VERSION 5.8 ;
BUSBITCHARS "[]" ;
DIVIDERCHAR "/" ;
UNITS
    DATABASE MICRONS 1000 ;
END UNITS

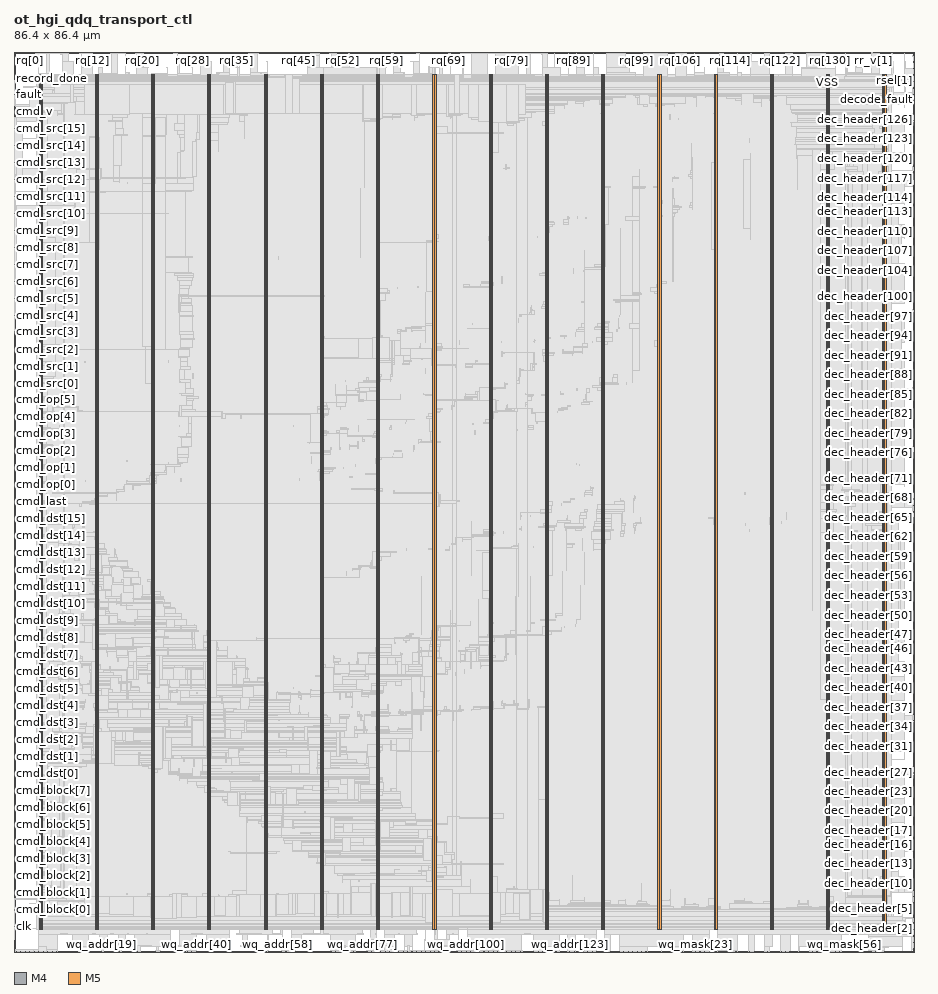
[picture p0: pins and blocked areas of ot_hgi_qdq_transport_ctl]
MACRO ot_hgi_qdq_transport_ctl
  FOREIGN ot_hgi_qdq_transport_ctl 0 0 ;
  CLASS BLOCK ;
  SIZE 86.4 BY 86.4 ;
  PIN beat_done
    DIRECTION OUTPUT ;
    USE SIGNAL ;
    PORT
      LAYER M4 ;
        RECT  0 0.816 0.084 0.84 ;
    END
    PORT
      LAYER M4 ;
        RECT  0.06 0.816 0.137 1.128 ;
    END
  END beat_done
  PIN clk
    DIRECTION INPUT ;
    USE SIGNAL ;
    PORT
      LAYER M4 ;
        RECT  0 2.448 0.084 2.472 ;
    END
    PORT
      LAYER M4 ;
        RECT  0.06 2.448 0.227 2.472 ;
    END
  END clk
  PIN cmd_block[0]
    DIRECTION INPUT ;
    USE SIGNAL ;
    PORT
      LAYER M4 ;
        RECT  0 4.08 0.084 4.104 ;
    END
    PORT
      LAYER M4 ;
        RECT  0.06 4.08 0.061 4.104 ;
    END
    PORT
      LAYER M4 ;
        RECT  0.061 3.984 0.173 4.104 ;
    END
  END cmd_block[0]
  PIN cmd_block[1]
    DIRECTION INPUT ;
    USE SIGNAL ;
    PORT
      LAYER M4 ;
        RECT  0 5.712 0.084 5.736 ;
    END
    PORT
      LAYER M4 ;
        RECT  0.06 5.712 2.408 5.736 ;
    END
  END cmd_block[1]
  PIN cmd_block[2]
    DIRECTION INPUT ;
    USE SIGNAL ;
    PORT
      LAYER M4 ;
        RECT  0 7.344 0.084 7.368 ;
    END
    PORT
      LAYER M4 ;
        RECT  0.06 7.344 2.408 7.368 ;
    END
  END cmd_block[2]
  PIN cmd_block[3]
    DIRECTION INPUT ;
    USE SIGNAL ;
    PORT
      LAYER M4 ;
        RECT  0 8.976 0.084 9 ;
    END
    PORT
      LAYER M4 ;
        RECT  0.06 8.976 2.408 9 ;
    END
  END cmd_block[3]
  PIN cmd_block[4]
    DIRECTION INPUT ;
    USE SIGNAL ;
    PORT
      LAYER M4 ;
        RECT  0 10.608 0.084 10.632 ;
    END
    PORT
      LAYER M4 ;
        RECT  0.06 10.608 2.408 10.632 ;
    END
  END cmd_block[4]
  PIN cmd_block[5]
    DIRECTION INPUT ;
    USE SIGNAL ;
    PORT
      LAYER M4 ;
        RECT  0 12.192 0.084 12.216 ;
    END
    PORT
      LAYER M4 ;
        RECT  0.06 12.192 2.408 12.216 ;
    END
  END cmd_block[5]
  PIN cmd_block[6]
    DIRECTION INPUT ;
    USE SIGNAL ;
    PORT
      LAYER M4 ;
        RECT  0 13.824 0.084 13.848 ;
    END
    PORT
      LAYER M4 ;
        RECT  0.06 13.824 2.408 13.848 ;
    END
  END cmd_block[6]
  PIN cmd_block[7]
    DIRECTION INPUT ;
    USE SIGNAL ;
    PORT
      LAYER M4 ;
        RECT  0 15.456 0.084 15.48 ;
    END
    PORT
      LAYER M4 ;
        RECT  0.06 15.456 2.408 15.48 ;
    END
  END cmd_block[7]
  PIN cmd_dst[0]
    DIRECTION INPUT ;
    USE SIGNAL ;
    PORT
      LAYER M4 ;
        RECT  0 17.088 0.084 17.112 ;
    END
    PORT
      LAYER M4 ;
        RECT  0.06 17.088 0.137 17.112 ;
    END
  END cmd_dst[0]
  PIN cmd_dst[10]
    DIRECTION INPUT ;
    USE SIGNAL ;
    PORT
      LAYER M4 ;
        RECT  0 33.408 0.084 33.432 ;
    END
    PORT
      LAYER M4 ;
        RECT  0.06 33.408 2.408 33.432 ;
    END
  END cmd_dst[10]
  PIN cmd_dst[11]
    DIRECTION INPUT ;
    USE SIGNAL ;
    PORT
      LAYER M4 ;
        RECT  0 35.04 0.084 35.064 ;
    END
    PORT
      LAYER M4 ;
        RECT  0.06 35.04 2.408 35.064 ;
    END
  END cmd_dst[11]
  PIN cmd_dst[12]
    DIRECTION INPUT ;
    USE SIGNAL ;
    PORT
      LAYER M4 ;
        RECT  0 36.672 0.084 36.696 ;
    END
    PORT
      LAYER M4 ;
        RECT  0.06 36.672 2.408 36.696 ;
    END
  END cmd_dst[12]
  PIN cmd_dst[13]
    DIRECTION INPUT ;
    USE SIGNAL ;
    PORT
      LAYER M4 ;
        RECT  0 38.304 0.084 38.328 ;
    END
    PORT
      LAYER M4 ;
        RECT  0.06 38.304 0.137 38.328 ;
    END
  END cmd_dst[13]
  PIN cmd_dst[14]
    DIRECTION INPUT ;
    USE SIGNAL ;
    PORT
      LAYER M4 ;
        RECT  0 39.936 0.084 39.96 ;
    END
    PORT
      LAYER M4 ;
        RECT  0.06 39.936 0.137 39.96 ;
    END
  END cmd_dst[14]
  PIN cmd_dst[15]
    DIRECTION INPUT ;
    USE SIGNAL ;
    PORT
      LAYER M4 ;
        RECT  0 41.568 0.084 41.592 ;
    END
    PORT
      LAYER M4 ;
        RECT  0.06 41.568 2.408 41.592 ;
    END
  END cmd_dst[15]
  PIN cmd_dst[1]
    DIRECTION INPUT ;
    USE SIGNAL ;
    PORT
      LAYER M4 ;
        RECT  0 18.72 0.084 18.744 ;
    END
    PORT
      LAYER M4 ;
        RECT  0.06 18.72 2.408 18.744 ;
    END
  END cmd_dst[1]
  PIN cmd_dst[2]
    DIRECTION INPUT ;
    USE SIGNAL ;
    PORT
      LAYER M4 ;
        RECT  0 20.352 0.084 20.376 ;
    END
    PORT
      LAYER M4 ;
        RECT  0.06 20.352 2.365 20.376 ;
    END
  END cmd_dst[2]
  PIN cmd_dst[3]
    DIRECTION INPUT ;
    USE SIGNAL ;
    PORT
      LAYER M4 ;
        RECT  0 21.984 0.084 22.008 ;
    END
    PORT
      LAYER M4 ;
        RECT  0.06 21.984 2.408 22.008 ;
    END
  END cmd_dst[3]
  PIN cmd_dst[4]
    DIRECTION INPUT ;
    USE SIGNAL ;
    PORT
      LAYER M4 ;
        RECT  0 23.616 0.084 23.64 ;
    END
    PORT
      LAYER M4 ;
        RECT  0.06 23.616 2.408 23.64 ;
    END
  END cmd_dst[4]
  PIN cmd_dst[5]
    DIRECTION INPUT ;
    USE SIGNAL ;
    PORT
      LAYER M4 ;
        RECT  0 25.248 0.084 25.272 ;
    END
    PORT
      LAYER M4 ;
        RECT  0.06 25.248 2.408 25.272 ;
    END
  END cmd_dst[5]
  PIN cmd_dst[6]
    DIRECTION INPUT ;
    USE SIGNAL ;
    PORT
      LAYER M4 ;
        RECT  0 26.88 0.084 26.904 ;
    END
    PORT
      LAYER M4 ;
        RECT  0.06 26.88 2.408 26.904 ;
    END
  END cmd_dst[6]
  PIN cmd_dst[7]
    DIRECTION INPUT ;
    USE SIGNAL ;
    PORT
      LAYER M4 ;
        RECT  0 28.512 0.084 28.536 ;
    END
    PORT
      LAYER M4 ;
        RECT  0.06 28.512 0.137 28.536 ;
    END
  END cmd_dst[7]
  PIN cmd_dst[8]
    DIRECTION INPUT ;
    USE SIGNAL ;
    PORT
      LAYER M4 ;
        RECT  0 30.144 0.084 30.168 ;
    END
    PORT
      LAYER M4 ;
        RECT  0.06 30.144 2.408 30.168 ;
    END
  END cmd_dst[8]
  PIN cmd_dst[9]
    DIRECTION INPUT ;
    USE SIGNAL ;
    PORT
      LAYER M4 ;
        RECT  0 31.776 0.084 31.8 ;
    END
    PORT
      LAYER M4 ;
        RECT  0.06 31.776 2.408 31.8 ;
    END
  END cmd_dst[9]
  PIN cmd_last
    DIRECTION INPUT ;
    USE SIGNAL ;
    PORT
      LAYER M4 ;
        RECT  0 43.2 0.084 43.224 ;
    END
    PORT
      LAYER M4 ;
        RECT  0.06 43.2 0.181 43.224 ;
    END
  END cmd_last
  PIN cmd_op[0]
    DIRECTION INPUT ;
    USE SIGNAL ;
    PORT
      LAYER M4 ;
        RECT  0 44.832 0.084 44.856 ;
    END
    PORT
      LAYER M4 ;
        RECT  0.06 44.832 0.133 44.856 ;
    END
  END cmd_op[0]
  PIN cmd_op[1]
    DIRECTION INPUT ;
    USE SIGNAL ;
    PORT
      LAYER M4 ;
        RECT  0 46.464 0.084 46.488 ;
    END
    PORT
      LAYER M4 ;
        RECT  0.06 46.464 0.133 46.488 ;
    END
  END cmd_op[1]
  PIN cmd_op[2]
    DIRECTION INPUT ;
    USE SIGNAL ;
    PORT
      LAYER M4 ;
        RECT  0 48.096 0.084 48.12 ;
    END
    PORT
      LAYER M4 ;
        RECT  0.06 48.096 2.408 48.12 ;
    END
  END cmd_op[2]
  PIN cmd_op[3]
    DIRECTION INPUT ;
    USE SIGNAL ;
    PORT
      LAYER M4 ;
        RECT  0 49.728 0.084 49.752 ;
    END
    PORT
      LAYER M4 ;
        RECT  0.06 49.728 2.408 49.752 ;
    END
  END cmd_op[3]
  PIN cmd_op[4]
    DIRECTION INPUT ;
    USE SIGNAL ;
    PORT
      LAYER M4 ;
        RECT  0 51.36 0.084 51.384 ;
    END
    PORT
      LAYER M4 ;
        RECT  0.06 51.36 2.408 51.384 ;
    END
  END cmd_op[4]
  PIN cmd_op[5]
    DIRECTION INPUT ;
    USE SIGNAL ;
    PORT
      LAYER M4 ;
        RECT  0 52.992 0.084 53.016 ;
    END
    PORT
      LAYER M4 ;
        RECT  0.06 52.992 2.408 53.016 ;
    END
  END cmd_op[5]
  PIN cmd_src[0]
    DIRECTION INPUT ;
    USE SIGNAL ;
    PORT
      LAYER M4 ;
        RECT  0 54.576 0.084 54.6 ;
    END
    PORT
      LAYER M4 ;
        RECT  0.06 54.576 2.408 54.6 ;
    END
  END cmd_src[0]
  PIN cmd_src[10]
    DIRECTION INPUT ;
    USE SIGNAL ;
    PORT
      LAYER M4 ;
        RECT  0 70.896 0.084 70.92 ;
    END
    PORT
      LAYER M4 ;
        RECT  0.06 70.896 0.097 70.92 ;
    END
  END cmd_src[10]
  PIN cmd_src[11]
    DIRECTION INPUT ;
    USE SIGNAL ;
    PORT
      LAYER M4 ;
        RECT  0 72.528 0.084 72.552 ;
    END
    PORT
      LAYER M4 ;
        RECT  0.06 72.528 0.133 72.552 ;
    END
  END cmd_src[11]
  PIN cmd_src[12]
    DIRECTION INPUT ;
    USE SIGNAL ;
    PORT
      LAYER M4 ;
        RECT  0 74.16 0.084 74.184 ;
    END
    PORT
      LAYER M4 ;
        RECT  0.06 74.16 0.181 74.184 ;
    END
  END cmd_src[12]
  PIN cmd_src[13]
    DIRECTION INPUT ;
    USE SIGNAL ;
    PORT
      LAYER M4 ;
        RECT  0 75.792 0.084 75.816 ;
    END
    PORT
      LAYER M4 ;
        RECT  0.06 75.792 0.229 75.816 ;
    END
  END cmd_src[13]
  PIN cmd_src[14]
    DIRECTION INPUT ;
    USE SIGNAL ;
    PORT
      LAYER M4 ;
        RECT  0 77.424 0.084 77.448 ;
    END
    PORT
      LAYER M4 ;
        RECT  0.06 77.424 0.137 77.448 ;
    END
  END cmd_src[14]
  PIN cmd_src[15]
    DIRECTION INPUT ;
    USE SIGNAL ;
    PORT
      LAYER M4 ;
        RECT  0 79.056 0.084 79.08 ;
    END
    PORT
      LAYER M4 ;
        RECT  0.06 79.056 0.137 79.08 ;
    END
  END cmd_src[15]
  PIN cmd_src[1]
    DIRECTION INPUT ;
    USE SIGNAL ;
    PORT
      LAYER M4 ;
        RECT  0 56.208 0.084 56.232 ;
    END
    PORT
      LAYER M4 ;
        RECT  0.06 56.208 0.097 56.232 ;
    END
  END cmd_src[1]
  PIN cmd_src[2]
    DIRECTION INPUT ;
    USE SIGNAL ;
    PORT
      LAYER M4 ;
        RECT  0 57.84 0.084 57.864 ;
    END
    PORT
      LAYER M4 ;
        RECT  0.06 57.84 2.408 57.864 ;
    END
  END cmd_src[2]
  PIN cmd_src[3]
    DIRECTION INPUT ;
    USE SIGNAL ;
    PORT
      LAYER M4 ;
        RECT  0 59.472 0.084 59.496 ;
    END
    PORT
      LAYER M4 ;
        RECT  0.06 59.472 0.061 59.496 ;
    END
    PORT
      LAYER M4 ;
        RECT  0.061 59.472 0.173 59.592 ;
    END
  END cmd_src[3]
  PIN cmd_src[4]
    DIRECTION INPUT ;
    USE SIGNAL ;
    PORT
      LAYER M4 ;
        RECT  0 61.104 0.084 61.128 ;
    END
    PORT
      LAYER M4 ;
        RECT  0.06 61.104 0.173 61.128 ;
    END
  END cmd_src[4]
  PIN cmd_src[5]
    DIRECTION INPUT ;
    USE SIGNAL ;
    PORT
      LAYER M4 ;
        RECT  0 62.736 0.084 62.76 ;
    END
    PORT
      LAYER M4 ;
        RECT  0.06 62.736 0.179 62.76 ;
    END
  END cmd_src[5]
  PIN cmd_src[6]
    DIRECTION INPUT ;
    USE SIGNAL ;
    PORT
      LAYER M4 ;
        RECT  0 64.368 0.084 64.392 ;
    END
    PORT
      LAYER M4 ;
        RECT  0.06 64.368 0.137 64.392 ;
    END
  END cmd_src[6]
  PIN cmd_src[7]
    DIRECTION INPUT ;
    USE SIGNAL ;
    PORT
      LAYER M4 ;
        RECT  0 66 0.084 66.024 ;
    END
    PORT
      LAYER M4 ;
        RECT  0.06 66 0.209 66.024 ;
    END
  END cmd_src[7]
  PIN cmd_src[8]
    DIRECTION INPUT ;
    USE SIGNAL ;
    PORT
      LAYER M4 ;
        RECT  0 67.632 0.084 67.656 ;
    END
    PORT
      LAYER M4 ;
        RECT  0.06 67.632 0.227 67.656 ;
    END
  END cmd_src[8]
  PIN cmd_src[9]
    DIRECTION INPUT ;
    USE SIGNAL ;
    PORT
      LAYER M4 ;
        RECT  0 69.264 0.084 69.288 ;
    END
    PORT
      LAYER M4 ;
        RECT  0.06 69.264 0.275 69.288 ;
    END
  END cmd_src[9]
  PIN cmd_v
    DIRECTION INPUT ;
    USE SIGNAL ;
    PORT
      LAYER M4 ;
        RECT  0 80.688 0.084 80.712 ;
    END
    PORT
      LAYER M4 ;
        RECT  0.06 80.688 1.477 80.712 ;
    END
  END cmd_v
  PIN dec_header[0]
    DIRECTION OUTPUT ;
    USE SIGNAL ;
    PORT
      LAYER M4 ;
        RECT  86.316 0.288 86.4 0.312 ;
    END
  END dec_header[0]
  PIN dec_header[100]
    DIRECTION OUTPUT ;
    USE SIGNAL ;
    PORT
      LAYER M4 ;
        RECT  86.316 62.928 86.4 62.952 ;
    END
  END dec_header[100]
  PIN dec_header[101]
    DIRECTION OUTPUT ;
    USE SIGNAL ;
    PORT
      LAYER M4 ;
        RECT  86.316 63.552 86.4 63.576 ;
    END
  END dec_header[101]
  PIN dec_header[102]
    DIRECTION OUTPUT ;
    USE SIGNAL ;
    PORT
      LAYER M4 ;
        RECT  86.316 64.176 86.4 64.2 ;
    END
  END dec_header[102]
  PIN dec_header[103]
    DIRECTION OUTPUT ;
    USE SIGNAL ;
    PORT
      LAYER M4 ;
        RECT  86.316 64.8 86.4 64.824 ;
    END
  END dec_header[103]
  PIN dec_header[104]
    DIRECTION OUTPUT ;
    USE SIGNAL ;
    PORT
      LAYER M4 ;
        RECT  86.316 65.424 86.4 65.448 ;
    END
  END dec_header[104]
  PIN dec_header[105]
    DIRECTION OUTPUT ;
    USE SIGNAL ;
    PORT
      LAYER M4 ;
        RECT  86.316 66.048 86.4 66.072 ;
    END
  END dec_header[105]
  PIN dec_header[106]
    DIRECTION OUTPUT ;
    USE SIGNAL ;
    PORT
      LAYER M4 ;
        RECT  86.316 66.672 86.4 66.696 ;
    END
  END dec_header[106]
  PIN dec_header[107]
    DIRECTION OUTPUT ;
    USE SIGNAL ;
    PORT
      LAYER M4 ;
        RECT  86.316 67.296 86.4 67.32 ;
    END
  END dec_header[107]
  PIN dec_header[108]
    DIRECTION OUTPUT ;
    USE SIGNAL ;
    PORT
      LAYER M4 ;
        RECT  86.316 67.92 86.4 67.944 ;
    END
  END dec_header[108]
  PIN dec_header[109]
    DIRECTION OUTPUT ;
    USE SIGNAL ;
    PORT
      LAYER M4 ;
        RECT  86.316 68.544 86.4 68.568 ;
    END
  END dec_header[109]
  PIN dec_header[10]
    DIRECTION OUTPUT ;
    USE SIGNAL ;
    PORT
      LAYER M4 ;
        RECT  86.316 6.576 86.4 6.6 ;
    END
  END dec_header[10]
  PIN dec_header[110]
    DIRECTION OUTPUT ;
    USE SIGNAL ;
    PORT
      LAYER M4 ;
        RECT  86.316 69.168 86.4 69.192 ;
    END
  END dec_header[110]
  PIN dec_header[111]
    DIRECTION OUTPUT ;
    USE SIGNAL ;
    PORT
      LAYER M4 ;
        RECT  86.316 69.792 86.4 69.816 ;
    END
  END dec_header[111]
  PIN dec_header[112]
    DIRECTION OUTPUT ;
    USE SIGNAL ;
    PORT
      LAYER M4 ;
        RECT  86.316 70.416 86.4 70.44 ;
    END
  END dec_header[112]
  PIN dec_header[113]
    DIRECTION OUTPUT ;
    USE SIGNAL ;
    PORT
      LAYER M4 ;
        RECT  86.316 71.04 86.4 71.064 ;
    END
  END dec_header[113]
  PIN dec_header[114]
    DIRECTION OUTPUT ;
    USE SIGNAL ;
    PORT
      LAYER M4 ;
        RECT  86.316 71.664 86.4 71.688 ;
    END
  END dec_header[114]
  PIN dec_header[115]
    DIRECTION OUTPUT ;
    USE SIGNAL ;
    PORT
      LAYER M4 ;
        RECT  86.316 72.288 86.4 72.312 ;
    END
  END dec_header[115]
  PIN dec_header[116]
    DIRECTION OUTPUT ;
    USE SIGNAL ;
    PORT
      LAYER M4 ;
        RECT  86.316 72.912 86.4 72.936 ;
    END
  END dec_header[116]
  PIN dec_header[117]
    DIRECTION OUTPUT ;
    USE SIGNAL ;
    PORT
      LAYER M4 ;
        RECT  86.316 73.536 86.4 73.56 ;
    END
  END dec_header[117]
  PIN dec_header[118]
    DIRECTION OUTPUT ;
    USE SIGNAL ;
    PORT
      LAYER M4 ;
        RECT  86.316 74.16 86.4 74.184 ;
    END
  END dec_header[118]
  PIN dec_header[119]
    DIRECTION OUTPUT ;
    USE SIGNAL ;
    PORT
      LAYER M4 ;
        RECT  86.316 74.784 86.4 74.808 ;
    END
  END dec_header[119]
  PIN dec_header[11]
    DIRECTION OUTPUT ;
    USE SIGNAL ;
    PORT
      LAYER M4 ;
        RECT  86.316 7.2 86.4 7.224 ;
    END
  END dec_header[11]
  PIN dec_header[120]
    DIRECTION OUTPUT ;
    USE SIGNAL ;
    PORT
      LAYER M4 ;
        RECT  86.316 75.408 86.4 75.432 ;
    END
  END dec_header[120]
  PIN dec_header[121]
    DIRECTION OUTPUT ;
    USE SIGNAL ;
    PORT
      LAYER M4 ;
        RECT  86.316 76.08 86.4 76.104 ;
    END
  END dec_header[121]
  PIN dec_header[122]
    DIRECTION OUTPUT ;
    USE SIGNAL ;
    PORT
      LAYER M4 ;
        RECT  86.316 76.704 86.4 76.728 ;
    END
  END dec_header[122]
  PIN dec_header[123]
    DIRECTION OUTPUT ;
    USE SIGNAL ;
    PORT
      LAYER M4 ;
        RECT  86.316 77.328 86.4 77.352 ;
    END
  END dec_header[123]
  PIN dec_header[124]
    DIRECTION OUTPUT ;
    USE SIGNAL ;
    PORT
      LAYER M4 ;
        RECT  86.316 77.952 86.4 77.976 ;
    END
  END dec_header[124]
  PIN dec_header[125]
    DIRECTION OUTPUT ;
    USE SIGNAL ;
    PORT
      LAYER M4 ;
        RECT  86.316 78.576 86.4 78.6 ;
    END
  END dec_header[125]
  PIN dec_header[126]
    DIRECTION OUTPUT ;
    USE SIGNAL ;
    PORT
      LAYER M4 ;
        RECT  86.316 79.2 86.4 79.224 ;
    END
  END dec_header[126]
  PIN dec_header[127]
    DIRECTION OUTPUT ;
    USE SIGNAL ;
    PORT
      LAYER M4 ;
        RECT  86.316 79.824 86.4 79.848 ;
    END
  END dec_header[127]
  PIN dec_header[12]
    DIRECTION OUTPUT ;
    USE SIGNAL ;
    PORT
      LAYER M4 ;
        RECT  86.316 7.824 86.4 7.848 ;
    END
  END dec_header[12]
  PIN dec_header[13]
    DIRECTION OUTPUT ;
    USE SIGNAL ;
    PORT
      LAYER M4 ;
        RECT  86.316 8.448 86.4 8.472 ;
    END
  END dec_header[13]
  PIN dec_header[14]
    DIRECTION OUTPUT ;
    USE SIGNAL ;
    PORT
      LAYER M4 ;
        RECT  86.316 9.072 86.4 9.096 ;
    END
  END dec_header[14]
  PIN dec_header[15]
    DIRECTION OUTPUT ;
    USE SIGNAL ;
    PORT
      LAYER M4 ;
        RECT  86.316 9.696 86.4 9.72 ;
    END
  END dec_header[15]
  PIN dec_header[16]
    DIRECTION OUTPUT ;
    USE SIGNAL ;
    PORT
      LAYER M4 ;
        RECT  86.316 10.32 86.4 10.344 ;
    END
  END dec_header[16]
  PIN dec_header[17]
    DIRECTION OUTPUT ;
    USE SIGNAL ;
    PORT
      LAYER M4 ;
        RECT  86.316 10.944 86.4 10.968 ;
    END
  END dec_header[17]
  PIN dec_header[18]
    DIRECTION OUTPUT ;
    USE SIGNAL ;
    PORT
      LAYER M4 ;
        RECT  86.316 11.568 86.4 11.592 ;
    END
  END dec_header[18]
  PIN dec_header[19]
    DIRECTION OUTPUT ;
    USE SIGNAL ;
    PORT
      LAYER M4 ;
        RECT  86.316 12.192 86.4 12.216 ;
    END
  END dec_header[19]
  PIN dec_header[1]
    DIRECTION OUTPUT ;
    USE SIGNAL ;
    PORT
      LAYER M4 ;
        RECT  86.316 0.912 86.4 0.936 ;
    END
  END dec_header[1]
  PIN dec_header[20]
    DIRECTION OUTPUT ;
    USE SIGNAL ;
    PORT
      LAYER M4 ;
        RECT  86.316 12.816 86.4 12.84 ;
    END
  END dec_header[20]
  PIN dec_header[21]
    DIRECTION OUTPUT ;
    USE SIGNAL ;
    PORT
      LAYER M4 ;
        RECT  86.316 13.44 86.4 13.464 ;
    END
  END dec_header[21]
  PIN dec_header[22]
    DIRECTION OUTPUT ;
    USE SIGNAL ;
    PORT
      LAYER M4 ;
        RECT  86.316 14.064 86.4 14.088 ;
    END
  END dec_header[22]
  PIN dec_header[23]
    DIRECTION OUTPUT ;
    USE SIGNAL ;
    PORT
      LAYER M4 ;
        RECT  86.316 14.688 86.4 14.712 ;
    END
  END dec_header[23]
  PIN dec_header[24]
    DIRECTION OUTPUT ;
    USE SIGNAL ;
    PORT
      LAYER M4 ;
        RECT  86.316 15.312 86.4 15.336 ;
    END
  END dec_header[24]
  PIN dec_header[25]
    DIRECTION OUTPUT ;
    USE SIGNAL ;
    PORT
      LAYER M4 ;
        RECT  86.316 15.936 86.4 15.96 ;
    END
  END dec_header[25]
  PIN dec_header[26]
    DIRECTION OUTPUT ;
    USE SIGNAL ;
    PORT
      LAYER M4 ;
        RECT  86.316 16.56 86.4 16.584 ;
    END
  END dec_header[26]
  PIN dec_header[27]
    DIRECTION OUTPUT ;
    USE SIGNAL ;
    PORT
      LAYER M4 ;
        RECT  86.316 17.184 86.4 17.208 ;
    END
  END dec_header[27]
  PIN dec_header[28]
    DIRECTION OUTPUT ;
    USE SIGNAL ;
    PORT
      LAYER M4 ;
        RECT  86.316 17.808 86.4 17.832 ;
    END
  END dec_header[28]
  PIN dec_header[29]
    DIRECTION OUTPUT ;
    USE SIGNAL ;
    PORT
      LAYER M4 ;
        RECT  86.316 18.48 86.4 18.504 ;
    END
  END dec_header[29]
  PIN dec_header[2]
    DIRECTION OUTPUT ;
    USE SIGNAL ;
    PORT
      LAYER M4 ;
        RECT  86.316 1.536 86.4 1.56 ;
    END
  END dec_header[2]
  PIN dec_header[30]
    DIRECTION OUTPUT ;
    USE SIGNAL ;
    PORT
      LAYER M4 ;
        RECT  86.316 19.104 86.4 19.128 ;
    END
  END dec_header[30]
  PIN dec_header[31]
    DIRECTION OUTPUT ;
    USE SIGNAL ;
    PORT
      LAYER M4 ;
        RECT  86.316 19.728 86.4 19.752 ;
    END
  END dec_header[31]
  PIN dec_header[32]
    DIRECTION OUTPUT ;
    USE SIGNAL ;
    PORT
      LAYER M4 ;
        RECT  86.316 20.352 86.4 20.376 ;
    END
  END dec_header[32]
  PIN dec_header[33]
    DIRECTION OUTPUT ;
    USE SIGNAL ;
    PORT
      LAYER M4 ;
        RECT  86.316 20.976 86.4 21 ;
    END
  END dec_header[33]
  PIN dec_header[34]
    DIRECTION OUTPUT ;
    USE SIGNAL ;
    PORT
      LAYER M4 ;
        RECT  86.316 21.6 86.4 21.624 ;
    END
  END dec_header[34]
  PIN dec_header[35]
    DIRECTION OUTPUT ;
    USE SIGNAL ;
    PORT
      LAYER M4 ;
        RECT  86.316 22.224 86.4 22.248 ;
    END
  END dec_header[35]
  PIN dec_header[36]
    DIRECTION OUTPUT ;
    USE SIGNAL ;
    PORT
      LAYER M4 ;
        RECT  86.316 22.848 86.4 22.872 ;
    END
  END dec_header[36]
  PIN dec_header[37]
    DIRECTION OUTPUT ;
    USE SIGNAL ;
    PORT
      LAYER M4 ;
        RECT  86.316 23.472 86.4 23.496 ;
    END
  END dec_header[37]
  PIN dec_header[38]
    DIRECTION OUTPUT ;
    USE SIGNAL ;
    PORT
      LAYER M4 ;
        RECT  86.316 24.096 86.4 24.12 ;
    END
  END dec_header[38]
  PIN dec_header[39]
    DIRECTION OUTPUT ;
    USE SIGNAL ;
    PORT
      LAYER M4 ;
        RECT  86.316 24.72 86.4 24.744 ;
    END
  END dec_header[39]
  PIN dec_header[3]
    DIRECTION OUTPUT ;
    USE SIGNAL ;
    PORT
      LAYER M4 ;
        RECT  86.316 2.16 86.4 2.184 ;
    END
  END dec_header[3]
  PIN dec_header[40]
    DIRECTION OUTPUT ;
    USE SIGNAL ;
    PORT
      LAYER M4 ;
        RECT  86.316 25.344 86.4 25.368 ;
    END
  END dec_header[40]
  PIN dec_header[41]
    DIRECTION OUTPUT ;
    USE SIGNAL ;
    PORT
      LAYER M4 ;
        RECT  86.316 25.968 86.4 25.992 ;
    END
  END dec_header[41]
  PIN dec_header[42]
    DIRECTION OUTPUT ;
    USE SIGNAL ;
    PORT
      LAYER M4 ;
        RECT  86.316 26.592 86.4 26.616 ;
    END
  END dec_header[42]
  PIN dec_header[43]
    DIRECTION OUTPUT ;
    USE SIGNAL ;
    PORT
      LAYER M4 ;
        RECT  86.316 27.216 86.4 27.24 ;
    END
  END dec_header[43]
  PIN dec_header[44]
    DIRECTION OUTPUT ;
    USE SIGNAL ;
    PORT
      LAYER M4 ;
        RECT  86.316 27.84 86.4 27.864 ;
    END
  END dec_header[44]
  PIN dec_header[45]
    DIRECTION OUTPUT ;
    USE SIGNAL ;
    PORT
      LAYER M4 ;
        RECT  86.316 28.464 86.4 28.488 ;
    END
  END dec_header[45]
  PIN dec_header[46]
    DIRECTION OUTPUT ;
    USE SIGNAL ;
    PORT
      LAYER M4 ;
        RECT  86.316 29.088 86.4 29.112 ;
    END
  END dec_header[46]
  PIN dec_header[47]
    DIRECTION OUTPUT ;
    USE SIGNAL ;
    PORT
      LAYER M4 ;
        RECT  86.316 29.712 86.4 29.736 ;
    END
  END dec_header[47]
  PIN dec_header[48]
    DIRECTION OUTPUT ;
    USE SIGNAL ;
    PORT
      LAYER M4 ;
        RECT  86.316 30.336 86.4 30.36 ;
    END
  END dec_header[48]
  PIN dec_header[49]
    DIRECTION OUTPUT ;
    USE SIGNAL ;
    PORT
      LAYER M4 ;
        RECT  86.316 30.96 86.4 30.984 ;
    END
  END dec_header[49]
  PIN dec_header[4]
    DIRECTION OUTPUT ;
    USE SIGNAL ;
    PORT
      LAYER M4 ;
        RECT  86.316 2.784 86.4 2.808 ;
    END
  END dec_header[4]
  PIN dec_header[50]
    DIRECTION OUTPUT ;
    USE SIGNAL ;
    PORT
      LAYER M4 ;
        RECT  86.316 31.584 86.4 31.608 ;
    END
  END dec_header[50]
  PIN dec_header[51]
    DIRECTION OUTPUT ;
    USE SIGNAL ;
    PORT
      LAYER M4 ;
        RECT  86.316 32.208 86.4 32.232 ;
    END
  END dec_header[51]
  PIN dec_header[52]
    DIRECTION OUTPUT ;
    USE SIGNAL ;
    PORT
      LAYER M4 ;
        RECT  86.316 32.88 86.4 32.904 ;
    END
  END dec_header[52]
  PIN dec_header[53]
    DIRECTION OUTPUT ;
    USE SIGNAL ;
    PORT
      LAYER M4 ;
        RECT  86.316 33.504 86.4 33.528 ;
    END
  END dec_header[53]
  PIN dec_header[54]
    DIRECTION OUTPUT ;
    USE SIGNAL ;
    PORT
      LAYER M4 ;
        RECT  86.316 34.128 86.4 34.152 ;
    END
  END dec_header[54]
  PIN dec_header[55]
    DIRECTION OUTPUT ;
    USE SIGNAL ;
    PORT
      LAYER M4 ;
        RECT  86.316 34.752 86.4 34.776 ;
    END
  END dec_header[55]
  PIN dec_header[56]
    DIRECTION OUTPUT ;
    USE SIGNAL ;
    PORT
      LAYER M4 ;
        RECT  86.316 35.376 86.4 35.4 ;
    END
  END dec_header[56]
  PIN dec_header[57]
    DIRECTION OUTPUT ;
    USE SIGNAL ;
    PORT
      LAYER M4 ;
        RECT  86.316 36 86.4 36.024 ;
    END
  END dec_header[57]
  PIN dec_header[58]
    DIRECTION OUTPUT ;
    USE SIGNAL ;
    PORT
      LAYER M4 ;
        RECT  86.316 36.624 86.4 36.648 ;
    END
  END dec_header[58]
  PIN dec_header[59]
    DIRECTION OUTPUT ;
    USE SIGNAL ;
    PORT
      LAYER M4 ;
        RECT  86.316 37.248 86.4 37.272 ;
    END
  END dec_header[59]
  PIN dec_header[5]
    DIRECTION OUTPUT ;
    USE SIGNAL ;
    PORT
      LAYER M4 ;
        RECT  86.316 3.408 86.4 3.432 ;
    END
  END dec_header[5]
  PIN dec_header[60]
    DIRECTION OUTPUT ;
    USE SIGNAL ;
    PORT
      LAYER M4 ;
        RECT  86.316 37.872 86.4 37.896 ;
    END
  END dec_header[60]
  PIN dec_header[61]
    DIRECTION OUTPUT ;
    USE SIGNAL ;
    PORT
      LAYER M4 ;
        RECT  86.316 38.496 86.4 38.52 ;
    END
  END dec_header[61]
  PIN dec_header[62]
    DIRECTION OUTPUT ;
    USE SIGNAL ;
    PORT
      LAYER M4 ;
        RECT  86.316 39.12 86.4 39.144 ;
    END
  END dec_header[62]
  PIN dec_header[63]
    DIRECTION OUTPUT ;
    USE SIGNAL ;
    PORT
      LAYER M4 ;
        RECT  86.316 39.744 86.4 39.768 ;
    END
  END dec_header[63]
  PIN dec_header[64]
    DIRECTION OUTPUT ;
    USE SIGNAL ;
    PORT
      LAYER M4 ;
        RECT  86.316 40.368 86.4 40.392 ;
    END
  END dec_header[64]
  PIN dec_header[65]
    DIRECTION OUTPUT ;
    USE SIGNAL ;
    PORT
      LAYER M4 ;
        RECT  86.316 40.992 86.4 41.016 ;
    END
  END dec_header[65]
  PIN dec_header[66]
    DIRECTION OUTPUT ;
    USE SIGNAL ;
    PORT
      LAYER M4 ;
        RECT  86.316 41.616 86.4 41.64 ;
    END
  END dec_header[66]
  PIN dec_header[67]
    DIRECTION OUTPUT ;
    USE SIGNAL ;
    PORT
      LAYER M4 ;
        RECT  86.316 42.24 86.4 42.264 ;
    END
  END dec_header[67]
  PIN dec_header[68]
    DIRECTION OUTPUT ;
    USE SIGNAL ;
    PORT
      LAYER M4 ;
        RECT  86.316 42.864 86.4 42.888 ;
    END
  END dec_header[68]
  PIN dec_header[69]
    DIRECTION OUTPUT ;
    USE SIGNAL ;
    PORT
      LAYER M4 ;
        RECT  86.316 43.488 86.4 43.512 ;
    END
  END dec_header[69]
  PIN dec_header[6]
    DIRECTION OUTPUT ;
    USE SIGNAL ;
    PORT
      LAYER M4 ;
        RECT  86.316 4.08 86.4 4.104 ;
    END
  END dec_header[6]
  PIN dec_header[70]
    DIRECTION OUTPUT ;
    USE SIGNAL ;
    PORT
      LAYER M4 ;
        RECT  86.316 44.112 86.4 44.136 ;
    END
  END dec_header[70]
  PIN dec_header[71]
    DIRECTION OUTPUT ;
    USE SIGNAL ;
    PORT
      LAYER M4 ;
        RECT  86.316 44.736 86.4 44.76 ;
    END
  END dec_header[71]
  PIN dec_header[72]
    DIRECTION OUTPUT ;
    USE SIGNAL ;
    PORT
      LAYER M4 ;
        RECT  86.316 45.36 86.4 45.384 ;
    END
  END dec_header[72]
  PIN dec_header[73]
    DIRECTION OUTPUT ;
    USE SIGNAL ;
    PORT
      LAYER M4 ;
        RECT  86.316 45.984 86.4 46.008 ;
    END
  END dec_header[73]
  PIN dec_header[74]
    DIRECTION OUTPUT ;
    USE SIGNAL ;
    PORT
      LAYER M4 ;
        RECT  86.316 46.608 86.4 46.632 ;
    END
  END dec_header[74]
  PIN dec_header[75]
    DIRECTION OUTPUT ;
    USE SIGNAL ;
    PORT
      LAYER M4 ;
        RECT  86.316 47.28 86.4 47.304 ;
    END
  END dec_header[75]
  PIN dec_header[76]
    DIRECTION OUTPUT ;
    USE SIGNAL ;
    PORT
      LAYER M4 ;
        RECT  86.316 47.904 86.4 47.928 ;
    END
  END dec_header[76]
  PIN dec_header[77]
    DIRECTION OUTPUT ;
    USE SIGNAL ;
    PORT
      LAYER M4 ;
        RECT  86.316 48.528 86.4 48.552 ;
    END
  END dec_header[77]
  PIN dec_header[78]
    DIRECTION OUTPUT ;
    USE SIGNAL ;
    PORT
      LAYER M4 ;
        RECT  86.316 49.152 86.4 49.176 ;
    END
  END dec_header[78]
  PIN dec_header[79]
    DIRECTION OUTPUT ;
    USE SIGNAL ;
    PORT
      LAYER M4 ;
        RECT  86.316 49.776 86.4 49.8 ;
    END
  END dec_header[79]
  PIN dec_header[7]
    DIRECTION OUTPUT ;
    USE SIGNAL ;
    PORT
      LAYER M4 ;
        RECT  86.316 4.704 86.4 4.728 ;
    END
  END dec_header[7]
  PIN dec_header[80]
    DIRECTION OUTPUT ;
    USE SIGNAL ;
    PORT
      LAYER M4 ;
        RECT  86.316 50.4 86.4 50.424 ;
    END
  END dec_header[80]
  PIN dec_header[81]
    DIRECTION OUTPUT ;
    USE SIGNAL ;
    PORT
      LAYER M4 ;
        RECT  86.316 51.024 86.4 51.048 ;
    END
  END dec_header[81]
  PIN dec_header[82]
    DIRECTION OUTPUT ;
    USE SIGNAL ;
    PORT
      LAYER M4 ;
        RECT  86.316 51.648 86.4 51.672 ;
    END
  END dec_header[82]
  PIN dec_header[83]
    DIRECTION OUTPUT ;
    USE SIGNAL ;
    PORT
      LAYER M4 ;
        RECT  86.316 52.272 86.4 52.296 ;
    END
  END dec_header[83]
  PIN dec_header[84]
    DIRECTION OUTPUT ;
    USE SIGNAL ;
    PORT
      LAYER M4 ;
        RECT  86.316 52.896 86.4 52.92 ;
    END
  END dec_header[84]
  PIN dec_header[85]
    DIRECTION OUTPUT ;
    USE SIGNAL ;
    PORT
      LAYER M4 ;
        RECT  86.316 53.52 86.4 53.544 ;
    END
  END dec_header[85]
  PIN dec_header[86]
    DIRECTION OUTPUT ;
    USE SIGNAL ;
    PORT
      LAYER M4 ;
        RECT  86.316 54.144 86.4 54.168 ;
    END
  END dec_header[86]
  PIN dec_header[87]
    DIRECTION OUTPUT ;
    USE SIGNAL ;
    PORT
      LAYER M4 ;
        RECT  86.316 54.768 86.4 54.792 ;
    END
  END dec_header[87]
  PIN dec_header[88]
    DIRECTION OUTPUT ;
    USE SIGNAL ;
    PORT
      LAYER M4 ;
        RECT  86.316 55.392 86.4 55.416 ;
    END
  END dec_header[88]
  PIN dec_header[89]
    DIRECTION OUTPUT ;
    USE SIGNAL ;
    PORT
      LAYER M4 ;
        RECT  86.316 56.016 86.4 56.04 ;
    END
  END dec_header[89]
  PIN dec_header[8]
    DIRECTION OUTPUT ;
    USE SIGNAL ;
    PORT
      LAYER M4 ;
        RECT  86.316 5.328 86.4 5.352 ;
    END
  END dec_header[8]
  PIN dec_header[90]
    DIRECTION OUTPUT ;
    USE SIGNAL ;
    PORT
      LAYER M4 ;
        RECT  86.316 56.64 86.4 56.664 ;
    END
  END dec_header[90]
  PIN dec_header[91]
    DIRECTION OUTPUT ;
    USE SIGNAL ;
    PORT
      LAYER M4 ;
        RECT  86.316 57.264 86.4 57.288 ;
    END
  END dec_header[91]
  PIN dec_header[92]
    DIRECTION OUTPUT ;
    USE SIGNAL ;
    PORT
      LAYER M4 ;
        RECT  86.316 57.888 86.4 57.912 ;
    END
  END dec_header[92]
  PIN dec_header[93]
    DIRECTION OUTPUT ;
    USE SIGNAL ;
    PORT
      LAYER M4 ;
        RECT  86.316 58.512 86.4 58.536 ;
    END
  END dec_header[93]
  PIN dec_header[94]
    DIRECTION OUTPUT ;
    USE SIGNAL ;
    PORT
      LAYER M4 ;
        RECT  86.316 59.136 86.4 59.16 ;
    END
  END dec_header[94]
  PIN dec_header[95]
    DIRECTION OUTPUT ;
    USE SIGNAL ;
    PORT
      LAYER M4 ;
        RECT  86.316 59.76 86.4 59.784 ;
    END
  END dec_header[95]
  PIN dec_header[96]
    DIRECTION OUTPUT ;
    USE SIGNAL ;
    PORT
      LAYER M4 ;
        RECT  86.316 60.384 86.4 60.408 ;
    END
  END dec_header[96]
  PIN dec_header[97]
    DIRECTION OUTPUT ;
    USE SIGNAL ;
    PORT
      LAYER M4 ;
        RECT  86.316 61.008 86.4 61.032 ;
    END
  END dec_header[97]
  PIN dec_header[98]
    DIRECTION OUTPUT ;
    USE SIGNAL ;
    PORT
      LAYER M4 ;
        RECT  86.316 61.68 86.4 61.704 ;
    END
  END dec_header[98]
  PIN dec_header[99]
    DIRECTION OUTPUT ;
    USE SIGNAL ;
    PORT
      LAYER M4 ;
        RECT  86.316 62.304 86.4 62.328 ;
    END
  END dec_header[99]
  PIN dec_header[9]
    DIRECTION OUTPUT ;
    USE SIGNAL ;
    PORT
      LAYER M4 ;
        RECT  86.316 5.952 86.4 5.976 ;
    END
  END dec_header[9]
  PIN dec_v
    DIRECTION OUTPUT ;
    USE SIGNAL ;
    PORT
      LAYER M4 ;
        RECT  86.316 80.448 86.4 80.472 ;
    END
  END dec_v
  PIN decode_fault
    DIRECTION INPUT ;
    USE SIGNAL ;
    PORT
      LAYER M4 ;
        RECT  86.316 81.072 86.4 81.096 ;
    END
  END decode_fault
  PIN fault
    DIRECTION OUTPUT ;
    USE SIGNAL ;
    PORT
      LAYER M4 ;
        RECT  0 82.32 0.084 82.344 ;
    END
    PORT
      LAYER M4 ;
        RECT  0.06 82.32 0.137 82.344 ;
    END
  END fault
  PIN qfault
    DIRECTION INPUT ;
    USE SIGNAL ;
    PORT
      LAYER M4 ;
        RECT  86.316 81.696 86.4 81.72 ;
    END
  END qfault
  PIN record_done
    DIRECTION OUTPUT ;
    USE SIGNAL ;
    PORT
      LAYER M4 ;
        RECT  0 83.952 0.084 83.976 ;
    END
    PORT
      LAYER M4 ;
        RECT  0.06 83.808 0.137 83.976 ;
    END
  END record_done
  PIN rq[0]
    DIRECTION OUTPUT ;
    USE SIGNAL ;
    PORT
      LAYER M5 ;
        RECT  0.288 86.316 0.312 86.4 ;
    END
  END rq[0]
  PIN rq[100]
    DIRECTION OUTPUT ;
    USE SIGNAL ;
    PORT
      LAYER M5 ;
        RECT  60.288 86.316 60.312 86.4 ;
    END
  END rq[100]
  PIN rq[101]
    DIRECTION OUTPUT ;
    USE SIGNAL ;
    PORT
      LAYER M5 ;
        RECT  60.912 86.316 60.936 86.4 ;
    END
  END rq[101]
  PIN rq[102]
    DIRECTION OUTPUT ;
    USE SIGNAL ;
    PORT
      LAYER M5 ;
        RECT  61.488 86.316 61.512 86.4 ;
    END
  END rq[102]
  PIN rq[103]
    DIRECTION OUTPUT ;
    USE SIGNAL ;
    PORT
      LAYER M5 ;
        RECT  62.112 86.316 62.136 86.4 ;
    END
  END rq[103]
  PIN rq[104]
    DIRECTION OUTPUT ;
    USE SIGNAL ;
    PORT
      LAYER M5 ;
        RECT  62.688 86.316 62.712 86.4 ;
    END
  END rq[104]
  PIN rq[105]
    DIRECTION OUTPUT ;
    USE SIGNAL ;
    PORT
      LAYER M5 ;
        RECT  63.312 86.316 63.336 86.4 ;
    END
  END rq[105]
  PIN rq[106]
    DIRECTION OUTPUT ;
    USE SIGNAL ;
    PORT
      LAYER M5 ;
        RECT  63.888 86.316 63.912 86.4 ;
    END
  END rq[106]
  PIN rq[107]
    DIRECTION OUTPUT ;
    USE SIGNAL ;
    PORT
      LAYER M5 ;
        RECT  64.512 86.316 64.536 86.4 ;
    END
  END rq[107]
  PIN rq[108]
    DIRECTION OUTPUT ;
    USE SIGNAL ;
    PORT
      LAYER M5 ;
        RECT  65.088 86.316 65.112 86.4 ;
    END
  END rq[108]
  PIN rq[109]
    DIRECTION OUTPUT ;
    USE SIGNAL ;
    PORT
      LAYER M5 ;
        RECT  65.712 86.316 65.736 86.4 ;
    END
  END rq[109]
  PIN rq[10]
    DIRECTION OUTPUT ;
    USE SIGNAL ;
    PORT
      LAYER M5 ;
        RECT  6.288 86.316 6.312 86.4 ;
    END
  END rq[10]
  PIN rq[110]
    DIRECTION OUTPUT ;
    USE SIGNAL ;
    PORT
      LAYER M5 ;
        RECT  66.288 86.316 66.312 86.4 ;
    END
  END rq[110]
  PIN rq[111]
    DIRECTION OUTPUT ;
    USE SIGNAL ;
    PORT
      LAYER M5 ;
        RECT  66.912 86.316 66.936 86.4 ;
    END
  END rq[111]
  PIN rq[112]
    DIRECTION OUTPUT ;
    USE SIGNAL ;
    PORT
      LAYER M5 ;
        RECT  67.488 86.316 67.512 86.4 ;
    END
  END rq[112]
  PIN rq[113]
    DIRECTION OUTPUT ;
    USE SIGNAL ;
    PORT
      LAYER M5 ;
        RECT  68.112 86.316 68.136 86.4 ;
    END
  END rq[113]
  PIN rq[114]
    DIRECTION OUTPUT ;
    USE SIGNAL ;
    PORT
      LAYER M5 ;
        RECT  68.688 86.316 68.712 86.4 ;
    END
  END rq[114]
  PIN rq[115]
    DIRECTION OUTPUT ;
    USE SIGNAL ;
    PORT
      LAYER M5 ;
        RECT  69.312 86.316 69.336 86.4 ;
    END
  END rq[115]
  PIN rq[116]
    DIRECTION OUTPUT ;
    USE SIGNAL ;
    PORT
      LAYER M5 ;
        RECT  69.888 86.316 69.912 86.4 ;
    END
  END rq[116]
  PIN rq[117]
    DIRECTION OUTPUT ;
    USE SIGNAL ;
    PORT
      LAYER M5 ;
        RECT  70.512 86.316 70.536 86.4 ;
    END
  END rq[117]
  PIN rq[118]
    DIRECTION OUTPUT ;
    USE SIGNAL ;
    PORT
      LAYER M5 ;
        RECT  71.088 86.316 71.112 86.4 ;
    END
  END rq[118]
  PIN rq[119]
    DIRECTION OUTPUT ;
    USE SIGNAL ;
    PORT
      LAYER M5 ;
        RECT  71.712 86.316 71.736 86.4 ;
    END
  END rq[119]
  PIN rq[11]
    DIRECTION OUTPUT ;
    USE SIGNAL ;
    PORT
      LAYER M5 ;
        RECT  6.912 86.316 6.936 86.4 ;
    END
  END rq[11]
  PIN rq[120]
    DIRECTION OUTPUT ;
    USE SIGNAL ;
    PORT
      LAYER M5 ;
        RECT  72.288 86.316 72.312 86.4 ;
    END
  END rq[120]
  PIN rq[121]
    DIRECTION OUTPUT ;
    USE SIGNAL ;
    PORT
      LAYER M5 ;
        RECT  72.912 86.316 72.936 86.4 ;
    END
  END rq[121]
  PIN rq[122]
    DIRECTION OUTPUT ;
    USE SIGNAL ;
    PORT
      LAYER M5 ;
        RECT  73.488 86.316 73.512 86.4 ;
    END
  END rq[122]
  PIN rq[123]
    DIRECTION OUTPUT ;
    USE SIGNAL ;
    PORT
      LAYER M5 ;
        RECT  74.112 86.316 74.136 86.4 ;
    END
  END rq[123]
  PIN rq[124]
    DIRECTION OUTPUT ;
    USE SIGNAL ;
    PORT
      LAYER M5 ;
        RECT  74.688 86.316 74.712 86.4 ;
    END
  END rq[124]
  PIN rq[125]
    DIRECTION OUTPUT ;
    USE SIGNAL ;
    PORT
      LAYER M5 ;
        RECT  75.312 86.316 75.336 86.4 ;
    END
  END rq[125]
  PIN rq[126]
    DIRECTION OUTPUT ;
    USE SIGNAL ;
    PORT
      LAYER M5 ;
        RECT  75.888 86.316 75.912 86.4 ;
    END
  END rq[126]
  PIN rq[127]
    DIRECTION OUTPUT ;
    USE SIGNAL ;
    PORT
      LAYER M5 ;
        RECT  76.512 86.316 76.536 86.4 ;
    END
  END rq[127]
  PIN rq[128]
    DIRECTION OUTPUT ;
    USE SIGNAL ;
    PORT
      LAYER M5 ;
        RECT  77.088 86.316 77.112 86.4 ;
    END
  END rq[128]
  PIN rq[129]
    DIRECTION OUTPUT ;
    USE SIGNAL ;
    PORT
      LAYER M5 ;
        RECT  77.712 86.316 77.736 86.4 ;
    END
  END rq[129]
  PIN rq[12]
    DIRECTION OUTPUT ;
    USE SIGNAL ;
    PORT
      LAYER M5 ;
        RECT  7.488 86.316 7.512 86.4 ;
    END
  END rq[12]
  PIN rq[130]
    DIRECTION OUTPUT ;
    USE SIGNAL ;
    PORT
      LAYER M5 ;
        RECT  78.288 86.316 78.312 86.4 ;
    END
  END rq[130]
  PIN rq[131]
    DIRECTION OUTPUT ;
    USE SIGNAL ;
    PORT
      LAYER M5 ;
        RECT  78.912 86.316 78.936 86.4 ;
    END
  END rq[131]
  PIN rq[132]
    DIRECTION OUTPUT ;
    USE SIGNAL ;
    PORT
      LAYER M5 ;
        RECT  79.488 86.316 79.512 86.4 ;
    END
  END rq[132]
  PIN rq[133]
    DIRECTION OUTPUT ;
    USE SIGNAL ;
    PORT
      LAYER M5 ;
        RECT  80.112 86.316 80.136 86.4 ;
    END
  END rq[133]
  PIN rq[134]
    DIRECTION OUTPUT ;
    USE SIGNAL ;
    PORT
      LAYER M5 ;
        RECT  80.688 86.316 80.712 86.4 ;
    END
  END rq[134]
  PIN rq[135]
    DIRECTION OUTPUT ;
    USE SIGNAL ;
    PORT
      LAYER M5 ;
        RECT  81.312 86.316 81.336 86.4 ;
    END
  END rq[135]
  PIN rq[13]
    DIRECTION OUTPUT ;
    USE SIGNAL ;
    PORT
      LAYER M5 ;
        RECT  8.112 86.316 8.136 86.4 ;
    END
  END rq[13]
  PIN rq[14]
    DIRECTION OUTPUT ;
    USE SIGNAL ;
    PORT
      LAYER M5 ;
        RECT  8.688 86.316 8.712 86.4 ;
    END
  END rq[14]
  PIN rq[15]
    DIRECTION OUTPUT ;
    USE SIGNAL ;
    PORT
      LAYER M5 ;
        RECT  9.312 86.316 9.336 86.4 ;
    END
  END rq[15]
  PIN rq[16]
    DIRECTION OUTPUT ;
    USE SIGNAL ;
    PORT
      LAYER M5 ;
        RECT  9.888 86.316 9.912 86.4 ;
    END
  END rq[16]
  PIN rq[17]
    DIRECTION OUTPUT ;
    USE SIGNAL ;
    PORT
      LAYER M5 ;
        RECT  10.512 86.316 10.536 86.4 ;
    END
  END rq[17]
  PIN rq[18]
    DIRECTION OUTPUT ;
    USE SIGNAL ;
    PORT
      LAYER M5 ;
        RECT  11.088 86.316 11.112 86.4 ;
    END
  END rq[18]
  PIN rq[19]
    DIRECTION OUTPUT ;
    USE SIGNAL ;
    PORT
      LAYER M5 ;
        RECT  11.712 86.316 11.736 86.4 ;
    END
  END rq[19]
  PIN rq[1]
    DIRECTION OUTPUT ;
    USE SIGNAL ;
    PORT
      LAYER M5 ;
        RECT  0.912 86.316 0.936 86.4 ;
    END
  END rq[1]
  PIN rq[20]
    DIRECTION OUTPUT ;
    USE SIGNAL ;
    PORT
      LAYER M5 ;
        RECT  12.288 86.316 12.312 86.4 ;
    END
  END rq[20]
  PIN rq[21]
    DIRECTION OUTPUT ;
    USE SIGNAL ;
    PORT
      LAYER M5 ;
        RECT  12.912 86.316 12.936 86.4 ;
    END
  END rq[21]
  PIN rq[22]
    DIRECTION OUTPUT ;
    USE SIGNAL ;
    PORT
      LAYER M5 ;
        RECT  13.488 86.316 13.512 86.4 ;
    END
  END rq[22]
  PIN rq[23]
    DIRECTION OUTPUT ;
    USE SIGNAL ;
    PORT
      LAYER M5 ;
        RECT  14.112 86.316 14.136 86.4 ;
    END
  END rq[23]
  PIN rq[24]
    DIRECTION OUTPUT ;
    USE SIGNAL ;
    PORT
      LAYER M5 ;
        RECT  14.688 86.316 14.712 86.4 ;
    END
  END rq[24]
  PIN rq[25]
    DIRECTION OUTPUT ;
    USE SIGNAL ;
    PORT
      LAYER M5 ;
        RECT  15.312 86.316 15.336 86.4 ;
    END
  END rq[25]
  PIN rq[26]
    DIRECTION OUTPUT ;
    USE SIGNAL ;
    PORT
      LAYER M5 ;
        RECT  15.888 86.316 15.912 86.4 ;
    END
  END rq[26]
  PIN rq[27]
    DIRECTION OUTPUT ;
    USE SIGNAL ;
    PORT
      LAYER M5 ;
        RECT  16.512 86.316 16.536 86.4 ;
    END
  END rq[27]
  PIN rq[28]
    DIRECTION OUTPUT ;
    USE SIGNAL ;
    PORT
      LAYER M5 ;
        RECT  17.088 86.316 17.112 86.4 ;
    END
  END rq[28]
  PIN rq[29]
    DIRECTION OUTPUT ;
    USE SIGNAL ;
    PORT
      LAYER M5 ;
        RECT  17.712 86.316 17.736 86.4 ;
    END
  END rq[29]
  PIN rq[2]
    DIRECTION OUTPUT ;
    USE SIGNAL ;
    PORT
      LAYER M5 ;
        RECT  1.488 86.316 1.512 86.4 ;
    END
  END rq[2]
  PIN rq[30]
    DIRECTION OUTPUT ;
    USE SIGNAL ;
    PORT
      LAYER M5 ;
        RECT  18.288 86.316 18.312 86.4 ;
    END
  END rq[30]
  PIN rq[31]
    DIRECTION OUTPUT ;
    USE SIGNAL ;
    PORT
      LAYER M5 ;
        RECT  18.912 86.316 18.936 86.4 ;
    END
  END rq[31]
  PIN rq[32]
    DIRECTION OUTPUT ;
    USE SIGNAL ;
    PORT
      LAYER M5 ;
        RECT  19.488 86.316 19.512 86.4 ;
    END
  END rq[32]
  PIN rq[33]
    DIRECTION OUTPUT ;
    USE SIGNAL ;
    PORT
      LAYER M5 ;
        RECT  20.112 86.316 20.136 86.4 ;
    END
  END rq[33]
  PIN rq[34]
    DIRECTION OUTPUT ;
    USE SIGNAL ;
    PORT
      LAYER M5 ;
        RECT  20.688 86.316 20.712 86.4 ;
    END
  END rq[34]
  PIN rq[35]
    DIRECTION OUTPUT ;
    USE SIGNAL ;
    PORT
      LAYER M5 ;
        RECT  21.312 86.316 21.336 86.4 ;
    END
  END rq[35]
  PIN rq[36]
    DIRECTION OUTPUT ;
    USE SIGNAL ;
    PORT
      LAYER M5 ;
        RECT  21.888 86.316 21.912 86.4 ;
    END
  END rq[36]
  PIN rq[37]
    DIRECTION OUTPUT ;
    USE SIGNAL ;
    PORT
      LAYER M5 ;
        RECT  22.512 86.316 22.536 86.4 ;
    END
  END rq[37]
  PIN rq[38]
    DIRECTION OUTPUT ;
    USE SIGNAL ;
    PORT
      LAYER M5 ;
        RECT  23.088 86.316 23.112 86.4 ;
    END
  END rq[38]
  PIN rq[39]
    DIRECTION OUTPUT ;
    USE SIGNAL ;
    PORT
      LAYER M5 ;
        RECT  23.712 86.316 23.736 86.4 ;
    END
  END rq[39]
  PIN rq[3]
    DIRECTION OUTPUT ;
    USE SIGNAL ;
    PORT
      LAYER M5 ;
        RECT  2.112 86.316 2.136 86.4 ;
    END
  END rq[3]
  PIN rq[40]
    DIRECTION OUTPUT ;
    USE SIGNAL ;
    PORT
      LAYER M5 ;
        RECT  24.288 86.316 24.312 86.4 ;
    END
  END rq[40]
  PIN rq[41]
    DIRECTION OUTPUT ;
    USE SIGNAL ;
    PORT
      LAYER M5 ;
        RECT  24.912 86.316 24.936 86.4 ;
    END
  END rq[41]
  PIN rq[42]
    DIRECTION OUTPUT ;
    USE SIGNAL ;
    PORT
      LAYER M5 ;
        RECT  25.488 86.316 25.512 86.4 ;
    END
  END rq[42]
  PIN rq[43]
    DIRECTION OUTPUT ;
    USE SIGNAL ;
    PORT
      LAYER M5 ;
        RECT  26.112 86.316 26.136 86.4 ;
    END
  END rq[43]
  PIN rq[44]
    DIRECTION OUTPUT ;
    USE SIGNAL ;
    PORT
      LAYER M5 ;
        RECT  26.688 86.316 26.712 86.4 ;
    END
  END rq[44]
  PIN rq[45]
    DIRECTION OUTPUT ;
    USE SIGNAL ;
    PORT
      LAYER M5 ;
        RECT  27.312 86.316 27.336 86.4 ;
    END
  END rq[45]
  PIN rq[46]
    DIRECTION OUTPUT ;
    USE SIGNAL ;
    PORT
      LAYER M5 ;
        RECT  27.888 86.316 27.912 86.4 ;
    END
  END rq[46]
  PIN rq[47]
    DIRECTION OUTPUT ;
    USE SIGNAL ;
    PORT
      LAYER M5 ;
        RECT  28.512 86.316 28.536 86.4 ;
    END
  END rq[47]
  PIN rq[48]
    DIRECTION OUTPUT ;
    USE SIGNAL ;
    PORT
      LAYER M5 ;
        RECT  29.088 86.316 29.112 86.4 ;
    END
  END rq[48]
  PIN rq[49]
    DIRECTION OUTPUT ;
    USE SIGNAL ;
    PORT
      LAYER M5 ;
        RECT  29.712 86.316 29.736 86.4 ;
    END
  END rq[49]
  PIN rq[4]
    DIRECTION OUTPUT ;
    USE SIGNAL ;
    PORT
      LAYER M5 ;
        RECT  2.688 86.316 2.712 86.4 ;
    END
  END rq[4]
  PIN rq[50]
    DIRECTION OUTPUT ;
    USE SIGNAL ;
    PORT
      LAYER M5 ;
        RECT  30.288 86.316 30.312 86.4 ;
    END
  END rq[50]
  PIN rq[51]
    DIRECTION OUTPUT ;
    USE SIGNAL ;
    PORT
      LAYER M5 ;
        RECT  30.912 86.316 30.936 86.4 ;
    END
  END rq[51]
  PIN rq[52]
    DIRECTION OUTPUT ;
    USE SIGNAL ;
    PORT
      LAYER M5 ;
        RECT  31.488 86.316 31.512 86.4 ;
    END
  END rq[52]
  PIN rq[53]
    DIRECTION OUTPUT ;
    USE SIGNAL ;
    PORT
      LAYER M5 ;
        RECT  32.112 86.316 32.136 86.4 ;
    END
  END rq[53]
  PIN rq[54]
    DIRECTION OUTPUT ;
    USE SIGNAL ;
    PORT
      LAYER M5 ;
        RECT  32.688 86.316 32.712 86.4 ;
    END
  END rq[54]
  PIN rq[55]
    DIRECTION OUTPUT ;
    USE SIGNAL ;
    PORT
      LAYER M5 ;
        RECT  33.312 86.316 33.336 86.4 ;
    END
  END rq[55]
  PIN rq[56]
    DIRECTION OUTPUT ;
    USE SIGNAL ;
    PORT
      LAYER M5 ;
        RECT  33.888 86.316 33.912 86.4 ;
    END
  END rq[56]
  PIN rq[57]
    DIRECTION OUTPUT ;
    USE SIGNAL ;
    PORT
      LAYER M5 ;
        RECT  34.512 86.316 34.536 86.4 ;
    END
  END rq[57]
  PIN rq[58]
    DIRECTION OUTPUT ;
    USE SIGNAL ;
    PORT
      LAYER M5 ;
        RECT  35.088 86.316 35.112 86.4 ;
    END
  END rq[58]
  PIN rq[59]
    DIRECTION OUTPUT ;
    USE SIGNAL ;
    PORT
      LAYER M5 ;
        RECT  35.712 86.316 35.736 86.4 ;
    END
  END rq[59]
  PIN rq[5]
    DIRECTION OUTPUT ;
    USE SIGNAL ;
    PORT
      LAYER M5 ;
        RECT  3.312 86.316 3.336 86.4 ;
    END
  END rq[5]
  PIN rq[60]
    DIRECTION OUTPUT ;
    USE SIGNAL ;
    PORT
      LAYER M5 ;
        RECT  36.288 86.316 36.312 86.4 ;
    END
  END rq[60]
  PIN rq[61]
    DIRECTION OUTPUT ;
    USE SIGNAL ;
    PORT
      LAYER M5 ;
        RECT  36.912 86.316 36.936 86.4 ;
    END
  END rq[61]
  PIN rq[62]
    DIRECTION OUTPUT ;
    USE SIGNAL ;
    PORT
      LAYER M5 ;
        RECT  37.488 86.316 37.512 86.4 ;
    END
  END rq[62]
  PIN rq[63]
    DIRECTION OUTPUT ;
    USE SIGNAL ;
    PORT
      LAYER M5 ;
        RECT  38.112 86.316 38.136 86.4 ;
    END
  END rq[63]
  PIN rq[64]
    DIRECTION OUTPUT ;
    USE SIGNAL ;
    PORT
      LAYER M5 ;
        RECT  38.688 86.316 38.712 86.4 ;
    END
  END rq[64]
  PIN rq[65]
    DIRECTION OUTPUT ;
    USE SIGNAL ;
    PORT
      LAYER M5 ;
        RECT  39.312 86.316 39.336 86.4 ;
    END
  END rq[65]
  PIN rq[66]
    DIRECTION OUTPUT ;
    USE SIGNAL ;
    PORT
      LAYER M5 ;
        RECT  39.888 86.316 39.912 86.4 ;
    END
  END rq[66]
  PIN rq[67]
    DIRECTION OUTPUT ;
    USE SIGNAL ;
    PORT
      LAYER M5 ;
        RECT  40.512 86.316 40.536 86.4 ;
    END
  END rq[67]
  PIN rq[68]
    DIRECTION OUTPUT ;
    USE SIGNAL ;
    PORT
      LAYER M5 ;
        RECT  41.088 86.316 41.112 86.4 ;
    END
  END rq[68]
  PIN rq[69]
    DIRECTION OUTPUT ;
    USE SIGNAL ;
    PORT
      LAYER M5 ;
        RECT  41.712 86.316 41.736 86.4 ;
    END
  END rq[69]
  PIN rq[6]
    DIRECTION OUTPUT ;
    USE SIGNAL ;
    PORT
      LAYER M5 ;
        RECT  3.888 86.316 3.912 86.4 ;
    END
  END rq[6]
  PIN rq[70]
    DIRECTION OUTPUT ;
    USE SIGNAL ;
    PORT
      LAYER M5 ;
        RECT  42.288 86.316 42.312 86.4 ;
    END
  END rq[70]
  PIN rq[71]
    DIRECTION OUTPUT ;
    USE SIGNAL ;
    PORT
      LAYER M5 ;
        RECT  42.912 86.316 42.936 86.4 ;
    END
  END rq[71]
  PIN rq[72]
    DIRECTION OUTPUT ;
    USE SIGNAL ;
    PORT
      LAYER M5 ;
        RECT  43.488 86.316 43.512 86.4 ;
    END
  END rq[72]
  PIN rq[73]
    DIRECTION OUTPUT ;
    USE SIGNAL ;
    PORT
      LAYER M5 ;
        RECT  44.112 86.316 44.136 86.4 ;
    END
  END rq[73]
  PIN rq[74]
    DIRECTION OUTPUT ;
    USE SIGNAL ;
    PORT
      LAYER M5 ;
        RECT  44.688 86.316 44.712 86.4 ;
    END
  END rq[74]
  PIN rq[75]
    DIRECTION OUTPUT ;
    USE SIGNAL ;
    PORT
      LAYER M5 ;
        RECT  45.312 86.316 45.336 86.4 ;
    END
  END rq[75]
  PIN rq[76]
    DIRECTION OUTPUT ;
    USE SIGNAL ;
    PORT
      LAYER M5 ;
        RECT  45.888 86.316 45.912 86.4 ;
    END
  END rq[76]
  PIN rq[77]
    DIRECTION OUTPUT ;
    USE SIGNAL ;
    PORT
      LAYER M5 ;
        RECT  46.512 86.316 46.536 86.4 ;
    END
  END rq[77]
  PIN rq[78]
    DIRECTION OUTPUT ;
    USE SIGNAL ;
    PORT
      LAYER M5 ;
        RECT  47.088 86.316 47.112 86.4 ;
    END
  END rq[78]
  PIN rq[79]
    DIRECTION OUTPUT ;
    USE SIGNAL ;
    PORT
      LAYER M5 ;
        RECT  47.712 86.316 47.736 86.4 ;
    END
  END rq[79]
  PIN rq[7]
    DIRECTION OUTPUT ;
    USE SIGNAL ;
    PORT
      LAYER M5 ;
        RECT  4.512 86.316 4.536 86.4 ;
    END
  END rq[7]
  PIN rq[80]
    DIRECTION OUTPUT ;
    USE SIGNAL ;
    PORT
      LAYER M5 ;
        RECT  48.288 86.316 48.312 86.4 ;
    END
  END rq[80]
  PIN rq[81]
    DIRECTION OUTPUT ;
    USE SIGNAL ;
    PORT
      LAYER M5 ;
        RECT  48.912 86.316 48.936 86.4 ;
    END
  END rq[81]
  PIN rq[82]
    DIRECTION OUTPUT ;
    USE SIGNAL ;
    PORT
      LAYER M5 ;
        RECT  49.488 86.316 49.512 86.4 ;
    END
  END rq[82]
  PIN rq[83]
    DIRECTION OUTPUT ;
    USE SIGNAL ;
    PORT
      LAYER M5 ;
        RECT  50.112 86.316 50.136 86.4 ;
    END
  END rq[83]
  PIN rq[84]
    DIRECTION OUTPUT ;
    USE SIGNAL ;
    PORT
      LAYER M5 ;
        RECT  50.688 86.316 50.712 86.4 ;
    END
  END rq[84]
  PIN rq[85]
    DIRECTION OUTPUT ;
    USE SIGNAL ;
    PORT
      LAYER M5 ;
        RECT  51.312 86.316 51.336 86.4 ;
    END
  END rq[85]
  PIN rq[86]
    DIRECTION OUTPUT ;
    USE SIGNAL ;
    PORT
      LAYER M5 ;
        RECT  51.888 86.316 51.912 86.4 ;
    END
  END rq[86]
  PIN rq[87]
    DIRECTION OUTPUT ;
    USE SIGNAL ;
    PORT
      LAYER M5 ;
        RECT  52.512 86.316 52.536 86.4 ;
    END
  END rq[87]
  PIN rq[88]
    DIRECTION OUTPUT ;
    USE SIGNAL ;
    PORT
      LAYER M5 ;
        RECT  53.088 86.316 53.112 86.4 ;
    END
  END rq[88]
  PIN rq[89]
    DIRECTION OUTPUT ;
    USE SIGNAL ;
    PORT
      LAYER M5 ;
        RECT  53.712 86.316 53.736 86.4 ;
    END
  END rq[89]
  PIN rq[8]
    DIRECTION OUTPUT ;
    USE SIGNAL ;
    PORT
      LAYER M5 ;
        RECT  5.088 86.316 5.112 86.4 ;
    END
  END rq[8]
  PIN rq[90]
    DIRECTION OUTPUT ;
    USE SIGNAL ;
    PORT
      LAYER M5 ;
        RECT  54.288 86.316 54.312 86.4 ;
    END
  END rq[90]
  PIN rq[91]
    DIRECTION OUTPUT ;
    USE SIGNAL ;
    PORT
      LAYER M5 ;
        RECT  54.912 86.316 54.936 86.4 ;
    END
  END rq[91]
  PIN rq[92]
    DIRECTION OUTPUT ;
    USE SIGNAL ;
    PORT
      LAYER M5 ;
        RECT  55.488 86.316 55.512 86.4 ;
    END
  END rq[92]
  PIN rq[93]
    DIRECTION OUTPUT ;
    USE SIGNAL ;
    PORT
      LAYER M5 ;
        RECT  56.112 86.316 56.136 86.4 ;
    END
  END rq[93]
  PIN rq[94]
    DIRECTION OUTPUT ;
    USE SIGNAL ;
    PORT
      LAYER M5 ;
        RECT  56.688 86.316 56.712 86.4 ;
    END
  END rq[94]
  PIN rq[95]
    DIRECTION OUTPUT ;
    USE SIGNAL ;
    PORT
      LAYER M5 ;
        RECT  57.312 86.316 57.336 86.4 ;
    END
  END rq[95]
  PIN rq[96]
    DIRECTION OUTPUT ;
    USE SIGNAL ;
    PORT
      LAYER M5 ;
        RECT  57.888 86.316 57.912 86.4 ;
    END
  END rq[96]
  PIN rq[97]
    DIRECTION OUTPUT ;
    USE SIGNAL ;
    PORT
      LAYER M5 ;
        RECT  58.512 86.316 58.536 86.4 ;
    END
  END rq[97]
  PIN rq[98]
    DIRECTION OUTPUT ;
    USE SIGNAL ;
    PORT
      LAYER M5 ;
        RECT  59.088 86.316 59.112 86.4 ;
    END
  END rq[98]
  PIN rq[99]
    DIRECTION OUTPUT ;
    USE SIGNAL ;
    PORT
      LAYER M5 ;
        RECT  59.712 86.316 59.736 86.4 ;
    END
  END rq[99]
  PIN rq[9]
    DIRECTION OUTPUT ;
    USE SIGNAL ;
    PORT
      LAYER M5 ;
        RECT  5.712 86.316 5.736 86.4 ;
    END
  END rq[9]
  PIN rr_v[0]
    DIRECTION INPUT ;
    USE SIGNAL ;
    PORT
      LAYER M5 ;
        RECT  81.888 86.316 81.912 86.4 ;
    END
  END rr_v[0]
  PIN rr_v[1]
    DIRECTION INPUT ;
    USE SIGNAL ;
    PORT
      LAYER M5 ;
        RECT  82.512 86.316 82.536 86.4 ;
    END
  END rr_v[1]
  PIN rr_v[2]
    DIRECTION INPUT ;
    USE SIGNAL ;
    PORT
      LAYER M5 ;
        RECT  83.088 86.316 83.112 86.4 ;
    END
  END rr_v[2]
  PIN rr_v[3]
    DIRECTION INPUT ;
    USE SIGNAL ;
    PORT
      LAYER M5 ;
        RECT  83.712 86.316 83.736 86.4 ;
    END
  END rr_v[3]
  PIN rr_v[4]
    DIRECTION INPUT ;
    USE SIGNAL ;
    PORT
      LAYER M5 ;
        RECT  84.288 86.316 84.312 86.4 ;
    END
  END rr_v[4]
  PIN rr_v[5]
    DIRECTION INPUT ;
    USE SIGNAL ;
    PORT
      LAYER M5 ;
        RECT  84.912 86.316 84.936 86.4 ;
    END
  END rr_v[5]
  PIN rr_v[6]
    DIRECTION INPUT ;
    USE SIGNAL ;
    PORT
      LAYER M5 ;
        RECT  85.488 86.316 85.512 86.4 ;
    END
  END rr_v[6]
  PIN rr_v[7]
    DIRECTION INPUT ;
    USE SIGNAL ;
    PORT
      LAYER M5 ;
        RECT  86.112 86.316 86.136 86.4 ;
    END
  END rr_v[7]
  PIN rsel[0]
    DIRECTION OUTPUT ;
    USE SIGNAL ;
    PORT
      LAYER M4 ;
        RECT  86.316 82.32 86.4 82.344 ;
    END
  END rsel[0]
  PIN rsel[1]
    DIRECTION OUTPUT ;
    USE SIGNAL ;
    PORT
      LAYER M4 ;
        RECT  86.316 82.944 86.4 82.968 ;
    END
  END rsel[1]
  PIN rsel[2]
    DIRECTION OUTPUT ;
    USE SIGNAL ;
    PORT
      LAYER M4 ;
        RECT  86.316 83.568 86.4 83.592 ;
    END
  END rsel[2]
  PIN rst_n
    DIRECTION INPUT ;
    USE SIGNAL ;
    PORT
      LAYER M4 ;
        RECT  0 85.584 0.084 85.608 ;
    END
    PORT
      LAYER M4 ;
        RECT  0.06 85.584 2.101 85.608 ;
    END
  END rst_n
  PIN vo
    DIRECTION INPUT ;
    USE SIGNAL ;
    PORT
      LAYER M4 ;
        RECT  86.316 84.192 86.4 84.216 ;
    END
  END vo
  PIN wq_addr[0]
    DIRECTION OUTPUT ;
    USE SIGNAL ;
    PORT
      LAYER M5 ;
        RECT  0.192 0 0.216 0.084 ;
    END
  END wq_addr[0]
  PIN wq_addr[100]
    DIRECTION OUTPUT ;
    USE SIGNAL ;
    PORT
      LAYER M5 ;
        RECT  43.392 0 43.416 0.084 ;
    END
  END wq_addr[100]
  PIN wq_addr[101]
    DIRECTION OUTPUT ;
    USE SIGNAL ;
    PORT
      LAYER M5 ;
        RECT  43.824 0 43.848 0.084 ;
    END
  END wq_addr[101]
  PIN wq_addr[102]
    DIRECTION OUTPUT ;
    USE SIGNAL ;
    PORT
      LAYER M5 ;
        RECT  44.256 0 44.28 0.084 ;
    END
  END wq_addr[102]
  PIN wq_addr[103]
    DIRECTION OUTPUT ;
    USE SIGNAL ;
    PORT
      LAYER M5 ;
        RECT  44.688 0 44.712 0.084 ;
    END
  END wq_addr[103]
  PIN wq_addr[104]
    DIRECTION OUTPUT ;
    USE SIGNAL ;
    PORT
      LAYER M5 ;
        RECT  45.12 0 45.144 0.084 ;
    END
  END wq_addr[104]
  PIN wq_addr[105]
    DIRECTION OUTPUT ;
    USE SIGNAL ;
    PORT
      LAYER M5 ;
        RECT  45.552 0 45.576 0.084 ;
    END
  END wq_addr[105]
  PIN wq_addr[106]
    DIRECTION OUTPUT ;
    USE SIGNAL ;
    PORT
      LAYER M5 ;
        RECT  45.984 0 46.008 0.084 ;
    END
  END wq_addr[106]
  PIN wq_addr[107]
    DIRECTION OUTPUT ;
    USE SIGNAL ;
    PORT
      LAYER M5 ;
        RECT  46.416 0 46.44 0.084 ;
    END
  END wq_addr[107]
  PIN wq_addr[108]
    DIRECTION OUTPUT ;
    USE SIGNAL ;
    PORT
      LAYER M5 ;
        RECT  46.848 0 46.872 0.084 ;
    END
  END wq_addr[108]
  PIN wq_addr[109]
    DIRECTION OUTPUT ;
    USE SIGNAL ;
    PORT
      LAYER M5 ;
        RECT  47.28 0 47.304 0.084 ;
    END
  END wq_addr[109]
  PIN wq_addr[10]
    DIRECTION OUTPUT ;
    USE SIGNAL ;
    PORT
      LAYER M5 ;
        RECT  4.512 0 4.536 0.084 ;
    END
  END wq_addr[10]
  PIN wq_addr[110]
    DIRECTION OUTPUT ;
    USE SIGNAL ;
    PORT
      LAYER M5 ;
        RECT  47.712 0 47.736 0.084 ;
    END
  END wq_addr[110]
  PIN wq_addr[111]
    DIRECTION OUTPUT ;
    USE SIGNAL ;
    PORT
      LAYER M5 ;
        RECT  48.144 0 48.168 0.084 ;
    END
  END wq_addr[111]
  PIN wq_addr[112]
    DIRECTION OUTPUT ;
    USE SIGNAL ;
    PORT
      LAYER M5 ;
        RECT  48.576 0 48.6 0.084 ;
    END
  END wq_addr[112]
  PIN wq_addr[113]
    DIRECTION OUTPUT ;
    USE SIGNAL ;
    PORT
      LAYER M5 ;
        RECT  49.008 0 49.032 0.084 ;
    END
  END wq_addr[113]
  PIN wq_addr[114]
    DIRECTION OUTPUT ;
    USE SIGNAL ;
    PORT
      LAYER M5 ;
        RECT  49.44 0 49.464 0.084 ;
    END
  END wq_addr[114]
  PIN wq_addr[115]
    DIRECTION OUTPUT ;
    USE SIGNAL ;
    PORT
      LAYER M5 ;
        RECT  49.872 0 49.896 0.084 ;
    END
  END wq_addr[115]
  PIN wq_addr[116]
    DIRECTION OUTPUT ;
    USE SIGNAL ;
    PORT
      LAYER M5 ;
        RECT  50.304 0 50.328 0.084 ;
    END
  END wq_addr[116]
  PIN wq_addr[117]
    DIRECTION OUTPUT ;
    USE SIGNAL ;
    PORT
      LAYER M5 ;
        RECT  50.736 0 50.76 0.084 ;
    END
  END wq_addr[117]
  PIN wq_addr[118]
    DIRECTION OUTPUT ;
    USE SIGNAL ;
    PORT
      LAYER M5 ;
        RECT  51.168 0 51.192 0.084 ;
    END
  END wq_addr[118]
  PIN wq_addr[119]
    DIRECTION OUTPUT ;
    USE SIGNAL ;
    PORT
      LAYER M5 ;
        RECT  51.6 0 51.624 0.084 ;
    END
  END wq_addr[119]
  PIN wq_addr[11]
    DIRECTION OUTPUT ;
    USE SIGNAL ;
    PORT
      LAYER M5 ;
        RECT  4.944 0 4.968 0.084 ;
    END
  END wq_addr[11]
  PIN wq_addr[120]
    DIRECTION OUTPUT ;
    USE SIGNAL ;
    PORT
      LAYER M5 ;
        RECT  52.032 0 52.056 0.084 ;
    END
  END wq_addr[120]
  PIN wq_addr[121]
    DIRECTION OUTPUT ;
    USE SIGNAL ;
    PORT
      LAYER M5 ;
        RECT  52.464 0 52.488 0.084 ;
    END
  END wq_addr[121]
  PIN wq_addr[122]
    DIRECTION OUTPUT ;
    USE SIGNAL ;
    PORT
      LAYER M5 ;
        RECT  52.896 0 52.92 0.084 ;
    END
  END wq_addr[122]
  PIN wq_addr[123]
    DIRECTION OUTPUT ;
    USE SIGNAL ;
    PORT
      LAYER M5 ;
        RECT  53.328 0 53.352 0.084 ;
    END
  END wq_addr[123]
  PIN wq_addr[124]
    DIRECTION OUTPUT ;
    USE SIGNAL ;
    PORT
      LAYER M5 ;
        RECT  53.76 0 53.784 0.084 ;
    END
  END wq_addr[124]
  PIN wq_addr[125]
    DIRECTION OUTPUT ;
    USE SIGNAL ;
    PORT
      LAYER M5 ;
        RECT  54.192 0 54.216 0.084 ;
    END
  END wq_addr[125]
  PIN wq_addr[126]
    DIRECTION OUTPUT ;
    USE SIGNAL ;
    PORT
      LAYER M5 ;
        RECT  54.624 0 54.648 0.084 ;
    END
  END wq_addr[126]
  PIN wq_addr[127]
    DIRECTION OUTPUT ;
    USE SIGNAL ;
    PORT
      LAYER M5 ;
        RECT  55.056 0 55.08 0.084 ;
    END
  END wq_addr[127]
  PIN wq_addr[12]
    DIRECTION OUTPUT ;
    USE SIGNAL ;
    PORT
      LAYER M5 ;
        RECT  5.376 0 5.4 0.084 ;
    END
  END wq_addr[12]
  PIN wq_addr[13]
    DIRECTION OUTPUT ;
    USE SIGNAL ;
    PORT
      LAYER M5 ;
        RECT  5.808 0 5.832 0.084 ;
    END
  END wq_addr[13]
  PIN wq_addr[14]
    DIRECTION OUTPUT ;
    USE SIGNAL ;
    PORT
      LAYER M5 ;
        RECT  6.24 0 6.264 0.084 ;
    END
  END wq_addr[14]
  PIN wq_addr[15]
    DIRECTION OUTPUT ;
    USE SIGNAL ;
    PORT
      LAYER M5 ;
        RECT  6.672 0 6.696 0.084 ;
    END
  END wq_addr[15]
  PIN wq_addr[16]
    DIRECTION OUTPUT ;
    USE SIGNAL ;
    PORT
      LAYER M5 ;
        RECT  7.104 0 7.128 0.084 ;
    END
  END wq_addr[16]
  PIN wq_addr[17]
    DIRECTION OUTPUT ;
    USE SIGNAL ;
    PORT
      LAYER M5 ;
        RECT  7.536 0 7.56 0.084 ;
    END
  END wq_addr[17]
  PIN wq_addr[18]
    DIRECTION OUTPUT ;
    USE SIGNAL ;
    PORT
      LAYER M5 ;
        RECT  7.968 0 7.992 0.084 ;
    END
  END wq_addr[18]
  PIN wq_addr[19]
    DIRECTION OUTPUT ;
    USE SIGNAL ;
    PORT
      LAYER M5 ;
        RECT  8.4 0 8.424 0.084 ;
    END
  END wq_addr[19]
  PIN wq_addr[1]
    DIRECTION OUTPUT ;
    USE SIGNAL ;
    PORT
      LAYER M5 ;
        RECT  0.624 0 0.648 0.084 ;
    END
  END wq_addr[1]
  PIN wq_addr[20]
    DIRECTION OUTPUT ;
    USE SIGNAL ;
    PORT
      LAYER M5 ;
        RECT  8.832 0 8.856 0.084 ;
    END
  END wq_addr[20]
  PIN wq_addr[21]
    DIRECTION OUTPUT ;
    USE SIGNAL ;
    PORT
      LAYER M5 ;
        RECT  9.264 0 9.288 0.084 ;
    END
  END wq_addr[21]
  PIN wq_addr[22]
    DIRECTION OUTPUT ;
    USE SIGNAL ;
    PORT
      LAYER M5 ;
        RECT  9.696 0 9.72 0.084 ;
    END
  END wq_addr[22]
  PIN wq_addr[23]
    DIRECTION OUTPUT ;
    USE SIGNAL ;
    PORT
      LAYER M5 ;
        RECT  10.128 0 10.152 0.084 ;
    END
  END wq_addr[23]
  PIN wq_addr[24]
    DIRECTION OUTPUT ;
    USE SIGNAL ;
    PORT
      LAYER M5 ;
        RECT  10.56 0 10.584 0.084 ;
    END
  END wq_addr[24]
  PIN wq_addr[25]
    DIRECTION OUTPUT ;
    USE SIGNAL ;
    PORT
      LAYER M5 ;
        RECT  10.992 0 11.016 0.084 ;
    END
  END wq_addr[25]
  PIN wq_addr[26]
    DIRECTION OUTPUT ;
    USE SIGNAL ;
    PORT
      LAYER M5 ;
        RECT  11.424 0 11.448 0.084 ;
    END
  END wq_addr[26]
  PIN wq_addr[27]
    DIRECTION OUTPUT ;
    USE SIGNAL ;
    PORT
      LAYER M5 ;
        RECT  11.856 0 11.88 0.084 ;
    END
  END wq_addr[27]
  PIN wq_addr[28]
    DIRECTION OUTPUT ;
    USE SIGNAL ;
    PORT
      LAYER M5 ;
        RECT  12.288 0 12.312 0.084 ;
    END
  END wq_addr[28]
  PIN wq_addr[29]
    DIRECTION OUTPUT ;
    USE SIGNAL ;
    PORT
      LAYER M5 ;
        RECT  12.72 0 12.744 0.084 ;
    END
  END wq_addr[29]
  PIN wq_addr[2]
    DIRECTION OUTPUT ;
    USE SIGNAL ;
    PORT
      LAYER M5 ;
        RECT  1.056 0 1.08 0.084 ;
    END
  END wq_addr[2]
  PIN wq_addr[30]
    DIRECTION OUTPUT ;
    USE SIGNAL ;
    PORT
      LAYER M5 ;
        RECT  13.152 0 13.176 0.084 ;
    END
  END wq_addr[30]
  PIN wq_addr[31]
    DIRECTION OUTPUT ;
    USE SIGNAL ;
    PORT
      LAYER M5 ;
        RECT  13.584 0 13.608 0.084 ;
    END
  END wq_addr[31]
  PIN wq_addr[32]
    DIRECTION OUTPUT ;
    USE SIGNAL ;
    PORT
      LAYER M5 ;
        RECT  14.016 0 14.04 0.084 ;
    END
  END wq_addr[32]
  PIN wq_addr[33]
    DIRECTION OUTPUT ;
    USE SIGNAL ;
    PORT
      LAYER M5 ;
        RECT  14.448 0 14.472 0.084 ;
    END
  END wq_addr[33]
  PIN wq_addr[34]
    DIRECTION OUTPUT ;
    USE SIGNAL ;
    PORT
      LAYER M5 ;
        RECT  14.88 0 14.904 0.084 ;
    END
  END wq_addr[34]
  PIN wq_addr[35]
    DIRECTION OUTPUT ;
    USE SIGNAL ;
    PORT
      LAYER M5 ;
        RECT  15.312 0 15.336 0.084 ;
    END
  END wq_addr[35]
  PIN wq_addr[36]
    DIRECTION OUTPUT ;
    USE SIGNAL ;
    PORT
      LAYER M5 ;
        RECT  15.744 0 15.768 0.084 ;
    END
  END wq_addr[36]
  PIN wq_addr[37]
    DIRECTION OUTPUT ;
    USE SIGNAL ;
    PORT
      LAYER M5 ;
        RECT  16.176 0 16.2 0.084 ;
    END
  END wq_addr[37]
  PIN wq_addr[38]
    DIRECTION OUTPUT ;
    USE SIGNAL ;
    PORT
      LAYER M5 ;
        RECT  16.608 0 16.632 0.084 ;
    END
  END wq_addr[38]
  PIN wq_addr[39]
    DIRECTION OUTPUT ;
    USE SIGNAL ;
    PORT
      LAYER M5 ;
        RECT  17.04 0 17.064 0.084 ;
    END
  END wq_addr[39]
  PIN wq_addr[3]
    DIRECTION OUTPUT ;
    USE SIGNAL ;
    PORT
      LAYER M5 ;
        RECT  1.488 0 1.512 0.084 ;
    END
  END wq_addr[3]
  PIN wq_addr[40]
    DIRECTION OUTPUT ;
    USE SIGNAL ;
    PORT
      LAYER M5 ;
        RECT  17.472 0 17.496 0.084 ;
    END
  END wq_addr[40]
  PIN wq_addr[41]
    DIRECTION OUTPUT ;
    USE SIGNAL ;
    PORT
      LAYER M5 ;
        RECT  17.904 0 17.928 0.084 ;
    END
  END wq_addr[41]
  PIN wq_addr[42]
    DIRECTION OUTPUT ;
    USE SIGNAL ;
    PORT
      LAYER M5 ;
        RECT  18.336 0 18.36 0.084 ;
    END
  END wq_addr[42]
  PIN wq_addr[43]
    DIRECTION OUTPUT ;
    USE SIGNAL ;
    PORT
      LAYER M5 ;
        RECT  18.768 0 18.792 0.084 ;
    END
  END wq_addr[43]
  PIN wq_addr[44]
    DIRECTION OUTPUT ;
    USE SIGNAL ;
    PORT
      LAYER M5 ;
        RECT  19.2 0 19.224 0.084 ;
    END
  END wq_addr[44]
  PIN wq_addr[45]
    DIRECTION OUTPUT ;
    USE SIGNAL ;
    PORT
      LAYER M5 ;
        RECT  19.632 0 19.656 0.084 ;
    END
  END wq_addr[45]
  PIN wq_addr[46]
    DIRECTION OUTPUT ;
    USE SIGNAL ;
    PORT
      LAYER M5 ;
        RECT  20.064 0 20.088 0.084 ;
    END
  END wq_addr[46]
  PIN wq_addr[47]
    DIRECTION OUTPUT ;
    USE SIGNAL ;
    PORT
      LAYER M5 ;
        RECT  20.496 0 20.52 0.084 ;
    END
  END wq_addr[47]
  PIN wq_addr[48]
    DIRECTION OUTPUT ;
    USE SIGNAL ;
    PORT
      LAYER M5 ;
        RECT  20.928 0 20.952 0.084 ;
    END
  END wq_addr[48]
  PIN wq_addr[49]
    DIRECTION OUTPUT ;
    USE SIGNAL ;
    PORT
      LAYER M5 ;
        RECT  21.36 0 21.384 0.084 ;
    END
  END wq_addr[49]
  PIN wq_addr[4]
    DIRECTION OUTPUT ;
    USE SIGNAL ;
    PORT
      LAYER M5 ;
        RECT  1.92 0 1.944 0.084 ;
    END
  END wq_addr[4]
  PIN wq_addr[50]
    DIRECTION OUTPUT ;
    USE SIGNAL ;
    PORT
      LAYER M5 ;
        RECT  21.792 0 21.816 0.084 ;
    END
  END wq_addr[50]
  PIN wq_addr[51]
    DIRECTION OUTPUT ;
    USE SIGNAL ;
    PORT
      LAYER M5 ;
        RECT  22.224 0 22.248 0.084 ;
    END
  END wq_addr[51]
  PIN wq_addr[52]
    DIRECTION OUTPUT ;
    USE SIGNAL ;
    PORT
      LAYER M5 ;
        RECT  22.656 0 22.68 0.084 ;
    END
  END wq_addr[52]
  PIN wq_addr[53]
    DIRECTION OUTPUT ;
    USE SIGNAL ;
    PORT
      LAYER M5 ;
        RECT  23.088 0 23.112 0.084 ;
    END
  END wq_addr[53]
  PIN wq_addr[54]
    DIRECTION OUTPUT ;
    USE SIGNAL ;
    PORT
      LAYER M5 ;
        RECT  23.52 0 23.544 0.084 ;
    END
  END wq_addr[54]
  PIN wq_addr[55]
    DIRECTION OUTPUT ;
    USE SIGNAL ;
    PORT
      LAYER M5 ;
        RECT  23.952 0 23.976 0.084 ;
    END
  END wq_addr[55]
  PIN wq_addr[56]
    DIRECTION OUTPUT ;
    USE SIGNAL ;
    PORT
      LAYER M5 ;
        RECT  24.384 0 24.408 0.084 ;
    END
  END wq_addr[56]
  PIN wq_addr[57]
    DIRECTION OUTPUT ;
    USE SIGNAL ;
    PORT
      LAYER M5 ;
        RECT  24.816 0 24.84 0.084 ;
    END
  END wq_addr[57]
  PIN wq_addr[58]
    DIRECTION OUTPUT ;
    USE SIGNAL ;
    PORT
      LAYER M5 ;
        RECT  25.248 0 25.272 0.084 ;
    END
  END wq_addr[58]
  PIN wq_addr[59]
    DIRECTION OUTPUT ;
    USE SIGNAL ;
    PORT
      LAYER M5 ;
        RECT  25.68 0 25.704 0.084 ;
    END
  END wq_addr[59]
  PIN wq_addr[5]
    DIRECTION OUTPUT ;
    USE SIGNAL ;
    PORT
      LAYER M5 ;
        RECT  2.352 0 2.376 0.084 ;
    END
  END wq_addr[5]
  PIN wq_addr[60]
    DIRECTION OUTPUT ;
    USE SIGNAL ;
    PORT
      LAYER M5 ;
        RECT  26.112 0 26.136 0.084 ;
    END
  END wq_addr[60]
  PIN wq_addr[61]
    DIRECTION OUTPUT ;
    USE SIGNAL ;
    PORT
      LAYER M5 ;
        RECT  26.544 0 26.568 0.084 ;
    END
  END wq_addr[61]
  PIN wq_addr[62]
    DIRECTION OUTPUT ;
    USE SIGNAL ;
    PORT
      LAYER M5 ;
        RECT  26.976 0 27 0.084 ;
    END
  END wq_addr[62]
  PIN wq_addr[63]
    DIRECTION OUTPUT ;
    USE SIGNAL ;
    PORT
      LAYER M5 ;
        RECT  27.408 0 27.432 0.084 ;
    END
  END wq_addr[63]
  PIN wq_addr[64]
    DIRECTION OUTPUT ;
    USE SIGNAL ;
    PORT
      LAYER M5 ;
        RECT  27.84 0 27.864 0.084 ;
    END
  END wq_addr[64]
  PIN wq_addr[65]
    DIRECTION OUTPUT ;
    USE SIGNAL ;
    PORT
      LAYER M5 ;
        RECT  28.272 0 28.296 0.084 ;
    END
  END wq_addr[65]
  PIN wq_addr[66]
    DIRECTION OUTPUT ;
    USE SIGNAL ;
    PORT
      LAYER M5 ;
        RECT  28.704 0 28.728 0.084 ;
    END
  END wq_addr[66]
  PIN wq_addr[67]
    DIRECTION OUTPUT ;
    USE SIGNAL ;
    PORT
      LAYER M5 ;
        RECT  29.136 0 29.16 0.084 ;
    END
  END wq_addr[67]
  PIN wq_addr[68]
    DIRECTION OUTPUT ;
    USE SIGNAL ;
    PORT
      LAYER M5 ;
        RECT  29.568 0 29.592 0.084 ;
    END
  END wq_addr[68]
  PIN wq_addr[69]
    DIRECTION OUTPUT ;
    USE SIGNAL ;
    PORT
      LAYER M5 ;
        RECT  30 0 30.024 0.084 ;
    END
  END wq_addr[69]
  PIN wq_addr[6]
    DIRECTION OUTPUT ;
    USE SIGNAL ;
    PORT
      LAYER M5 ;
        RECT  2.784 0 2.808 0.084 ;
    END
  END wq_addr[6]
  PIN wq_addr[70]
    DIRECTION OUTPUT ;
    USE SIGNAL ;
    PORT
      LAYER M5 ;
        RECT  30.432 0 30.456 0.084 ;
    END
  END wq_addr[70]
  PIN wq_addr[71]
    DIRECTION OUTPUT ;
    USE SIGNAL ;
    PORT
      LAYER M5 ;
        RECT  30.864 0 30.888 0.084 ;
    END
  END wq_addr[71]
  PIN wq_addr[72]
    DIRECTION OUTPUT ;
    USE SIGNAL ;
    PORT
      LAYER M5 ;
        RECT  31.296 0 31.32 0.084 ;
    END
  END wq_addr[72]
  PIN wq_addr[73]
    DIRECTION OUTPUT ;
    USE SIGNAL ;
    PORT
      LAYER M5 ;
        RECT  31.728 0 31.752 0.084 ;
    END
  END wq_addr[73]
  PIN wq_addr[74]
    DIRECTION OUTPUT ;
    USE SIGNAL ;
    PORT
      LAYER M5 ;
        RECT  32.16 0 32.184 0.084 ;
    END
  END wq_addr[74]
  PIN wq_addr[75]
    DIRECTION OUTPUT ;
    USE SIGNAL ;
    PORT
      LAYER M5 ;
        RECT  32.592 0 32.616 0.084 ;
    END
  END wq_addr[75]
  PIN wq_addr[76]
    DIRECTION OUTPUT ;
    USE SIGNAL ;
    PORT
      LAYER M5 ;
        RECT  33.024 0 33.048 0.084 ;
    END
  END wq_addr[76]
  PIN wq_addr[77]
    DIRECTION OUTPUT ;
    USE SIGNAL ;
    PORT
      LAYER M5 ;
        RECT  33.456 0 33.48 0.084 ;
    END
  END wq_addr[77]
  PIN wq_addr[78]
    DIRECTION OUTPUT ;
    USE SIGNAL ;
    PORT
      LAYER M5 ;
        RECT  33.888 0 33.912 0.084 ;
    END
  END wq_addr[78]
  PIN wq_addr[79]
    DIRECTION OUTPUT ;
    USE SIGNAL ;
    PORT
      LAYER M5 ;
        RECT  34.32 0 34.344 0.084 ;
    END
  END wq_addr[79]
  PIN wq_addr[7]
    DIRECTION OUTPUT ;
    USE SIGNAL ;
    PORT
      LAYER M5 ;
        RECT  3.216 0 3.24 0.084 ;
    END
  END wq_addr[7]
  PIN wq_addr[80]
    DIRECTION OUTPUT ;
    USE SIGNAL ;
    PORT
      LAYER M5 ;
        RECT  34.752 0 34.776 0.084 ;
    END
  END wq_addr[80]
  PIN wq_addr[81]
    DIRECTION OUTPUT ;
    USE SIGNAL ;
    PORT
      LAYER M5 ;
        RECT  35.184 0 35.208 0.084 ;
    END
  END wq_addr[81]
  PIN wq_addr[82]
    DIRECTION OUTPUT ;
    USE SIGNAL ;
    PORT
      LAYER M5 ;
        RECT  35.616 0 35.64 0.084 ;
    END
  END wq_addr[82]
  PIN wq_addr[83]
    DIRECTION OUTPUT ;
    USE SIGNAL ;
    PORT
      LAYER M5 ;
        RECT  36.048 0 36.072 0.084 ;
    END
  END wq_addr[83]
  PIN wq_addr[84]
    DIRECTION OUTPUT ;
    USE SIGNAL ;
    PORT
      LAYER M5 ;
        RECT  36.48 0 36.504 0.084 ;
    END
  END wq_addr[84]
  PIN wq_addr[85]
    DIRECTION OUTPUT ;
    USE SIGNAL ;
    PORT
      LAYER M5 ;
        RECT  36.912 0 36.936 0.084 ;
    END
  END wq_addr[85]
  PIN wq_addr[86]
    DIRECTION OUTPUT ;
    USE SIGNAL ;
    PORT
      LAYER M5 ;
        RECT  37.344 0 37.368 0.084 ;
    END
  END wq_addr[86]
  PIN wq_addr[87]
    DIRECTION OUTPUT ;
    USE SIGNAL ;
    PORT
      LAYER M5 ;
        RECT  37.776 0 37.8 0.084 ;
    END
  END wq_addr[87]
  PIN wq_addr[88]
    DIRECTION OUTPUT ;
    USE SIGNAL ;
    PORT
      LAYER M5 ;
        RECT  38.208 0 38.232 0.084 ;
    END
  END wq_addr[88]
  PIN wq_addr[89]
    DIRECTION OUTPUT ;
    USE SIGNAL ;
    PORT
      LAYER M5 ;
        RECT  38.64 0 38.664 0.084 ;
    END
  END wq_addr[89]
  PIN wq_addr[8]
    DIRECTION OUTPUT ;
    USE SIGNAL ;
    PORT
      LAYER M5 ;
        RECT  3.648 0 3.672 0.084 ;
    END
  END wq_addr[8]
  PIN wq_addr[90]
    DIRECTION OUTPUT ;
    USE SIGNAL ;
    PORT
      LAYER M5 ;
        RECT  39.072 0 39.096 0.084 ;
    END
  END wq_addr[90]
  PIN wq_addr[91]
    DIRECTION OUTPUT ;
    USE SIGNAL ;
    PORT
      LAYER M5 ;
        RECT  39.504 0 39.528 0.084 ;
    END
  END wq_addr[91]
  PIN wq_addr[92]
    DIRECTION OUTPUT ;
    USE SIGNAL ;
    PORT
      LAYER M5 ;
        RECT  39.936 0 39.96 0.084 ;
    END
  END wq_addr[92]
  PIN wq_addr[93]
    DIRECTION OUTPUT ;
    USE SIGNAL ;
    PORT
      LAYER M5 ;
        RECT  40.368 0 40.392 0.084 ;
    END
  END wq_addr[93]
  PIN wq_addr[94]
    DIRECTION OUTPUT ;
    USE SIGNAL ;
    PORT
      LAYER M5 ;
        RECT  40.8 0 40.824 0.084 ;
    END
  END wq_addr[94]
  PIN wq_addr[95]
    DIRECTION OUTPUT ;
    USE SIGNAL ;
    PORT
      LAYER M5 ;
        RECT  41.232 0 41.256 0.084 ;
    END
  END wq_addr[95]
  PIN wq_addr[96]
    DIRECTION OUTPUT ;
    USE SIGNAL ;
    PORT
      LAYER M5 ;
        RECT  41.664 0 41.688 0.084 ;
    END
  END wq_addr[96]
  PIN wq_addr[97]
    DIRECTION OUTPUT ;
    USE SIGNAL ;
    PORT
      LAYER M5 ;
        RECT  42.096 0 42.12 0.084 ;
    END
  END wq_addr[97]
  PIN wq_addr[98]
    DIRECTION OUTPUT ;
    USE SIGNAL ;
    PORT
      LAYER M5 ;
        RECT  42.528 0 42.552 0.084 ;
    END
  END wq_addr[98]
  PIN wq_addr[99]
    DIRECTION OUTPUT ;
    USE SIGNAL ;
    PORT
      LAYER M5 ;
        RECT  42.96 0 42.984 0.084 ;
    END
  END wq_addr[99]
  PIN wq_addr[9]
    DIRECTION OUTPUT ;
    USE SIGNAL ;
    PORT
      LAYER M5 ;
        RECT  4.08 0 4.104 0.084 ;
    END
  END wq_addr[9]
  PIN wq_mask[0]
    DIRECTION OUTPUT ;
    USE SIGNAL ;
    PORT
      LAYER M5 ;
        RECT  55.488 0 55.512 0.084 ;
    END
  END wq_mask[0]
  PIN wq_mask[10]
    DIRECTION OUTPUT ;
    USE SIGNAL ;
    PORT
      LAYER M5 ;
        RECT  59.808 0 59.832 0.084 ;
    END
  END wq_mask[10]
  PIN wq_mask[11]
    DIRECTION OUTPUT ;
    USE SIGNAL ;
    PORT
      LAYER M5 ;
        RECT  60.24 0 60.264 0.084 ;
    END
  END wq_mask[11]
  PIN wq_mask[12]
    DIRECTION OUTPUT ;
    USE SIGNAL ;
    PORT
      LAYER M5 ;
        RECT  60.672 0 60.696 0.084 ;
    END
  END wq_mask[12]
  PIN wq_mask[13]
    DIRECTION OUTPUT ;
    USE SIGNAL ;
    PORT
      LAYER M5 ;
        RECT  61.104 0 61.128 0.084 ;
    END
  END wq_mask[13]
  PIN wq_mask[14]
    DIRECTION OUTPUT ;
    USE SIGNAL ;
    PORT
      LAYER M5 ;
        RECT  61.536 0 61.56 0.084 ;
    END
  END wq_mask[14]
  PIN wq_mask[15]
    DIRECTION OUTPUT ;
    USE SIGNAL ;
    PORT
      LAYER M5 ;
        RECT  61.968 0 61.992 0.084 ;
    END
  END wq_mask[15]
  PIN wq_mask[16]
    DIRECTION OUTPUT ;
    USE SIGNAL ;
    PORT
      LAYER M5 ;
        RECT  62.4 0 62.424 0.084 ;
    END
  END wq_mask[16]
  PIN wq_mask[17]
    DIRECTION OUTPUT ;
    USE SIGNAL ;
    PORT
      LAYER M5 ;
        RECT  62.832 0 62.856 0.084 ;
    END
  END wq_mask[17]
  PIN wq_mask[18]
    DIRECTION OUTPUT ;
    USE SIGNAL ;
    PORT
      LAYER M5 ;
        RECT  63.264 0 63.288 0.084 ;
    END
  END wq_mask[18]
  PIN wq_mask[19]
    DIRECTION OUTPUT ;
    USE SIGNAL ;
    PORT
      LAYER M5 ;
        RECT  63.696 0 63.72 0.084 ;
    END
  END wq_mask[19]
  PIN wq_mask[1]
    DIRECTION OUTPUT ;
    USE SIGNAL ;
    PORT
      LAYER M5 ;
        RECT  55.92 0 55.944 0.084 ;
    END
  END wq_mask[1]
  PIN wq_mask[20]
    DIRECTION OUTPUT ;
    USE SIGNAL ;
    PORT
      LAYER M5 ;
        RECT  64.128 0 64.152 0.084 ;
    END
  END wq_mask[20]
  PIN wq_mask[21]
    DIRECTION OUTPUT ;
    USE SIGNAL ;
    PORT
      LAYER M5 ;
        RECT  64.56 0 64.584 0.084 ;
    END
  END wq_mask[21]
  PIN wq_mask[22]
    DIRECTION OUTPUT ;
    USE SIGNAL ;
    PORT
      LAYER M5 ;
        RECT  64.992 0 65.016 0.084 ;
    END
  END wq_mask[22]
  PIN wq_mask[23]
    DIRECTION OUTPUT ;
    USE SIGNAL ;
    PORT
      LAYER M5 ;
        RECT  65.424 0 65.448 0.084 ;
    END
  END wq_mask[23]
  PIN wq_mask[24]
    DIRECTION OUTPUT ;
    USE SIGNAL ;
    PORT
      LAYER M5 ;
        RECT  65.856 0 65.88 0.084 ;
    END
  END wq_mask[24]
  PIN wq_mask[25]
    DIRECTION OUTPUT ;
    USE SIGNAL ;
    PORT
      LAYER M5 ;
        RECT  66.288 0 66.312 0.084 ;
    END
  END wq_mask[25]
  PIN wq_mask[26]
    DIRECTION OUTPUT ;
    USE SIGNAL ;
    PORT
      LAYER M5 ;
        RECT  66.72 0 66.744 0.084 ;
    END
  END wq_mask[26]
  PIN wq_mask[27]
    DIRECTION OUTPUT ;
    USE SIGNAL ;
    PORT
      LAYER M5 ;
        RECT  67.152 0 67.176 0.084 ;
    END
  END wq_mask[27]
  PIN wq_mask[28]
    DIRECTION OUTPUT ;
    USE SIGNAL ;
    PORT
      LAYER M5 ;
        RECT  67.584 0 67.608 0.084 ;
    END
  END wq_mask[28]
  PIN wq_mask[29]
    DIRECTION OUTPUT ;
    USE SIGNAL ;
    PORT
      LAYER M5 ;
        RECT  68.016 0 68.04 0.084 ;
    END
  END wq_mask[29]
  PIN wq_mask[2]
    DIRECTION OUTPUT ;
    USE SIGNAL ;
    PORT
      LAYER M5 ;
        RECT  56.352 0 56.376 0.084 ;
    END
  END wq_mask[2]
  PIN wq_mask[30]
    DIRECTION OUTPUT ;
    USE SIGNAL ;
    PORT
      LAYER M5 ;
        RECT  68.448 0 68.472 0.084 ;
    END
  END wq_mask[30]
  PIN wq_mask[31]
    DIRECTION OUTPUT ;
    USE SIGNAL ;
    PORT
      LAYER M5 ;
        RECT  68.88 0 68.904 0.084 ;
    END
  END wq_mask[31]
  PIN wq_mask[32]
    DIRECTION OUTPUT ;
    USE SIGNAL ;
    PORT
      LAYER M5 ;
        RECT  69.312 0 69.336 0.084 ;
    END
  END wq_mask[32]
  PIN wq_mask[33]
    DIRECTION OUTPUT ;
    USE SIGNAL ;
    PORT
      LAYER M5 ;
        RECT  69.744 0 69.768 0.084 ;
    END
  END wq_mask[33]
  PIN wq_mask[34]
    DIRECTION OUTPUT ;
    USE SIGNAL ;
    PORT
      LAYER M5 ;
        RECT  70.176 0 70.2 0.084 ;
    END
  END wq_mask[34]
  PIN wq_mask[35]
    DIRECTION OUTPUT ;
    USE SIGNAL ;
    PORT
      LAYER M5 ;
        RECT  70.608 0 70.632 0.084 ;
    END
  END wq_mask[35]
  PIN wq_mask[36]
    DIRECTION OUTPUT ;
    USE SIGNAL ;
    PORT
      LAYER M5 ;
        RECT  71.04 0 71.064 0.084 ;
    END
  END wq_mask[36]
  PIN wq_mask[37]
    DIRECTION OUTPUT ;
    USE SIGNAL ;
    PORT
      LAYER M5 ;
        RECT  71.472 0 71.496 0.084 ;
    END
  END wq_mask[37]
  PIN wq_mask[38]
    DIRECTION OUTPUT ;
    USE SIGNAL ;
    PORT
      LAYER M5 ;
        RECT  71.904 0 71.928 0.084 ;
    END
  END wq_mask[38]
  PIN wq_mask[39]
    DIRECTION OUTPUT ;
    USE SIGNAL ;
    PORT
      LAYER M5 ;
        RECT  72.336 0 72.36 0.084 ;
    END
  END wq_mask[39]
  PIN wq_mask[3]
    DIRECTION OUTPUT ;
    USE SIGNAL ;
    PORT
      LAYER M5 ;
        RECT  56.784 0 56.808 0.084 ;
    END
  END wq_mask[3]
  PIN wq_mask[40]
    DIRECTION OUTPUT ;
    USE SIGNAL ;
    PORT
      LAYER M5 ;
        RECT  72.768 0 72.792 0.084 ;
    END
  END wq_mask[40]
  PIN wq_mask[41]
    DIRECTION OUTPUT ;
    USE SIGNAL ;
    PORT
      LAYER M5 ;
        RECT  73.2 0 73.224 0.084 ;
    END
  END wq_mask[41]
  PIN wq_mask[42]
    DIRECTION OUTPUT ;
    USE SIGNAL ;
    PORT
      LAYER M5 ;
        RECT  73.632 0 73.656 0.084 ;
    END
  END wq_mask[42]
  PIN wq_mask[43]
    DIRECTION OUTPUT ;
    USE SIGNAL ;
    PORT
      LAYER M5 ;
        RECT  74.064 0 74.088 0.084 ;
    END
  END wq_mask[43]
  PIN wq_mask[44]
    DIRECTION OUTPUT ;
    USE SIGNAL ;
    PORT
      LAYER M5 ;
        RECT  74.496 0 74.52 0.084 ;
    END
  END wq_mask[44]
  PIN wq_mask[45]
    DIRECTION OUTPUT ;
    USE SIGNAL ;
    PORT
      LAYER M5 ;
        RECT  74.928 0 74.952 0.084 ;
    END
  END wq_mask[45]
  PIN wq_mask[46]
    DIRECTION OUTPUT ;
    USE SIGNAL ;
    PORT
      LAYER M5 ;
        RECT  75.36 0 75.384 0.084 ;
    END
  END wq_mask[46]
  PIN wq_mask[47]
    DIRECTION OUTPUT ;
    USE SIGNAL ;
    PORT
      LAYER M5 ;
        RECT  75.792 0 75.816 0.084 ;
    END
  END wq_mask[47]
  PIN wq_mask[48]
    DIRECTION OUTPUT ;
    USE SIGNAL ;
    PORT
      LAYER M5 ;
        RECT  76.224 0 76.248 0.084 ;
    END
  END wq_mask[48]
  PIN wq_mask[49]
    DIRECTION OUTPUT ;
    USE SIGNAL ;
    PORT
      LAYER M5 ;
        RECT  76.656 0 76.68 0.084 ;
    END
  END wq_mask[49]
  PIN wq_mask[4]
    DIRECTION OUTPUT ;
    USE SIGNAL ;
    PORT
      LAYER M5 ;
        RECT  57.216 0 57.24 0.084 ;
    END
  END wq_mask[4]
  PIN wq_mask[50]
    DIRECTION OUTPUT ;
    USE SIGNAL ;
    PORT
      LAYER M5 ;
        RECT  77.088 0 77.112 0.084 ;
    END
  END wq_mask[50]
  PIN wq_mask[51]
    DIRECTION OUTPUT ;
    USE SIGNAL ;
    PORT
      LAYER M5 ;
        RECT  77.52 0 77.544 0.084 ;
    END
  END wq_mask[51]
  PIN wq_mask[52]
    DIRECTION OUTPUT ;
    USE SIGNAL ;
    PORT
      LAYER M5 ;
        RECT  77.952 0 77.976 0.084 ;
    END
  END wq_mask[52]
  PIN wq_mask[53]
    DIRECTION OUTPUT ;
    USE SIGNAL ;
    PORT
      LAYER M5 ;
        RECT  78.384 0 78.408 0.084 ;
    END
  END wq_mask[53]
  PIN wq_mask[54]
    DIRECTION OUTPUT ;
    USE SIGNAL ;
    PORT
      LAYER M5 ;
        RECT  78.816 0 78.84 0.084 ;
    END
  END wq_mask[54]
  PIN wq_mask[55]
    DIRECTION OUTPUT ;
    USE SIGNAL ;
    PORT
      LAYER M5 ;
        RECT  79.248 0 79.272 0.084 ;
    END
  END wq_mask[55]
  PIN wq_mask[56]
    DIRECTION OUTPUT ;
    USE SIGNAL ;
    PORT
      LAYER M5 ;
        RECT  79.68 0 79.704 0.084 ;
    END
  END wq_mask[56]
  PIN wq_mask[57]
    DIRECTION OUTPUT ;
    USE SIGNAL ;
    PORT
      LAYER M5 ;
        RECT  80.112 0 80.136 0.084 ;
    END
  END wq_mask[57]
  PIN wq_mask[58]
    DIRECTION OUTPUT ;
    USE SIGNAL ;
    PORT
      LAYER M5 ;
        RECT  80.544 0 80.568 0.084 ;
    END
  END wq_mask[58]
  PIN wq_mask[59]
    DIRECTION OUTPUT ;
    USE SIGNAL ;
    PORT
      LAYER M5 ;
        RECT  80.976 0 81 0.084 ;
    END
  END wq_mask[59]
  PIN wq_mask[5]
    DIRECTION OUTPUT ;
    USE SIGNAL ;
    PORT
      LAYER M5 ;
        RECT  57.648 0 57.672 0.084 ;
    END
  END wq_mask[5]
  PIN wq_mask[60]
    DIRECTION OUTPUT ;
    USE SIGNAL ;
    PORT
      LAYER M5 ;
        RECT  81.408 0 81.432 0.084 ;
    END
  END wq_mask[60]
  PIN wq_mask[61]
    DIRECTION OUTPUT ;
    USE SIGNAL ;
    PORT
      LAYER M5 ;
        RECT  81.84 0 81.864 0.084 ;
    END
  END wq_mask[61]
  PIN wq_mask[62]
    DIRECTION OUTPUT ;
    USE SIGNAL ;
    PORT
      LAYER M5 ;
        RECT  82.272 0 82.296 0.084 ;
    END
  END wq_mask[62]
  PIN wq_mask[63]
    DIRECTION OUTPUT ;
    USE SIGNAL ;
    PORT
      LAYER M5 ;
        RECT  82.704 0 82.728 0.084 ;
    END
  END wq_mask[63]
  PIN wq_mask[6]
    DIRECTION OUTPUT ;
    USE SIGNAL ;
    PORT
      LAYER M5 ;
        RECT  58.08 0 58.104 0.084 ;
    END
  END wq_mask[6]
  PIN wq_mask[7]
    DIRECTION OUTPUT ;
    USE SIGNAL ;
    PORT
      LAYER M5 ;
        RECT  58.512 0 58.536 0.084 ;
    END
  END wq_mask[7]
  PIN wq_mask[8]
    DIRECTION OUTPUT ;
    USE SIGNAL ;
    PORT
      LAYER M5 ;
        RECT  58.944 0 58.968 0.084 ;
    END
  END wq_mask[8]
  PIN wq_mask[9]
    DIRECTION OUTPUT ;
    USE SIGNAL ;
    PORT
      LAYER M5 ;
        RECT  59.376 0 59.4 0.084 ;
    END
  END wq_mask[9]
  PIN wq_v[0]
    DIRECTION OUTPUT ;
    USE SIGNAL ;
    PORT
      LAYER M5 ;
        RECT  83.136 0 83.16 0.084 ;
    END
  END wq_v[0]
  PIN wq_v[1]
    DIRECTION OUTPUT ;
    USE SIGNAL ;
    PORT
      LAYER M5 ;
        RECT  83.568 0 83.592 0.084 ;
    END
  END wq_v[1]
  PIN wq_v[2]
    DIRECTION OUTPUT ;
    USE SIGNAL ;
    PORT
      LAYER M5 ;
        RECT  84 0 84.024 0.084 ;
    END
  END wq_v[2]
  PIN wq_v[3]
    DIRECTION OUTPUT ;
    USE SIGNAL ;
    PORT
      LAYER M5 ;
        RECT  84.432 0 84.456 0.084 ;
    END
  END wq_v[3]
  PIN wq_v[4]
    DIRECTION OUTPUT ;
    USE SIGNAL ;
    PORT
      LAYER M5 ;
        RECT  84.864 0 84.888 0.084 ;
    END
  END wq_v[4]
  PIN wq_v[5]
    DIRECTION OUTPUT ;
    USE SIGNAL ;
    PORT
      LAYER M5 ;
        RECT  85.296 0 85.32 0.084 ;
    END
  END wq_v[5]
  PIN wq_v[6]
    DIRECTION OUTPUT ;
    USE SIGNAL ;
    PORT
      LAYER M5 ;
        RECT  85.728 0 85.752 0.084 ;
    END
  END wq_v[6]
  PIN wq_v[7]
    DIRECTION OUTPUT ;
    USE SIGNAL ;
    PORT
      LAYER M5 ;
        RECT  86.16 0 86.184 0.084 ;
    END
  END wq_v[7]
  PIN wsel[0]
    DIRECTION OUTPUT ;
    USE SIGNAL ;
    PORT
      LAYER M4 ;
        RECT  86.316 84.816 86.4 84.84 ;
    END
  END wsel[0]
  PIN wsel[1]
    DIRECTION OUTPUT ;
    USE SIGNAL ;
    PORT
      LAYER M4 ;
        RECT  86.316 85.44 86.4 85.464 ;
    END
  END wsel[1]
  PIN wsel[2]
    DIRECTION OUTPUT ;
    USE SIGNAL ;
    PORT
      LAYER M4 ;
        RECT  86.316 86.064 86.4 86.088 ;
    END
  END wsel[2]
  PIN VDD
    DIRECTION INOUT ;
    USE POWER ;
    PORT
      LAYER M5 ;
        RECT  83.592 2.151 83.712 84.249 ;
        RECT  78.192 2.151 78.312 84.249 ;
        RECT  72.792 2.151 72.912 84.249 ;
        RECT  67.392 2.151 67.512 84.249 ;
        RECT  61.992 2.151 62.112 84.249 ;
        RECT  56.592 2.151 56.712 84.249 ;
        RECT  51.192 2.151 51.312 84.249 ;
        RECT  45.792 2.151 45.912 84.249 ;
        RECT  40.392 2.151 40.512 84.249 ;
        RECT  34.992 2.151 35.112 84.249 ;
        RECT  29.592 2.151 29.712 84.249 ;
        RECT  24.192 2.151 24.312 84.249 ;
        RECT  18.792 2.151 18.912 84.249 ;
        RECT  13.392 2.151 13.512 84.249 ;
        RECT  7.992 2.151 8.112 84.249 ;
        RECT  2.592 2.151 2.712 84.249 ;
    END
  END VDD
  PIN VSS
    DIRECTION INOUT ;
    USE GROUND ;
    PORT
      LAYER M5 ;
        RECT  83.4 2.137 83.52 84.263 ;
        RECT  78 2.137 78.12 84.263 ;
        RECT  72.6 2.137 72.72 84.263 ;
        RECT  67.2 2.137 67.32 84.263 ;
        RECT  61.8 2.137 61.92 84.263 ;
        RECT  56.4 2.137 56.52 84.263 ;
        RECT  51 2.137 51.12 84.263 ;
        RECT  45.6 2.137 45.72 84.263 ;
        RECT  40.2 2.137 40.32 84.263 ;
        RECT  34.8 2.137 34.92 84.263 ;
        RECT  29.4 2.137 29.52 84.263 ;
        RECT  24 2.137 24.12 84.263 ;
        RECT  18.6 2.137 18.72 84.263 ;
        RECT  13.2 2.137 13.32 84.263 ;
        RECT  7.8 2.137 7.92 84.263 ;
        RECT  2.4 2.137 2.52 84.263 ;
    END
  END VSS
  # OT_OBS_CLOSED layer=M5 d_um=1.536 added=202
  OBS
    LAYER RVTN ;
     RECT  2.16 2.16 84.24 2.295 ;
     RECT  2.16 2.565 84.24 2.835 ;
     RECT  2.16 3.105 84.24 3.375 ;
     RECT  2.16 3.645 84.24 3.915 ;
     RECT  2.16 4.185 84.24 4.455 ;
     RECT  2.16 4.725 84.24 4.995 ;
     RECT  2.16 5.265 84.24 5.535 ;
     RECT  2.16 5.805 84.24 6.075 ;
     RECT  2.16 6.345 84.24 6.615 ;
     RECT  2.16 6.885 84.24 7.155 ;
     RECT  2.16 7.425 84.24 7.695 ;
     RECT  2.16 7.965 84.24 8.235 ;
     RECT  2.16 8.505 84.24 8.775 ;
     RECT  2.16 9.045 84.24 9.315 ;
     RECT  2.16 9.585 84.24 9.855 ;
     RECT  2.16 10.125 84.24 10.395 ;
     RECT  2.16 10.665 84.24 10.935 ;
     RECT  2.16 11.205 84.24 11.475 ;
     RECT  2.16 11.745 84.24 12.015 ;
     RECT  2.16 12.285 84.24 12.555 ;
     RECT  2.16 12.825 84.24 13.095 ;
     RECT  2.16 13.365 84.24 13.635 ;
     RECT  2.16 13.905 84.24 14.175 ;
     RECT  2.16 14.445 84.24 14.715 ;
     RECT  2.16 14.985 84.24 15.255 ;
     RECT  2.16 15.525 84.24 15.795 ;
     RECT  2.16 16.065 84.24 16.335 ;
     RECT  2.16 16.605 84.24 16.875 ;
     RECT  2.16 17.145 84.24 17.415 ;
     RECT  2.16 17.685 84.24 17.955 ;
     RECT  2.16 18.225 84.24 18.495 ;
     RECT  2.16 18.765 84.24 19.035 ;
     RECT  2.16 19.305 84.24 19.575 ;
     RECT  2.16 19.845 84.24 20.115 ;
     RECT  2.16 20.385 84.24 20.655 ;
     RECT  2.16 20.925 84.24 21.195 ;
     RECT  2.16 21.465 84.24 21.735 ;
     RECT  2.16 22.005 84.24 22.275 ;
     RECT  2.16 22.545 84.24 22.815 ;
     RECT  2.16 23.085 84.24 23.355 ;
     RECT  2.16 23.625 84.24 23.895 ;
     RECT  2.16 24.165 84.24 24.435 ;
     RECT  2.16 24.705 84.24 24.975 ;
     RECT  2.16 25.245 84.24 25.515 ;
     RECT  2.16 25.785 84.24 26.055 ;
     RECT  2.16 26.325 84.24 26.595 ;
     RECT  2.16 26.865 84.24 27.135 ;
     RECT  2.16 27.405 84.24 27.675 ;
     RECT  2.16 27.945 84.24 28.215 ;
     RECT  2.16 28.485 84.24 28.755 ;
     RECT  2.16 29.025 84.24 29.295 ;
     RECT  2.16 29.565 84.24 29.835 ;
     RECT  2.16 30.105 84.24 30.375 ;
     RECT  2.16 30.645 84.24 30.915 ;
     RECT  2.16 31.185 84.24 31.455 ;
     RECT  2.16 31.725 84.24 31.995 ;
     RECT  2.16 32.265 84.24 32.535 ;
     RECT  2.16 32.805 84.24 33.075 ;
     RECT  2.16 33.345 84.24 33.615 ;
     RECT  2.16 33.885 84.24 34.155 ;
     RECT  2.16 34.425 84.24 34.695 ;
     RECT  2.16 34.965 84.24 35.235 ;
     RECT  2.16 35.505 84.24 35.775 ;
     RECT  2.16 36.045 84.24 36.315 ;
     RECT  2.16 36.585 84.24 36.855 ;
     RECT  2.16 37.125 84.24 37.395 ;
     RECT  2.16 37.665 84.24 37.935 ;
     RECT  2.16 38.205 84.24 38.475 ;
     RECT  2.16 38.745 84.24 39.015 ;
     RECT  2.16 39.285 84.24 39.555 ;
     RECT  2.16 39.825 84.24 40.095 ;
     RECT  2.16 40.365 84.24 40.635 ;
     RECT  2.16 40.905 84.24 41.175 ;
     RECT  2.16 41.445 84.24 41.715 ;
     RECT  2.16 41.985 84.24 42.255 ;
     RECT  2.16 42.525 84.24 42.795 ;
     RECT  2.16 43.065 84.24 43.335 ;
     RECT  2.16 43.605 84.24 43.875 ;
     RECT  2.16 44.145 84.24 44.415 ;
     RECT  2.16 44.685 84.24 44.955 ;
     RECT  2.16 45.225 84.24 45.495 ;
     RECT  2.16 45.765 84.24 46.035 ;
     RECT  2.16 46.305 84.24 46.575 ;
     RECT  2.16 46.845 84.24 47.115 ;
     RECT  2.16 47.385 84.24 47.655 ;
     RECT  2.16 47.925 84.24 48.195 ;
     RECT  2.16 48.465 84.24 48.735 ;
     RECT  2.16 49.005 84.24 49.275 ;
     RECT  2.16 49.545 84.24 49.815 ;
     RECT  2.16 50.085 84.24 50.355 ;
     RECT  2.16 50.625 84.24 50.895 ;
     RECT  2.16 51.165 84.24 51.435 ;
     RECT  2.16 51.705 84.24 51.975 ;
     RECT  2.16 52.245 84.24 52.515 ;
     RECT  2.16 52.785 84.24 53.055 ;
     RECT  2.16 53.325 84.24 53.595 ;
     RECT  2.16 53.865 84.24 54.135 ;
     RECT  2.16 54.405 84.24 54.675 ;
     RECT  2.16 54.945 84.24 55.215 ;
     RECT  2.16 55.485 84.24 55.755 ;
     RECT  2.16 56.025 84.24 56.295 ;
     RECT  2.16 56.565 84.24 56.835 ;
     RECT  2.16 57.105 84.24 57.375 ;
     RECT  2.16 57.645 84.24 57.915 ;
     RECT  2.16 58.185 84.24 58.455 ;
     RECT  2.16 58.725 84.24 58.995 ;
     RECT  2.16 59.265 84.24 59.535 ;
     RECT  2.16 59.805 84.24 60.075 ;
     RECT  2.16 60.345 84.24 60.615 ;
     RECT  2.16 60.885 84.24 61.155 ;
     RECT  2.16 61.425 84.24 61.695 ;
     RECT  2.16 61.965 84.24 62.235 ;
     RECT  2.16 62.505 84.24 62.775 ;
     RECT  2.16 63.045 84.24 63.315 ;
     RECT  2.16 63.585 84.24 63.855 ;
     RECT  2.16 64.125 84.24 64.395 ;
     RECT  2.16 64.665 84.24 64.935 ;
     RECT  2.16 65.205 84.24 65.475 ;
     RECT  2.16 65.745 84.24 66.015 ;
     RECT  2.16 66.285 84.24 66.555 ;
     RECT  2.16 66.825 84.24 67.095 ;
     RECT  2.16 67.365 84.24 67.635 ;
     RECT  2.16 67.905 84.24 68.175 ;
     RECT  2.16 68.445 84.24 68.715 ;
     RECT  2.16 68.985 84.24 69.255 ;
     RECT  2.16 69.525 84.24 69.795 ;
     RECT  2.16 70.065 84.24 70.335 ;
     RECT  2.16 70.605 84.24 70.875 ;
     RECT  2.16 71.145 84.24 71.415 ;
     RECT  2.16 71.685 84.24 71.955 ;
     RECT  2.16 72.225 84.24 72.495 ;
     RECT  2.16 72.765 84.24 73.035 ;
     RECT  2.16 73.305 84.24 73.575 ;
     RECT  2.16 73.845 84.24 74.115 ;
     RECT  2.16 74.385 84.24 74.655 ;
     RECT  2.16 74.925 84.24 75.195 ;
     RECT  2.16 75.465 84.24 75.735 ;
     RECT  2.16 76.005 84.24 76.275 ;
     RECT  2.16 76.545 84.24 76.815 ;
     RECT  2.16 77.085 84.24 77.355 ;
     RECT  2.16 77.625 84.24 77.895 ;
     RECT  2.16 78.165 84.24 78.435 ;
     RECT  2.16 78.705 84.24 78.975 ;
     RECT  2.16 79.245 84.24 79.515 ;
     RECT  2.16 79.785 84.24 80.055 ;
     RECT  2.16 80.325 84.24 80.595 ;
     RECT  2.16 80.865 84.24 81.135 ;
     RECT  2.16 81.405 84.24 81.675 ;
     RECT  2.16 81.945 84.24 82.215 ;
     RECT  2.16 82.485 84.24 82.755 ;
     RECT  2.16 83.025 84.24 83.295 ;
     RECT  2.16 83.565 84.24 83.835 ;
     RECT  2.16 84.105 84.24 84.24 ;
    LAYER RVTP ;
     RECT  2.16 2.295 84.24 2.565 ;
     RECT  2.16 2.835 84.24 3.105 ;
     RECT  2.16 3.375 84.24 3.645 ;
     RECT  2.16 3.915 84.24 4.185 ;
     RECT  2.16 4.455 84.24 4.725 ;
     RECT  2.16 4.995 84.24 5.265 ;
     RECT  2.16 5.535 84.24 5.805 ;
     RECT  2.16 6.075 84.24 6.345 ;
     RECT  2.16 6.615 84.24 6.885 ;
     RECT  2.16 7.155 84.24 7.425 ;
     RECT  2.16 7.695 84.24 7.965 ;
     RECT  2.16 8.235 84.24 8.505 ;
     RECT  2.16 8.775 84.24 9.045 ;
     RECT  2.16 9.315 84.24 9.585 ;
     RECT  2.16 9.855 84.24 10.125 ;
     RECT  2.16 10.395 84.24 10.665 ;
     RECT  2.16 10.935 84.24 11.205 ;
     RECT  2.16 11.475 84.24 11.745 ;
     RECT  2.16 12.015 84.24 12.285 ;
     RECT  2.16 12.555 84.24 12.825 ;
     RECT  2.16 13.095 84.24 13.365 ;
     RECT  2.16 13.635 84.24 13.905 ;
     RECT  2.16 14.175 84.24 14.445 ;
     RECT  2.16 14.715 84.24 14.985 ;
     RECT  2.16 15.255 84.24 15.525 ;
     RECT  2.16 15.795 84.24 16.065 ;
     RECT  2.16 16.335 84.24 16.605 ;
     RECT  2.16 16.875 84.24 17.145 ;
     RECT  2.16 17.415 84.24 17.685 ;
     RECT  2.16 17.955 84.24 18.225 ;
     RECT  2.16 18.495 84.24 18.765 ;
     RECT  2.16 19.035 84.24 19.305 ;
     RECT  2.16 19.575 84.24 19.845 ;
     RECT  2.16 20.115 84.24 20.385 ;
     RECT  2.16 20.655 84.24 20.925 ;
     RECT  2.16 21.195 84.24 21.465 ;
     RECT  2.16 21.735 84.24 22.005 ;
     RECT  2.16 22.275 84.24 22.545 ;
     RECT  2.16 22.815 84.24 23.085 ;
     RECT  2.16 23.355 84.24 23.625 ;
     RECT  2.16 23.895 84.24 24.165 ;
     RECT  2.16 24.435 84.24 24.705 ;
     RECT  2.16 24.975 84.24 25.245 ;
     RECT  2.16 25.515 84.24 25.785 ;
     RECT  2.16 26.055 84.24 26.325 ;
     RECT  2.16 26.595 84.24 26.865 ;
     RECT  2.16 27.135 84.24 27.405 ;
     RECT  2.16 27.675 84.24 27.945 ;
     RECT  2.16 28.215 84.24 28.485 ;
     RECT  2.16 28.755 84.24 29.025 ;
     RECT  2.16 29.295 84.24 29.565 ;
     RECT  2.16 29.835 84.24 30.105 ;
     RECT  2.16 30.375 84.24 30.645 ;
     RECT  2.16 30.915 84.24 31.185 ;
     RECT  2.16 31.455 84.24 31.725 ;
     RECT  2.16 31.995 84.24 32.265 ;
     RECT  2.16 32.535 84.24 32.805 ;
     RECT  2.16 33.075 84.24 33.345 ;
     RECT  2.16 33.615 84.24 33.885 ;
     RECT  2.16 34.155 84.24 34.425 ;
     RECT  2.16 34.695 84.24 34.965 ;
     RECT  2.16 35.235 84.24 35.505 ;
     RECT  2.16 35.775 84.24 36.045 ;
     RECT  2.16 36.315 84.24 36.585 ;
     RECT  2.16 36.855 84.24 37.125 ;
     RECT  2.16 37.395 84.24 37.665 ;
     RECT  2.16 37.935 84.24 38.205 ;
     RECT  2.16 38.475 84.24 38.745 ;
     RECT  2.16 39.015 84.24 39.285 ;
     RECT  2.16 39.555 84.24 39.825 ;
     RECT  2.16 40.095 84.24 40.365 ;
     RECT  2.16 40.635 84.24 40.905 ;
     RECT  2.16 41.175 84.24 41.445 ;
     RECT  2.16 41.715 84.24 41.985 ;
     RECT  2.16 42.255 84.24 42.525 ;
     RECT  2.16 42.795 84.24 43.065 ;
     RECT  2.16 43.335 84.24 43.605 ;
     RECT  2.16 43.875 84.24 44.145 ;
     RECT  2.16 44.415 84.24 44.685 ;
     RECT  2.16 44.955 84.24 45.225 ;
     RECT  2.16 45.495 84.24 45.765 ;
     RECT  2.16 46.035 84.24 46.305 ;
     RECT  2.16 46.575 84.24 46.845 ;
     RECT  2.16 47.115 84.24 47.385 ;
     RECT  2.16 47.655 84.24 47.925 ;
     RECT  2.16 48.195 84.24 48.465 ;
     RECT  2.16 48.735 84.24 49.005 ;
     RECT  2.16 49.275 84.24 49.545 ;
     RECT  2.16 49.815 84.24 50.085 ;
     RECT  2.16 50.355 84.24 50.625 ;
     RECT  2.16 50.895 84.24 51.165 ;
     RECT  2.16 51.435 84.24 51.705 ;
     RECT  2.16 51.975 84.24 52.245 ;
     RECT  2.16 52.515 84.24 52.785 ;
     RECT  2.16 53.055 84.24 53.325 ;
     RECT  2.16 53.595 84.24 53.865 ;
     RECT  2.16 54.135 84.24 54.405 ;
     RECT  2.16 54.675 84.24 54.945 ;
     RECT  2.16 55.215 84.24 55.485 ;
     RECT  2.16 55.755 84.24 56.025 ;
     RECT  2.16 56.295 84.24 56.565 ;
     RECT  2.16 56.835 84.24 57.105 ;
     RECT  2.16 57.375 84.24 57.645 ;
     RECT  2.16 57.915 84.24 58.185 ;
     RECT  2.16 58.455 84.24 58.725 ;
     RECT  2.16 58.995 84.24 59.265 ;
     RECT  2.16 59.535 84.24 59.805 ;
     RECT  2.16 60.075 84.24 60.345 ;
     RECT  2.16 60.615 84.24 60.885 ;
     RECT  2.16 61.155 84.24 61.425 ;
     RECT  2.16 61.695 84.24 61.965 ;
     RECT  2.16 62.235 84.24 62.505 ;
     RECT  2.16 62.775 84.24 63.045 ;
     RECT  2.16 63.315 84.24 63.585 ;
     RECT  2.16 63.855 84.24 64.125 ;
     RECT  2.16 64.395 84.24 64.665 ;
     RECT  2.16 64.935 84.24 65.205 ;
     RECT  2.16 65.475 84.24 65.745 ;
     RECT  2.16 66.015 84.24 66.285 ;
     RECT  2.16 66.555 84.24 66.825 ;
     RECT  2.16 67.095 84.24 67.365 ;
     RECT  2.16 67.635 84.24 67.905 ;
     RECT  2.16 68.175 84.24 68.445 ;
     RECT  2.16 68.715 84.24 68.985 ;
     RECT  2.16 69.255 84.24 69.525 ;
     RECT  2.16 69.795 84.24 70.065 ;
     RECT  2.16 70.335 84.24 70.605 ;
     RECT  2.16 70.875 84.24 71.145 ;
     RECT  2.16 71.415 84.24 71.685 ;
     RECT  2.16 71.955 84.24 72.225 ;
     RECT  2.16 72.495 84.24 72.765 ;
     RECT  2.16 73.035 84.24 73.305 ;
     RECT  2.16 73.575 84.24 73.845 ;
     RECT  2.16 74.115 84.24 74.385 ;
     RECT  2.16 74.655 84.24 74.925 ;
     RECT  2.16 75.195 84.24 75.465 ;
     RECT  2.16 75.735 84.24 76.005 ;
     RECT  2.16 76.275 84.24 76.545 ;
     RECT  2.16 76.815 84.24 77.085 ;
     RECT  2.16 77.355 84.24 77.625 ;
     RECT  2.16 77.895 84.24 78.165 ;
     RECT  2.16 78.435 84.24 78.705 ;
     RECT  2.16 78.975 84.24 79.245 ;
     RECT  2.16 79.515 84.24 79.785 ;
     RECT  2.16 80.055 84.24 80.325 ;
     RECT  2.16 80.595 84.24 80.865 ;
     RECT  2.16 81.135 84.24 81.405 ;
     RECT  2.16 81.675 84.24 81.945 ;
     RECT  2.16 82.215 84.24 82.485 ;
     RECT  2.16 82.755 84.24 83.025 ;
     RECT  2.16 83.295 84.24 83.565 ;
     RECT  2.16 83.835 84.24 84.105 ;
    LAYER M1 ;
     RECT  2.16 2.151 84.24 84.249 ;
    LAYER M2 ;
     RECT  0.067 74.016 0.103 74.034 ;
     RECT  0.031 80.1 0.103 80.118 ;
     RECT  0.031 81.306 0.103 81.324 ;
     RECT  0.031 70.578 0.131 70.596 ;
     RECT  0.103 74.016 0.139 74.682 ;
     RECT  0.103 79.722 0.175 80.118 ;
     RECT  0.139 74.016 0.203 75.384 ;
     RECT  0.067 2.268 2.16 2.286 ;
     RECT  0.031 5.076 2.16 5.094 ;
     RECT  0.103 17.082 2.16 17.1 ;
     RECT  0.103 28.458 2.16 28.476 ;
     RECT  0.103 38.178 2.16 38.196 ;
     RECT  0.103 39.87 2.16 39.888 ;
     RECT  0.203 74.016 2.16 74.034 ;
     RECT  0.203 75.366 2.16 75.384 ;
     RECT  0.103 78.102 2.16 78.12 ;
     RECT  0.823 78.948 2.16 78.966 ;
     RECT  0.175 79.722 2.16 80.154 ;
     RECT  0.103 81.216 2.16 81.324 ;
     RECT  2.16 2.151 4.711 84.249 ;
     RECT  4.711 2.151 4.847 84.906 ;
     RECT  16.771 1.152 16.907 1.17 ;
     RECT  31.459 1.152 31.559 1.17 ;
     RECT  35.383 1.152 35.555 1.17 ;
     RECT  39.379 1.152 39.479 1.17 ;
     RECT  40.675 1.152 40.811 1.17 ;
     RECT  4.847 2.151 42.115 84.249 ;
     RECT  42.115 2.106 42.503 84.249 ;
     RECT  42.503 2.151 48.199 84.249 ;
     RECT  48.199 2.106 49.307 84.249 ;
     RECT  49.307 2.151 79.843 84.249 ;
     RECT  79.843 2.151 79.979 84.906 ;
     RECT  79.979 2.151 81.427 84.249 ;
     RECT  81.427 2.106 81.923 84.249 ;
     RECT  81.923 2.151 84.24 84.249 ;
     RECT  84.24 81.378 84.407 83.754 ;
     RECT  84.24 2.304 84.443 4.518 ;
     RECT  84.24 27.18 84.911 28.98 ;
     RECT  84.24 29.736 84.911 41.814 ;
     RECT  84.24 5.742 84.947 7.758 ;
     RECT  84.911 27.18 84.947 27.9 ;
     RECT  84.911 29.736 84.947 41.004 ;
     RECT  84.24 66.06 84.947 71.1 ;
     RECT  84.443 4.086 85.091 4.518 ;
     RECT  84.947 32.202 85.127 40.464 ;
     RECT  84.24 56.034 85.199 61.524 ;
     RECT  84.947 67.302 85.199 69.822 ;
     RECT  85.091 4.086 85.343 4.374 ;
     RECT  85.343 4.356 85.487 4.374 ;
     RECT  84.947 5.742 85.487 7.218 ;
     RECT  84.24 8.676 85.487 11.7 ;
     RECT  84.24 12.456 85.487 14.706 ;
     RECT  84.24 15.462 85.487 17.676 ;
     RECT  84.24 18.468 85.487 18.486 ;
     RECT  84.24 19.242 85.487 23.346 ;
     RECT  84.24 24.102 85.487 26.424 ;
     RECT  84.947 27.882 85.487 27.9 ;
     RECT  84.947 29.736 85.487 30.978 ;
     RECT  85.127 32.202 85.487 39.78 ;
     RECT  84.24 42.696 85.487 43.524 ;
     RECT  84.24 44.856 85.487 55.278 ;
     RECT  85.199 56.034 85.487 57.294 ;
     RECT  85.199 58.5 85.487 61.524 ;
     RECT  84.24 62.28 85.487 65.304 ;
     RECT  84.947 66.06 85.487 66.078 ;
     RECT  85.199 67.302 85.487 67.32 ;
     RECT  85.199 68.616 85.487 69.822 ;
     RECT  84.947 71.082 85.487 71.1 ;
     RECT  84.24 71.856 85.487 74.106 ;
     RECT  84.24 76.086 85.487 76.734 ;
     RECT  84.24 77.796 85.487 80.352 ;
     RECT  84.407 81.378 85.487 82.512 ;
     RECT  85.487 22.086 85.523 23.346 ;
     RECT  84.911 28.962 85.523 28.98 ;
     RECT  85.487 54.108 85.523 55.278 ;
     RECT  85.487 60.966 85.523 61.524 ;
     RECT  85.487 73.386 85.523 74.106 ;
     RECT  85.487 81.756 85.523 82.512 ;
     RECT  84.443 2.304 85.559 3.294 ;
     RECT  84.407 83.574 85.559 83.754 ;
     RECT  85.559 2.304 86.171 2.322 ;
     RECT  85.559 3.186 86.279 3.294 ;
     RECT  85.487 5.742 86.279 6.3 ;
     RECT  85.523 73.512 86.279 74.106 ;
     RECT  85.559 83.574 86.279 83.592 ;
     RECT  86.279 3.186 86.315 3.204 ;
     RECT  86.279 5.742 86.315 5.76 ;
     RECT  85.487 9.666 86.315 9.684 ;
     RECT  85.487 17.082 86.315 17.676 ;
     RECT  85.523 22.086 86.315 22.734 ;
     RECT  84.911 41.796 86.315 41.814 ;
     RECT  85.487 42.696 86.315 43.326 ;
     RECT  85.487 47.862 86.315 48.456 ;
     RECT  85.523 54.108 86.315 54.126 ;
     RECT  85.523 61.506 86.315 61.524 ;
     RECT  86.279 73.512 86.315 73.53 ;
     RECT  84.24 75.006 86.315 75.024 ;
     RECT  85.487 79.722 86.315 80.352 ;
     RECT  85.523 81.756 86.315 82.476 ;
     RECT  86.315 82.458 86.387 82.476 ;
    LAYER M3 ;
     RECT  3.456 0.091 4.158 0.139 ;
     RECT  34.236 0.091 34.254 0.139 ;
     RECT  35.388 0.091 35.406 0.139 ;
     RECT  43.668 0.091 43.686 0.139 ;
     RECT  44.46 0.091 48.762 0.139 ;
     RECT  67.536 0.091 67.554 0.139 ;
     RECT  68.436 0.091 69.498 0.139 ;
     RECT  82.404 0.091 83.574 0.139 ;
     RECT  2.736 0.139 4.158 0.187 ;
     RECT  36.504 0.091 36.522 0.187 ;
     RECT  86.148 0.091 86.166 0.283 ;
     RECT  82.08 0.139 83.574 0.475 ;
     RECT  49.896 0.091 50.922 0.523 ;
     RECT  51.768 0.091 52.326 0.523 ;
     RECT  58.14 0.091 60.858 0.523 ;
     RECT  62.172 0.091 62.19 0.523 ;
     RECT  63.108 0.091 64.314 0.523 ;
     RECT  72.072 0.091 72.522 0.523 ;
     RECT  75.348 0.091 75.366 0.523 ;
     RECT  76.392 0.091 79.434 0.523 ;
     RECT  82.08 0.475 83.934 0.523 ;
     RECT  85.32 0.091 85.338 0.523 ;
     RECT  6.372 0.091 7.146 0.571 ;
     RECT  8.568 0.091 8.586 0.571 ;
     RECT  10.296 0.091 10.314 0.571 ;
     RECT  12.132 0.091 12.15 0.571 ;
     RECT  13.68 0.091 13.842 0.571 ;
     RECT  16.776 0.091 17.514 0.571 ;
     RECT  19.008 0.523 19.026 0.571 ;
     RECT  20.664 0.091 20.682 0.571 ;
     RECT  24.444 0.091 24.462 0.571 ;
     RECT  26.676 0.091 26.982 0.571 ;
     RECT  30.42 0.091 31.482 0.571 ;
     RECT  32.292 0.091 32.742 0.571 ;
     RECT  34.236 0.139 35.406 0.571 ;
     RECT  36.504 0.187 36.558 0.571 ;
     RECT  37.476 0.091 37.494 0.571 ;
     RECT  38.268 0.091 38.286 0.571 ;
     RECT  40.356 0.091 40.806 0.571 ;
     RECT  0.108 0.811 0.126 1.099 ;
     RECT  0.036 1.099 0.126 1.133 ;
     RECT  39.384 0.091 39.402 1.147 ;
     RECT  34.236 0.571 36.558 1.175 ;
     RECT  39.384 1.147 39.474 1.175 ;
     RECT  40.356 0.571 41.85 1.175 ;
     RECT  82.08 0.523 85.338 1.531 ;
     RECT  86.148 0.283 86.31 1.531 ;
     RECT  2.376 0.187 4.158 1.723 ;
     RECT  5.652 0.571 7.146 1.723 ;
     RECT  8.244 0.571 9.018 1.723 ;
     RECT  10.044 0.571 10.746 1.723 ;
     RECT  11.592 0.571 15.03 1.723 ;
     RECT  15.912 0.571 17.514 1.723 ;
     RECT  18.504 0.571 20.682 1.723 ;
     RECT  21.924 0.571 22.41 1.723 ;
     RECT  24.372 0.571 24.462 1.723 ;
     RECT  25.776 0.091 25.794 1.723 ;
     RECT  26.676 0.571 27.558 1.723 ;
     RECT  30.42 0.571 32.742 1.723 ;
     RECT  35.532 1.175 36.558 1.723 ;
     RECT  37.476 0.571 38.286 1.723 ;
     RECT  41.472 1.175 41.85 1.723 ;
     RECT  42.696 0.091 42.714 1.723 ;
     RECT  43.524 0.139 48.762 1.723 ;
     RECT  49.896 0.523 52.326 1.723 ;
     RECT  53.172 0.091 53.874 1.723 ;
     RECT  54.72 0.091 55.926 1.723 ;
     RECT  56.736 0.091 57.258 1.723 ;
     RECT  58.14 0.523 64.314 1.723 ;
     RECT  65.16 0.091 66.762 1.723 ;
     RECT  67.536 0.139 69.498 1.723 ;
     RECT  70.524 0.091 71.082 1.723 ;
     RECT  72.072 0.523 72.774 1.723 ;
     RECT  73.62 0.091 74.538 1.723 ;
     RECT  75.348 0.523 79.434 1.723 ;
     RECT  82.08 1.531 86.31 1.723 ;
     RECT  26.676 1.723 28.782 2.143 ;
     RECT  29.592 1.723 33.498 2.143 ;
     RECT  34.236 1.175 34.758 2.143 ;
     RECT  35.532 1.723 38.646 2.143 ;
     RECT  40.356 1.175 40.698 2.143 ;
     RECT  43.524 1.723 55.926 2.143 ;
     RECT  56.736 1.723 66.762 2.143 ;
     RECT  67.536 1.723 86.31 2.143 ;
     RECT  2.376 1.723 15.03 2.155 ;
     RECT  15.912 1.723 20.682 2.155 ;
     RECT  21.636 1.723 24.858 2.155 ;
     RECT  25.596 1.723 25.794 2.191 ;
     RECT  26.676 2.143 33.498 2.191 ;
     RECT  34.236 2.143 38.646 2.191 ;
     RECT  39.456 1.175 39.474 2.191 ;
     RECT  40.215 2.143 40.698 2.191 ;
     RECT  41.472 1.723 42.714 2.191 ;
     RECT  25.596 2.191 33.498 2.227 ;
     RECT  34.236 2.191 42.714 2.227 ;
     RECT  0.036 1.133 0.054 2.263 ;
     RECT  2.376 2.155 24.858 2.263 ;
     RECT  25.596 2.227 42.714 2.263 ;
     RECT  2.376 2.263 42.714 2.371 ;
     RECT  43.524 2.143 86.31 2.371 ;
     RECT  2.376 2.371 86.31 2.461 ;
     RECT  2.34 2.461 86.31 2.597 ;
     RECT  2.34 2.597 85.518 2.669 ;
     RECT  2.34 2.669 85.482 2.731 ;
     RECT  2.304 2.731 85.482 3.065 ;
     RECT  86.256 2.597 86.31 3.209 ;
     RECT  86.256 3.209 86.274 3.299 ;
     RECT  2.304 3.065 85.338 3.371 ;
     RECT  2.304 3.371 83.934 3.875 ;
     RECT  0.036 2.263 0.09 3.979 ;
     RECT  85.068 3.371 85.338 4.075 ;
     RECT  0.036 3.979 0.162 4.109 ;
     RECT  2.34 3.875 83.934 4.109 ;
     RECT  68.652 4.109 83.934 4.145 ;
     RECT  6.228 4.109 67.806 4.217 ;
     RECT  2.34 4.109 5.382 4.253 ;
     RECT  74.124 4.145 83.898 4.253 ;
     RECT  64.044 4.217 67.806 4.289 ;
     RECT  74.124 4.253 76.554 4.289 ;
     RECT  6.228 4.217 11.538 4.379 ;
     RECT  12.42 4.217 63.306 4.379 ;
     RECT  64.044 4.289 65.754 4.379 ;
     RECT  66.492 4.289 67.806 4.379 ;
     RECT  77.364 4.253 83.898 4.379 ;
     RECT  85.068 4.075 85.482 4.379 ;
     RECT  10.8 4.379 11.538 4.415 ;
     RECT  12.42 4.379 63.054 4.415 ;
     RECT  66.492 4.379 67.497 4.415 ;
     RECT  75.168 4.289 76.554 4.415 ;
     RECT  31.068 4.415 63.054 4.451 ;
     RECT  66.672 4.415 67.497 4.487 ;
     RECT  31.068 4.451 58.806 4.493 ;
     RECT  85.068 4.379 85.086 4.523 ;
     RECT  53.1 4.493 58.806 4.541 ;
     RECT  6.228 4.379 10.026 4.559 ;
     RECT  53.1 4.541 57.294 4.559 ;
     RECT  58.068 4.541 58.806 4.559 ;
     RECT  59.724 4.451 61.002 4.559 ;
     RECT  64.404 4.379 65.754 4.559 ;
     RECT  75.168 4.415 76.23 4.589 ;
     RECT  6.228 4.559 9.054 4.649 ;
     RECT  10.8 4.415 10.818 4.649 ;
     RECT  12.42 4.415 30.33 4.649 ;
     RECT  53.244 4.559 57.294 4.649 ;
     RECT  59.724 4.559 60.858 4.649 ;
     RECT  65.232 4.559 65.394 4.649 ;
     RECT  68.652 4.145 72.897 4.649 ;
     RECT  9.864 4.559 10.026 4.685 ;
     RECT  53.316 4.649 57.294 4.685 ;
     RECT  65.232 4.649 65.25 4.685 ;
     RECT  71.856 4.649 72.897 4.685 ;
     RECT  75.276 4.589 76.23 4.685 ;
     RECT  78.015 4.379 83.898 4.685 ;
     RECT  68.652 4.649 70.938 4.691 ;
     RECT  12.42 4.649 13.95 4.721 ;
     RECT  12.42 4.721 13.806 4.733 ;
     RECT  69.156 4.691 70.938 4.757 ;
     RECT  78.015 4.685 79.038 4.757 ;
     RECT  53.388 4.685 57.294 4.793 ;
     RECT  59.868 4.649 60.75 4.829 ;
     RECT  69.156 4.757 70.83 4.829 ;
     RECT  71.928 4.685 72.897 4.829 ;
     RECT  78.015 4.757 78.966 4.829 ;
     RECT  2.34 4.253 5.274 4.919 ;
     RECT  7.776 4.649 8.586 4.919 ;
     RECT  14.94 4.649 30.294 4.919 ;
     RECT  53.388 4.793 54.81 4.919 ;
     RECT  56.415 4.793 57.294 4.919 ;
     RECT  58.068 4.559 58.734 4.919 ;
     RECT  61.815 4.451 63.054 4.919 ;
     RECT  69.156 4.829 70.146 4.919 ;
     RECT  75.276 4.685 75.438 4.919 ;
     RECT  76.212 4.685 76.23 4.919 ;
     RECT  6.228 4.649 6.966 4.925 ;
     RECT  14.94 4.919 24.39 4.955 ;
     RECT  31.068 4.493 52.362 4.955 ;
     RECT  53.388 4.919 53.586 4.955 ;
     RECT  56.415 4.919 57.222 4.955 ;
     RECT  69.156 4.919 69.174 4.955 ;
     RECT  2.376 4.919 5.058 4.991 ;
     RECT  14.94 4.955 24.354 4.991 ;
     RECT  54.36 4.919 54.81 4.991 ;
     RECT  58.14 4.919 58.734 4.991 ;
     RECT  59.904 4.829 60.246 4.991 ;
     RECT  62.892 4.919 63.054 4.991 ;
     RECT  12.708 4.733 13.806 5.027 ;
     RECT  12.78 5.027 13.806 5.063 ;
     RECT  52.344 4.955 52.362 5.063 ;
     RECT  58.716 4.991 58.734 5.063 ;
     RECT  62.964 4.991 63.054 5.063 ;
     RECT  0.036 4.109 0.054 5.099 ;
     RECT  2.376 4.991 5.022 5.099 ;
     RECT  9.936 4.685 10.026 5.099 ;
     RECT  64.404 4.559 64.422 5.099 ;
     RECT  66.708 4.487 67.497 5.099 ;
     RECT  70.128 4.919 70.146 5.099 ;
     RECT  25.236 4.919 30.294 5.165 ;
     RECT  31.068 4.955 51.39 5.165 ;
     RECT  14.94 4.991 24.297 5.189 ;
     RECT  31.356 5.165 51.39 5.189 ;
     RECT  2.376 5.099 4.698 5.225 ;
     RECT  14.94 5.189 17.118 5.225 ;
     RECT  18.108 5.189 19.746 5.261 ;
     RECT  54.792 4.991 54.81 5.261 ;
     RECT  79.812 4.685 83.898 5.261 ;
     RECT  28.332 5.165 30.294 5.297 ;
     RECT  25.236 5.165 27.486 5.309 ;
     RECT  44.784 5.189 51.39 5.309 ;
     RECT  86.292 4.699 86.31 5.323 ;
     RECT  20.52 5.189 24.297 5.333 ;
     RECT  31.356 5.189 43.974 5.333 ;
     RECT  80.028 5.261 83.898 5.341 ;
     RECT  6.228 4.925 6.786 5.357 ;
     RECT  31.356 5.333 32.202 5.369 ;
     RECT  78.015 4.829 78.678 5.369 ;
     RECT  31.356 5.369 32.022 5.453 ;
     RECT  19.656 5.261 19.746 5.459 ;
     RECT  29.052 5.297 30.294 5.459 ;
     RECT  33.048 5.333 43.974 5.459 ;
     RECT  45 5.309 51.39 5.459 ;
     RECT  80.028 5.341 84.114 5.459 ;
     RECT  14.94 5.225 16.686 5.495 ;
     RECT  19.656 5.459 19.674 5.495 ;
     RECT  20.556 5.333 24.297 5.495 ;
     RECT  20.556 5.495 22.806 5.531 ;
     RECT  6.228 5.357 6.246 5.567 ;
     RECT  12.78 5.063 13.497 5.567 ;
     RECT  20.556 5.531 22.338 5.567 ;
     RECT  25.236 5.309 25.47 5.567 ;
     RECT  26.316 5.309 27.486 5.597 ;
     RECT  12.816 5.567 13.497 5.603 ;
     RECT  15.264 5.495 16.686 5.603 ;
     RECT  26.604 5.597 27.486 5.603 ;
     RECT  29.415 5.459 30.294 5.603 ;
     RECT  10.836 5.539 10.854 5.639 ;
     RECT  15.264 5.603 16.074 5.639 ;
     RECT  18.108 5.261 18.897 5.639 ;
     RECT  25.236 5.567 25.362 5.639 ;
     RECT  26.784 5.603 27.486 5.639 ;
     RECT  80.352 5.459 80.406 5.639 ;
     RECT  15.264 5.639 15.282 5.645 ;
     RECT  16.056 5.639 16.074 5.645 ;
     RECT  26.784 5.639 27.234 5.645 ;
     RECT  31.644 5.453 32.022 5.645 ;
     RECT  31.968 5.645 32.022 5.648 ;
     RECT  45.615 5.459 51.39 5.693 ;
     RECT  2.376 5.225 4.374 5.707 ;
     RECT  47.304 5.693 51.39 5.729 ;
     RECT  86.256 5.323 86.31 5.765 ;
     RECT  29.415 5.603 30.222 5.801 ;
     RECT  20.988 5.567 22.338 5.873 ;
     RECT  21.564 5.873 22.338 5.909 ;
     RECT  2.304 5.707 4.374 5.999 ;
     RECT  47.304 5.729 51.297 5.999 ;
     RECT  63.036 5.063 63.054 5.999 ;
     RECT  49.5 5.999 51.297 6.029 ;
     RECT  50.184 6.029 51.297 6.035 ;
     RECT  47.304 5.999 48.366 6.071 ;
     RECT  81.432 5.459 84.114 6.107 ;
     RECT  47.556 6.071 48.366 6.143 ;
     RECT  2.415 5.999 4.374 6.151 ;
     RECT  81.936 6.107 84.114 6.179 ;
     RECT  2.415 6.151 4.482 6.269 ;
     RECT  47.916 6.143 48.078 6.269 ;
     RECT  33.048 5.459 43.866 6.277 ;
     RECT  32.328 6.277 43.866 6.305 ;
     RECT  47.916 6.269 47.934 6.305 ;
     RECT  86.256 5.765 86.274 6.305 ;
     RECT  2.415 6.269 3.69 6.341 ;
     RECT  60.228 4.991 60.246 6.539 ;
     RECT  81.936 6.179 83.697 6.845 ;
     RECT  31.536 6.691 31.554 6.961 ;
     RECT  32.328 6.305 42.93 6.961 ;
     RECT  43.848 6.305 43.866 6.989 ;
     RECT  82.08 6.845 82.35 7.079 ;
     RECT  82.08 7.079 82.098 7.187 ;
     RECT  83.196 6.845 83.697 7.223 ;
     RECT  85.464 5.947 85.482 7.232 ;
     RECT  45.615 5.693 46.422 7.259 ;
     RECT  4.464 6.269 4.482 7.321 ;
     RECT  31.536 6.961 42.93 7.321 ;
     RECT  2.415 6.341 3.582 7.339 ;
     RECT  53.568 4.955 53.586 7.349 ;
     RECT  2.34 7.339 3.582 7.385 ;
     RECT  31.068 7.321 42.93 7.385 ;
     RECT  2.415 7.385 3.582 7.501 ;
     RECT  31.068 7.385 39.078 7.501 ;
     RECT  2.415 7.501 3.726 7.619 ;
     RECT  39.816 7.385 41.526 7.619 ;
     RECT  2.415 7.619 3.546 7.691 ;
     RECT  84.924 7.735 84.942 7.853 ;
     RECT  39.816 7.619 41.49 8.159 ;
     RECT  41.292 8.159 41.49 8.195 ;
     RECT  29.415 5.801 29.697 8.299 ;
     RECT  29.415 8.299 29.934 8.311 ;
     RECT  30.78 7.501 39.078 8.311 ;
     RECT  39.816 8.159 40.554 8.311 ;
     RECT  29.415 8.311 40.554 8.509 ;
     RECT  29.232 8.509 40.554 8.539 ;
     RECT  42.912 7.385 42.93 8.699 ;
     RECT  41.976 8.539 41.994 8.851 ;
     RECT  5.976 5.881 5.994 8.879 ;
     RECT  4.464 7.321 4.518 8.941 ;
     RECT  2.415 7.691 3.222 8.968 ;
     RECT  2.304 8.968 3.222 9.005 ;
     RECT  2.415 9.005 3.222 9.067 ;
     RECT  29.088 8.539 40.554 9.085 ;
     RECT  2.415 9.067 3.726 9.121 ;
     RECT  4.464 8.941 4.698 9.121 ;
     RECT  28.224 9.085 40.554 9.211 ;
     RECT  2.415 9.121 4.698 9.239 ;
     RECT  85.464 8.443 85.482 9.239 ;
     RECT  28.224 9.211 41.094 9.275 ;
     RECT  41.976 8.851 42.282 9.391 ;
     RECT  28.224 9.275 40.497 9.437 ;
     RECT  2.415 9.239 3.546 9.509 ;
     RECT  41.364 9.391 42.282 9.509 ;
     RECT  25.2 9.481 25.218 9.533 ;
     RECT  2.415 9.509 3.402 9.545 ;
     RECT  41.364 9.509 42.03 9.545 ;
     RECT  27.468 9.625 27.486 9.661 ;
     RECT  28.224 9.437 38.538 9.661 ;
     RECT  25.488 9.643 25.506 9.689 ;
     RECT  27.468 9.661 38.538 9.725 ;
     RECT  86.292 9.661 86.31 9.725 ;
     RECT  26.712 9.691 26.73 10.021 ;
     RECT  39.528 9.437 40.497 10.165 ;
     RECT  27.576 9.725 38.538 10.201 ;
     RECT  39.456 10.165 40.497 10.201 ;
     RECT  26.712 10.021 26.766 10.435 ;
     RECT  27.576 10.201 40.497 10.471 ;
     RECT  41.364 9.545 41.49 10.471 ;
     RECT  27.576 10.471 41.49 10.589 ;
     RECT  27.576 10.589 41.238 10.625 ;
     RECT  25.992 10.435 26.766 10.741 ;
     RECT  27.576 10.625 40.626 10.741 ;
     RECT  2.415 9.545 3.042 10.843 ;
     RECT  25.884 10.741 40.626 10.931 ;
     RECT  24.015 5.495 24.297 10.975 ;
     RECT  25.884 10.931 38.862 10.987 ;
     RECT  2.415 10.843 3.582 11.011 ;
     RECT  4.464 9.239 4.698 11.011 ;
     RECT  24.015 10.975 24.894 11.011 ;
     RECT  25.668 10.987 38.862 11.011 ;
     RECT  2.415 11.011 4.698 11.129 ;
     RECT  39.672 10.931 40.626 11.129 ;
     RECT  24.015 11.011 38.862 11.165 ;
     RECT  30.564 11.165 38.862 11.435 ;
     RECT  32.508 11.435 38.862 11.713 ;
     RECT  39.672 11.129 40.497 11.713 ;
     RECT  24.015 11.165 29.79 11.911 ;
     RECT  23.832 11.911 29.79 11.947 ;
     RECT  30.564 11.435 31.662 11.947 ;
     RECT  23.832 11.947 31.662 12.091 ;
     RECT  23.796 12.091 31.662 12.325 ;
     RECT  23.472 12.325 31.662 12.361 ;
     RECT  32.508 11.713 40.497 12.361 ;
     RECT  2.415 11.129 3.582 12.631 ;
     RECT  22.32 5.909 22.338 12.631 ;
     RECT  23.472 12.361 40.497 12.631 ;
     RECT  2.415 12.631 3.654 12.749 ;
     RECT  22.32 12.631 40.497 12.749 ;
     RECT  2.415 12.749 3.438 12.785 ;
     RECT  22.32 12.749 38.538 13.003 ;
     RECT  22.068 13.003 38.538 13.027 ;
     RECT  42.768 12.859 42.786 13.037 ;
     RECT  21.636 13.027 38.538 13.289 ;
     RECT  46.944 12.859 46.962 13.289 ;
     RECT  2.415 12.785 3.114 13.801 ;
     RECT  2.415 13.801 3.222 13.819 ;
     RECT  21.636 13.289 38.178 13.829 ;
     RECT  2.34 13.819 3.222 13.865 ;
     RECT  21.636 13.829 37.314 14.099 ;
     RECT  2.415 13.865 3.222 14.203 ;
     RECT  4.392 11.129 4.698 14.203 ;
     RECT  20.52 14.059 20.538 14.251 ;
     RECT  21.636 14.099 37.206 14.251 ;
     RECT  20.52 14.251 37.206 14.341 ;
     RECT  2.415 14.203 4.698 14.369 ;
     RECT  20.196 14.341 37.206 14.369 ;
     RECT  2.415 14.369 3.654 14.405 ;
     RECT  20.196 14.369 37.134 14.521 ;
     RECT  20.052 14.521 37.134 14.639 ;
     RECT  50.328 6.035 51.297 14.639 ;
     RECT  22.212 14.639 37.134 14.675 ;
     RECT  18.615 5.639 18.897 14.881 ;
     RECT  20.052 14.639 20.97 14.881 ;
     RECT  26.568 14.675 37.134 15.215 ;
     RECT  18.615 14.881 20.97 15.307 ;
     RECT  18.252 15.307 20.97 15.403 ;
     RECT  22.212 14.675 25.65 15.403 ;
     RECT  18.252 15.403 25.65 15.421 ;
     RECT  18.252 15.421 25.83 15.449 ;
     RECT  32.112 15.215 37.134 15.449 ;
     RECT  2.415 14.405 3.222 15.451 ;
     RECT  4.392 14.369 4.698 15.451 ;
     RECT  18.252 15.449 20.07 15.485 ;
     RECT  2.415 15.451 4.698 15.601 ;
     RECT  20.808 15.449 25.83 15.601 ;
     RECT  26.568 15.215 31.158 15.601 ;
     RECT  32.112 15.449 35.442 15.629 ;
     RECT  36.18 15.449 36.738 15.677 ;
     RECT  2.415 15.601 4.734 15.719 ;
     RECT  18.252 15.485 19.458 15.719 ;
     RECT  18.252 15.719 19.206 15.755 ;
     RECT  20.808 15.601 31.158 15.755 ;
     RECT  2.415 15.719 3.654 15.791 ;
     RECT  18.252 15.755 18.897 15.799 ;
     RECT  17.64 15.799 18.897 15.979 ;
     RECT  31.356 16.105 31.374 16.141 ;
     RECT  32.292 15.629 35.442 16.295 ;
     RECT  20.808 15.755 30.186 16.375 ;
     RECT  31.356 16.141 31.518 16.375 ;
     RECT  32.292 16.295 35.37 16.375 ;
     RECT  16.632 16.141 16.65 16.411 ;
     RECT  17.496 15.979 18.897 16.411 ;
     RECT  20.7 16.375 30.186 16.555 ;
     RECT  31.356 16.375 35.37 16.555 ;
     RECT  85.464 10.291 85.482 16.589 ;
     RECT  16.632 16.411 18.897 16.645 ;
     RECT  19.8 16.555 19.818 16.645 ;
     RECT  15.876 16.501 15.894 16.681 ;
     RECT  16.632 16.645 19.818 16.681 ;
     RECT  20.7 16.555 35.37 16.681 ;
     RECT  15.876 16.681 35.37 16.799 ;
     RECT  15.876 16.799 35.097 16.871 ;
     RECT  2.415 15.791 3.222 16.951 ;
     RECT  15.876 16.871 17.118 16.951 ;
     RECT  2.415 16.951 3.33 17.035 ;
     RECT  4.392 15.719 4.734 17.035 ;
     RECT  17.928 16.871 35.097 17.069 ;
     RECT  15.66 16.951 17.118 17.105 ;
     RECT  17.928 17.069 28.35 17.105 ;
     RECT  0.108 17.077 0.126 17.117 ;
     RECT  13.215 5.603 13.497 17.185 ;
     RECT  14.832 17.077 14.85 17.213 ;
     RECT  2.415 17.035 4.734 17.221 ;
     RECT  15.66 17.105 15.894 17.221 ;
     RECT  14.868 17.221 15.894 17.339 ;
     RECT  17.928 17.105 26.622 17.339 ;
     RECT  2.415 17.221 5.022 17.419 ;
     RECT  13.215 17.185 13.806 17.491 ;
     RECT  29.088 17.069 35.097 17.609 ;
     RECT  15.804 17.339 15.894 17.645 ;
     RECT  17.1 17.105 17.118 17.645 ;
     RECT  13.215 17.491 14.058 17.653 ;
     RECT  13.068 17.653 14.058 17.659 ;
     RECT  6.084 17.611 6.102 17.707 ;
     RECT  2.415 17.419 5.166 17.761 ;
     RECT  6.084 17.707 6.462 17.761 ;
     RECT  86.292 17.077 86.31 17.837 ;
     RECT  12.888 17.659 14.058 17.851 ;
     RECT  18.072 17.339 26.622 17.879 ;
     RECT  29.088 17.609 34.002 17.915 ;
     RECT  12.312 17.851 14.058 18.031 ;
     RECT  21.636 17.879 26.622 18.031 ;
     RECT  27.36 17.105 28.35 18.031 ;
     RECT  29.124 17.915 34.002 18.077 ;
     RECT  2.415 17.761 6.966 18.121 ;
     RECT  7.776 4.919 8.097 18.121 ;
     RECT  2.415 18.121 8.442 18.149 ;
     RECT  29.124 18.077 32.958 18.149 ;
     RECT  12.24 18.031 14.058 18.157 ;
     RECT  2.415 18.149 5.022 18.185 ;
     RECT  5.796 18.149 8.442 18.185 ;
     RECT  12.024 18.157 14.058 18.193 ;
     RECT  6.624 18.185 8.442 18.301 ;
     RECT  9.36 18.121 9.378 18.301 ;
     RECT  10.656 18.193 10.674 18.301 ;
     RECT  11.484 18.193 14.058 18.379 ;
     RECT  14.868 17.339 15.03 18.379 ;
     RECT  6.624 18.301 9.378 18.419 ;
     RECT  6.624 18.419 6.642 18.455 ;
     RECT  7.416 18.419 9.378 18.455 ;
     RECT  29.124 18.149 32.886 18.455 ;
     RECT  29.124 18.455 32.67 18.527 ;
     RECT  7.452 18.455 9.378 18.535 ;
     RECT  16.236 18.301 16.362 18.535 ;
     RECT  17.208 17.761 17.334 18.535 ;
     RECT  18.072 17.879 20.862 18.535 ;
     RECT  7.452 18.535 9.45 18.571 ;
     RECT  10.656 18.301 10.746 18.571 ;
     RECT  11.484 18.379 15.03 18.571 ;
     RECT  16.056 18.535 16.362 18.571 ;
     RECT  17.208 18.535 20.862 18.571 ;
     RECT  34.815 17.609 35.097 18.661 ;
     RECT  33.84 18.077 34.002 18.689 ;
     RECT  2.415 18.185 4.77 18.697 ;
     RECT  16.056 18.571 20.862 18.697 ;
     RECT  21.636 18.031 28.35 18.697 ;
     RECT  2.304 18.697 4.77 18.749 ;
     RECT  7.452 18.571 15.318 18.841 ;
     RECT  16.056 18.697 28.35 18.841 ;
     RECT  33.84 18.689 33.858 18.845 ;
     RECT  29.124 18.527 31.986 18.959 ;
     RECT  2.415 18.749 4.77 18.989 ;
     RECT  34.776 18.661 35.097 19.111 ;
     RECT  38.16 13.829 38.178 19.201 ;
     RECT  2.415 18.989 3.402 19.229 ;
     RECT  36.72 15.677 36.738 19.237 ;
     RECT  37.944 19.201 38.178 19.237 ;
     RECT  36.72 19.237 38.178 19.277 ;
     RECT  34.776 19.111 35.154 19.336 ;
     RECT  4.356 18.989 4.77 19.339 ;
     RECT  5.544 19.201 5.562 19.339 ;
     RECT  7.452 18.841 28.35 19.345 ;
     RECT  29.124 18.959 31.878 19.345 ;
     RECT  4.356 19.339 5.562 19.381 ;
     RECT  34.776 19.336 35.19 19.381 ;
     RECT  36.72 19.277 36.738 19.381 ;
     RECT  4.356 19.381 5.67 19.471 ;
     RECT  2.415 19.229 3.366 19.499 ;
     RECT  4.356 19.471 5.778 19.535 ;
     RECT  2.415 19.499 3.15 19.615 ;
     RECT  6.624 19.543 6.642 19.615 ;
     RECT  7.452 19.345 31.878 19.615 ;
     RECT  34.776 19.381 35.37 19.651 ;
     RECT  5.472 19.535 5.778 19.769 ;
     RECT  6.624 19.615 31.878 19.769 ;
     RECT  34.164 19.651 35.37 19.769 ;
     RECT  5.472 19.769 5.598 19.805 ;
     RECT  6.624 19.769 31.158 19.921 ;
     RECT  34.815 19.769 35.37 19.921 ;
     RECT  36.144 19.381 36.738 19.921 ;
     RECT  34.02 19.915 34.038 19.955 ;
     RECT  5.544 19.805 5.598 20.039 ;
     RECT  6.552 19.921 31.158 20.039 ;
     RECT  6.552 20.039 31.086 20.075 ;
     RECT  5.58 20.039 5.598 20.111 ;
     RECT  6.552 20.075 9.702 20.149 ;
     RECT  10.548 20.075 31.086 20.309 ;
     RECT  2.376 19.615 3.15 20.347 ;
     RECT  2.304 20.347 3.15 20.461 ;
     RECT  34.815 19.921 36.738 20.461 ;
     RECT  37.944 19.277 38.178 20.461 ;
     RECT  2.304 20.461 3.33 20.539 ;
     RECT  32.976 20.551 32.994 20.587 ;
     RECT  2.304 20.539 3.51 20.615 ;
     RECT  6.516 20.149 9.702 20.615 ;
     RECT  4.356 19.535 4.734 20.659 ;
     RECT  2.415 20.615 3.51 20.731 ;
     RECT  4.356 20.659 4.77 20.731 ;
     RECT  5.76 20.695 5.778 20.731 ;
     RECT  6.516 20.615 8.442 20.731 ;
     RECT  2.415 20.731 4.77 20.849 ;
     RECT  2.415 20.849 3.51 20.885 ;
     RECT  4.356 20.849 4.77 20.957 ;
     RECT  34.815 20.461 38.286 20.971 ;
     RECT  4.392 20.957 4.77 21.001 ;
     RECT  5.76 20.731 8.442 21.001 ;
     RECT  32.688 20.587 32.994 21.001 ;
     RECT  4.392 21.001 4.806 21.067 ;
     RECT  5.652 21.001 8.442 21.067 ;
     RECT  10.548 20.309 30.942 21.115 ;
     RECT  9.216 20.615 9.702 21.127 ;
     RECT  10.44 21.115 30.942 21.127 ;
     RECT  34.776 20.971 38.286 21.191 ;
     RECT  9.216 21.127 30.942 21.199 ;
     RECT  31.716 21.115 31.734 21.199 ;
     RECT  9.216 21.199 31.734 21.271 ;
     RECT  32.688 21.001 33.858 21.271 ;
     RECT  34.776 21.191 36.09 21.271 ;
     RECT  80.388 5.639 80.406 21.361 ;
     RECT  32.688 21.271 33.966 21.389 ;
     RECT  34.704 21.271 36.09 21.389 ;
     RECT  36.864 21.191 38.286 21.389 ;
     RECT  4.392 21.067 8.442 21.425 ;
     RECT  36.9 21.389 38.286 21.425 ;
     RECT  36.9 21.425 36.918 21.533 ;
     RECT  9.216 21.271 31.914 21.541 ;
     RECT  85.464 18.463 85.482 21.629 ;
     RECT  2.415 20.885 3.474 21.643 ;
     RECT  4.392 21.425 8.19 21.659 ;
     RECT  33.624 21.389 33.75 21.659 ;
     RECT  34.704 21.389 35.91 21.659 ;
     RECT  32.688 21.389 32.886 21.695 ;
     RECT  33.624 21.659 33.678 21.695 ;
     RECT  34.776 21.659 35.73 21.695 ;
     RECT  34.776 21.695 35.097 21.731 ;
     RECT  2.415 21.643 3.51 21.811 ;
     RECT  4.392 21.659 6.93 21.811 ;
     RECT  7.668 21.659 8.19 21.839 ;
     RECT  2.415 21.811 6.93 21.929 ;
     RECT  8.928 21.541 31.95 21.929 ;
     RECT  2.415 21.929 3.546 21.937 ;
     RECT  4.392 21.929 4.734 21.965 ;
     RECT  5.796 21.929 6.93 21.965 ;
     RECT  2.412 21.937 3.546 22.001 ;
     RECT  5.796 21.965 5.814 22.001 ;
     RECT  2.412 22.001 3.15 22.013 ;
     RECT  6.912 21.965 6.93 22.073 ;
     RECT  7.776 21.839 8.19 22.351 ;
     RECT  8.928 21.929 30.402 22.351 ;
     RECT  31.248 21.929 31.95 22.411 ;
     RECT  7.776 22.351 30.402 22.469 ;
     RECT  7.776 22.469 30.222 22.505 ;
     RECT  31.248 22.411 32.094 22.505 ;
     RECT  31.284 22.505 32.094 22.621 ;
     RECT  33.3 22.219 33.318 22.621 ;
     RECT  34.815 21.731 35.097 22.621 ;
     RECT  34.308 22.621 35.91 22.699 ;
     RECT  40.215 12.749 40.497 22.699 ;
     RECT  29.415 22.505 30.078 22.739 ;
     RECT  33.012 22.621 33.462 22.739 ;
     RECT  40.215 22.699 40.554 22.739 ;
     RECT  42.084 22.219 42.102 22.739 ;
     RECT  13.215 22.505 28.242 22.775 ;
     RECT  29.415 22.739 29.97 22.775 ;
     RECT  31.284 22.621 32.238 22.775 ;
     RECT  33.012 22.739 33.318 22.775 ;
     RECT  37.404 22.699 37.422 22.783 ;
     RECT  38.16 21.425 38.286 22.783 ;
     RECT  39.06 21.271 39.078 22.783 ;
     RECT  13.215 22.775 27.486 22.847 ;
     RECT  86.292 22.081 86.31 22.877 ;
     RECT  34.308 22.699 36.018 22.891 ;
     RECT  37.08 22.783 37.422 22.891 ;
     RECT  38.16 22.783 39.294 22.891 ;
     RECT  7.776 22.505 10.062 23.009 ;
     RECT  13.215 22.847 26.514 23.009 ;
     RECT  27.324 22.847 27.486 23.009 ;
     RECT  28.224 22.775 28.242 23.009 ;
     RECT  34.308 22.891 36.162 23.009 ;
     RECT  36.936 22.891 39.294 23.009 ;
     RECT  34.308 23.009 35.946 23.045 ;
     RECT  36.936 23.009 37.35 23.045 ;
     RECT  33.012 22.775 33.174 23.081 ;
     RECT  7.776 23.009 9.018 23.161 ;
     RECT  38.16 23.009 39.294 23.161 ;
     RECT  40.215 22.739 40.497 23.161 ;
     RECT  41.688 23.131 41.85 23.161 ;
     RECT  42.948 23.125 42.966 23.161 ;
     RECT  9.9 23.009 10.062 23.251 ;
     RECT  10.872 22.505 12.15 23.251 ;
     RECT  13.215 23.009 26.406 23.251 ;
     RECT  43.92 23.161 43.938 23.251 ;
     RECT  36.972 23.045 37.098 23.279 ;
     RECT  41.22 23.161 41.85 23.279 ;
     RECT  42.624 23.161 43.146 23.279 ;
     RECT  43.92 23.251 44.658 23.287 ;
     RECT  7.704 23.161 9.018 23.315 ;
     RECT  9.9 23.251 26.406 23.315 ;
     RECT  34.815 23.045 35.946 23.315 ;
     RECT  36.972 23.279 36.99 23.315 ;
     RECT  38.16 23.161 40.497 23.315 ;
     RECT  41.22 23.279 41.562 23.315 ;
     RECT  42.624 23.279 42.894 23.315 ;
     RECT  43.92 23.287 44.766 23.315 ;
     RECT  45.615 7.259 45.897 23.323 ;
     RECT  27.36 23.009 27.45 23.351 ;
     RECT  49.32 23.317 49.338 23.357 ;
     RECT  6.624 23.287 6.642 23.431 ;
     RECT  7.704 23.315 8.262 23.431 ;
     RECT  44.1 23.315 44.766 23.431 ;
     RECT  45.615 23.323 45.99 23.431 ;
     RECT  50.364 14.639 51.297 23.431 ;
     RECT  85.5 23.323 85.518 23.501 ;
     RECT  4.392 21.965 4.698 23.515 ;
     RECT  22.5 23.315 26.406 23.549 ;
     RECT  32.364 23.431 32.49 23.549 ;
     RECT  41.328 23.315 41.49 23.549 ;
     RECT  42.768 23.315 42.822 23.549 ;
     RECT  44.1 23.431 45.99 23.549 ;
     RECT  50.256 23.431 51.297 23.549 ;
     RECT  35.892 23.315 35.946 23.585 ;
     RECT  39.276 23.315 40.497 23.585 ;
     RECT  41.328 23.549 41.346 23.585 ;
     RECT  44.1 23.549 44.658 23.585 ;
     RECT  45.612 23.549 45.99 23.585 ;
     RECT  50.256 23.549 50.274 23.585 ;
     RECT  2.415 22.013 3.15 23.611 ;
     RECT  27.36 23.351 27.414 23.621 ;
     RECT  2.304 23.611 3.15 23.657 ;
     RECT  42.804 23.549 42.822 23.693 ;
     RECT  4.392 23.515 4.878 23.701 ;
     RECT  5.832 23.431 5.85 23.701 ;
     RECT  6.624 23.431 6.786 23.701 ;
     RECT  45.615 23.585 45.99 23.701 ;
     RECT  47.016 23.371 47.034 23.701 ;
     RECT  48.312 23.323 48.33 23.701 ;
     RECT  35.892 23.585 35.91 23.729 ;
     RECT  4.392 23.701 5.022 23.819 ;
     RECT  45.615 23.701 46.026 23.819 ;
     RECT  46.8 23.701 47.178 23.819 ;
     RECT  47.952 23.701 48.474 23.819 ;
     RECT  5.796 23.701 6.786 23.855 ;
     RECT  7.596 23.431 8.262 23.855 ;
     RECT  46.8 23.819 46.962 23.855 ;
     RECT  47.952 23.819 48.186 23.855 ;
     RECT  9 23.315 9.018 23.933 ;
     RECT  22.608 23.549 26.406 23.935 ;
     RECT  6.084 23.855 6.786 23.971 ;
     RECT  9.9 23.315 21.726 23.971 ;
     RECT  29.415 22.775 29.697 23.971 ;
     RECT  6.084 23.971 6.858 24.089 ;
     RECT  9.108 23.971 21.726 24.089 ;
     RECT  45.615 23.819 45.99 24.089 ;
     RECT  46.8 23.855 46.89 24.089 ;
     RECT  47.988 23.855 48.078 24.089 ;
     RECT  6.084 24.089 6.102 24.125 ;
     RECT  22.608 23.935 26.55 24.125 ;
     RECT  47.988 24.089 48.006 24.125 ;
     RECT  46.872 24.089 46.89 24.161 ;
     RECT  6.84 24.089 6.858 24.197 ;
     RECT  78.015 5.369 78.297 24.205 ;
     RECT  9.108 24.089 14.994 24.233 ;
     RECT  22.608 24.125 26.514 24.233 ;
     RECT  45.615 24.089 45.954 24.233 ;
     RECT  49.428 23.431 49.446 24.233 ;
     RECT  15.984 24.089 21.726 24.395 ;
     RECT  16.812 24.395 21.726 24.403 ;
     RECT  22.608 24.233 24.426 24.403 ;
     RECT  32.472 23.549 32.49 24.469 ;
     RECT  27.468 24.241 27.594 24.475 ;
     RECT  39.276 23.585 39.294 24.475 ;
     RECT  7.776 23.855 8.262 24.511 ;
     RECT  28.44 24.475 28.458 24.511 ;
     RECT  29.412 23.971 29.697 24.511 ;
     RECT  34.056 24.475 34.074 24.511 ;
     RECT  7.776 24.511 8.37 24.601 ;
     RECT  9.108 24.233 13.95 24.629 ;
     RECT  16.812 24.403 24.426 24.629 ;
     RECT  27.288 24.475 27.594 24.629 ;
     RECT  9.108 24.629 13.878 24.665 ;
     RECT  33.336 24.511 34.074 24.745 ;
     RECT  34.815 23.315 35.097 24.745 ;
     RECT  28.44 24.511 29.697 24.781 ;
     RECT  33.336 24.745 35.097 24.781 ;
     RECT  25.164 24.233 26.514 24.899 ;
     RECT  27.288 24.629 27.486 24.899 ;
     RECT  28.44 24.781 29.79 24.899 ;
     RECT  31.284 24.241 31.302 24.907 ;
     RECT  33.336 24.781 35.37 24.907 ;
     RECT  9.108 24.665 13.497 24.935 ;
     RECT  25.272 24.899 25.434 24.935 ;
     RECT  33.336 24.907 35.442 24.935 ;
     RECT  38.16 23.315 38.286 24.935 ;
     RECT  31.14 24.907 31.302 24.955 ;
     RECT  32.328 24.469 32.49 24.955 ;
     RECT  27.288 24.899 27.45 24.971 ;
     RECT  25.272 24.935 25.29 25.043 ;
     RECT  14.832 24.233 14.994 25.051 ;
     RECT  29.376 24.899 29.79 25.051 ;
     RECT  31.14 24.955 32.49 25.051 ;
     RECT  33.336 24.935 33.426 25.051 ;
     RECT  34.2 24.935 35.442 25.051 ;
     RECT  39.276 24.475 39.402 25.051 ;
     RECT  10.26 24.935 12.042 25.085 ;
     RECT  34.2 25.051 35.478 25.133 ;
     RECT  7.128 24.601 8.37 25.141 ;
     RECT  15.984 24.395 16.002 25.141 ;
     RECT  16.812 24.629 22.194 25.141 ;
     RECT  14.832 25.051 15.174 25.147 ;
     RECT  15.984 25.141 22.194 25.147 ;
     RECT  9.108 24.935 9.45 25.169 ;
     RECT  28.44 24.899 28.566 25.169 ;
     RECT  29.376 25.051 33.426 25.169 ;
     RECT  28.548 25.169 28.566 25.205 ;
     RECT  30.528 25.169 33.426 25.205 ;
     RECT  2.415 23.657 3.15 25.243 ;
     RECT  6.48 25.141 8.37 25.285 ;
     RECT  6.12 25.285 8.37 25.321 ;
     RECT  9.108 25.169 9.306 25.321 ;
     RECT  4.392 23.819 4.662 25.349 ;
     RECT  26.784 25.249 26.802 25.349 ;
     RECT  13.215 24.935 13.497 25.435 ;
     RECT  14.832 25.147 22.194 25.435 ;
     RECT  11.16 25.085 12.042 25.439 ;
     RECT  14.832 25.435 22.23 25.439 ;
     RECT  2.34 25.243 3.15 25.475 ;
     RECT  11.16 25.439 11.97 25.475 ;
     RECT  14.832 25.439 15.066 25.475 ;
     RECT  29.376 25.169 29.697 25.475 ;
     RECT  30.528 25.205 32.922 25.475 ;
     RECT  34.344 25.133 35.478 25.555 ;
     RECT  6.12 25.321 9.306 25.591 ;
     RECT  13.215 25.435 13.914 25.591 ;
     RECT  14.832 25.475 14.958 25.591 ;
     RECT  15.876 25.439 22.23 25.591 ;
     RECT  22.968 24.629 24.426 25.591 ;
     RECT  34.344 25.555 35.586 25.591 ;
     RECT  4.428 25.349 4.662 25.627 ;
     RECT  5.472 25.591 9.306 25.627 ;
     RECT  4.428 25.627 9.306 25.709 ;
     RECT  13.215 25.591 14.958 25.709 ;
     RECT  15.876 25.591 24.426 25.709 ;
     RECT  30.6 25.475 32.922 25.709 ;
     RECT  4.428 25.709 6.354 25.745 ;
     RECT  34.344 25.591 35.73 25.745 ;
     RECT  7.092 25.709 9.306 25.817 ;
     RECT  10.26 25.085 10.35 25.819 ;
     RECT  13.215 25.709 13.986 25.819 ;
     RECT  10.044 25.819 10.35 25.861 ;
     RECT  11.16 25.475 11.25 25.861 ;
     RECT  22.068 25.709 24.426 25.889 ;
     RECT  10.044 25.861 11.25 25.979 ;
     RECT  34.812 25.745 35.73 25.987 ;
     RECT  36.576 25.591 37.242 25.987 ;
     RECT  7.2 25.817 9.306 26.015 ;
     RECT  10.044 25.979 10.998 26.015 ;
     RECT  22.068 25.889 24.297 26.015 ;
     RECT  7.272 26.015 9.306 26.087 ;
     RECT  31.572 25.709 32.922 26.131 ;
     RECT  34.812 25.987 37.242 26.131 ;
     RECT  38.16 24.935 38.178 26.131 ;
     RECT  4.428 25.745 6.318 26.203 ;
     RECT  14.724 25.709 14.958 26.203 ;
     RECT  30.6 25.709 30.618 26.237 ;
     RECT  4.248 26.203 6.318 26.249 ;
     RECT  15.876 25.709 15.894 26.249 ;
     RECT  22.068 26.015 22.59 26.249 ;
     RECT  23.364 26.015 24.297 26.249 ;
     RECT  4.248 26.249 5.382 26.285 ;
     RECT  6.3 26.249 6.318 26.285 ;
     RECT  22.068 26.249 22.446 26.285 ;
     RECT  23.4 26.249 24.297 26.321 ;
     RECT  7.38 26.087 9.306 26.365 ;
     RECT  10.044 26.015 10.314 26.365 ;
     RECT  29.415 25.475 29.697 26.401 ;
     RECT  34.812 26.131 38.178 26.401 ;
     RECT  39.06 25.051 39.402 26.401 ;
     RECT  40.215 23.585 40.497 26.401 ;
     RECT  4.248 26.285 5.31 26.429 ;
     RECT  31.572 26.131 34.074 26.429 ;
     RECT  7.38 26.365 10.314 26.519 ;
     RECT  28.98 26.401 29.697 26.519 ;
     RECT  34.812 26.401 39.402 26.527 ;
     RECT  40.14 26.401 40.497 26.527 ;
     RECT  7.38 26.519 10.062 26.555 ;
     RECT  85.464 24.088 85.482 26.621 ;
     RECT  32.112 26.429 34.074 26.635 ;
     RECT  34.812 26.527 40.497 26.635 ;
     RECT  11.772 26.203 11.934 26.671 ;
     RECT  12.852 25.819 13.986 26.671 ;
     RECT  14.724 26.203 15.102 26.671 ;
     RECT  16.668 25.709 21.33 26.671 ;
     RECT  32.112 26.635 40.662 26.671 ;
     RECT  11.772 26.671 13.986 26.761 ;
     RECT  14.724 26.671 15.318 26.761 ;
     RECT  2.415 25.475 3.15 26.779 ;
     RECT  4.392 26.429 5.31 26.789 ;
     RECT  7.38 26.555 9.522 26.789 ;
     RECT  30.78 26.671 31.302 26.789 ;
     RECT  42.372 26.527 42.39 26.789 ;
     RECT  4.392 26.789 5.238 26.825 ;
     RECT  7.38 26.789 9.378 26.825 ;
     RECT  7.38 26.825 9.306 26.827 ;
     RECT  2.415 26.779 3.294 26.875 ;
     RECT  32.112 26.671 41.598 26.897 ;
     RECT  11.772 26.761 15.318 27.031 ;
     RECT  7.272 26.827 9.306 27.059 ;
     RECT  32.112 26.897 37.134 27.059 ;
     RECT  2.304 26.875 3.294 27.095 ;
     RECT  7.272 27.059 8.406 27.095 ;
     RECT  36.648 27.059 37.134 27.095 ;
     RECT  43.236 26.761 43.254 27.095 ;
     RECT  37.872 26.897 41.598 27.103 ;
     RECT  22.248 26.285 22.446 27.139 ;
     RECT  2.415 27.095 3.294 27.211 ;
     RECT  4.392 26.825 4.662 27.211 ;
     RECT  16.236 26.671 21.33 27.211 ;
     RECT  22.248 27.139 22.482 27.239 ;
     RECT  43.848 27.205 43.866 27.245 ;
     RECT  84.924 27.175 84.942 27.245 ;
     RECT  11.052 27.031 15.318 27.301 ;
     RECT  29.412 26.519 29.697 27.301 ;
     RECT  9.216 27.059 9.306 27.329 ;
     RECT  22.248 27.239 22.446 27.329 ;
     RECT  29.412 27.301 29.862 27.329 ;
     RECT  16.2 27.211 21.33 27.337 ;
     RECT  22.248 27.329 22.266 27.337 ;
     RECT  10.908 27.301 15.39 27.341 ;
     RECT  9.216 27.329 9.234 27.365 ;
     RECT  37.872 27.103 41.922 27.365 ;
     RECT  44.784 27.211 44.802 27.445 ;
     RECT  6.516 27.337 6.534 27.481 ;
     RECT  7.272 27.095 8.334 27.481 ;
     RECT  10.98 27.341 15.39 27.481 ;
     RECT  16.2 27.337 22.266 27.481 ;
     RECT  44.784 27.445 44.874 27.481 ;
     RECT  45.615 24.233 45.897 27.481 ;
     RECT  6.516 27.481 8.334 27.599 ;
     RECT  29.415 27.329 29.862 27.599 ;
     RECT  4.212 27.211 4.662 27.635 ;
     RECT  6.516 27.599 8.262 27.635 ;
     RECT  32.112 27.059 35.838 27.635 ;
     RECT  37.872 27.365 39.078 27.635 ;
     RECT  6.516 27.635 8.097 27.715 ;
     RECT  30.78 26.789 31.158 27.751 ;
     RECT  32.148 27.635 32.166 27.779 ;
     RECT  6.336 27.715 8.097 27.841 ;
     RECT  30.636 27.751 31.158 27.841 ;
     RECT  5.724 27.841 8.097 27.869 ;
     RECT  10.98 27.481 22.266 27.869 ;
     RECT  38.232 27.635 39.078 27.869 ;
     RECT  39.816 27.365 41.886 27.869 ;
     RECT  5.724 27.869 6.57 27.877 ;
     RECT  2.415 27.211 3.438 27.883 ;
     RECT  36.648 27.095 36.99 27.883 ;
     RECT  5.436 27.877 6.57 27.905 ;
     RECT  7.308 27.869 8.097 27.905 ;
     RECT  85.464 27.835 85.482 27.905 ;
     RECT  11.736 27.869 22.266 27.917 ;
     RECT  32.976 27.635 33.066 27.917 ;
     RECT  46.944 27.877 46.962 27.917 ;
     RECT  42.84 27.751 42.858 28.021 ;
     RECT  44.784 27.481 45.897 28.111 ;
     RECT  5.436 27.905 6.534 28.139 ;
     RECT  11.772 27.917 22.266 28.139 ;
     RECT  33.048 27.917 33.066 28.139 ;
     RECT  11.772 28.139 21.438 28.175 ;
     RECT  30.636 27.841 31.374 28.175 ;
     RECT  39.816 27.869 41.058 28.175 ;
     RECT  9.972 27.913 10.026 28.255 ;
     RECT  9.864 28.255 10.026 28.291 ;
     RECT  10.98 27.869 10.998 28.291 ;
     RECT  34.056 27.635 35.838 28.291 ;
     RECT  36.648 27.883 37.17 28.291 ;
     RECT  44.532 28.111 45.897 28.291 ;
     RECT  47.124 27.979 47.25 28.291 ;
     RECT  39.816 28.175 41.022 28.319 ;
     RECT  5.436 28.139 5.454 28.409 ;
     RECT  6.408 28.139 6.534 28.409 ;
     RECT  11.772 28.175 20.502 28.409 ;
     RECT  21.312 28.175 21.438 28.409 ;
     RECT  30.636 28.175 30.798 28.409 ;
     RECT  47.124 28.291 47.286 28.409 ;
     RECT  4.644 27.635 4.662 28.417 ;
     RECT  6.408 28.409 6.426 28.445 ;
     RECT  12.708 28.409 20.502 28.445 ;
     RECT  21.312 28.409 21.33 28.445 ;
     RECT  30.636 28.409 30.654 28.445 ;
     RECT  34.056 28.291 37.17 28.445 ;
     RECT  44.532 28.291 46.206 28.445 ;
     RECT  84.888 28.417 84.906 28.493 ;
     RECT  44.532 28.445 44.694 28.525 ;
     RECT  0.108 28.453 0.126 28.541 ;
     RECT  8.964 28.381 8.982 28.561 ;
     RECT  37.116 28.445 37.17 28.561 ;
     RECT  42.84 28.021 43.29 28.561 ;
     RECT  47.232 28.409 47.286 28.561 ;
     RECT  2.415 27.883 3.798 28.679 ;
     RECT  4.644 28.417 5.166 28.679 ;
     RECT  37.116 28.561 37.314 28.679 ;
     RECT  47.232 28.561 47.43 28.679 ;
     RECT  2.415 28.679 3.618 28.715 ;
     RECT  4.644 28.679 4.95 28.715 ;
     RECT  34.092 28.445 36.27 28.715 ;
     RECT  37.116 28.679 37.134 28.715 ;
     RECT  38.268 27.869 39.078 28.715 ;
     RECT  47.232 28.679 47.286 28.715 ;
     RECT  8.964 28.561 9.018 28.795 ;
     RECT  8.892 28.795 9.018 28.831 ;
     RECT  9.864 28.291 10.998 28.831 ;
     RECT  11.772 28.409 11.79 28.831 ;
     RECT  38.772 28.715 39.078 28.831 ;
     RECT  39.816 28.319 40.878 28.831 ;
     RECT  42.84 28.561 43.506 28.831 ;
     RECT  38.772 28.831 40.878 28.859 ;
     RECT  42.696 28.831 43.506 28.949 ;
     RECT  13.14 28.445 20.502 28.985 ;
     RECT  38.916 28.859 40.878 28.985 ;
     RECT  43.344 28.949 43.506 29.029 ;
     RECT  44.28 28.525 44.694 29.029 ;
     RECT  13.14 28.985 19.674 29.069 ;
     RECT  7.776 27.905 8.097 29.101 ;
     RECT  8.892 28.831 11.79 29.101 ;
     RECT  20.448 28.985 20.502 29.101 ;
     RECT  85.5 28.957 85.518 29.117 ;
     RECT  13.14 29.069 17.406 29.219 ;
     RECT  18.18 29.069 19.674 29.219 ;
     RECT  20.448 29.101 20.538 29.219 ;
     RECT  38.916 28.985 39.078 29.219 ;
     RECT  7.776 29.101 11.79 29.255 ;
     RECT  13.14 29.219 13.59 29.255 ;
     RECT  34.704 28.715 36.27 29.255 ;
     RECT  43.344 29.029 44.694 29.255 ;
     RECT  9.756 29.255 11.79 29.263 ;
     RECT  20.52 29.219 20.538 29.291 ;
     RECT  9.756 29.263 12.366 29.371 ;
     RECT  13.14 29.255 13.497 29.371 ;
     RECT  39.852 28.985 40.878 29.371 ;
     RECT  38.916 29.219 38.934 29.405 ;
     RECT  43.704 29.255 44.694 29.461 ;
     RECT  45.576 28.445 45.897 29.461 ;
     RECT  7.776 29.255 8.982 29.489 ;
     RECT  14.328 29.219 17.406 29.489 ;
     RECT  43.704 29.461 45.897 29.489 ;
     RECT  7.776 29.489 8.838 29.525 ;
     RECT  34.815 29.255 36.27 29.525 ;
     RECT  39.852 29.371 40.914 29.525 ;
     RECT  43.704 29.489 43.722 29.525 ;
     RECT  4.644 28.715 4.662 29.755 ;
     RECT  18.18 29.219 19.566 29.759 ;
     RECT  36.504 29.605 36.666 29.759 ;
     RECT  6.84 29.755 6.858 29.795 ;
     RECT  18.18 29.759 19.422 29.795 ;
     RECT  44.604 29.489 45.897 29.839 ;
     RECT  42.768 29.767 42.786 29.867 ;
     RECT  24.015 26.321 24.297 29.899 ;
     RECT  37.62 29.731 37.638 29.911 ;
     RECT  39.96 29.525 40.914 29.911 ;
     RECT  41.868 27.869 41.886 29.911 ;
     RECT  6.984 29.911 7.002 30.029 ;
     RECT  23.544 29.899 24.297 30.029 ;
     RECT  39.96 29.911 41.886 30.029 ;
     RECT  14.328 29.489 17.334 30.065 ;
     RECT  37.44 29.911 37.962 30.065 ;
     RECT  2.415 28.715 3.15 30.136 ;
     RECT  9.756 29.371 13.497 30.139 ;
     RECT  2.304 30.136 3.15 30.173 ;
     RECT  39.996 30.029 41.886 30.173 ;
     RECT  4.644 29.755 4.914 30.181 ;
     RECT  44.604 29.839 46.098 30.181 ;
     RECT  47.232 28.715 47.25 30.181 ;
     RECT  48.168 28.561 48.186 30.181 ;
     RECT  37.62 30.065 37.962 30.187 ;
     RECT  23.256 30.091 23.274 30.209 ;
     RECT  36.504 29.759 36.522 30.221 ;
     RECT  7.776 29.525 8.154 30.235 ;
     RECT  4.356 30.181 5.058 30.299 ;
     RECT  37.62 30.187 38.178 30.299 ;
     RECT  4.356 30.299 4.662 30.335 ;
     RECT  5.904 30.181 6.102 30.335 ;
     RECT  40.215 30.173 41.886 30.335 ;
     RECT  44.604 30.181 48.186 30.335 ;
     RECT  18.18 29.795 18.897 30.371 ;
     RECT  37.656 30.299 38.178 30.371 ;
     RECT  51.015 23.549 51.297 30.415 ;
     RECT  45.468 30.335 45.897 30.443 ;
     RECT  47.088 30.335 48.186 30.443 ;
     RECT  7.668 30.235 8.154 30.451 ;
     RECT  37.944 30.371 38.178 30.451 ;
     RECT  50.688 30.415 51.297 30.451 ;
     RECT  50.688 30.451 51.642 30.461 ;
     RECT  7.668 30.451 8.802 30.541 ;
     RECT  9.756 30.139 13.518 30.541 ;
     RECT  5.976 30.335 6.102 30.569 ;
     RECT  37.944 30.451 38.322 30.569 ;
     RECT  5.976 30.569 5.994 30.605 ;
     RECT  37.944 30.569 37.962 30.605 ;
     RECT  7.668 30.541 13.518 30.721 ;
     RECT  14.436 30.065 17.334 30.721 ;
     RECT  51.015 30.461 51.642 30.721 ;
     RECT  6.732 30.712 6.75 30.749 ;
     RECT  14.436 30.721 17.73 30.839 ;
     RECT  51.015 30.721 52.542 30.839 ;
     RECT  18.504 30.371 18.897 30.875 ;
     RECT  47.7 30.443 48.186 30.875 ;
     RECT  49.176 30.721 49.554 30.875 ;
     RECT  51.015 30.839 51.786 30.875 ;
     RECT  7.668 30.721 13.662 30.907 ;
     RECT  7.488 30.907 13.662 30.955 ;
     RECT  14.436 30.839 17.514 30.955 ;
     RECT  85.464 29.707 85.482 30.992 ;
     RECT  40.215 30.335 40.914 31.109 ;
     RECT  7.488 30.955 17.514 31.145 ;
     RECT  52.524 30.839 52.542 31.145 ;
     RECT  51.015 30.875 51.297 31.195 ;
     RECT  52.848 31.195 52.866 31.253 ;
     RECT  41.868 30.335 41.886 31.261 ;
     RECT  41.688 31.261 41.886 31.373 ;
     RECT  15.408 31.145 17.514 31.379 ;
     RECT  40.215 31.109 40.878 31.379 ;
     RECT  7.488 31.145 14.634 31.415 ;
     RECT  17.352 31.379 17.37 31.415 ;
     RECT  53.856 31.261 53.874 31.415 ;
     RECT  41.868 31.373 41.886 31.525 ;
     RECT  6.588 31.339 6.606 31.531 ;
     RECT  7.488 31.415 8.097 31.531 ;
     RECT  45.576 30.443 45.897 31.531 ;
     RECT  49.536 30.875 49.554 31.531 ;
     RECT  9.072 31.415 14.634 31.565 ;
     RECT  41.868 31.525 42.426 31.565 ;
     RECT  84.924 31.495 84.942 31.613 ;
     RECT  9.936 31.565 14.634 31.649 ;
     RECT  45.576 31.531 46.026 31.649 ;
     RECT  49.536 31.531 49.986 31.649 ;
     RECT  9.936 31.649 10.674 31.685 ;
     RECT  43.776 31.339 43.794 31.685 ;
     RECT  4.644 30.335 4.662 31.801 ;
     RECT  50.976 31.195 51.297 31.801 ;
     RECT  5.976 31.531 8.097 31.867 ;
     RECT  54 31.531 54.018 31.891 ;
     RECT  5.436 31.867 8.097 31.919 ;
     RECT  9.936 31.685 10.206 31.919 ;
     RECT  15.408 31.379 16.578 31.919 ;
     RECT  54 31.891 54.414 31.919 ;
     RECT  11.592 31.649 14.634 31.927 ;
     RECT  15.408 31.919 16.47 31.927 ;
     RECT  6.444 31.919 8.097 31.955 ;
     RECT  9.936 31.919 10.098 31.955 ;
     RECT  11.592 31.927 16.47 31.955 ;
     RECT  50.58 31.801 52.002 31.955 ;
     RECT  7.704 31.955 8.097 31.991 ;
     RECT  11.88 31.955 16.11 32.189 ;
     RECT  6.444 31.955 6.642 32.225 ;
     RECT  14.328 32.189 16.11 32.225 ;
     RECT  9.072 31.565 9.198 32.296 ;
     RECT  8.82 32.296 9.198 32.341 ;
     RECT  9.936 31.955 9.954 32.341 ;
     RECT  52.02 32.071 52.038 32.341 ;
     RECT  5.436 31.919 5.67 32.459 ;
     RECT  6.516 32.225 6.642 32.459 ;
     RECT  8.82 32.341 9.954 32.459 ;
     RECT  14.472 32.225 16.11 32.459 ;
     RECT  4.536 31.801 4.662 32.491 ;
     RECT  6.516 32.459 6.534 32.495 ;
     RECT  8.82 32.459 9.81 32.495 ;
     RECT  52.02 32.341 52.686 32.495 ;
     RECT  8.82 32.495 9.162 32.729 ;
     RECT  41.868 31.565 41.886 32.801 ;
     RECT  4.32 32.491 4.662 32.881 ;
     RECT  5.436 32.459 5.454 32.881 ;
     RECT  7.776 31.991 8.097 32.881 ;
     RECT  8.82 32.729 9.09 32.881 ;
     RECT  11.88 32.189 13.554 32.881 ;
     RECT  4.32 32.881 5.454 32.999 ;
     RECT  7.776 32.881 9.09 32.999 ;
     RECT  14.472 32.459 15.498 32.999 ;
     RECT  4.32 32.999 5.274 33.035 ;
     RECT  7.776 32.999 9.054 33.035 ;
     RECT  14.472 32.999 15.39 33.035 ;
     RECT  7.776 33.035 8.226 33.079 ;
     RECT  14.472 33.035 15.066 33.151 ;
     RECT  2.415 30.173 3.15 33.385 ;
     RECT  2.304 33.385 3.294 33.421 ;
     RECT  4.32 33.035 4.662 33.421 ;
     RECT  9.864 33.385 9.882 33.421 ;
     RECT  10.8 32.881 13.554 33.421 ;
     RECT  14.364 33.151 15.066 33.421 ;
     RECT  2.304 33.421 3.438 33.437 ;
     RECT  2.415 33.437 3.438 33.539 ;
     RECT  9.864 33.421 15.066 33.539 ;
     RECT  7.704 33.079 8.226 33.547 ;
     RECT  4.212 33.421 4.662 33.575 ;
     RECT  9.864 33.539 14.886 33.575 ;
     RECT  2.415 33.539 3.294 33.629 ;
     RECT  11.448 33.575 14.49 33.809 ;
     RECT  4.248 33.575 4.662 33.845 ;
     RECT  7.056 33.547 8.226 33.845 ;
     RECT  44.604 30.335 44.622 33.845 ;
     RECT  9.036 33.035 9.054 33.925 ;
     RECT  6.228 33.595 6.246 33.961 ;
     RECT  7.056 33.845 8.097 33.961 ;
     RECT  8.82 33.925 9.054 33.961 ;
     RECT  9.864 33.575 10.278 33.961 ;
     RECT  45.576 31.649 45.897 33.961 ;
     RECT  12.24 33.809 14.382 33.965 ;
     RECT  12.276 33.965 14.382 34.079 ;
     RECT  8.82 33.961 10.278 34.115 ;
     RECT  12.276 34.079 14.31 34.115 ;
     RECT  48.168 30.875 48.186 34.115 ;
     RECT  4.644 33.845 4.662 34.219 ;
     RECT  6.228 33.961 8.097 34.349 ;
     RECT  12.348 34.115 14.058 34.349 ;
     RECT  7.2 34.349 8.097 34.385 ;
     RECT  10.296 34.315 10.314 34.385 ;
     RECT  4.644 34.219 5.31 34.501 ;
     RECT  11.448 33.809 11.466 34.501 ;
     RECT  13.104 34.349 14.058 34.619 ;
     RECT  6.228 34.349 6.462 34.655 ;
     RECT  13.104 34.619 13.914 34.655 ;
     RECT  7.704 34.385 8.097 34.693 ;
     RECT  8.82 34.115 9.378 34.693 ;
     RECT  45 33.961 45.897 34.735 ;
     RECT  7.704 34.693 9.378 34.829 ;
     RECT  4.644 34.501 5.382 34.889 ;
     RECT  6.3 34.655 6.462 34.889 ;
     RECT  9.324 34.829 9.378 34.889 ;
     RECT  2.415 33.629 3.15 34.891 ;
     RECT  6.444 34.889 6.462 34.961 ;
     RECT  2.415 34.891 3.762 35.005 ;
     RECT  2.304 35.005 3.762 35.041 ;
     RECT  4.644 34.889 4.878 35.041 ;
     RECT  2.304 35.041 4.878 35.069 ;
     RECT  2.415 35.069 4.878 35.159 ;
     RECT  10.512 34.501 11.466 35.159 ;
     RECT  12.348 34.349 12.366 35.159 ;
     RECT  2.415 35.159 3.618 35.195 ;
     RECT  9.36 34.889 9.378 35.195 ;
     RECT  54.396 31.919 54.414 35.195 ;
     RECT  7.704 34.829 8.586 35.311 ;
     RECT  11.232 35.159 11.466 35.311 ;
     RECT  11.232 35.311 11.574 35.323 ;
     RECT  4.644 35.159 4.878 35.429 ;
     RECT  9.504 35.311 10.494 35.429 ;
     RECT  4.644 35.429 4.734 35.465 ;
     RECT  7.56 35.311 8.586 35.545 ;
     RECT  13.104 34.655 13.497 35.545 ;
     RECT  10.332 35.429 10.494 35.735 ;
     RECT  12.852 35.545 13.497 35.735 ;
     RECT  6.516 35.545 6.534 35.851 ;
     RECT  7.272 35.545 8.586 35.851 ;
     RECT  11.232 35.323 12.114 35.947 ;
     RECT  9.504 35.429 9.522 35.969 ;
     RECT  10.512 35.947 12.114 35.969 ;
     RECT  30.672 35.941 30.69 35.981 ;
     RECT  39.096 30.451 39.114 36.005 ;
     RECT  49.536 31.649 49.554 36.005 ;
     RECT  4.644 35.465 4.662 36.077 ;
     RECT  6.516 35.851 8.586 36.121 ;
     RECT  9.36 36.085 9.378 36.121 ;
     RECT  51.015 31.955 51.297 36.121 ;
     RECT  6.516 36.121 9.378 36.239 ;
     RECT  7.272 36.239 8.442 36.461 ;
     RECT  6.336 36.391 6.354 36.509 ;
     RECT  10.512 35.969 11.934 36.509 ;
     RECT  4.824 36.475 4.842 36.545 ;
     RECT  31.932 36.121 31.95 36.545 ;
     RECT  52.668 32.495 52.686 36.545 ;
     RECT  2.415 35.195 3.15 36.625 ;
     RECT  10.512 36.509 11.394 36.625 ;
     RECT  7.272 36.461 8.37 36.659 ;
     RECT  6.12 36.625 6.138 36.661 ;
     RECT  2.304 36.625 3.15 36.701 ;
     RECT  32.472 36.661 32.49 36.763 ;
     RECT  5.004 36.661 5.022 36.779 ;
     RECT  5.796 36.661 6.138 36.779 ;
     RECT  7.308 36.659 8.37 36.779 ;
     RECT  10.404 36.625 11.394 36.779 ;
     RECT  32.472 36.763 33.21 36.779 ;
     RECT  3.996 36.661 4.014 36.815 ;
     RECT  5.796 36.779 5.814 36.815 ;
     RECT  10.404 36.779 11.286 36.815 ;
     RECT  10.404 36.815 10.962 36.859 ;
     RECT  34.815 29.525 35.097 36.859 ;
     RECT  9.216 36.239 9.378 36.931 ;
     RECT  10.296 36.859 10.962 36.931 ;
     RECT  33.084 36.779 33.21 36.931 ;
     RECT  34.2 36.859 35.097 36.931 ;
     RECT  9.216 36.931 9.45 37.021 ;
     RECT  10.188 36.931 10.962 37.021 ;
     RECT  9.216 37.021 10.962 37.049 ;
     RECT  33.084 36.931 33.354 37.049 ;
     RECT  33.084 37.049 33.21 37.085 ;
     RECT  34.164 36.931 35.097 37.085 ;
     RECT  34.2 37.085 35.097 37.319 ;
     RECT  34.272 37.319 35.097 37.391 ;
     RECT  9.216 37.049 10.854 37.471 ;
     RECT  34.308 37.391 35.097 37.561 ;
     RECT  9.072 37.471 10.854 37.589 ;
     RECT  9.072 37.589 10.746 37.625 ;
     RECT  34.308 37.561 35.298 37.625 ;
     RECT  6.3 37.579 6.318 37.741 ;
     RECT  6.3 37.741 6.534 37.859 ;
     RECT  9.072 37.625 9.918 37.859 ;
     RECT  9.072 37.859 9.882 37.895 ;
     RECT  34.815 37.625 35.298 37.939 ;
     RECT  34.815 37.939 35.442 38.011 ;
     RECT  9.648 37.895 9.882 38.129 ;
     RECT  7.308 36.779 8.298 38.137 ;
     RECT  6.3 37.859 6.39 38.155 ;
     RECT  7.308 38.137 8.91 38.281 ;
     RECT  0.108 38.173 0.126 38.333 ;
     RECT  34.815 38.011 36.126 38.395 ;
     RECT  5.904 38.155 6.39 38.399 ;
     RECT  34.815 38.395 36.702 38.399 ;
     RECT  45 34.735 45.954 38.399 ;
     RECT  54.792 35.311 54.81 38.399 ;
     RECT  3.996 38.281 4.014 38.435 ;
     RECT  7.2 38.281 8.91 38.435 ;
     RECT  34.815 38.399 35.298 38.435 ;
     RECT  36.108 38.399 36.702 38.435 ;
     RECT  5.904 38.399 6.318 38.551 ;
     RECT  44.784 38.515 44.802 38.573 ;
     RECT  40.215 31.379 40.497 38.641 ;
     RECT  55.656 38.551 55.674 38.641 ;
     RECT  56.415 4.955 56.697 38.641 ;
     RECT  5.22 38.551 6.318 38.669 ;
     RECT  7.668 38.435 8.91 38.669 ;
     RECT  9.648 38.129 9.774 38.669 ;
     RECT  41.4 38.551 41.85 38.669 ;
     RECT  7.776 38.669 8.766 38.705 ;
     RECT  9.648 38.669 9.666 38.705 ;
     RECT  37.656 38.551 37.674 38.705 ;
     RECT  39.78 38.641 40.497 38.741 ;
     RECT  48.456 34.159 48.474 38.779 ;
     RECT  53.064 36.661 53.082 38.821 ;
     RECT  49.896 38.821 49.914 38.939 ;
     RECT  41.832 38.669 41.85 38.975 ;
     RECT  47.772 38.779 48.474 38.975 ;
     RECT  47.952 38.975 48.474 39.011 ;
     RECT  53.064 38.821 53.658 39.091 ;
     RECT  5.22 38.669 6.246 39.149 ;
     RECT  4.284 38.779 4.302 39.181 ;
     RECT  5.22 39.149 5.562 39.181 ;
     RECT  55.656 38.641 56.697 39.181 ;
     RECT  4.284 39.181 5.562 39.209 ;
     RECT  7.776 38.705 8.694 39.209 ;
     RECT  42.012 39.091 42.174 39.209 ;
     RECT  48.456 39.011 48.474 39.209 ;
     RECT  4.284 39.209 5.418 39.245 ;
     RECT  7.776 39.209 8.622 39.245 ;
     RECT  53.064 39.091 53.766 39.245 ;
     RECT  2.415 36.701 3.15 39.307 ;
     RECT  55.656 39.181 56.754 39.559 ;
     RECT  7.776 39.245 8.097 39.595 ;
     RECT  43.02 39.361 43.038 39.631 ;
     RECT  43.884 36.121 43.902 39.631 ;
     RECT  55.656 39.559 57.294 39.631 ;
     RECT  54.54 38.551 54.558 39.677 ;
     RECT  4.284 39.245 5.346 39.749 ;
     RECT  5.256 39.749 5.274 39.785 ;
     RECT  43.02 39.631 43.902 39.785 ;
     RECT  85.464 32.197 85.482 39.785 ;
     RECT  43.884 39.785 43.902 39.787 ;
     RECT  7.74 39.595 8.097 39.829 ;
     RECT  43.884 39.787 44.118 39.865 ;
     RECT  2.415 39.307 3.258 39.901 ;
     RECT  4.284 39.749 4.338 39.901 ;
     RECT  6.624 39.865 6.93 39.901 ;
     RECT  7.704 39.829 8.097 39.901 ;
     RECT  43.884 39.865 44.442 39.901 ;
     RECT  45.615 38.399 45.954 39.901 ;
     RECT  6.624 39.901 8.097 39.917 ;
     RECT  0.108 39.865 0.126 39.965 ;
     RECT  2.415 39.901 3.438 40.019 ;
     RECT  43.884 39.901 45.954 40.027 ;
     RECT  2.415 40.019 3.222 40.055 ;
     RECT  43.884 40.027 46.062 40.061 ;
     RECT  45.072 40.061 46.062 40.171 ;
     RECT  58.176 39.901 58.482 40.171 ;
     RECT  77.472 24.205 78.297 40.261 ;
     RECT  4.176 39.901 4.338 40.289 ;
     RECT  6.768 39.917 8.097 40.289 ;
     RECT  45.072 40.171 46.206 40.289 ;
     RECT  4.176 40.289 4.194 40.325 ;
     RECT  7.596 40.289 8.097 40.325 ;
     RECT  45.072 40.289 46.062 40.325 ;
     RECT  46.98 40.171 46.998 40.325 ;
     RECT  55.476 39.631 57.294 40.325 ;
     RECT  58.176 40.171 58.59 40.325 ;
     RECT  80.136 21.361 80.406 40.405 ;
     RECT  83.415 7.223 83.697 40.405 ;
     RECT  53.064 39.245 53.082 40.441 ;
     RECT  55.62 40.325 57.294 40.441 ;
     RECT  58.284 40.325 58.59 40.441 ;
     RECT  59.58 40.171 59.598 40.441 ;
     RECT  83.415 40.405 83.862 40.441 ;
     RECT  80.136 40.405 80.982 40.445 ;
     RECT  51.015 36.121 51.678 40.459 ;
     RECT  85.104 40.363 85.122 40.469 ;
     RECT  48.672 40.441 48.69 40.531 ;
     RECT  6.768 40.289 6.786 40.559 ;
     RECT  45.072 40.325 45.897 40.559 ;
     RECT  55.62 40.441 57.51 40.559 ;
     RECT  70.632 40.369 70.65 40.559 ;
     RECT  82.368 40.441 83.862 40.559 ;
     RECT  48.564 40.531 48.69 40.631 ;
     RECT  53.928 40.441 54.522 40.675 ;
     RECT  52.92 40.441 53.082 40.699 ;
     RECT  53.928 40.675 54.702 40.699 ;
     RECT  5.652 40.675 5.67 40.711 ;
     RECT  51.015 40.459 51.858 40.711 ;
     RECT  52.92 40.699 54.702 40.711 ;
     RECT  59.58 40.441 59.706 40.711 ;
     RECT  50.364 40.711 51.858 40.801 ;
     RECT  50.364 40.801 52.074 40.829 ;
     RECT  52.848 40.711 54.846 40.829 ;
     RECT  6.588 40.711 6.75 40.865 ;
     RECT  48.672 40.631 48.69 40.865 ;
     RECT  55.62 40.559 57.366 40.865 ;
     RECT  50.832 40.829 52.074 40.937 ;
     RECT  58.284 40.441 58.626 40.981 ;
     RECT  59.472 40.711 59.706 40.981 ;
     RECT  82.368 40.559 83.826 40.981 ;
     RECT  84.924 40.981 84.942 41.021 ;
     RECT  2.415 40.055 3.15 41.035 ;
     RECT  67.215 5.099 67.497 41.071 ;
     RECT  72.615 4.829 72.897 41.083 ;
     RECT  5.652 40.711 5.814 41.099 ;
     RECT  6.624 40.865 6.75 41.099 ;
     RECT  58.284 40.981 58.734 41.099 ;
     RECT  70.2 40.909 70.218 41.099 ;
     RECT  81.72 40.981 83.826 41.099 ;
     RECT  59.472 40.981 59.778 41.107 ;
     RECT  6.624 41.099 6.642 41.135 ;
     RECT  50.832 40.937 51.297 41.135 ;
     RECT  52.092 40.981 52.11 41.135 ;
     RECT  52.848 40.829 54.702 41.135 ;
     RECT  59.472 41.107 60.21 41.135 ;
     RECT  81.72 41.099 81.738 41.135 ;
     RECT  55.764 40.865 57.366 41.165 ;
     RECT  82.944 41.099 83.826 41.171 ;
     RECT  59.688 41.135 60.21 41.207 ;
     RECT  58.284 41.099 58.446 41.243 ;
     RECT  52.848 41.135 53.406 41.251 ;
     RECT  5.436 41.215 5.454 41.369 ;
     RECT  43.884 40.061 43.902 41.369 ;
     RECT  55.764 41.165 57.33 41.369 ;
     RECT  73.692 41.179 73.71 41.369 ;
     RECT  2.415 41.035 3.834 41.405 ;
     RECT  52.2 41.251 53.406 41.405 ;
     RECT  53.064 41.405 53.406 41.411 ;
     RECT  2.415 41.405 3.798 41.485 ;
     RECT  2.304 41.485 3.798 41.597 ;
     RECT  77.472 40.261 78.678 41.605 ;
     RECT  54.324 41.135 54.702 41.611 ;
     RECT  2.415 41.597 3.798 41.639 ;
     RECT  53.064 41.411 53.154 41.639 ;
     RECT  55.872 41.369 57.33 41.639 ;
     RECT  67.104 41.071 67.497 41.647 ;
     RECT  2.415 41.639 3.618 41.675 ;
     RECT  60.12 41.207 60.138 41.675 ;
     RECT  72.504 41.083 72.897 41.741 ;
     RECT  66.708 41.647 67.497 41.747 ;
     RECT  84.888 41.611 84.906 41.747 ;
     RECT  83.016 41.171 83.826 41.755 ;
     RECT  48.636 41.521 48.654 41.791 ;
     RECT  80.136 40.445 80.406 41.791 ;
     RECT  4.824 41.521 4.986 41.909 ;
     RECT  48.6 41.791 48.762 41.909 ;
     RECT  54.324 41.611 54.918 41.909 ;
     RECT  4.824 41.909 4.842 41.945 ;
     RECT  48.6 41.909 48.654 41.945 ;
     RECT  49.536 41.791 49.554 41.945 ;
     RECT  53.136 41.639 53.154 41.945 ;
     RECT  79.776 41.791 80.406 41.945 ;
     RECT  51.015 41.135 51.297 42.061 ;
     RECT  55.908 41.639 57.33 42.061 ;
     RECT  58.284 41.243 58.41 42.061 ;
     RECT  50.58 42.061 51.297 42.151 ;
     RECT  74.16 41.521 74.178 42.173 ;
     RECT  83.016 41.755 83.898 42.179 ;
     RECT  50.58 42.151 51.642 42.181 ;
     RECT  54.36 41.909 54.918 42.215 ;
     RECT  48.6 41.945 48.618 42.221 ;
     RECT  50.472 42.181 51.642 42.221 ;
     RECT  83.016 42.179 83.826 42.251 ;
     RECT  77.472 41.605 78.858 42.259 ;
     RECT  54.72 42.215 54.918 42.331 ;
     RECT  55.908 42.061 58.41 42.331 ;
     RECT  59.472 42.223 59.49 42.331 ;
     RECT  54.72 42.331 55.062 42.449 ;
     RECT  77.472 42.259 79.002 42.449 ;
     RECT  50.58 42.221 51.642 42.485 ;
     RECT  54.72 42.449 54.738 42.485 ;
     RECT  55.908 42.331 58.626 42.485 ;
     RECT  77.472 42.449 78.894 42.485 ;
     RECT  80.136 41.945 80.406 42.763 ;
     RECT  51.015 42.485 51.642 42.871 ;
     RECT  56.016 42.485 58.626 42.989 ;
     RECT  7.776 40.325 8.097 42.997 ;
     RECT  6.444 42.763 6.462 43.025 ;
     RECT  52.56 42.871 52.578 43.025 ;
     RECT  80.136 42.763 80.766 43.025 ;
     RECT  7.272 42.997 8.097 43.141 ;
     RECT  83.415 42.251 83.826 43.141 ;
     RECT  77.472 42.485 78.678 43.169 ;
     RECT  2.415 41.675 3.15 43.195 ;
     RECT  2.304 43.195 3.15 43.231 ;
     RECT  42.48 43.051 42.498 43.231 ;
     RECT  6.624 43.141 8.097 43.259 ;
     RECT  42.48 43.231 42.786 43.259 ;
     RECT  51.015 42.871 51.678 43.259 ;
     RECT  57.636 42.989 58.626 43.259 ;
     RECT  82.872 43.141 83.826 43.259 ;
     RECT  2.304 43.231 3.69 43.295 ;
     RECT  7.272 43.259 8.097 43.295 ;
     RECT  51.015 43.259 51.606 43.295 ;
     RECT  52.704 43.141 53.442 43.295 ;
     RECT  57.636 43.259 58.482 43.295 ;
     RECT  81.72 43.141 81.738 43.295 ;
     RECT  59.436 42.331 59.49 43.303 ;
     RECT  83.415 43.259 83.826 43.303 ;
     RECT  42.768 43.259 42.786 43.325 ;
     RECT  58.248 43.295 58.482 43.325 ;
     RECT  2.415 43.295 3.69 43.331 ;
     RECT  7.416 43.295 8.097 43.331 ;
     RECT  53.424 43.295 53.442 43.483 ;
     RECT  53.424 43.483 53.802 43.529 ;
     RECT  58.248 43.325 58.266 43.529 ;
     RECT  85.464 43.483 85.482 43.529 ;
     RECT  59.436 43.303 59.598 43.537 ;
     RECT  7.74 43.331 8.097 43.565 ;
     RECT  53.424 43.529 53.442 43.565 ;
     RECT  59.436 43.537 59.634 43.565 ;
     RECT  7.815 43.565 8.097 43.681 ;
     RECT  80.136 43.025 80.658 43.681 ;
     RECT  59.58 43.565 59.634 43.709 ;
     RECT  7.815 43.681 8.946 43.799 ;
     RECT  82.332 43.681 82.35 43.799 ;
     RECT  54.72 43.681 54.738 43.835 ;
     RECT  59.58 43.709 59.598 43.835 ;
     RECT  55.476 43.867 55.494 43.951 ;
     RECT  83.415 43.303 83.934 44.041 ;
     RECT  8.928 43.799 8.946 44.059 ;
     RECT  9.828 43.303 9.846 44.059 ;
     RECT  70.164 43.951 70.182 44.069 ;
     RECT  82.908 44.041 83.934 44.069 ;
     RECT  8.928 44.059 9.846 44.077 ;
     RECT  8.928 44.077 10.026 44.105 ;
     RECT  54.792 43.951 55.494 44.105 ;
     RECT  82.908 44.069 83.697 44.141 ;
     RECT  86.292 41.791 86.31 44.141 ;
     RECT  9.828 44.105 10.026 44.221 ;
     RECT  34.815 38.435 35.097 44.221 ;
     RECT  79.704 43.681 80.658 44.221 ;
     RECT  36.468 44.059 36.486 44.339 ;
     RECT  54.9 44.105 55.494 44.339 ;
     RECT  79.704 44.221 81.378 44.339 ;
     RECT  79.704 44.339 81.126 44.347 ;
     RECT  79.452 44.347 81.126 44.375 ;
     RECT  79.452 44.375 80.406 44.384 ;
     RECT  77.472 43.169 78.297 44.443 ;
     RECT  9.828 44.221 10.566 44.447 ;
     RECT  34.815 44.221 35.406 44.477 ;
     RECT  55.332 44.339 55.494 44.491 ;
     RECT  55.332 44.491 55.674 44.609 ;
     RECT  10.548 44.447 10.566 44.645 ;
     RECT  55.332 44.609 55.35 44.645 ;
     RECT  11.412 44.419 11.43 44.761 ;
     RECT  77.472 44.443 78.57 44.761 ;
     RECT  10.62 44.761 10.638 44.851 ;
     RECT  11.412 44.761 12.114 44.851 ;
     RECT  13.215 35.735 13.497 44.851 ;
     RECT  83.196 44.141 83.697 44.851 ;
     RECT  10.62 44.851 13.497 44.879 ;
     RECT  77.472 44.761 78.714 44.879 ;
     RECT  79.488 44.384 80.406 44.915 ;
     RECT  83.196 44.851 83.898 44.951 ;
     RECT  10.836 44.879 13.497 44.959 ;
     RECT  2.415 43.331 3.15 44.995 ;
     RECT  2.412 44.995 3.15 45.019 ;
     RECT  83.196 44.951 83.697 45.023 ;
     RECT  2.304 45.019 3.15 45.115 ;
     RECT  10.836 44.959 13.662 45.149 ;
     RECT  2.304 45.115 3.726 45.185 ;
     RECT  10.836 45.149 10.998 45.185 ;
     RECT  12.6 45.149 13.662 45.185 ;
     RECT  6.84 45.121 6.858 45.221 ;
     RECT  10.836 45.185 10.854 45.293 ;
     RECT  12.672 45.185 13.662 45.293 ;
     RECT  29.415 27.599 29.697 45.301 ;
     RECT  27.36 45.301 27.378 45.419 ;
     RECT  12.744 45.293 13.662 45.455 ;
     RECT  16.02 45.193 16.038 45.455 ;
     RECT  32.22 45.595 32.238 45.689 ;
     RECT  13.104 45.455 13.662 45.697 ;
     RECT  13.104 45.697 13.878 45.731 ;
     RECT  13.14 45.731 13.878 45.841 ;
     RECT  33.768 45.841 33.786 45.917 ;
     RECT  29.304 45.301 29.697 45.931 ;
     RECT  13.14 45.841 14.67 45.995 ;
     RECT  13.215 45.995 13.662 46.067 ;
     RECT  29.304 45.931 30.258 46.111 ;
     RECT  29.16 46.111 30.546 46.157 ;
     RECT  14.436 45.995 14.67 46.265 ;
     RECT  29.415 46.157 30.546 46.309 ;
     RECT  29.415 46.309 30.654 46.381 ;
     RECT  2.415 45.185 3.114 46.459 ;
     RECT  29.415 46.381 30.834 46.499 ;
     RECT  29.415 46.499 30.546 46.535 ;
     RECT  31.608 46.381 31.626 46.535 ;
     RECT  15.408 46.039 15.426 46.579 ;
     RECT  2.415 46.459 3.474 46.615 ;
     RECT  2.412 46.615 3.474 46.651 ;
     RECT  14.544 46.265 14.67 46.651 ;
     RECT  15.408 46.579 15.966 46.651 ;
     RECT  2.412 46.651 3.618 46.747 ;
     RECT  2.304 46.747 3.618 46.769 ;
     RECT  54.288 46.741 54.306 46.781 ;
     RECT  2.304 46.769 3.114 46.805 ;
     RECT  32.76 46.651 32.778 46.805 ;
     RECT  14.544 46.651 15.966 46.841 ;
     RECT  53.964 46.843 53.982 46.883 ;
     RECT  15.696 46.841 15.966 46.885 ;
     RECT  34.815 44.477 35.097 46.921 ;
     RECT  14.832 46.841 14.85 46.949 ;
     RECT  15.696 46.885 16.182 47.011 ;
     RECT  4.392 46.651 4.41 47.075 ;
     RECT  10.836 47.047 10.854 47.147 ;
     RECT  34.704 46.921 35.097 47.323 ;
     RECT  34.704 47.323 35.262 47.345 ;
     RECT  85.464 44.731 85.482 47.345 ;
     RECT  15.696 47.011 16.65 47.461 ;
     RECT  34.815 47.345 35.262 47.501 ;
     RECT  28.512 46.921 28.53 47.579 ;
     RECT  36.324 47.461 36.342 47.615 ;
     RECT  29.415 46.535 29.697 47.695 ;
     RECT  29.412 47.695 29.697 47.731 ;
     RECT  15.696 47.461 16.722 47.759 ;
     RECT  36.432 47.731 36.45 47.885 ;
     RECT  37.296 47.467 37.314 47.885 ;
     RECT  29.412 47.731 30.366 47.933 ;
     RECT  29.415 47.933 30.366 48.001 ;
     RECT  2.415 46.805 3.114 48.091 ;
     RECT  36.54 48.001 37.242 48.119 ;
     RECT  29.415 48.001 30.402 48.155 ;
     RECT  38.304 48.001 38.322 48.155 ;
     RECT  2.304 48.091 3.114 48.379 ;
     RECT  30.42 48.271 30.438 48.389 ;
     RECT  31.212 48.271 31.374 48.389 ;
     RECT  2.304 48.379 3.654 48.425 ;
     RECT  15.732 47.759 16.722 48.467 ;
     RECT  2.415 48.425 3.654 48.541 ;
     RECT  16.056 48.467 16.722 48.541 ;
     RECT  32.22 48.271 32.238 48.541 ;
     RECT  33.012 48.361 33.03 48.541 ;
     RECT  86.292 47.857 86.31 48.557 ;
     RECT  2.415 48.541 3.834 48.659 ;
     RECT  32.22 48.541 33.03 48.659 ;
     RECT  38.376 48.271 38.466 48.659 ;
     RECT  2.415 48.659 3.654 48.695 ;
     RECT  4.608 48.541 4.626 48.695 ;
     RECT  32.22 48.659 32.238 48.695 ;
     RECT  28.332 48.811 28.35 48.901 ;
     RECT  28.188 48.901 28.35 48.929 ;
     RECT  38.844 48.811 38.862 48.937 ;
     RECT  28.188 48.929 28.206 48.941 ;
     RECT  33.012 48.659 33.03 48.965 ;
     RECT  29.415 48.155 29.697 49.081 ;
     RECT  40.215 38.741 40.497 49.081 ;
     RECT  33.48 48.973 33.642 49.199 ;
     RECT  38.844 48.937 39.078 49.199 ;
     RECT  29.232 49.081 29.697 49.235 ;
     RECT  38.844 49.199 38.862 49.235 ;
     RECT  16.056 48.541 17.046 49.351 ;
     RECT  34.815 47.501 35.097 49.351 ;
     RECT  15.948 49.351 17.046 49.441 ;
     RECT  15.948 49.441 17.082 49.469 ;
     RECT  29.376 49.235 29.697 49.505 ;
     RECT  34.416 49.351 35.097 49.505 ;
     RECT  15.804 49.477 15.822 49.517 ;
     RECT  33.48 49.199 33.498 49.565 ;
     RECT  29.415 49.505 29.697 49.621 ;
     RECT  2.415 48.695 3.114 49.723 ;
     RECT  29.415 49.621 29.97 49.771 ;
     RECT  2.304 49.723 3.114 49.775 ;
     RECT  16.596 49.469 17.082 49.775 ;
     RECT  34.488 49.505 35.097 49.775 ;
     RECT  2.415 49.775 3.114 49.891 ;
     RECT  29.415 49.771 30.078 49.891 ;
     RECT  31.212 48.389 31.23 49.891 ;
     RECT  2.415 49.891 3.294 49.963 ;
     RECT  40.032 49.081 40.497 49.981 ;
     RECT  29.415 49.891 30.222 50.009 ;
     RECT  34.596 49.775 35.097 50.009 ;
     RECT  29.415 50.009 29.97 50.045 ;
     RECT  30.996 49.891 31.23 50.045 ;
     RECT  44.244 49.711 44.262 50.045 ;
     RECT  48.24 50.107 48.258 50.153 ;
     RECT  2.415 49.963 3.474 50.161 ;
     RECT  4.392 50.125 4.41 50.161 ;
     RECT  32.004 49.531 32.022 50.161 ;
     RECT  34.776 50.009 35.097 50.161 ;
     RECT  49.86 50.125 49.878 50.161 ;
     RECT  2.415 50.161 4.41 50.279 ;
     RECT  31.356 50.161 32.094 50.279 ;
     RECT  34.776 50.161 35.118 50.279 ;
     RECT  31.356 50.279 31.914 50.315 ;
     RECT  34.776 50.279 35.097 50.315 ;
     RECT  36.036 50.161 36.234 50.315 ;
     RECT  49.284 50.161 49.878 50.315 ;
     RECT  2.415 50.279 3.546 50.351 ;
     RECT  15.84 50.431 15.858 50.549 ;
     RECT  26.856 50.431 26.874 50.549 ;
     RECT  36.108 50.315 36.234 50.549 ;
     RECT  4.392 50.279 4.41 50.585 ;
     RECT  33.084 49.981 33.102 50.585 ;
     RECT  36.108 50.549 36.126 50.585 ;
     RECT  49.392 50.315 49.878 50.585 ;
     RECT  16.74 49.775 17.082 50.693 ;
     RECT  29.415 50.045 29.697 50.701 ;
     RECT  45.615 40.559 45.897 50.701 ;
     RECT  43.992 50.665 44.01 50.717 ;
     RECT  28.872 50.701 29.697 50.731 ;
     RECT  37.548 50.701 37.566 50.819 ;
     RECT  50.112 50.701 50.274 50.819 ;
     RECT  45.108 50.701 45.897 50.855 ;
     RECT  51.015 43.295 51.297 50.971 ;
     RECT  50.112 50.819 50.13 51.005 ;
     RECT  37.656 50.971 37.674 51.097 ;
     RECT  28.692 50.731 29.697 51.125 ;
     RECT  37.656 51.097 38.394 51.125 ;
     RECT  45.288 50.855 45.897 51.125 ;
     RECT  38.376 51.125 38.394 51.149 ;
     RECT  29.088 51.125 29.697 51.241 ;
     RECT  39.924 49.981 40.497 51.241 ;
     RECT  45.615 51.125 45.897 51.241 ;
     RECT  21.78 51.241 21.798 51.293 ;
     RECT  29.088 51.241 29.754 51.331 ;
     RECT  2.415 50.351 3.258 51.355 ;
     RECT  39.6 51.241 40.497 51.395 ;
     RECT  50.976 50.971 51.297 51.395 ;
     RECT  15.948 51.397 15.966 51.439 ;
     RECT  16.74 50.693 17.01 51.439 ;
     RECT  15.948 51.439 17.01 51.511 ;
     RECT  29.088 51.331 29.79 51.511 ;
     RECT  15.948 51.511 17.262 51.637 ;
     RECT  29.088 51.511 30.078 51.643 ;
     RECT  2.304 51.355 3.258 51.665 ;
     RECT  39.816 51.395 40.497 51.665 ;
     RECT  20.232 51.241 20.25 51.677 ;
     RECT  2.415 51.665 3.258 51.745 ;
     RECT  2.415 51.745 3.726 51.781 ;
     RECT  40.215 51.665 40.497 51.781 ;
     RECT  45.615 51.241 46.062 51.781 ;
     RECT  51.015 51.395 51.297 51.781 ;
     RECT  13.215 46.067 13.497 51.871 ;
     RECT  40.215 51.781 40.806 51.871 ;
     RECT  2.415 51.781 3.87 51.899 ;
     RECT  15.948 51.637 17.406 51.899 ;
     RECT  45.615 51.781 46.422 51.899 ;
     RECT  51.015 51.781 51.318 51.899 ;
     RECT  6.12 51.871 6.138 51.907 ;
     RECT  13.104 51.871 13.497 51.917 ;
     RECT  2.415 51.899 3.654 51.935 ;
     RECT  52.2 51.781 52.218 51.935 ;
     RECT  4.644 51.781 4.662 52.007 ;
     RECT  6.12 51.907 6.534 52.007 ;
     RECT  29.088 51.643 30.186 52.051 ;
     RECT  40.215 51.871 40.95 52.051 ;
     RECT  52.308 51.979 52.722 52.051 ;
     RECT  45.615 51.899 46.278 52.061 ;
     RECT  16.02 51.899 17.406 52.079 ;
     RECT  29.088 52.051 30.33 52.169 ;
     RECT  40.215 52.051 41.094 52.169 ;
     RECT  47.196 52.051 47.79 52.171 ;
     RECT  40.215 52.169 40.806 52.205 ;
     RECT  47.196 52.171 48.114 52.205 ;
     RECT  52.308 52.051 53.118 52.205 ;
     RECT  48.096 52.205 48.114 52.211 ;
     RECT  52.56 52.205 53.118 52.241 ;
     RECT  31.356 52.051 31.374 52.321 ;
     RECT  41.976 52.051 41.994 52.321 ;
     RECT  29.088 52.169 30.114 52.349 ;
     RECT  6.12 52.007 6.138 52.355 ;
     RECT  31.248 52.321 31.806 52.411 ;
     RECT  53.1 52.241 53.118 52.411 ;
     RECT  29.415 52.349 30.114 52.439 ;
     RECT  47.304 52.205 47.358 52.439 ;
     RECT  16.02 52.079 17.154 52.445 ;
     RECT  41.976 52.321 42.318 52.475 ;
     RECT  53.1 52.411 53.442 52.475 ;
     RECT  49.104 52.321 49.122 52.555 ;
     RECT  47.34 52.439 47.358 52.583 ;
     RECT  49.104 52.555 49.194 52.591 ;
     RECT  49.104 52.591 49.338 52.745 ;
     RECT  54.504 52.591 55.242 52.745 ;
     RECT  30.96 52.411 31.806 52.747 ;
     RECT  29.415 52.439 29.97 52.781 ;
     RECT  54.648 52.745 55.242 52.825 ;
     RECT  42.264 52.475 42.318 52.861 ;
     RECT  54.648 52.825 55.566 52.877 ;
     RECT  33.048 52.861 33.57 52.939 ;
     RECT  45.615 52.061 45.897 52.939 ;
     RECT  2.415 51.935 3.258 52.951 ;
     RECT  16.524 52.445 17.154 52.951 ;
     RECT  33.048 52.939 33.93 52.979 ;
     RECT  42.264 52.861 42.462 52.979 ;
     RECT  45.615 52.939 46.53 52.979 ;
     RECT  2.415 52.951 3.69 52.987 ;
     RECT  49.32 52.745 49.338 52.987 ;
     RECT  33.048 52.979 33.57 53.015 ;
     RECT  42.264 52.979 42.282 53.015 ;
     RECT  54.648 52.877 54.99 53.015 ;
     RECT  2.304 52.987 3.69 53.024 ;
     RECT  45.615 52.979 46.206 53.024 ;
     RECT  44.028 52.987 44.046 53.059 ;
     RECT  2.415 53.024 3.69 53.131 ;
     RECT  16.524 52.951 17.226 53.131 ;
     RECT  43.344 53.059 44.046 53.131 ;
     RECT  43.236 53.131 44.046 53.227 ;
     RECT  2.415 53.131 3.834 53.249 ;
     RECT  33.048 53.015 33.174 53.249 ;
     RECT  16.524 53.131 17.694 53.285 ;
     RECT  43.236 53.227 44.55 53.285 ;
     RECT  2.415 53.249 3.33 53.321 ;
     RECT  49.32 52.987 49.662 53.365 ;
     RECT  16.524 53.285 17.19 53.401 ;
     RECT  30.96 52.747 31.914 53.401 ;
     RECT  33.048 53.249 33.138 53.401 ;
     RECT  40.215 52.205 40.497 53.401 ;
     RECT  45.615 53.024 45.897 53.401 ;
     RECT  49.32 53.365 49.734 53.401 ;
     RECT  51.015 51.899 51.297 53.401 ;
     RECT  39.492 53.401 40.497 53.491 ;
     RECT  49.32 53.401 49.878 53.491 ;
     RECT  39.276 53.491 40.497 53.519 ;
     RECT  43.308 53.285 44.55 53.519 ;
     RECT  49.104 53.491 49.878 53.519 ;
     RECT  54.9 53.015 54.99 53.519 ;
     RECT  85.464 49.147 85.482 53.549 ;
     RECT  30.852 53.401 33.138 53.555 ;
     RECT  37.08 53.035 37.098 53.555 ;
     RECT  45.468 53.401 45.897 53.555 ;
     RECT  49.104 53.519 49.662 53.555 ;
     RECT  50.652 53.401 51.297 53.555 ;
     RECT  52.776 53.491 52.794 53.563 ;
     RECT  39.276 53.519 39.294 53.591 ;
     RECT  43.308 53.519 43.326 53.591 ;
     RECT  49.104 53.555 49.122 53.591 ;
     RECT  52.452 53.563 52.794 53.591 ;
     RECT  16.056 53.401 17.19 53.611 ;
     RECT  15.912 53.611 17.19 53.663 ;
     RECT  54.972 53.519 54.99 53.671 ;
     RECT  52.452 53.591 52.47 53.789 ;
     RECT  44.316 53.519 44.55 53.825 ;
     RECT  44.532 53.825 44.55 53.837 ;
     RECT  31.896 53.555 33.138 53.861 ;
     RECT  34.815 50.315 35.097 53.941 ;
     RECT  45.615 53.555 45.897 53.941 ;
     RECT  56.415 42.989 56.697 53.941 ;
     RECT  45.615 53.941 45.954 54.031 ;
     RECT  16.452 53.663 17.19 54.095 ;
     RECT  32.796 53.861 33.138 54.095 ;
     RECT  54.972 53.671 55.278 54.095 ;
     RECT  54.036 53.905 54.054 54.125 ;
     RECT  45.615 54.031 46.206 54.131 ;
     RECT  86.292 54.103 86.31 54.173 ;
     RECT  33.084 54.095 33.138 54.211 ;
     RECT  34.164 53.941 35.097 54.211 ;
     RECT  47.16 54.139 47.178 54.211 ;
     RECT  56.052 53.941 56.697 54.211 ;
     RECT  31.896 53.861 31.914 54.365 ;
     RECT  55.548 54.211 56.697 54.365 ;
     RECT  30.852 53.555 30.87 54.473 ;
     RECT  47.052 54.211 47.178 54.481 ;
     RECT  56.232 54.365 56.697 54.481 ;
     RECT  2.415 53.321 3.258 54.571 ;
     RECT  13.215 51.917 13.497 54.571 ;
     RECT  47.052 54.481 47.358 54.599 ;
     RECT  56.232 54.481 58.05 54.599 ;
     RECT  48.24 54.481 48.258 54.607 ;
     RECT  2.304 54.571 3.258 54.635 ;
     RECT  33.084 54.211 35.097 54.635 ;
     RECT  47.052 54.599 47.07 54.635 ;
     RECT  56.232 54.599 57.942 54.635 ;
     RECT  58.824 54.481 58.842 54.635 ;
     RECT  16.452 54.095 16.974 54.715 ;
     RECT  34.776 54.635 35.097 54.751 ;
     RECT  4.608 54.751 4.626 54.869 ;
     RECT  31.788 54.751 31.806 54.869 ;
     RECT  33.588 54.635 34.002 54.869 ;
     RECT  48.24 54.607 48.51 54.905 ;
     RECT  15.912 54.715 16.974 54.941 ;
     RECT  2.415 54.635 3.258 55.021 ;
     RECT  33.84 54.869 34.002 55.139 ;
     RECT  48.456 54.905 48.51 55.139 ;
     RECT  33.84 55.139 33.858 55.175 ;
     RECT  56.232 54.635 56.697 55.175 ;
     RECT  57.42 54.635 57.942 55.175 ;
     RECT  2.415 55.021 3.834 55.255 ;
     RECT  34.776 54.751 35.154 55.291 ;
     RECT  36.108 54.751 36.126 55.291 ;
     RECT  34.776 55.291 35.262 55.409 ;
     RECT  57.564 55.175 57.942 55.409 ;
     RECT  85.5 54.679 85.518 55.421 ;
     RECT  36.108 55.291 36.378 55.445 ;
     RECT  57.636 55.409 57.726 55.445 ;
     RECT  57.636 55.445 57.654 55.481 ;
     RECT  17.172 55.021 17.19 55.553 ;
     RECT  59.328 54.679 59.382 55.715 ;
     RECT  48.564 55.255 48.582 55.819 ;
     RECT  48.564 55.819 48.834 55.831 ;
     RECT  59.364 55.715 59.382 55.831 ;
     RECT  15.912 54.941 16.362 55.949 ;
     RECT  48.564 55.831 48.942 55.949 ;
     RECT  16.02 55.949 16.362 55.957 ;
     RECT  39.456 55.561 39.474 55.985 ;
     RECT  48.564 55.949 48.582 55.985 ;
     RECT  49.752 55.831 49.986 56.101 ;
     RECT  16.02 55.957 16.902 56.255 ;
     RECT  43.308 56.101 44.01 56.255 ;
     RECT  49.716 56.101 49.986 56.255 ;
     RECT  0.108 56.203 0.126 56.333 ;
     RECT  36.216 55.445 36.378 56.371 ;
     RECT  49.932 56.255 49.986 56.371 ;
     RECT  42.372 56.065 42.39 56.381 ;
     RECT  43.344 56.255 44.01 56.443 ;
     RECT  49.932 56.371 50.202 56.489 ;
     RECT  34.776 55.409 35.097 56.525 ;
     RECT  37.296 56.371 37.962 56.525 ;
     RECT  43.344 56.443 44.334 56.525 ;
     RECT  49.932 56.489 49.95 56.525 ;
     RECT  34.815 56.525 35.097 56.605 ;
     RECT  36.216 56.371 36.522 56.605 ;
     RECT  37.404 56.525 37.962 56.641 ;
     RECT  44.316 56.525 44.334 56.641 ;
     RECT  51.015 53.555 51.297 56.641 ;
     RECT  6.804 56.569 6.822 56.669 ;
     RECT  16.02 56.255 16.686 56.731 ;
     RECT  14.832 56.569 14.85 56.759 ;
     RECT  34.815 56.605 36.522 56.759 ;
     RECT  37.404 56.641 38.142 56.759 ;
     RECT  44.316 56.641 44.478 56.759 ;
     RECT  44.316 56.759 44.334 56.795 ;
     RECT  45.615 54.131 45.897 56.911 ;
     RECT  36 56.759 36.522 57.001 ;
     RECT  15.984 56.731 16.686 57.037 ;
     RECT  45.612 56.911 45.897 57.065 ;
     RECT  39.168 56.911 39.186 57.145 ;
     RECT  15.804 57.037 16.686 57.181 ;
     RECT  39.168 57.145 39.294 57.181 ;
     RECT  40.215 53.519 40.497 57.181 ;
     RECT  50.868 56.641 51.297 57.259 ;
     RECT  50.868 57.259 51.75 57.271 ;
     RECT  36 57.001 36.558 57.293 ;
     RECT  37.404 56.759 38.106 57.293 ;
     RECT  36 57.293 36.162 57.299 ;
     RECT  85.464 56.011 85.482 57.299 ;
     RECT  46.836 57.181 46.854 57.415 ;
     RECT  37.404 57.293 38.07 57.451 ;
     RECT  46.836 57.415 46.926 57.451 ;
     RECT  50.724 57.271 51.75 57.451 ;
     RECT  53.568 57.259 53.586 57.451 ;
     RECT  52.668 57.451 53.73 57.547 ;
     RECT  54.576 57.451 54.594 57.547 ;
     RECT  39.168 57.181 40.497 57.569 ;
     RECT  46.836 57.451 47.07 57.569 ;
     RECT  50.724 57.451 51.894 57.569 ;
     RECT  46.836 57.569 46.926 57.581 ;
     RECT  37.116 57.451 38.07 57.605 ;
     RECT  46.836 57.581 46.854 57.605 ;
     RECT  52.668 57.547 54.594 57.605 ;
     RECT  38.988 57.577 39.042 57.721 ;
     RECT  39.888 57.569 40.497 57.721 ;
     RECT  2.415 55.255 3.942 57.835 ;
     RECT  37.296 57.605 38.07 57.839 ;
     RECT  52.668 57.605 52.758 57.839 ;
     RECT  15.804 57.181 16.866 57.869 ;
     RECT  37.296 57.839 37.89 57.875 ;
     RECT  39.888 57.721 41.022 57.875 ;
     RECT  50.724 57.569 51.297 57.875 ;
     RECT  52.668 57.839 52.686 57.875 ;
     RECT  15.912 57.869 16.866 57.983 ;
     RECT  85.176 57.883 85.194 57.983 ;
     RECT  2.304 57.835 3.942 57.991 ;
     RECT  15.984 57.983 16.866 57.991 ;
     RECT  40.215 57.875 41.022 57.991 ;
     RECT  53.748 57.605 54.594 57.991 ;
     RECT  34.815 56.759 35.097 58.075 ;
     RECT  12.6 54.571 13.497 58.081 ;
     RECT  61.815 4.919 62.097 58.081 ;
     RECT  33.084 57.931 33.102 58.109 ;
     RECT  53.748 57.991 55.062 58.109 ;
     RECT  2.304 57.991 4.41 58.145 ;
     RECT  38.916 57.721 39.042 58.145 ;
     RECT  40.215 57.991 41.166 58.145 ;
     RECT  53.748 58.109 53.766 58.145 ;
     RECT  54.576 58.109 55.062 58.145 ;
     RECT  2.415 58.145 4.41 58.289 ;
     RECT  56.415 55.175 56.697 58.363 ;
     RECT  33.876 58.261 33.894 58.379 ;
     RECT  39.024 58.145 39.042 58.379 ;
     RECT  40.215 58.145 41.058 58.379 ;
     RECT  54.612 58.145 55.062 58.379 ;
     RECT  54.756 58.379 55.062 58.415 ;
     RECT  34.632 58.075 35.097 58.531 ;
     RECT  49.932 58.531 49.95 58.603 ;
     RECT  56.415 58.363 57.006 58.621 ;
     RECT  46.764 58.531 46.782 58.649 ;
     RECT  55.512 58.531 55.53 58.649 ;
     RECT  56.415 58.621 57.474 58.651 ;
     RECT  49.932 58.603 49.986 58.657 ;
     RECT  51.015 57.875 51.297 58.657 ;
     RECT  42.768 58.351 42.786 58.685 ;
     RECT  61.488 58.081 62.097 58.685 ;
     RECT  49.932 58.657 50.022 58.733 ;
     RECT  15.984 57.991 17.154 58.801 ;
     RECT  49.932 58.733 49.95 58.829 ;
     RECT  51.015 58.657 51.354 58.891 ;
     RECT  15.984 58.801 17.298 58.919 ;
     RECT  55.908 58.651 57.474 58.955 ;
     RECT  34.38 58.531 35.097 58.973 ;
     RECT  36 57.299 36.018 58.973 ;
     RECT  51.015 58.891 51.534 58.991 ;
     RECT  29.415 52.781 29.697 59.029 ;
     RECT  29.415 59.029 29.79 59.069 ;
     RECT  34.815 58.973 35.097 59.071 ;
     RECT  52.848 58.891 52.866 59.071 ;
     RECT  52.452 59.071 53.01 59.189 ;
     RECT  34.815 59.071 35.334 59.225 ;
     RECT  52.452 59.189 52.47 59.225 ;
     RECT  15.984 58.919 17.19 59.233 ;
     RECT  37.08 58.699 37.098 59.341 ;
     RECT  53.928 59.071 53.946 59.495 ;
     RECT  56.415 58.955 57.474 59.495 ;
     RECT  15.84 59.233 17.19 59.531 ;
     RECT  0.144 59.467 0.162 59.563 ;
     RECT  0.072 59.563 0.162 59.597 ;
     RECT  36.864 59.341 37.098 59.611 ;
     RECT  54.756 58.415 54.774 59.611 ;
     RECT  38.196 59.611 38.214 59.701 ;
     RECT  39.456 58.531 39.474 59.701 ;
     RECT  36.864 59.611 37.242 59.729 ;
     RECT  56.415 59.495 57.042 59.755 ;
     RECT  36.864 59.729 36.882 59.765 ;
     RECT  54.036 59.611 54.774 59.765 ;
     RECT  57.816 59.611 57.978 59.789 ;
     RECT  59.364 55.831 60.03 59.881 ;
     RECT  54.144 59.765 54.774 59.999 ;
     RECT  55.692 59.755 57.042 59.999 ;
     RECT  58.032 59.851 58.086 59.999 ;
     RECT  38.196 59.701 39.474 60.035 ;
     RECT  55.8 59.999 57.042 60.035 ;
     RECT  38.196 60.035 38.214 60.071 ;
     RECT  39.456 60.035 39.474 60.151 ;
     RECT  40.215 58.379 40.497 60.151 ;
     RECT  39.456 60.151 40.497 60.305 ;
     RECT  54.504 59.999 54.774 60.305 ;
     RECT  56.016 60.035 57.042 60.305 ;
     RECT  59.04 59.881 60.03 60.305 ;
     RECT  44.028 60.241 44.046 60.341 ;
     RECT  85.464 58.495 85.482 60.413 ;
     RECT  56.415 60.305 57.042 60.421 ;
     RECT  56.415 60.421 57.186 60.539 ;
     RECT  56.415 60.539 57.006 60.575 ;
     RECT  48.42 60.421 48.438 60.845 ;
     RECT  58.032 59.999 58.05 60.845 ;
     RECT  15.84 59.531 17.154 60.961 ;
     RECT  85.5 60.961 85.518 61.037 ;
     RECT  48.528 60.961 48.69 61.079 ;
     RECT  58.14 60.961 58.158 61.079 ;
     RECT  0.072 59.597 0.09 61.099 ;
     RECT  15.84 60.961 17.19 61.151 ;
     RECT  48.528 61.079 48.546 61.229 ;
     RECT  49.644 61.159 49.662 61.231 ;
     RECT  49.464 61.231 49.662 61.385 ;
     RECT  15.84 61.151 17.154 61.469 ;
     RECT  49.608 61.385 49.662 61.501 ;
     RECT  49.608 61.501 49.878 61.619 ;
     RECT  49.608 61.619 49.734 61.655 ;
     RECT  86.292 61.501 86.31 61.709 ;
     RECT  51.015 58.991 51.297 61.771 ;
     RECT  49.608 61.655 49.662 61.889 ;
     RECT  50.652 61.771 51.297 61.925 ;
     RECT  15.984 61.469 17.154 62.033 ;
     RECT  49.644 61.889 49.662 62.033 ;
     RECT  50.724 61.925 51.297 62.159 ;
     RECT  15.984 62.033 17.082 62.275 ;
     RECT  54.756 60.305 54.774 62.311 ;
     RECT  58.176 61.231 58.194 62.311 ;
     RECT  15.804 62.275 17.082 62.333 ;
     RECT  57.708 62.311 58.194 62.401 ;
     RECT  59.364 60.305 60.03 62.401 ;
     RECT  54.432 62.311 54.774 62.429 ;
     RECT  50.832 62.159 51.297 62.465 ;
     RECT  34.815 59.225 35.226 62.581 ;
     RECT  57.708 62.401 60.03 62.581 ;
     RECT  57.564 62.581 60.03 62.621 ;
     RECT  16.056 62.333 17.082 62.771 ;
     RECT  58.176 62.621 60.03 63.041 ;
     RECT  16.056 62.771 16.758 63.098 ;
     RECT  59.364 63.041 60.03 63.121 ;
     RECT  34.815 62.581 35.694 63.211 ;
     RECT  61.815 58.685 62.097 63.211 ;
     RECT  59.364 63.121 60.246 63.239 ;
     RECT  34.815 63.211 36.018 63.275 ;
     RECT  39.456 60.305 39.474 63.275 ;
     RECT  59.364 63.239 60.102 63.275 ;
     RECT  40.215 60.305 40.497 63.391 ;
     RECT  61.524 63.211 62.097 63.391 ;
     RECT  35.856 63.275 36.018 63.509 ;
     RECT  15.876 63.098 16.758 63.661 ;
     RECT  35.856 63.509 35.874 63.725 ;
     RECT  36.792 63.661 36.81 63.815 ;
     RECT  61.092 63.391 62.097 63.815 ;
     RECT  43.56 63.787 43.578 63.823 ;
     RECT  38.772 63.751 38.79 63.851 ;
     RECT  43.164 63.823 43.578 63.931 ;
     RECT  15.876 63.661 16.866 64.021 ;
     RECT  45.615 57.065 45.897 64.021 ;
     RECT  43.164 63.931 43.722 64.049 ;
     RECT  43.164 64.049 43.182 64.085 ;
     RECT  44.748 63.931 44.766 64.085 ;
     RECT  61.704 63.815 62.097 64.085 ;
     RECT  45.615 64.021 45.99 64.201 ;
     RECT  61.815 64.085 62.097 64.201 ;
     RECT  44.892 64.201 46.062 64.319 ;
     RECT  44.892 64.319 45.897 64.355 ;
     RECT  61.815 64.201 62.658 64.355 ;
     RECT  15.876 64.021 17.046 64.435 ;
     RECT  15.66 64.435 17.046 64.471 ;
     RECT  15.66 64.471 17.118 64.741 ;
     RECT  46.836 64.201 46.854 64.859 ;
     RECT  51.015 62.465 51.297 64.939 ;
     RECT  15.66 64.741 17.19 64.975 ;
     RECT  15.444 64.975 17.19 65.165 ;
     RECT  50.4 64.939 51.297 65.165 ;
     RECT  14.544 57.847 14.562 65.245 ;
     RECT  15.444 65.165 17.082 65.245 ;
     RECT  14.544 65.245 17.082 65.273 ;
     RECT  50.724 65.165 51.297 65.273 ;
     RECT  54.756 62.429 54.774 65.281 ;
     RECT  54.648 65.281 54.774 65.435 ;
     RECT  54.756 65.435 54.774 65.551 ;
     RECT  54.756 65.551 55.134 65.563 ;
     RECT  56.415 60.575 56.697 65.563 ;
     RECT  53.712 65.137 53.73 65.597 ;
     RECT  54.756 65.563 56.697 65.705 ;
     RECT  55.692 65.705 56.697 65.821 ;
     RECT  55.692 65.821 56.79 65.975 ;
     RECT  0.072 61.099 0.162 65.995 ;
     RECT  85.464 62.275 85.482 66.083 ;
     RECT  14.544 65.273 16.722 66.631 ;
     RECT  84.924 66.595 84.942 66.701 ;
     RECT  25.344 66.487 25.362 66.749 ;
     RECT  14.544 66.631 17.154 66.785 ;
     RECT  54.756 65.705 54.774 67.325 ;
     RECT  85.464 67.288 85.482 67.325 ;
     RECT  7.815 43.799 8.097 67.441 ;
     RECT  67.215 41.747 67.497 67.441 ;
     RECT  85.176 67.915 85.194 68.009 ;
     RECT  39.564 63.391 40.497 68.099 ;
     RECT  7.815 67.441 8.19 68.107 ;
     RECT  7.164 68.107 8.19 68.144 ;
     RECT  39.636 68.099 40.497 68.251 ;
     RECT  39.636 68.251 40.59 68.279 ;
     RECT  45.615 64.355 45.897 68.341 ;
     RECT  40.215 68.279 40.59 68.521 ;
     RECT  2.415 58.289 3.942 68.639 ;
     RECT  45.54 68.341 45.897 68.675 ;
     RECT  50.256 68.635 50.274 68.675 ;
     RECT  40.215 68.521 40.734 68.909 ;
     RECT  40.215 68.909 40.59 68.945 ;
     RECT  51.015 65.273 51.297 69.061 ;
     RECT  58.176 63.041 58.194 69.485 ;
     RECT  70.704 68.377 70.722 69.493 ;
     RECT  51.015 69.061 51.426 69.601 ;
     RECT  85.464 68.539 85.482 69.827 ;
     RECT  51.015 69.601 51.714 69.835 ;
     RECT  51.015 69.835 51.786 69.871 ;
     RECT  56.415 65.975 56.79 69.871 ;
     RECT  51.015 69.871 51.93 69.989 ;
     RECT  52.704 69.871 53.19 70.025 ;
     RECT  51.015 69.989 51.786 70.157 ;
     RECT  59.364 63.275 60.03 70.231 ;
     RECT  52.776 70.025 53.19 70.295 ;
     RECT  53.172 70.295 53.19 70.411 ;
     RECT  84.924 70.375 84.942 70.445 ;
     RECT  53.172 70.411 53.298 70.529 ;
     RECT  54.9 70.411 54.918 70.529 ;
     RECT  53.172 70.529 53.19 70.565 ;
     RECT  54.072 70.411 54.09 70.565 ;
     RECT  58.716 70.231 60.03 70.565 ;
     RECT  0.072 65.995 0.198 70.573 ;
     RECT  61.815 64.355 62.097 70.645 ;
     RECT  63.252 64.363 63.27 70.645 ;
     RECT  80.136 44.915 80.406 70.681 ;
     RECT  0.036 70.573 0.198 70.685 ;
     RECT  61.815 70.645 62.298 70.685 ;
     RECT  63.252 70.645 63.378 70.915 ;
     RECT  63.252 70.915 63.486 70.951 ;
     RECT  63.252 70.951 63.702 71.323 ;
     RECT  63.252 71.323 63.918 71.491 ;
     RECT  65.16 71.311 65.178 71.491 ;
     RECT  63.252 71.491 64.098 71.609 ;
     RECT  63.252 71.609 63.81 71.645 ;
     RECT  64.872 71.491 65.178 71.645 ;
     RECT  5.58 71.653 5.598 71.693 ;
     RECT  5.796 71.761 5.814 71.837 ;
     RECT  61.815 70.685 62.097 71.899 ;
     RECT  64.98 71.645 65.178 71.951 ;
     RECT  61.815 71.899 62.262 72.149 ;
     RECT  63.252 71.645 63.378 72.365 ;
     RECT  7.272 68.144 8.19 72.931 ;
     RECT  85.464 71.035 85.482 72.959 ;
     RECT  14.544 66.785 16.506 73.003 ;
     RECT  7.272 72.931 8.766 73.037 ;
     RECT  14.544 73.003 17.046 73.111 ;
     RECT  33.264 66.631 33.282 73.265 ;
     RECT  63.252 72.365 63.27 73.265 ;
     RECT  59.364 70.565 60.03 73.339 ;
     RECT  56.415 69.871 57.078 73.381 ;
     RECT  59.364 73.339 60.498 73.381 ;
     RECT  61.815 72.149 62.097 73.381 ;
     RECT  59.364 73.381 60.642 73.499 ;
     RECT  56.415 73.381 57.222 73.535 ;
     RECT  61.416 73.381 62.097 73.535 ;
     RECT  85.5 73.381 85.518 73.565 ;
     RECT  83.415 45.023 83.697 73.615 ;
     RECT  12.348 58.081 13.497 73.741 ;
     RECT  83.415 73.615 83.898 73.769 ;
     RECT  14.544 73.111 17.19 73.805 ;
     RECT  10.908 73.777 10.926 73.913 ;
     RECT  10.116 73.885 10.134 74.011 ;
     RECT  86.292 73.507 86.31 74.083 ;
     RECT  7.272 73.037 8.19 74.155 ;
     RECT  86.256 74.083 86.31 74.189 ;
     RECT  83.415 73.769 83.826 74.191 ;
     RECT  63.216 73.921 63.234 74.281 ;
     RECT  65.16 71.951 65.178 74.281 ;
     RECT  7.272 74.155 8.298 74.299 ;
     RECT  63.216 74.281 63.414 74.299 ;
     RECT  82.836 74.191 83.826 74.309 ;
     RECT  7.272 74.299 8.514 74.345 ;
     RECT  15.696 73.805 17.19 74.345 ;
     RECT  63.216 74.299 63.774 74.345 ;
     RECT  5.76 74.317 5.778 74.381 ;
     RECT  64.944 74.281 65.178 74.425 ;
     RECT  63.396 74.345 63.414 74.453 ;
     RECT  17.172 74.345 17.19 74.461 ;
     RECT  80.136 70.681 80.514 74.461 ;
     RECT  81.36 53.221 81.378 74.461 ;
     RECT  59.364 73.499 60.03 74.489 ;
     RECT  64.764 74.425 65.178 74.615 ;
     RECT  80.136 74.461 81.378 74.623 ;
     RECT  0.036 70.685 0.162 74.659 ;
     RECT  5.904 74.461 5.922 74.669 ;
     RECT  86.256 74.189 86.274 74.813 ;
     RECT  64.944 74.615 65.178 74.849 ;
     RECT  80.136 74.623 81.594 74.885 ;
     RECT  83.016 74.309 83.826 74.921 ;
     RECT  83.232 74.921 83.826 74.965 ;
     RECT  64.98 74.849 65.178 74.993 ;
     RECT  7.272 74.345 8.19 75.091 ;
     RECT  80.136 74.885 81.018 75.091 ;
     RECT  60.012 74.489 60.03 75.119 ;
     RECT  77.472 44.879 78.297 75.127 ;
     RECT  47.232 75.091 47.25 75.211 ;
     RECT  7.272 75.091 8.37 75.245 ;
     RECT  47.232 75.211 47.538 75.299 ;
     RECT  79.812 75.091 81.018 75.389 ;
     RECT  83.232 74.965 83.934 75.389 ;
     RECT  79.812 75.389 80.586 75.425 ;
     RECT  86.292 75.001 86.31 75.437 ;
     RECT  47.232 75.299 47.286 75.533 ;
     RECT  9.576 74.011 10.134 75.541 ;
     RECT  47.232 75.533 47.25 75.581 ;
     RECT  0.036 74.659 0.198 75.787 ;
     RECT  66.924 67.441 67.497 75.839 ;
     RECT  77.472 75.127 78.786 75.929 ;
     RECT  83.232 75.389 83.898 76.001 ;
     RECT  83.232 76.001 83.697 76.081 ;
     RECT  70.056 69.493 70.722 76.109 ;
     RECT  81.576 76.081 81.594 76.171 ;
     RECT  75.24 73.201 75.258 76.207 ;
     RECT  65.016 74.993 65.178 76.235 ;
     RECT  80.208 75.425 80.586 76.315 ;
     RECT  81.396 76.171 81.594 76.315 ;
     RECT  82.944 76.081 83.697 76.351 ;
     RECT  75.096 76.207 75.258 76.441 ;
     RECT  75.096 76.441 75.33 76.477 ;
     RECT  76.68 32.773 76.698 76.477 ;
     RECT  80.208 76.315 81.594 76.477 ;
     RECT  82.476 76.351 83.697 76.477 ;
     RECT  79.56 76.477 81.594 76.621 ;
     RECT  82.44 76.477 83.697 76.621 ;
     RECT  70.704 76.109 70.722 76.649 ;
     RECT  45.615 68.675 45.897 76.711 ;
     RECT  15.696 74.345 16.002 76.775 ;
     RECT  77.472 75.929 78.606 76.819 ;
     RECT  77.472 76.819 78.678 76.855 ;
     RECT  79.56 76.621 83.697 76.855 ;
     RECT  15.984 76.775 16.002 76.891 ;
     RECT  15.984 76.891 16.254 76.981 ;
     RECT  75.096 76.477 76.698 77.03 ;
     RECT  77.472 76.855 83.934 77.03 ;
     RECT  75.096 77.03 83.934 77.117 ;
     RECT  75.096 77.117 82.638 77.512 ;
     RECT  74.952 77.512 82.638 77.549 ;
     RECT  65.016 76.235 65.034 77.585 ;
     RECT  83.412 77.117 83.934 77.693 ;
     RECT  74.988 77.549 82.638 77.819 ;
     RECT  17.172 74.461 17.55 77.855 ;
     RECT  74.988 77.819 82.494 77.855 ;
     RECT  83.415 77.693 83.934 77.855 ;
     RECT  18.615 30.875 18.897 77.935 ;
     RECT  19.62 76.855 19.638 77.935 ;
     RECT  17.46 77.855 17.55 77.963 ;
     RECT  17.532 77.963 17.55 77.971 ;
     RECT  74.988 77.855 82.458 77.981 ;
     RECT  70.596 77.701 70.614 78.089 ;
     RECT  75.06 77.981 82.458 78.161 ;
     RECT  15.984 76.981 16.326 78.205 ;
     RECT  7.272 75.245 8.19 78.233 ;
     RECT  12.348 73.741 13.554 78.241 ;
     RECT  14.544 73.805 14.562 78.241 ;
     RECT  7.272 78.233 8.097 78.269 ;
     RECT  12.348 78.241 14.562 78.395 ;
     RECT  9.576 75.541 10.314 78.403 ;
     RECT  9.576 78.403 10.854 78.431 ;
     RECT  15.912 78.205 16.326 78.475 ;
     RECT  9.792 78.431 10.854 78.503 ;
     RECT  14.544 78.395 14.562 78.511 ;
     RECT  14.544 78.511 14.598 78.539 ;
     RECT  40.215 68.945 40.497 78.619 ;
     RECT  18.615 77.935 19.638 78.637 ;
     RECT  75.096 78.161 82.458 78.637 ;
     RECT  17.532 77.971 17.766 78.665 ;
     RECT  40.215 78.619 40.806 78.781 ;
     RECT  15.66 78.475 16.326 78.907 ;
     RECT  0.036 75.787 0.846 78.971 ;
     RECT  9.792 78.503 10.494 79.043 ;
     RECT  75.096 78.637 82.566 79.043 ;
     RECT  83.415 77.855 83.697 79.051 ;
     RECT  40.215 78.781 41.022 79.229 ;
     RECT  85.464 76.072 85.482 79.229 ;
     RECT  83.124 79.051 83.697 79.241 ;
     RECT  75.096 79.043 82.386 79.249 ;
     RECT  51.015 70.157 51.297 79.321 ;
     RECT  18.576 78.637 19.638 79.483 ;
     RECT  15.408 78.907 16.326 79.511 ;
     RECT  47.376 79.321 47.934 79.519 ;
     RECT  47.376 79.519 48.186 79.555 ;
     RECT  18.576 79.483 20.502 79.591 ;
     RECT  47.268 79.555 48.186 79.591 ;
     RECT  74.664 79.249 82.386 79.591 ;
     RECT  74.52 79.591 82.386 79.661 ;
     RECT  45.615 76.711 46.53 79.675 ;
     RECT  47.268 79.591 48.51 79.675 ;
     RECT  9.792 79.043 10.458 79.681 ;
     RECT  33.66 73.381 33.678 79.717 ;
     RECT  34.815 63.275 35.097 79.717 ;
     RECT  50.688 79.321 51.297 79.745 ;
     RECT  22.104 78.061 22.122 79.753 ;
     RECT  33.66 79.717 35.097 79.753 ;
     RECT  9.072 79.681 10.458 79.781 ;
     RECT  45.615 79.675 48.51 79.789 ;
     RECT  33.552 79.753 35.097 79.805 ;
     RECT  75.168 79.661 82.386 79.861 ;
     RECT  83.415 79.241 83.697 79.861 ;
     RECT  34.2 79.805 35.097 79.951 ;
     RECT  44.64 79.771 44.658 79.951 ;
     RECT  62.964 79.915 62.982 79.951 ;
     RECT  63.792 79.915 63.81 79.979 ;
     RECT  83.415 79.861 83.826 79.979 ;
     RECT  75.168 79.861 82.422 79.987 ;
     RECT  83.415 79.979 83.79 79.987 ;
     RECT  62.892 79.951 62.982 79.997 ;
     RECT  34.2 79.951 35.154 80.011 ;
     RECT  45.615 79.789 48.978 80.059 ;
     RECT  45.576 80.059 48.978 80.087 ;
     RECT  12.348 78.395 13.554 80.095 ;
     RECT  14.58 78.539 14.598 80.095 ;
     RECT  18.576 79.591 20.574 80.095 ;
     RECT  36.36 79.951 36.378 80.095 ;
     RECT  47.916 80.087 48.978 80.095 ;
     RECT  43.956 79.951 44.658 80.107 ;
     RECT  0.036 78.971 0.198 80.123 ;
     RECT  9.468 79.781 10.458 80.131 ;
     RECT  34.2 80.011 35.406 80.131 ;
     RECT  36.252 80.095 36.378 80.131 ;
     RECT  38.412 79.861 38.43 80.131 ;
     RECT  41.904 80.059 41.922 80.131 ;
     RECT  43.632 80.107 44.658 80.131 ;
     RECT  45.576 80.087 46.89 80.131 ;
     RECT  47.916 80.095 49.194 80.131 ;
     RECT  0.18 80.123 0.198 80.159 ;
     RECT  43.632 80.131 46.89 80.159 ;
     RECT  34.2 80.131 37.134 80.249 ;
     RECT  41.904 80.131 41.958 80.251 ;
     RECT  38.412 80.131 38.754 80.257 ;
     RECT  41.724 80.251 41.958 80.257 ;
     RECT  34.2 80.249 35.37 80.285 ;
     RECT  41.724 80.257 42.534 80.293 ;
     RECT  21.672 79.753 22.122 80.329 ;
     RECT  36.36 80.249 37.134 80.357 ;
     RECT  18.576 80.095 20.718 80.365 ;
     RECT  21.672 80.329 22.41 80.365 ;
     RECT  38.412 80.257 39.402 80.365 ;
     RECT  62.964 79.997 62.982 80.381 ;
     RECT  9.468 80.131 10.854 80.395 ;
     RECT  4.176 80.329 4.194 80.401 ;
     RECT  17.64 78.665 17.766 80.401 ;
     RECT  38.088 80.365 39.402 80.401 ;
     RECT  40.215 79.229 40.497 80.401 ;
     RECT  41.724 80.293 42.822 80.401 ;
     RECT  75.168 79.987 83.79 80.401 ;
     RECT  86.292 79.717 86.31 80.477 ;
     RECT  12.348 80.095 14.598 80.491 ;
     RECT  15.66 79.511 16.326 80.491 ;
     RECT  17.496 80.401 17.766 80.491 ;
     RECT  18.576 80.365 22.41 80.491 ;
     RECT  24.015 30.029 24.297 80.491 ;
     RECT  56.415 73.535 56.697 80.491 ;
     RECT  67.215 75.839 67.497 80.491 ;
     RECT  74.988 80.401 83.79 80.491 ;
     RECT  4.176 80.401 4.626 80.519 ;
     RECT  9.468 80.395 11.106 80.519 ;
     RECT  43.848 80.159 46.89 80.519 ;
     RECT  56.304 80.491 56.697 80.528 ;
     RECT  67.104 80.491 67.497 80.528 ;
     RECT  51.015 79.745 51.297 80.539 ;
     RECT  36.864 80.357 37.134 80.555 ;
     RECT  7.815 78.269 8.097 80.587 ;
     RECT  74.772 80.491 83.79 80.587 ;
     RECT  15.66 80.491 16.65 80.599 ;
     RECT  29.415 59.069 29.697 80.599 ;
     RECT  47.916 80.131 49.662 80.599 ;
     RECT  37.116 80.555 37.134 80.629 ;
     RECT  2.415 68.639 3.258 80.635 ;
     RECT  11.952 80.491 14.598 80.635 ;
     RECT  15.66 80.599 16.722 80.635 ;
     RECT  47.916 80.599 49.842 80.635 ;
     RECT  2.412 80.635 3.258 80.671 ;
     RECT  17.46 80.491 17.766 80.671 ;
     RECT  27.684 80.599 27.702 80.671 ;
     RECT  37.116 80.629 37.314 80.671 ;
     RECT  38.088 80.401 40.497 80.671 ;
     RECT  41.724 80.401 43.038 80.671 ;
     RECT  47.916 80.635 50.058 80.671 ;
     RECT  51.015 80.539 51.894 80.671 ;
     RECT  2.412 80.671 3.438 80.683 ;
     RECT  74.664 80.587 83.79 80.761 ;
     RECT  26.928 80.635 26.946 80.779 ;
     RECT  27.684 80.671 27.99 80.779 ;
     RECT  29.415 80.599 30.006 80.779 ;
     RECT  11.844 80.635 16.722 80.789 ;
     RECT  37.116 80.671 40.497 80.789 ;
     RECT  2.304 80.683 3.438 80.797 ;
     RECT  4.176 80.519 4.59 80.797 ;
     RECT  26.928 80.779 27.99 80.797 ;
     RECT  9.468 80.519 10.854 80.825 ;
     RECT  37.116 80.789 37.134 80.825 ;
     RECT  11.952 80.789 16.722 80.827 ;
     RECT  17.46 80.671 17.802 80.827 ;
     RECT  25.164 80.797 25.182 80.827 ;
     RECT  38.124 80.789 40.497 80.833 ;
     RECT  41.364 80.671 43.038 80.833 ;
     RECT  26.28 80.797 27.99 80.861 ;
     RECT  30.744 80.599 30.762 80.861 ;
     RECT  34.2 80.285 35.097 80.861 ;
     RECT  18.576 80.491 22.806 80.869 ;
     RECT  23.904 80.491 24.297 80.869 ;
     RECT  25.092 80.827 25.182 80.869 ;
     RECT  38.124 80.833 43.038 80.905 ;
     RECT  43.848 80.519 46.854 80.905 ;
     RECT  47.916 80.671 51.894 80.923 ;
     RECT  74.664 80.761 83.97 80.923 ;
     RECT  7.815 80.587 8.73 80.941 ;
     RECT  9.468 80.825 10.818 80.941 ;
     RECT  26.28 80.861 27.27 80.941 ;
     RECT  29.016 80.779 30.006 80.941 ;
     RECT  34.704 80.861 35.097 80.969 ;
     RECT  18.576 80.869 25.182 81.019 ;
     RECT  11.952 80.827 17.802 81.031 ;
     RECT  18.576 81.019 25.254 81.031 ;
     RECT  38.124 80.905 46.854 81.059 ;
     RECT  28.404 80.941 30.006 81.095 ;
     RECT  38.124 81.059 46.602 81.095 ;
     RECT  26.208 80.941 27.27 81.103 ;
     RECT  45.54 81.095 46.602 81.131 ;
     RECT  61.815 73.535 62.097 81.139 ;
     RECT  30.852 80.905 30.87 81.175 ;
     RECT  60.408 81.139 60.426 81.175 ;
     RECT  61.56 81.139 62.097 81.259 ;
     RECT  0.108 81.211 0.126 81.301 ;
     RECT  11.952 81.031 25.254 81.301 ;
     RECT  26.1 81.103 27.27 81.301 ;
     RECT  47.844 80.923 51.894 81.301 ;
     RECT  52.848 80.941 52.866 81.301 ;
     RECT  56.415 80.528 56.697 81.301 ;
     RECT  45.576 81.131 46.602 81.329 ;
     RECT  47.844 81.301 52.866 81.337 ;
     RECT  60.408 81.175 60.786 81.337 ;
     RECT  61.56 81.259 62.442 81.337 ;
     RECT  63.36 81.139 63.378 81.337 ;
     RECT  28.548 81.095 30.006 81.365 ;
     RECT  30.852 81.175 31.518 81.365 ;
     RECT  71.784 81.211 71.802 81.373 ;
     RECT  74.52 80.923 83.97 81.373 ;
     RECT  38.124 81.095 44.19 81.401 ;
     RECT  59.868 81.337 60.786 81.401 ;
     RECT  85.464 81.067 85.482 81.401 ;
     RECT  56.415 81.301 57.186 81.403 ;
     RECT  56.232 81.403 57.186 81.451 ;
     RECT  2.304 80.797 4.59 81.481 ;
     RECT  5.94 81.409 5.958 81.481 ;
     RECT  47.844 81.337 53.118 81.481 ;
     RECT  54.684 81.175 54.702 81.481 ;
     RECT  61.56 81.337 63.378 81.481 ;
     RECT  2.304 81.481 5.166 81.509 ;
     RECT  2.34 81.509 5.166 81.595 ;
     RECT  5.94 81.481 6.03 81.595 ;
     RECT  38.124 81.401 39.402 81.595 ;
     RECT  71.712 81.373 71.802 81.595 ;
     RECT  6.84 81.211 6.858 81.643 ;
     RECT  7.815 80.941 10.818 81.643 ;
     RECT  11.952 81.301 27.27 81.643 ;
     RECT  37.44 81.595 39.402 81.643 ;
     RECT  28.692 81.365 30.006 81.679 ;
     RECT  30.852 81.365 31.014 81.679 ;
     RECT  37.008 81.643 39.402 81.679 ;
     RECT  53.928 81.481 54.702 81.679 ;
     RECT  36.576 81.679 39.402 81.715 ;
     RECT  53.928 81.679 54.738 81.715 ;
     RECT  69.804 81.337 69.822 81.715 ;
     RECT  84.888 81.643 84.906 81.725 ;
     RECT  6.84 81.643 10.962 81.751 ;
     RECT  11.952 81.643 27.594 81.751 ;
     RECT  47.34 81.481 53.118 81.751 ;
     RECT  53.928 81.715 55.278 81.751 ;
     RECT  67.215 80.528 67.497 81.751 ;
     RECT  72.615 41.741 72.897 81.751 ;
     RECT  36.036 81.715 39.402 81.877 ;
     RECT  47.34 81.751 55.278 81.877 ;
     RECT  56.232 81.451 57.438 81.877 ;
     RECT  45.615 81.329 46.602 81.913 ;
     RECT  47.34 81.877 57.438 81.913 ;
     RECT  69.228 81.715 69.822 81.913 ;
     RECT  71.028 81.595 71.802 81.913 ;
     RECT  72.576 81.751 72.897 81.913 ;
     RECT  34.815 80.969 35.097 81.985 ;
     RECT  40.14 81.401 44.19 81.985 ;
     RECT  33.876 81.979 33.894 82.021 ;
     RECT  34.632 81.985 35.097 82.021 ;
     RECT  36 81.877 39.402 82.021 ;
     RECT  59.868 81.401 60.066 82.021 ;
     RECT  65.52 81.211 65.538 82.021 ;
     RECT  67.215 81.751 67.554 82.021 ;
     RECT  74.196 81.373 83.97 82.021 ;
     RECT  31.86 81.841 31.878 82.075 ;
     RECT  33.12 81.139 33.138 82.075 ;
     RECT  45.615 81.913 57.438 82.075 ;
     RECT  71.028 81.913 72.897 82.075 ;
     RECT  28.692 81.679 31.014 82.111 ;
     RECT  31.86 82.075 33.138 82.111 ;
     RECT  33.876 82.021 35.097 82.111 ;
     RECT  40.14 81.985 44.658 82.111 ;
     RECT  45.615 82.075 58.662 82.111 ;
     RECT  61.056 81.481 64.458 82.111 ;
     RECT  65.268 82.021 65.538 82.111 ;
     RECT  66.348 81.985 66.366 82.111 ;
     RECT  67.104 82.021 67.554 82.111 ;
     RECT  71.028 82.075 72.918 82.111 ;
     RECT  2.34 81.595 6.03 82.147 ;
     RECT  6.84 81.751 27.594 82.147 ;
     RECT  35.82 82.021 39.402 82.147 ;
     RECT  40.14 82.111 58.662 82.147 ;
     RECT  66.348 82.111 67.554 82.147 ;
     RECT  68.4 81.913 69.822 82.147 ;
     RECT  28.692 82.111 35.097 82.171 ;
     RECT  35.82 82.147 58.662 82.171 ;
     RECT  66.348 82.147 69.822 82.171 ;
     RECT  59.688 82.021 60.066 82.183 ;
     RECT  61.056 82.111 65.538 82.183 ;
     RECT  66.348 82.171 69.858 82.183 ;
     RECT  71.028 82.111 73.17 82.183 ;
     RECT  74.196 82.021 84.042 82.183 ;
     RECT  85.5 82.183 85.518 82.219 ;
     RECT  28.692 82.171 58.662 82.291 ;
     RECT  59.436 82.183 60.066 82.291 ;
     RECT  60.948 82.183 69.858 82.291 ;
     RECT  0.036 81.301 0.126 82.349 ;
     RECT  71.028 82.183 84.042 82.417 ;
     RECT  2.34 82.147 27.594 82.453 ;
     RECT  28.332 82.291 69.858 82.453 ;
     RECT  70.812 82.417 84.042 82.453 ;
     RECT  86.292 81.751 86.31 82.453 ;
     RECT  2.34 82.453 84.042 82.831 ;
     RECT  85.5 82.219 85.554 82.973 ;
     RECT  2.304 82.831 84.042 83.029 ;
     RECT  2.304 83.029 84.402 83.563 ;
     RECT  85.5 82.973 85.518 83.563 ;
     RECT  86.292 82.453 86.382 83.569 ;
     RECT  2.304 83.563 85.518 83.669 ;
     RECT  85.5 83.669 85.518 83.731 ;
     RECT  86.256 83.569 86.382 83.731 ;
     RECT  2.304 83.669 84.402 83.759 ;
     RECT  0.036 82.349 0.054 83.803 ;
     RECT  2.376 83.759 78.858 83.831 ;
     RECT  0.036 83.803 0.126 83.837 ;
     RECT  2.376 83.831 43.11 83.939 ;
     RECT  43.884 83.831 78.858 83.939 ;
     RECT  0.108 83.837 0.126 83.981 ;
     RECT  2.376 83.939 37.494 84.029 ;
     RECT  38.232 83.939 43.11 84.029 ;
     RECT  43.884 83.939 62.73 84.029 ;
     RECT  63.504 83.939 78.858 84.029 ;
     RECT  79.776 83.759 84.402 84.029 ;
     RECT  22.5 84.029 24.534 84.065 ;
     RECT  73.44 84.029 78.858 84.065 ;
     RECT  2.376 84.029 14.742 84.101 ;
     RECT  15.696 84.029 20.718 84.101 ;
     RECT  27.648 84.029 37.494 84.101 ;
     RECT  38.34 84.029 43.11 84.101 ;
     RECT  65.34 84.029 68.706 84.101 ;
     RECT  22.716 84.065 24.534 84.173 ;
     RECT  43.884 84.029 49.986 84.173 ;
     RECT  53.244 84.029 54.846 84.173 ;
     RECT  2.376 84.101 11.034 84.209 ;
     RECT  25.92 84.029 26.766 84.209 ;
     RECT  28.152 84.101 37.494 84.209 ;
     RECT  38.34 84.101 41.922 84.209 ;
     RECT  43.884 84.173 49.554 84.209 ;
     RECT  54 84.173 54.846 84.209 ;
     RECT  73.44 84.065 74.718 84.209 ;
     RECT  79.956 84.029 84.402 84.209 ;
     RECT  26.208 84.209 26.766 84.221 ;
     RECT  42.732 84.101 43.11 84.221 ;
     RECT  6.48 84.209 9.954 84.257 ;
     RECT  11.772 84.101 14.742 84.257 ;
     RECT  38.34 84.209 41.166 84.257 ;
     RECT  43.884 84.209 48.438 84.257 ;
     RECT  55.656 84.029 59.634 84.257 ;
     RECT  67.215 84.101 68.706 84.257 ;
     RECT  70.74 84.029 72.705 84.257 ;
     RECT  79.956 84.209 83.505 84.257 ;
     RECT  2.376 84.209 3.402 84.365 ;
     RECT  8.424 84.257 9.954 84.365 ;
     RECT  13.644 84.257 14.742 84.365 ;
     RECT  15.696 84.101 17.118 84.365 ;
     RECT  38.34 84.257 39.834 84.365 ;
     RECT  79.956 84.257 83.07 84.365 ;
     RECT  10.692 84.209 11.034 84.413 ;
     RECT  19.656 84.101 20.718 84.413 ;
     RECT  22.716 84.173 24.354 84.413 ;
     RECT  36.432 84.209 37.494 84.413 ;
     RECT  56.88 84.257 59.634 84.413 ;
     RECT  65.34 84.101 66.33 84.413 ;
     RECT  67.572 84.257 68.706 84.413 ;
     RECT  69.48 84.029 69.858 84.413 ;
     RECT  79.956 84.365 81.414 84.413 ;
     RECT  75.636 84.065 78.858 84.845 ;
     RECT  85.5 83.731 86.382 84.845 ;
     RECT  79.956 84.413 79.974 84.883 ;
     RECT  79.848 84.883 79.974 84.911 ;
     RECT  6.48 84.257 7.542 84.941 ;
     RECT  8.424 84.365 8.442 84.941 ;
     RECT  11.772 84.257 12.834 84.941 ;
     RECT  14.724 84.365 14.742 84.941 ;
     RECT  17.1 84.365 17.118 84.941 ;
     RECT  21.456 84.029 21.69 84.941 ;
     RECT  28.152 84.209 35.694 84.941 ;
     RECT  40.824 84.257 41.166 84.941 ;
     RECT  50.724 84.029 52.47 84.941 ;
     RECT  54 84.209 54.81 84.941 ;
     RECT  55.656 84.257 56.142 84.941 ;
     RECT  56.88 84.413 59.094 84.941 ;
     RECT  66.312 84.413 66.33 84.941 ;
     RECT  75.636 84.845 77.886 84.941 ;
     RECT  80.82 84.413 81.414 84.941 ;
     RECT  39.816 84.365 39.834 84.989 ;
     RECT  85.5 84.845 85.554 85.469 ;
     RECT  4.644 84.209 5.706 85.517 ;
     RECT  15.696 84.365 15.93 85.517 ;
     RECT  17.856 84.101 18.918 85.517 ;
     RECT  20.088 84.413 20.718 85.517 ;
     RECT  21.672 84.941 21.69 85.517 ;
     RECT  24.336 84.413 24.354 85.517 ;
     RECT  30.456 84.941 32.202 85.517 ;
     RECT  38.34 84.365 38.898 85.517 ;
     RECT  67.572 84.413 68.13 85.517 ;
     RECT  70.74 84.257 72.486 85.517 ;
     RECT  78.84 84.845 78.858 85.517 ;
     RECT  80.82 84.941 80.838 85.517 ;
     RECT  84.276 84.209 84.402 85.517 ;
     RECT  2.376 84.365 2.394 85.613 ;
     RECT  86.364 84.845 86.382 85.963 ;
     RECT  36.432 84.413 37.134 85.997 ;
     RECT  86.292 85.963 86.382 85.997 ;
     RECT  28.152 84.941 29.286 86.045 ;
     RECT  86.292 85.997 86.31 86.093 ;
     RECT  4.644 85.517 5.238 86.237 ;
     RECT  50.724 84.941 51.174 86.237 ;
     RECT  3.132 84.365 3.402 86.285 ;
     RECT  4.716 86.237 5.238 86.285 ;
     RECT  6.48 84.941 6.498 86.285 ;
     RECT  7.524 84.941 7.542 86.285 ;
     RECT  9.36 84.365 9.954 86.285 ;
     RECT  10.692 84.413 10.71 86.285 ;
     RECT  11.772 84.941 12.438 86.285 ;
     RECT  15.696 85.517 15.714 86.285 ;
     RECT  22.716 84.413 23.418 86.285 ;
     RECT  28.548 86.045 29.286 86.285 ;
     RECT  30.456 85.517 30.942 86.285 ;
     RECT  32.184 85.517 32.202 86.285 ;
     RECT  36.432 85.997 36.45 86.285 ;
     RECT  38.88 85.517 38.898 86.285 ;
     RECT  41.904 84.209 41.922 86.285 ;
     RECT  43.092 84.221 43.11 86.285 ;
     RECT  43.884 84.257 45.486 86.285 ;
     RECT  46.224 84.257 48.438 86.285 ;
     RECT  49.176 84.209 49.554 86.285 ;
     RECT  50.724 86.237 50.742 86.285 ;
     RECT  51.912 84.941 51.93 86.285 ;
     RECT  53.244 84.173 53.262 86.285 ;
     RECT  54 84.941 54.018 86.285 ;
     RECT  55.656 84.941 55.674 86.285 ;
     RECT  56.88 84.941 58.698 86.285 ;
     RECT  60.444 84.029 62.73 86.285 ;
     RECT  63.504 84.029 64.602 86.285 ;
     RECT  65.34 84.413 65.358 86.285 ;
     RECT  67.752 85.517 68.13 86.285 ;
     RECT  69.48 84.413 69.498 86.285 ;
     RECT  70.74 85.517 70.758 86.285 ;
     RECT  72.036 85.517 72.486 86.285 ;
     RECT  74.052 84.209 74.718 86.285 ;
     RECT  76.068 84.941 77.886 86.285 ;
     RECT  79.848 84.911 79.866 86.285 ;
     RECT  82.368 84.365 83.07 86.285 ;
     RECT  84.276 85.517 84.294 86.285 ;
     RECT  85.5 85.469 85.518 86.285 ;
     RECT  82.368 86.285 82.386 86.381 ;
    LAYER M4 ;
     RECT  0.025 1.104 0.06 1.128 ;
     RECT  0.025 83.808 0.06 83.832 ;
     RECT  0.097 70.656 0.133 70.92 ;
     RECT  0.097 56.208 0.137 56.328 ;
     RECT  0.133 44.832 0.179 45.048 ;
     RECT  0.133 46.464 0.179 46.776 ;
     RECT  0.133 70.656 0.179 73.032 ;
     RECT  0.179 70.656 0.209 71.688 ;
     RECT  0.181 74.16 0.229 74.376 ;
     RECT  0.229 74.16 0.857 75.816 ;
     RECT  0.277 81.984 1.477 82.008 ;
     RECT  0.181 0.096 1.909 0.216 ;
     RECT  1.909 0.096 2.341 0.264 ;
     RECT  1.477 4.656 2.365 4.68 ;
     RECT  2.101 85.584 2.405 86.28 ;
     RECT  2.365 4.128 2.408 4.68 ;
     RECT  2.365 20.304 2.408 20.376 ;
     RECT  0.181 43.056 2.408 43.224 ;
     RECT  0.179 45.024 2.408 45.048 ;
     RECT  0.179 46.752 2.408 46.776 ;
     RECT  0.137 56.304 2.408 56.328 ;
     RECT  0.209 70.896 2.408 71.688 ;
     RECT  0.179 73.008 2.408 73.032 ;
     RECT  0.857 74.16 2.408 75.192 ;
     RECT  1.477 80.688 2.408 82.008 ;
     RECT  0.901 83.04 2.408 83.064 ;
     RECT  2.408 2.148 2.512 84.252 ;
     RECT  2.512 2.418 2.677 84.252 ;
     RECT  2.677 2.418 2.704 84.36 ;
     RECT  2.704 83.712 2.801 84.36 ;
     RECT  2.704 31.776 2.837 31.8 ;
     RECT  2.704 3.888 2.909 4.92 ;
     RECT  2.801 83.712 2.981 83.736 ;
     RECT  2.704 56.304 3.017 56.664 ;
     RECT  2.341 0.096 3.089 0.504 ;
     RECT  2.704 57.84 3.155 58.152 ;
     RECT  2.704 17.04 3.203 18.84 ;
     RECT  2.909 3.936 3.443 4.92 ;
     RECT  2.704 6.288 3.443 6.312 ;
     RECT  2.704 26.4 3.443 26.808 ;
     RECT  2.704 49.968 3.491 49.992 ;
     RECT  2.704 7.392 3.635 7.416 ;
     RECT  3.017 56.64 3.635 56.664 ;
     RECT  2.704 10.848 3.637 10.872 ;
     RECT  2.704 48.384 3.665 48.408 ;
     RECT  2.704 20.304 3.683 21.672 ;
     RECT  2.704 51.792 3.685 51.816 ;
     RECT  2.704 52.992 3.685 53.016 ;
     RECT  2.704 82.416 3.692 82.44 ;
     RECT  3.203 18.24 3.693 18.84 ;
     RECT  2.704 33.6 3.731 33.624 ;
     RECT  3.685 51.792 3.731 53.016 ;
     RECT  2.704 9.072 3.737 9.096 ;
     RECT  2.704 14.208 3.737 14.232 ;
     RECT  2.704 55.056 3.765 55.08 ;
     RECT  3.685 15.456 3.772 15.48 ;
     RECT  3.731 51.792 3.772 52.344 ;
     RECT  3.685 34.896 3.773 34.92 ;
     RECT  3.692 45.12 3.779 45.144 ;
     RECT  2.704 46.464 3.779 46.488 ;
     RECT  3.692 82.416 3.913 82.728 ;
     RECT  3.693 18.816 4.021 18.84 ;
     RECT  3.089 0.096 4.133 0.216 ;
     RECT  4.133 0.096 4.169 0.12 ;
     RECT  3.443 4.128 4.205 4.92 ;
     RECT  3.443 26.4 4.237 26.424 ;
     RECT  2.704 39.312 4.273 39.336 ;
     RECT  4.237 26.208 4.277 26.424 ;
     RECT  4.273 38.784 4.313 39.336 ;
     RECT  2.405 86.256 4.501 86.28 ;
     RECT  4.021 18.816 4.525 18.984 ;
     RECT  4.525 18.816 4.565 19.368 ;
     RECT  3.203 17.04 4.601 17.064 ;
     RECT  3.683 21.12 4.601 21.144 ;
     RECT  4.501 86.208 4.673 86.28 ;
     RECT  4.481 1.728 5.141 1.752 ;
     RECT  4.277 26.208 5.209 26.232 ;
     RECT  5.209 25.632 5.249 26.232 ;
     RECT  4.673 86.256 5.249 86.28 ;
     RECT  4.309 32.496 5.425 32.52 ;
     RECT  3.913 82.416 5.461 83.304 ;
     RECT  5.425 31.872 5.465 32.52 ;
     RECT  4.565 18.96 5.501 19.368 ;
     RECT  5.101 3.648 5.641 3.672 ;
     RECT  5.461 81.6 5.681 83.304 ;
     RECT  5.677 85.488 5.761 85.512 ;
     RECT  5.641 3.648 5.785 3.72 ;
     RECT  2.704 70.896 5.785 71.688 ;
     RECT  5.425 21.072 5.789 21.096 ;
     RECT  4.313 38.784 5.845 38.808 ;
     RECT  5.785 70.896 5.869 71.832 ;
     RECT  3.685 36.48 5.891 36.504 ;
     RECT  5.797 80.4 5.893 80.424 ;
     RECT  5.681 81.6 5.893 81.624 ;
     RECT  2.704 74.16 5.977 75.192 ;
     RECT  5.465 31.872 6.005 31.896 ;
     RECT  4.849 17.616 6.073 17.64 ;
     RECT  3.772 52.32 6.109 52.344 ;
     RECT  6.073 17.616 6.113 17.736 ;
     RECT  6.109 51.888 6.149 52.344 ;
     RECT  5.281 34.224 6.217 34.248 ;
     RECT  5.845 37.584 6.217 38.808 ;
     RECT  5.365 0.576 6.221 0.6 ;
     RECT  6.217 33.6 6.257 34.248 ;
     RECT  6.217 37.584 6.277 39.144 ;
     RECT  2.704 43.056 6.277 43.08 ;
     RECT  6.277 37.584 6.323 39.912 ;
     RECT  3.805 41.04 6.323 41.064 ;
     RECT  6.323 37.584 6.329 38.808 ;
     RECT  6.113 17.712 6.473 17.736 ;
     RECT  6.277 42.768 6.473 43.08 ;
     RECT  6.109 20.976 6.476 21 ;
     RECT  6.476 20.16 6.563 21 ;
     RECT  4.849 23.52 6.572 23.544 ;
     RECT  5.249 25.632 6.613 25.656 ;
     RECT  6.323 39.888 6.653 39.912 ;
     RECT  6.572 23.328 6.659 23.544 ;
     RECT  5.785 3.648 6.721 3.912 ;
     RECT  4.205 4.896 6.721 4.92 ;
     RECT  4.885 29.76 6.721 29.784 ;
     RECT  6.577 31.344 6.721 31.368 ;
     RECT  6.721 3.648 6.757 4.92 ;
     RECT  5.893 80.4 6.757 81.624 ;
     RECT  5.681 83.04 6.757 83.304 ;
     RECT  6.563 20.976 6.829 21 ;
     RECT  6.901 84.912 7.049 84.936 ;
     RECT  6.229 0.096 7.157 0.12 ;
     RECT  6.613 24.816 7.369 25.656 ;
     RECT  7.261 26.832 7.369 26.856 ;
     RECT  5.501 18.96 7.441 18.984 ;
     RECT  7.369 24.816 7.477 26.856 ;
     RECT  3.769 27.888 7.477 27.912 ;
     RECT  6.277 86.256 7.553 86.28 ;
     RECT  6.721 29.76 7.573 31.368 ;
     RECT  7.441 18.96 7.621 19.368 ;
     RECT  6.829 20.976 7.621 21.672 ;
     RECT  7.525 1.728 7.805 1.752 ;
     RECT  6.757 3.648 7.808 5.352 ;
     RECT  7.621 18.96 7.808 21.672 ;
     RECT  7.477 24.816 7.808 27.912 ;
     RECT  7.573 29.04 7.808 31.368 ;
     RECT  6.257 33.6 7.808 33.624 ;
     RECT  7.621 34.704 7.808 34.728 ;
     RECT  7.261 36.624 7.808 36.648 ;
     RECT  6.329 38.16 7.808 38.808 ;
     RECT  6.473 43.056 7.808 43.08 ;
     RECT  3.733 44.064 7.808 44.088 ;
     RECT  6.149 51.888 7.808 51.912 ;
     RECT  3.155 57.84 7.808 57.864 ;
     RECT  2.704 68.112 7.808 68.136 ;
     RECT  5.869 70.896 7.808 70.92 ;
     RECT  2.704 73.008 7.808 73.032 ;
     RECT  5.977 74.16 7.808 74.184 ;
     RECT  5.977 75.168 7.808 75.192 ;
     RECT  6.757 80.4 7.808 83.304 ;
     RECT  7.808 2.148 7.912 84.252 ;
     RECT  7.912 2.418 8.101 84.252 ;
     RECT  8.101 2.418 8.104 84.936 ;
     RECT  8.104 74.16 8.309 75.24 ;
     RECT  7.957 0.576 8.389 0.6 ;
     RECT  8.309 74.304 8.425 75.24 ;
     RECT  8.104 34.704 8.435 35.064 ;
     RECT  8.104 36.432 8.435 38.184 ;
     RECT  8.104 84.336 8.453 84.936 ;
     RECT  8.435 36.432 8.476 37.08 ;
     RECT  8.435 34.704 8.525 34.824 ;
     RECT  8.389 0.096 8.597 0.6 ;
     RECT  8.104 26.832 8.597 27.096 ;
     RECT  8.104 32.304 8.849 32.328 ;
     RECT  8.104 23.328 9.107 24.648 ;
     RECT  8.104 3.696 9.133 5.352 ;
     RECT  8.453 84.336 9.137 84.36 ;
     RECT  9.107 24.624 9.173 24.648 ;
     RECT  8.435 38.16 9.203 38.184 ;
     RECT  8.476 36.912 9.245 37.08 ;
     RECT  8.104 44.064 9.281 44.088 ;
     RECT  8.104 18.144 9.389 21.144 ;
     RECT  8.525 34.8 9.389 34.824 ;
     RECT  9.253 1.728 9.533 1.752 ;
     RECT  9.389 18.144 9.637 20.328 ;
     RECT  9.637 17.904 9.683 20.328 ;
     RECT  9.245 37.056 9.785 37.08 ;
     RECT  8.104 29.04 9.853 29.064 ;
     RECT  9.107 23.328 9.929 23.352 ;
     RECT  8.597 0.576 10.117 0.6 ;
     RECT  8.104 33.6 10.261 33.624 ;
     RECT  9.709 31.536 10.307 31.56 ;
     RECT  10.261 33.264 10.307 34.344 ;
     RECT  10.117 0.096 10.325 0.6 ;
     RECT  10.307 34.32 10.348 34.344 ;
     RECT  9.683 20.304 10.429 20.328 ;
     RECT  10.429 20.304 10.681 21.144 ;
     RECT  9.301 86.256 10.721 86.28 ;
     RECT  10.249 24.24 10.837 24.264 ;
     RECT  10.033 25.824 10.837 25.848 ;
     RECT  8.597 27.072 10.837 27.096 ;
     RECT  10.837 24.24 10.883 27.096 ;
     RECT  9.853 28.512 10.883 29.064 ;
     RECT  10.883 26.208 10.897 27.096 ;
     RECT  10.883 24.24 11.009 25.08 ;
     RECT  10.861 1.728 11.027 1.752 ;
     RECT  8.104 80.4 11.117 83.304 ;
     RECT  11.005 84.384 11.123 84.408 ;
     RECT  10.753 35.952 11.173 35.976 ;
     RECT  11.173 35.328 11.219 35.976 ;
     RECT  11.009 24.24 11.329 24.264 ;
     RECT  10.307 33.264 11.333 33.288 ;
     RECT  10.883 29.04 11.365 29.064 ;
     RECT  11.257 30.144 11.365 30.168 ;
     RECT  11.329 23.328 11.369 24.264 ;
     RECT  10.681 20.208 11.437 21.144 ;
     RECT  10.897 26.208 11.461 27.336 ;
     RECT  9.133 3.6 11.473 5.352 ;
     RECT  11.437 20.208 11.477 21.432 ;
     RECT  11.365 29.04 11.507 30.168 ;
     RECT  11.545 31.344 11.581 31.368 ;
     RECT  11.581 31.344 11.629 31.944 ;
     RECT  11.461 26.208 11.765 27.912 ;
     RECT  10.325 0.576 11.845 0.6 ;
     RECT  11.765 26.208 11.945 27.096 ;
     RECT  11.219 35.328 11.945 35.352 ;
     RECT  9.683 17.904 11.989 18.984 ;
     RECT  11.989 17.904 12.053 19.128 ;
     RECT  11.845 0.096 12.161 0.6 ;
     RECT  12.053 18.96 12.161 19.128 ;
     RECT  11.477 20.208 12.161 20.232 ;
     RECT  11.701 86.256 12.449 86.28 ;
     RECT  11.945 27.072 12.769 27.096 ;
     RECT  12.689 1.728 12.773 1.752 ;
     RECT  12.053 17.904 12.877 17.928 ;
     RECT  11.369 23.328 12.877 23.352 ;
     RECT  12.805 84.912 12.947 84.936 ;
     RECT  11.149 44.976 13.052 45 ;
     RECT  11.473 3.456 13.093 5.352 ;
     RECT  13.093 3.312 13.208 5.352 ;
     RECT  12.877 17.664 13.208 17.928 ;
     RECT  12.161 18.96 13.208 18.984 ;
     RECT  11.477 21.408 13.208 21.432 ;
     RECT  12.877 23.328 13.208 23.976 ;
     RECT  12.841 25.824 13.208 25.848 ;
     RECT  12.769 27.072 13.208 27.72 ;
     RECT  11.507 29.616 13.208 30.168 ;
     RECT  11.629 31.728 13.208 31.944 ;
     RECT  11.365 33.936 13.208 33.96 ;
     RECT  8.104 43.056 13.208 43.08 ;
     RECT  13.052 44.976 13.208 45.72 ;
     RECT  13.093 46.8 13.208 46.824 ;
     RECT  8.104 51.888 13.208 51.912 ;
     RECT  8.104 57.84 13.208 57.864 ;
     RECT  8.104 70.896 13.208 70.92 ;
     RECT  8.104 73.008 13.208 73.032 ;
     RECT  8.425 74.304 13.208 74.328 ;
     RECT  11.117 80.496 13.208 83.304 ;
     RECT  12.161 0.576 13.213 0.6 ;
     RECT  13.208 2.148 13.312 84.36 ;
     RECT  13.312 2.418 13.504 84.36 ;
     RECT  13.504 25.44 13.619 29.016 ;
     RECT  13.504 30.144 13.619 30.264 ;
     RECT  13.619 25.44 13.948 28.488 ;
     RECT  13.504 23.328 13.953 23.976 ;
     RECT  13.573 0.096 14.051 0.12 ;
     RECT  13.504 84.336 14.177 84.36 ;
     RECT  13.504 17.664 14.243 21.672 ;
     RECT  13.504 33.648 14.257 33.672 ;
     RECT  13.948 26.208 14.285 28.488 ;
     RECT  14.243 18.384 14.357 21.672 ;
     RECT  14.357 18.576 14.524 21.672 ;
     RECT  14.285 28.464 14.741 28.488 ;
     RECT  13.953 23.328 14.753 23.352 ;
     RECT  14.669 84.912 14.753 84.936 ;
     RECT  13.619 30.24 14.819 30.264 ;
     RECT  14.524 21.648 14.821 21.672 ;
     RECT  14.741 28.464 14.825 29.208 ;
     RECT  13.504 70.896 14.861 70.92 ;
     RECT  14.821 21.648 14.905 22.2 ;
     RECT  14.524 18.576 15.155 20.616 ;
     RECT  13.504 3.264 15.253 5.352 ;
     RECT  15.155 18.576 15.257 18.888 ;
     RECT  14.285 26.208 15.325 27.192 ;
     RECT  15.301 2.16 15.473 2.184 ;
     RECT  15.253 3.264 15.617 5.64 ;
     RECT  14.821 24.912 15.644 24.936 ;
     RECT  15.301 86.256 15.725 86.28 ;
     RECT  15.644 24.912 15.731 25.176 ;
     RECT  13.504 46.8 15.74 46.824 ;
     RECT  13.504 51.888 15.781 51.912 ;
     RECT  15.74 46.8 15.797 47.304 ;
     RECT  15.788 61.44 15.821 62.328 ;
     RECT  15.797 47.28 15.827 47.304 ;
     RECT  15.721 48.432 15.827 48.456 ;
     RECT  15.781 49.488 15.868 49.512 ;
     RECT  15.821 61.44 15.875 63.144 ;
     RECT  15.875 62.976 15.905 63.144 ;
     RECT  15.781 51.408 15.925 51.912 ;
     RECT  14.825 28.464 15.941 28.488 ;
     RECT  13.504 57.84 15.941 57.864 ;
     RECT  15.857 85.488 15.941 85.512 ;
     RECT  15.884 53.616 15.971 53.64 ;
     RECT  15.901 54.72 15.985 54.744 ;
     RECT  15.433 31.344 16.009 31.368 ;
     RECT  16.009 30.816 16.049 31.368 ;
     RECT  15.925 51.408 16.049 52.44 ;
     RECT  15.617 3.312 16.085 5.64 ;
     RECT  15.257 18.576 16.085 18.6 ;
     RECT  14.417 0.576 16.265 0.6 ;
     RECT  14.905 21.648 16.369 21.672 ;
     RECT  15.325 26.208 16.481 27.336 ;
     RECT  13.504 74.304 16.481 74.328 ;
     RECT  16.477 84.336 16.561 84.36 ;
     RECT  16.369 21.648 16.577 22.152 ;
     RECT  16.481 26.208 16.657 27.096 ;
     RECT  16.577 21.648 16.661 22.824 ;
     RECT  16.657 26.16 16.933 27.096 ;
     RECT  16.933 25.344 17.021 27.096 ;
     RECT  15.155 19.92 17.053 20.616 ;
     RECT  16.661 21.648 17.053 22.632 ;
     RECT  13.504 73.008 17.057 73.032 ;
     RECT  16.049 30.816 17.084 30.84 ;
     RECT  17.084 30 17.125 30.84 ;
     RECT  14.821 17.088 17.129 17.112 ;
     RECT  17.053 19.728 17.129 22.632 ;
     RECT  17.125 29.04 17.129 30.84 ;
     RECT  17.077 84.912 17.164 84.936 ;
     RECT  17.129 29.04 17.171 30.024 ;
     RECT  16.085 3.312 17.489 5.352 ;
     RECT  16.597 0.096 17.525 0.12 ;
     RECT  17.516 24.864 17.603 24.888 ;
     RECT  17.009 1.728 18.101 1.752 ;
     RECT  17.021 26.16 18.169 27.096 ;
     RECT  17.129 19.728 18.229 22.2 ;
     RECT  15.685 23.808 18.229 23.832 ;
     RECT  17.485 15.984 18.241 16.008 ;
     RECT  18.169 26.16 18.385 27.912 ;
     RECT  17.171 29.04 18.385 29.064 ;
     RECT  18.229 19.728 18.493 23.832 ;
     RECT  17.489 3.408 18.608 5.352 ;
     RECT  18.241 15.312 18.608 16.008 ;
     RECT  17.893 17.28 18.608 17.304 ;
     RECT  18.493 18.768 18.608 23.832 ;
     RECT  18.385 25.296 18.608 27.912 ;
     RECT  18.385 29.04 18.608 29.256 ;
     RECT  13.504 43.056 18.608 43.08 ;
     RECT  16.049 51.408 18.608 51.912 ;
     RECT  15.905 62.976 18.608 63 ;
     RECT  13.504 80.4 18.608 83.304 ;
     RECT  18.608 2.148 18.712 84.252 ;
     RECT  18.325 0.576 18.757 0.6 ;
     RECT  18.712 2.418 18.904 84.252 ;
     RECT  18.904 18.816 18.965 20.616 ;
     RECT  17.701 85.488 18.973 85.512 ;
     RECT  18.757 0.528 19.037 0.6 ;
     RECT  18.904 3.408 19.253 5.352 ;
     RECT  18.904 24.48 19.427 29.928 ;
     RECT  19.427 24.48 19.433 28.824 ;
     RECT  19.433 25.68 19.468 28.824 ;
     RECT  19.477 84.384 19.685 84.408 ;
     RECT  19.433 24.48 19.757 24.6 ;
     RECT  18.904 17.616 19.873 17.64 ;
     RECT  19.757 24.48 19.957 24.504 ;
     RECT  18.904 51.408 19.957 51.912 ;
     RECT  19.957 23.856 20.003 24.504 ;
     RECT  19.957 51.264 20.003 51.912 ;
     RECT  18.904 22.464 20.069 22.728 ;
     RECT  20.069 22.464 20.113 22.824 ;
     RECT  20.003 23.856 20.113 23.88 ;
     RECT  18.904 80.4 20.117 83.304 ;
     RECT  20.113 22.128 20.153 23.88 ;
     RECT  18.965 20.496 20.185 20.616 ;
     RECT  20.153 22.128 20.185 23.4 ;
     RECT  20.185 20.496 20.189 23.4 ;
     RECT  19.037 0.576 20.225 0.6 ;
     RECT  19.253 3.504 20.257 5.352 ;
     RECT  20.003 51.264 20.261 51.672 ;
     RECT  20.117 80.448 20.261 83.304 ;
     RECT  18.965 18.816 20.293 19.128 ;
     RECT  20.261 80.496 20.293 83.304 ;
     RECT  20.189 20.544 20.339 23.4 ;
     RECT  20.293 18.192 20.377 19.128 ;
     RECT  20.509 14.064 20.52 14.088 ;
     RECT  18.904 15.312 20.52 15.336 ;
     RECT  20.377 18.72 20.581 19.128 ;
     RECT  20.485 0.096 20.693 0.12 ;
     RECT  18.904 16.56 20.729 16.584 ;
     RECT  20.581 9.648 20.773 9.672 ;
     RECT  20.339 20.544 20.801 21.384 ;
     RECT  20.773 9.504 20.819 9.672 ;
     RECT  19.468 25.68 20.945 27.912 ;
     RECT  20.876 17.28 20.963 17.304 ;
     RECT  20.945 25.68 20.977 25.704 ;
     RECT  20.977 25.44 21.017 25.704 ;
     RECT  20.339 23.088 21.053 23.4 ;
     RECT  20.293 80.496 21.085 83.496 ;
     RECT  20.945 27.12 21.125 27.912 ;
     RECT  20.917 2.16 21.233 2.184 ;
     RECT  20.06 85.488 21.301 85.512 ;
     RECT  21.125 27.12 21.305 27.144 ;
     RECT  21.085 80.496 21.305 83.544 ;
     RECT  20.257 3.456 21.373 5.352 ;
     RECT  21.053 23.376 21.377 23.4 ;
     RECT  20.52 14.064 21.481 15.336 ;
     RECT  21.301 84.912 21.485 85.512 ;
     RECT  20.581 18.72 21.557 19.512 ;
     RECT  21.481 14.064 21.625 15.432 ;
     RECT  21.373 3.456 21.661 5.448 ;
     RECT  21.625 13.632 21.683 15.432 ;
     RECT  21.557 19.2 21.683 19.512 ;
     RECT  21.683 13.632 21.709 15.192 ;
     RECT  21.709 14.592 21.724 15.192 ;
     RECT  20.261 51.648 21.74 51.672 ;
     RECT  21.74 51.264 21.827 51.672 ;
     RECT  20.801 20.544 21.881 21.288 ;
     RECT  21.485 85.488 21.923 85.512 ;
     RECT  21.017 25.44 21.949 25.464 ;
     RECT  21.683 19.488 22.025 19.512 ;
     RECT  21.881 21.072 22.165 21.288 ;
     RECT  22.057 13.008 22.309 13.032 ;
     RECT  22.165 21.072 22.313 22.2 ;
     RECT  22.309 12.48 22.403 13.032 ;
     RECT  21.781 0.576 22.421 0.6 ;
     RECT  21.637 18.192 22.637 18.216 ;
     RECT  22.313 21.072 22.637 21.144 ;
     RECT  21.949 24.48 22.997 25.464 ;
     RECT  19.427 29.904 23.245 29.928 ;
     RECT  22.501 86.256 23.429 86.28 ;
     RECT  22.885 16.512 23.569 16.536 ;
     RECT  21.661 3.456 23.641 5.544 ;
     RECT  21.349 1.728 23.717 1.752 ;
     RECT  23.66 84.384 23.747 84.408 ;
     RECT  23.461 12.528 23.785 12.552 ;
     RECT  23.641 3.408 24.008 5.544 ;
     RECT  20.819 9.504 24.008 9.528 ;
     RECT  23.785 12.528 24.008 13.08 ;
     RECT  21.724 15.168 24.008 15.192 ;
     RECT  23.569 16.512 24.008 17.112 ;
     RECT  22.637 21.12 24.008 21.144 ;
     RECT  22.313 22.176 24.008 22.2 ;
     RECT  23.245 29.904 24.008 30.12 ;
     RECT  18.904 43.056 24.008 43.08 ;
     RECT  21.827 51.648 24.008 51.672 ;
     RECT  18.904 62.976 24.008 63 ;
     RECT  21.305 80.496 24.008 83.304 ;
     RECT  24.008 2.148 24.112 84.252 ;
     RECT  24.112 2.148 24.304 83.982 ;
     RECT  24.277 85.488 24.365 85.512 ;
     RECT  23.941 0.576 24.373 0.6 ;
     RECT  24.373 0.096 24.401 0.6 ;
     RECT  24.304 10.992 24.419 11.352 ;
     RECT  24.419 10.992 24.467 11.256 ;
     RECT  24.401 0.096 24.473 0.12 ;
     RECT  24.304 14.208 24.611 15.864 ;
     RECT  24.611 14.208 25.091 15.336 ;
     RECT  24.304 3.408 25.121 5.544 ;
     RECT  25.121 3.552 25.193 5.544 ;
     RECT  24.304 9.504 25.229 9.672 ;
     RECT  24.304 22.752 25.301 22.776 ;
     RECT  24.304 21.12 25.429 21.144 ;
     RECT  24.304 19.152 25.441 19.176 ;
     RECT  25.429 20.592 25.475 21.144 ;
     RECT  25.405 22.224 25.489 22.248 ;
     RECT  25.229 9.648 25.517 9.672 ;
     RECT  24.785 1.728 25.625 1.752 ;
     RECT  24.467 10.992 25.657 11.016 ;
     RECT  24.304 12.528 25.657 13.08 ;
     RECT  25.657 10.992 25.697 13.08 ;
     RECT  25.697 11.952 25.813 13.08 ;
     RECT  25.091 14.208 25.813 15.192 ;
     RECT  25.813 11.952 25.9 15.192 ;
     RECT  24.304 80.496 26.101 83.928 ;
     RECT  25.9 14.208 26.125 15.192 ;
     RECT  25.441 19.152 26.125 19.416 ;
     RECT  26.125 18.672 26.165 19.416 ;
     RECT  25.193 3.6 26.305 5.544 ;
     RECT  24.304 17.088 26.309 17.112 ;
     RECT  25.475 20.592 26.485 20.616 ;
     RECT  25.669 0.096 26.533 0.12 ;
     RECT  25.9 11.952 26.701 12.744 ;
     RECT  26.305 3.6 26.773 5.592 ;
     RECT  26.485 20.304 26.773 20.616 ;
     RECT  26.233 21.648 26.773 21.672 ;
     RECT  26.101 80.496 26.777 84.216 ;
     RECT  26.701 11.904 26.813 12.744 ;
     RECT  26.773 20.304 26.819 21.672 ;
     RECT  26.819 20.304 26.86 21.096 ;
     RECT  26.813 11.904 26.957 11.928 ;
     RECT  26.773 3.6 26.993 5.64 ;
     RECT  26.533 0.096 27.037 0.216 ;
     RECT  26.125 14.208 27.101 15.672 ;
     RECT  26.165 18.672 27.209 18.696 ;
     RECT  26.993 3.696 27.245 5.64 ;
     RECT  27.101 14.208 27.317 14.568 ;
     RECT  26.777 80.496 27.389 83.832 ;
     RECT  27.397 0.576 27.569 0.6 ;
     RECT  27.101 15.648 27.745 15.672 ;
     RECT  26.86 20.304 27.889 20.616 ;
     RECT  27.877 13.44 27.964 13.464 ;
     RECT  27.889 20.304 28.145 21.672 ;
     RECT  28.145 20.304 28.172 20.616 ;
     RECT  27.877 86.016 28.181 86.04 ;
     RECT  28.172 19.344 28.259 20.616 ;
     RECT  27.529 11.424 28.465 11.448 ;
     RECT  25.405 24.768 28.501 24.792 ;
     RECT  28.177 48.912 28.501 48.936 ;
     RECT  24.304 51.648 28.501 51.672 ;
     RECT  27.745 15.648 28.645 15.96 ;
     RECT  28.145 21.648 28.753 21.672 ;
     RECT  27.245 3.696 28.825 5.592 ;
     RECT  29.149 46.128 29.269 46.152 ;
     RECT  28.493 86.256 29.297 86.28 ;
     RECT  27.809 1.728 29.408 1.752 ;
     RECT  28.825 3.408 29.408 5.592 ;
     RECT  29.077 8.544 29.408 8.568 ;
     RECT  26.701 9.696 29.408 9.72 ;
     RECT  28.465 11.232 29.408 11.448 ;
     RECT  29.365 12.528 29.408 12.552 ;
     RECT  27.317 14.544 29.408 14.568 ;
     RECT  28.645 15.552 29.408 15.96 ;
     RECT  29.077 17.664 29.408 17.688 ;
     RECT  28.259 19.92 29.408 20.616 ;
     RECT  28.753 21.648 29.408 21.768 ;
     RECT  28.501 24.768 29.408 25.08 ;
     RECT  24.304 30.096 29.408 30.12 ;
     RECT  24.304 43.056 29.408 43.08 ;
     RECT  29.269 46.128 29.408 46.344 ;
     RECT  28.501 47.904 29.408 47.928 ;
     RECT  28.501 48.912 29.408 51.672 ;
     RECT  24.304 62.976 29.408 63 ;
     RECT  27.389 80.496 29.408 83.304 ;
     RECT  29.408 1.728 29.681 84.252 ;
     RECT  29.681 1.728 29.704 84.936 ;
     RECT  29.704 84.912 29.765 84.936 ;
     RECT  29.704 58.896 29.843 59.064 ;
     RECT  29.704 62.976 29.843 63 ;
     RECT  29.704 8.304 29.945 9.528 ;
     RECT  29.704 3.408 29.981 5.592 ;
     RECT  29.704 15.552 29.981 15.576 ;
     RECT  29.704 49.776 30.089 49.896 ;
     RECT  29.704 1.728 30.161 1.752 ;
     RECT  29.704 51.648 30.197 51.672 ;
     RECT  29.704 21.744 30.297 21.768 ;
     RECT  29.704 17.664 30.412 19.224 ;
     RECT  29.704 10.848 30.419 13.032 ;
     RECT  29.704 24.96 30.652 27.336 ;
     RECT  29.704 46.32 30.665 46.344 ;
     RECT  30.652 26.208 30.707 27.336 ;
     RECT  30.419 10.848 30.755 12.888 ;
     RECT  30.707 26.688 30.769 27.336 ;
     RECT  30.769 26.688 30.803 27.624 ;
     RECT  29.945 8.304 30.809 8.328 ;
     RECT  29.704 14.4 30.913 14.424 ;
     RECT  30.412 18.816 30.913 19.224 ;
     RECT  29.704 20.496 30.913 20.616 ;
     RECT  30.913 14.4 30.953 14.664 ;
     RECT  30.277 86.256 30.953 86.28 ;
     RECT  29.981 3.6 31.045 5.592 ;
     RECT  31.045 3.36 31.132 5.592 ;
     RECT  29.945 9.504 31.237 9.528 ;
     RECT  30.412 17.664 31.241 17.688 ;
     RECT  30.913 18.816 31.285 20.616 ;
     RECT  31.237 9.072 31.309 9.528 ;
     RECT  31.285 18.816 31.313 21.144 ;
     RECT  31.309 9.072 31.321 9.672 ;
     RECT  31.313 19.2 31.331 21.144 ;
     RECT  29.704 16.56 31.345 16.584 ;
     RECT  31.321 9.648 31.561 9.672 ;
     RECT  30.755 10.848 31.561 11.016 ;
     RECT  31.477 85.488 31.564 85.512 ;
     RECT  31.132 3.6 31.633 5.592 ;
     RECT  30.409 0.096 31.717 0.12 ;
     RECT  31.331 20.592 31.745 21.144 ;
     RECT  31.717 0.096 31.817 0.6 ;
     RECT  30.652 24.96 31.861 24.984 ;
     RECT  31.861 24.48 31.907 24.984 ;
     RECT  29.704 52.752 31.925 52.776 ;
     RECT  30.089 49.776 31.993 49.8 ;
     RECT  31.993 49.536 32.033 49.8 ;
     RECT  30.953 14.64 32.06 14.664 ;
     RECT  31.345 16.128 32.06 16.68 ;
     RECT  32.053 22.416 32.14 22.44 ;
     RECT  30.803 26.784 32.213 27.624 ;
     RECT  32.101 86.256 32.213 86.28 ;
     RECT  31.561 9.648 32.285 11.016 ;
     RECT  31.633 3.6 32.293 5.64 ;
     RECT  31.907 24.48 32.357 24.504 ;
     RECT  32.293 3.6 32.38 6.312 ;
     RECT  30.755 12.864 32.465 12.888 ;
     RECT  32.209 45.6 32.483 45.624 ;
     RECT  32.06 14.64 32.681 16.68 ;
     RECT  31.633 7.44 32.717 7.464 ;
     RECT  31.745 20.592 32.717 20.616 ;
     RECT  31.817 0.096 32.753 0.12 ;
     RECT  32.213 27.6 32.924 27.624 ;
     RECT  32.924 27.6 32.965 27.912 ;
     RECT  32.965 27.6 33.011 28.728 ;
     RECT  32.681 14.64 33.073 16.152 ;
     RECT  29.704 57.024 33.073 57.048 ;
     RECT  29.843 58.896 33.073 58.92 ;
     RECT  33.061 6.816 33.148 6.84 ;
     RECT  29.704 35.952 33.157 35.976 ;
     RECT  33.157 35.952 33.181 36.792 ;
     RECT  33.181 35.952 33.203 37.08 ;
     RECT  33.203 36.768 33.244 37.08 ;
     RECT  33.073 14.496 33.257 16.152 ;
     RECT  29.704 80.496 33.5 83.304 ;
     RECT  32.285 10.56 33.505 11.016 ;
     RECT  32.972 1.728 33.509 1.752 ;
     RECT  33.5 79.776 33.587 83.304 ;
     RECT  33.289 22.224 33.596 22.248 ;
     RECT  33.596 20.976 33.637 22.248 ;
     RECT  33.637 20.976 33.683 22.776 ;
     RECT  33.692 26.496 33.721 26.52 ;
     RECT  33.011 27.6 33.721 27.624 ;
     RECT  33.637 18.048 33.724 18.072 ;
     RECT  33.721 26.496 33.779 27.624 ;
     RECT  31.331 19.2 33.829 19.224 ;
     RECT  32.965 53.76 33.884 53.784 ;
     RECT  33.829 18.816 33.98 19.224 ;
     RECT  33.257 16.128 34.165 16.152 ;
     RECT  33.829 17.664 34.165 17.688 ;
     RECT  32.38 3.6 34.261 5.736 ;
     RECT  33.244 37.056 34.297 37.08 ;
     RECT  33.877 0.096 34.309 0.12 ;
     RECT  34.261 3.6 34.309 6.6 ;
     RECT  33.073 57.024 34.369 58.92 ;
     RECT  34.297 37.056 34.453 37.608 ;
     RECT  32.437 44.448 34.645 44.472 ;
     RECT  33.505 10.272 34.693 11.016 ;
     RECT  34.621 12.528 34.693 12.552 ;
     RECT  34.309 3.456 34.729 6.6 ;
     RECT  33.779 26.736 34.765 27.624 ;
     RECT  34.729 1.728 34.808 1.752 ;
     RECT  34.729 3.408 34.808 6.6 ;
     RECT  34.22 7.584 34.808 7.608 ;
     RECT  33.397 8.832 34.808 8.856 ;
     RECT  34.693 10.272 34.808 12.552 ;
     RECT  33.257 14.496 34.808 14.52 ;
     RECT  34.165 16.128 34.808 17.688 ;
     RECT  33.98 18.816 34.808 19.944 ;
     RECT  33.683 20.976 34.808 21 ;
     RECT  33.683 22.752 34.808 22.776 ;
     RECT  33.397 25.104 34.808 25.128 ;
     RECT  34.765 26.64 34.808 27.624 ;
     RECT  33.011 28.704 34.808 28.728 ;
     RECT  29.704 30.096 34.808 30.12 ;
     RECT  34.453 37.056 34.808 38.424 ;
     RECT  29.704 43.056 34.808 43.08 ;
     RECT  34.645 44.352 34.808 44.472 ;
     RECT  33.757 45.888 34.808 45.912 ;
     RECT  34.693 47.328 34.808 47.352 ;
     RECT  32.033 49.536 34.808 49.56 ;
     RECT  33.925 51.12 34.808 51.144 ;
     RECT  33.884 52.944 34.808 53.784 ;
     RECT  33.576 54.816 34.808 54.84 ;
     RECT  34.369 57.024 34.808 58.968 ;
     RECT  33.587 80.016 34.808 83.304 ;
     RECT  32.677 84.912 34.808 84.936 ;
     RECT  34.808 1.728 34.813 84.936 ;
     RECT  34.813 2.148 34.912 84.936 ;
     RECT  34.912 2.418 35.104 84.936 ;
     RECT  35.104 9.648 35.165 12.552 ;
     RECT  35.104 19.344 35.201 19.368 ;
     RECT  35.104 47.328 35.273 47.496 ;
     RECT  35.104 13.632 35.363 13.848 ;
     RECT  35.104 15.024 35.363 15.432 ;
     RECT  35.104 44.352 35.381 44.472 ;
     RECT  35.381 44.448 35.417 44.472 ;
     RECT  35.104 80.016 35.417 83.304 ;
     RECT  35.104 25.584 35.597 25.608 ;
     RECT  34.309 0.096 35.605 0.168 ;
     RECT  35.104 8.496 35.651 8.52 ;
     RECT  35.165 9.648 35.669 9.672 ;
     RECT  35.104 84.912 35.749 84.936 ;
     RECT  35.605 0.096 35.813 0.6 ;
     RECT  35.104 63.696 35.891 63.72 ;
     RECT  35.104 21.12 36.021 21.144 ;
     RECT  35.165 10.992 36.029 12.552 ;
     RECT  35.104 57.024 36.029 58.968 ;
     RECT  35.363 15.408 36.14 15.432 ;
     RECT  36.14 20.256 36.181 20.28 ;
     RECT  36.14 15.408 36.209 15.672 ;
     RECT  36.209 15.648 36.227 15.672 ;
     RECT  36.181 19.344 36.227 20.28 ;
     RECT  36.029 57.024 36.229 58.728 ;
     RECT  35.104 3.408 36.236 5.64 ;
     RECT  35.104 54.96 36.275 54.984 ;
     RECT  36.236 3.36 36.277 5.64 ;
     RECT  36.229 56.208 36.316 58.728 ;
     RECT  36.277 3.36 36.323 5.736 ;
     RECT  36.277 86.256 36.461 86.28 ;
     RECT  36.029 12 36.467 12.552 ;
     RECT  35.104 7.392 36.493 7.416 ;
     RECT  35.104 30.096 36.493 30.12 ;
     RECT  36.493 7.392 36.533 7.944 ;
     RECT  35.813 0.096 36.569 0.216 ;
     RECT  36.316 57.024 36.569 58.728 ;
     RECT  36.029 10.992 36.605 11.016 ;
     RECT  35.104 38.4 36.713 38.424 ;
     RECT  35.104 26.64 36.853 27.624 ;
     RECT  36.881 1.728 36.965 1.752 ;
     RECT  36.533 7.92 37.001 7.944 ;
     RECT  36.569 57.264 37.069 58.728 ;
     RECT  36.323 3.408 37.073 5.736 ;
     RECT  35.363 13.824 37.073 13.848 ;
     RECT  35.104 53.04 37.109 53.064 ;
     RECT  37.069 57.264 37.109 59.64 ;
     RECT  36.901 85.968 37.145 85.992 ;
     RECT  36.853 26.64 37.181 27.912 ;
     RECT  36.227 19.344 37.321 19.368 ;
     RECT  35.273 47.472 37.325 47.496 ;
     RECT  37.436 84.384 37.523 84.408 ;
     RECT  37.181 26.64 37.541 27.624 ;
     RECT  36.467 12.192 37.613 12.552 ;
     RECT  35.104 22.704 37.621 22.728 ;
     RECT  37.109 59.616 37.621 59.64 ;
     RECT  37.621 22.704 37.667 23.064 ;
     RECT  37.621 59.616 37.667 59.928 ;
     RECT  36.569 0.096 37.765 0.12 ;
     RECT  37.073 3.552 37.969 5.736 ;
     RECT  37.765 0.096 37.973 0.6 ;
     RECT  37.321 19.248 37.973 19.368 ;
     RECT  37.969 3.552 38.077 6.264 ;
     RECT  37.109 57.264 38.077 57.96 ;
     RECT  35.417 80.496 38.149 83.304 ;
     RECT  38.077 3.408 38.225 6.264 ;
     RECT  38.101 85.488 38.369 85.512 ;
     RECT  35.104 51.12 38.405 51.144 ;
     RECT  38.149 80.352 38.621 83.304 ;
     RECT  37.613 12.192 38.653 12.216 ;
     RECT  38.617 1.728 38.701 1.752 ;
     RECT  37.541 27.6 38.828 27.624 ;
     RECT  38.828 27.6 38.861 28.344 ;
     RECT  38.861 27.6 38.876 29.112 ;
     RECT  36.493 30.096 38.876 30.216 ;
     RECT  37.667 23.04 38.905 23.064 ;
     RECT  38.677 86.256 38.909 86.28 ;
     RECT  38.905 23.04 38.945 23.16 ;
     RECT  38.876 27.6 38.945 30.216 ;
     RECT  38.945 29.376 38.963 30.216 ;
     RECT  37.667 59.904 39.161 59.928 ;
     RECT  38.437 10.224 39.193 10.248 ;
     RECT  39.164 26.448 39.205 26.472 ;
     RECT  38.945 27.6 39.205 28.344 ;
     RECT  38.225 3.408 39.229 5.592 ;
     RECT  39.193 9.408 39.301 10.248 ;
     RECT  39.229 3.36 39.493 5.592 ;
     RECT  38.869 7.776 39.553 7.8 ;
     RECT  35.104 68.112 39.625 68.136 ;
     RECT  39.301 84.336 39.805 84.36 ;
     RECT  39.805 84.336 39.923 84.984 ;
     RECT  39.553 6.816 40.069 7.8 ;
     RECT  39.301 8.832 40.069 10.92 ;
     RECT  38.963 29.904 40.069 30.12 ;
     RECT  38.077 57.024 40.069 57.96 ;
     RECT  39.493 2.88 40.208 5.592 ;
     RECT  40.069 6.816 40.208 10.92 ;
     RECT  38.653 12.192 40.208 12.552 ;
     RECT  37.973 19.248 40.208 19.272 ;
     RECT  38.945 23.136 40.208 23.16 ;
     RECT  39.205 26.448 40.208 28.344 ;
     RECT  40.069 29.904 40.208 30.888 ;
     RECT  35.104 43.056 40.208 43.08 ;
     RECT  36.457 44.064 40.208 44.088 ;
     RECT  39.049 48.96 40.208 48.984 ;
     RECT  40.069 56.352 40.208 57.96 ;
     RECT  39.625 68.112 40.208 68.232 ;
     RECT  38.621 80.496 40.208 83.304 ;
     RECT  39.923 84.336 40.208 84.936 ;
     RECT  40.208 2.148 40.337 84.936 ;
     RECT  40.337 1.728 40.421 84.936 ;
     RECT  40.421 2.418 40.504 84.936 ;
     RECT  40.504 22.704 40.691 23.16 ;
     RECT  40.504 30.096 40.691 31.368 ;
     RECT  40.504 19.248 40.739 19.368 ;
     RECT  40.504 42.768 40.739 44.088 ;
     RECT  40.504 68.208 40.739 68.232 ;
     RECT  40.691 30.864 40.781 31.368 ;
     RECT  40.739 19.344 40.835 19.368 ;
     RECT  40.739 42.768 40.835 43.944 ;
     RECT  37.973 0.096 40.861 0.12 ;
     RECT  40.691 22.8 40.931 23.16 ;
     RECT  40.835 43.056 40.931 43.944 ;
     RECT  40.504 48.96 40.979 48.984 ;
     RECT  40.504 51.888 40.979 51.912 ;
     RECT  40.504 8.448 41.116 9.24 ;
     RECT  40.504 84.912 41.177 84.936 ;
     RECT  40.504 7.2 41.277 7.224 ;
     RECT  40.504 26.784 41.429 27.912 ;
     RECT  40.504 80.496 41.557 83.304 ;
     RECT  40.504 78.624 41.603 79.224 ;
     RECT  40.504 12.288 41.605 12.312 ;
     RECT  41.605 12.288 41.651 13.032 ;
     RECT  41.557 80.256 41.753 83.304 ;
     RECT  41.429 27.36 41.789 27.912 ;
     RECT  41.221 0.576 41.861 0.6 ;
     RECT  41.701 86.256 41.933 86.28 ;
     RECT  41.116 8.448 42.005 8.568 ;
     RECT  40.931 23.136 42.073 23.16 ;
     RECT  40.504 3.408 42.077 6.024 ;
     RECT  42.065 1.728 42.149 1.752 ;
     RECT  42.073 22.224 42.157 23.16 ;
     RECT  41.753 80.496 42.277 83.304 ;
     RECT  40.781 31.248 42.38 31.368 ;
     RECT  40.504 56.352 42.401 56.376 ;
     RECT  42.001 39.168 42.421 39.192 ;
     RECT  42.38 31.248 42.467 31.56 ;
     RECT  42.421 39.168 42.467 39.816 ;
     RECT  40.931 43.056 42.509 43.32 ;
     RECT  41.651 13.008 42.757 13.032 ;
     RECT  42.277 80.496 42.761 84.216 ;
     RECT  42.077 3.408 42.797 5.592 ;
     RECT  42.757 12.864 42.797 13.032 ;
     RECT  42.509 43.296 42.797 43.32 ;
     RECT  42.517 0.096 42.949 0.12 ;
     RECT  42.157 23.136 42.977 23.16 ;
     RECT  41.789 27.888 43.333 27.912 ;
     RECT  40.504 57.936 43.619 57.96 ;
     RECT  42.761 80.496 43.621 83.304 ;
     RECT  42.467 31.344 43.805 31.368 ;
     RECT  43.333 27.888 43.813 28.824 ;
     RECT  43.813 27.216 43.9 28.824 ;
     RECT  40.504 52.944 44.005 53.016 ;
     RECT  44.005 52.944 44.051 53.256 ;
     RECT  43.981 50.688 44.065 50.712 ;
     RECT  42.467 39.792 44.129 39.816 ;
     RECT  43.9 27.888 44.377 28.824 ;
     RECT  42.949 0.096 44.417 0.168 ;
     RECT  44.051 52.992 44.521 53.256 ;
     RECT  44.377 27.888 44.561 29.112 ;
     RECT  43.621 80.112 44.629 83.304 ;
     RECT  44.521 52.992 44.677 53.832 ;
     RECT  42.797 3.504 45.608 5.592 ;
     RECT  42.005 8.448 45.608 8.472 ;
     RECT  42.797 12.864 45.608 12.888 ;
     RECT  44.737 23.376 45.608 23.4 ;
     RECT  44.561 27.888 45.608 28.008 ;
     RECT  45.493 30.336 45.608 30.36 ;
     RECT  44.437 38.544 45.608 38.568 ;
     RECT  44.399 40.032 45.608 40.056 ;
     RECT  44.677 52.992 45.608 54.168 ;
     RECT  44.305 56.448 45.608 56.472 ;
     RECT  43.573 59.856 45.608 59.88 ;
     RECT  43.549 63.84 45.608 63.864 ;
     RECT  41.603 78.624 45.608 78.648 ;
     RECT  44.629 79.776 45.608 83.304 ;
     RECT  45.608 2.148 45.712 84.252 ;
     RECT  45.712 2.418 45.904 83.982 ;
     RECT  44.417 0.096 45.973 0.12 ;
     RECT  45.904 40.032 46.073 40.056 ;
     RECT  45.904 51.936 46.217 53.016 ;
     RECT  45.973 0.096 46.289 0.168 ;
     RECT  46.217 51.936 46.3 52.968 ;
     RECT  46.3 52.944 46.541 52.968 ;
     RECT  45.904 2.88 46.721 5.688 ;
     RECT  45.904 12.864 46.973 13.272 ;
     RECT  45.904 27.888 46.973 28.008 ;
     RECT  45.904 23.376 46.988 23.4 ;
     RECT  45.904 8.448 47.027 8.472 ;
     RECT  45.904 78.624 47.027 78.648 ;
     RECT  46.988 23.376 47.045 23.736 ;
     RECT  46.981 75.216 47.18 75.24 ;
     RECT  45.904 54.144 47.189 54.168 ;
     RECT  46.721 3.6 47.225 5.688 ;
     RECT  46.973 27.984 47.261 28.008 ;
     RECT  47.18 75.216 47.267 75.576 ;
     RECT  45.904 79.68 47.267 83.304 ;
     RECT  47.269 2.16 47.513 2.184 ;
     RECT  45.904 38.784 47.801 38.808 ;
     RECT  47.225 3.696 47.939 5.688 ;
     RECT  45.904 30.336 47.941 30.36 ;
     RECT  47.941 30.336 47.981 30.456 ;
     RECT  46.3 51.936 48.085 51.96 ;
     RECT  47.045 23.712 48.301 23.736 ;
     RECT  48.229 50.112 48.323 50.136 ;
     RECT  48.085 51.936 48.323 52.2 ;
     RECT  48.301 23.328 48.341 23.736 ;
     RECT  47.267 79.776 48.449 83.304 ;
     RECT  47.939 3.696 48.517 5.64 ;
     RECT  46.289 0.096 48.773 0.12 ;
     RECT  48.449 80.4 49.097 83.304 ;
     RECT  48.341 23.328 49.349 23.352 ;
     RECT  48.517 3.168 49.489 5.64 ;
     RECT  49.489 3.168 49.565 6.024 ;
     RECT  48.805 55.824 49.573 55.848 ;
     RECT  48.997 1.728 49.601 1.752 ;
     RECT  48.517 61.2 49.705 61.224 ;
     RECT  48.323 52.176 49.717 52.2 ;
     RECT  49.717 51.744 49.763 52.2 ;
     RECT  49.676 53.376 49.763 53.4 ;
     RECT  49.573 55.824 49.763 56.472 ;
     RECT  49.763 56.448 49.909 56.472 ;
     RECT  46.897 57.552 49.909 57.576 ;
     RECT  49.909 58.608 49.949 58.632 ;
     RECT  49.909 56.448 49.955 57.576 ;
     RECT  49.955 56.448 49.961 57.336 ;
     RECT  49.949 58.608 49.997 58.728 ;
     RECT  49.705 61.2 50.003 61.608 ;
     RECT  49.997 58.704 50.033 58.728 ;
     RECT  49.763 51.744 50.06 51.768 ;
     RECT  42.901 86.256 50.677 86.28 ;
     RECT  47.981 30.432 50.725 30.456 ;
     RECT  49.565 3.696 50.749 6.024 ;
     RECT  50.677 86.208 50.753 86.28 ;
     RECT  50.749 2.976 50.785 6.024 ;
     RECT  50.785 2.88 51.008 6.024 ;
     RECT  50.725 30.432 51.008 31.224 ;
     RECT  48.589 42.192 51.008 42.216 ;
     RECT  50.06 50.976 51.008 51.768 ;
     RECT  49.961 57.312 51.008 57.336 ;
     RECT  45.904 59.856 51.008 59.88 ;
     RECT  45.904 64.032 51.008 64.056 ;
     RECT  50.149 65.184 51.008 65.208 ;
     RECT  50.204 68.64 51.008 68.664 ;
     RECT  50.245 70.08 51.008 70.104 ;
     RECT  47.267 75.216 51.008 75.24 ;
     RECT  49.097 80.496 51.008 83.304 ;
     RECT  51.008 2.148 51.112 84.252 ;
     RECT  49.841 0.096 51.157 0.12 ;
     RECT  50.753 86.208 51.185 86.232 ;
     RECT  51.112 2.418 51.301 84.252 ;
     RECT  51.301 2.418 51.304 84.936 ;
     RECT  51.304 57.264 51.329 57.336 ;
     RECT  51.304 70.08 51.329 70.152 ;
     RECT  51.304 80.496 51.437 83.304 ;
     RECT  51.157 0.096 51.509 0.552 ;
     RECT  51.304 2.88 51.545 4.488 ;
     RECT  51.304 42.192 51.581 42.696 ;
     RECT  51.857 86.256 51.941 86.28 ;
     RECT  51.304 84.912 52.547 84.936 ;
     RECT  52.453 1.728 52.769 1.752 ;
     RECT  51.304 59.856 52.837 59.88 ;
     RECT  51.304 31.2 52.877 31.224 ;
     RECT  51.545 3.696 53.093 4.488 ;
     RECT  51.329 70.128 53.129 70.152 ;
     RECT  53.093 3.984 53.233 4.488 ;
     RECT  51.304 5.472 53.233 5.496 ;
     RECT  51.304 40.464 53.365 40.488 ;
     RECT  51.581 42.672 53.365 42.696 ;
     RECT  53.365 40.464 53.411 41.4 ;
     RECT  53.365 42.672 53.411 43.512 ;
     RECT  53.411 40.704 53.452 41.4 ;
     RECT  51.329 57.264 53.557 57.288 ;
     RECT  53.557 57.264 53.597 57.576 ;
     RECT  51.304 65.184 53.701 65.208 ;
     RECT  53.701 65.184 53.741 65.592 ;
     RECT  53.597 57.552 53.852 57.576 ;
     RECT  52.837 58.896 53.852 59.88 ;
     RECT  53.233 3.984 53.885 5.496 ;
     RECT  53.852 57.552 53.939 59.88 ;
     RECT  53.885 4.128 54.029 5.496 ;
     RECT  53.077 86.256 54.029 86.28 ;
     RECT  53.939 57.552 54.083 58.488 ;
     RECT  54.025 54.096 54.109 54.12 ;
     RECT  53.939 59.76 54.133 59.88 ;
     RECT  53.953 46.848 54.236 46.872 ;
     RECT  53.411 43.488 54.277 43.512 ;
     RECT  53.413 52.416 54.277 52.44 ;
     RECT  54.277 43.488 54.323 43.896 ;
     RECT  54.236 46.752 54.323 46.872 ;
     RECT  54.277 52.416 54.323 52.872 ;
     RECT  54.323 46.848 54.419 46.872 ;
     RECT  54.133 59.76 54.419 59.976 ;
     RECT  54.181 1.728 54.461 1.752 ;
     RECT  54.517 39.648 54.529 39.672 ;
     RECT  54.529 39.216 54.604 39.672 ;
     RECT  53.452 40.704 54.713 41.304 ;
     RECT  54.277 84.912 54.947 84.936 ;
     RECT  54.029 4.128 55.004 4.2 ;
     RECT  55.004 3.936 55.045 4.2 ;
     RECT  54.029 5.472 55.045 5.496 ;
     RECT  55.045 3.936 55.091 5.496 ;
     RECT  55.105 53.952 55.285 53.976 ;
     RECT  55.285 53.952 55.331 54.84 ;
     RECT  54.323 43.872 55.477 43.896 ;
     RECT  55.477 86.256 55.685 86.28 ;
     RECT  54.083 58.464 55.868 58.488 ;
     RECT  56.069 84.912 56.153 84.936 ;
     RECT  54.713 41.28 56.293 41.304 ;
     RECT  55.091 4.176 56.408 4.68 ;
     RECT  54.604 39.216 56.408 39.24 ;
     RECT  56.293 41.136 56.408 41.304 ;
     RECT  55.477 43.296 56.408 43.896 ;
     RECT  54.323 52.848 56.408 52.872 ;
     RECT  55.331 54.816 56.408 54.84 ;
     RECT  55.868 58.464 56.408 58.68 ;
     RECT  54.419 59.76 56.408 59.88 ;
     RECT  53.741 65.568 56.408 65.592 ;
     RECT  51.437 80.496 56.408 83.256 ;
     RECT  56.408 2.148 56.512 84.252 ;
     RECT  56.512 2.418 56.704 83.982 ;
     RECT  51.509 0.096 56.764 0.12 ;
     RECT  56.704 58.368 57.017 58.488 ;
     RECT  56.764 0.096 57.125 0.168 ;
     RECT  56.704 42.48 57.125 43.32 ;
     RECT  56.704 39.792 57.203 41.16 ;
     RECT  56.704 3.984 57.233 4.68 ;
     RECT  57.203 40.704 57.377 41.16 ;
     RECT  56.704 59.76 57.635 60.312 ;
     RECT  56.704 62.592 57.635 63.24 ;
     RECT  56.704 54.72 57.773 54.744 ;
     RECT  57.635 59.76 57.845 59.88 ;
     RECT  57.637 1.728 57.953 1.752 ;
     RECT  57.845 59.856 58.097 59.88 ;
     RECT  57.377 40.704 58.421 41.112 ;
     RECT  57.125 43.296 58.493 43.32 ;
     RECT  58.421 40.992 58.597 41.112 ;
     RECT  58.597 40.992 58.643 41.64 ;
     RECT  56.677 86.256 58.709 86.28 ;
     RECT  59.065 84.912 59.149 84.936 ;
     RECT  59.605 84.384 59.747 84.408 ;
     RECT  57.233 4.176 60.077 4.68 ;
     RECT  57.635 63.216 60.085 63.24 ;
     RECT  60.085 63.216 60.131 63.864 ;
     RECT  57.125 0.096 60.869 0.12 ;
     RECT  59.605 60.144 61.237 60.168 ;
     RECT  61.093 1.728 61.301 1.752 ;
     RECT  57.017 58.368 61.477 58.392 ;
     RECT  60.829 3.408 61.808 3.432 ;
     RECT  60.077 4.512 61.808 4.68 ;
     RECT  58.643 41.088 61.808 41.64 ;
     RECT  61.477 58.128 61.808 58.68 ;
     RECT  61.237 59.856 61.808 60.168 ;
     RECT  60.131 63.84 61.808 63.864 ;
     RECT  61.237 71.904 61.808 71.928 ;
     RECT  60.469 73.344 61.808 73.368 ;
     RECT  56.704 80.496 61.808 83.256 ;
     RECT  61.808 2.148 61.912 84.252 ;
     RECT  61.477 0.528 61.957 0.552 ;
     RECT  61.912 2.418 62.104 83.982 ;
     RECT  62.104 71.904 62.273 71.928 ;
     RECT  62.104 58.656 62.435 58.68 ;
     RECT  61.957 0.096 62.813 0.552 ;
     RECT  62.104 3.888 63.245 4.68 ;
     RECT  62.104 70.656 63.253 70.68 ;
     RECT  62.104 73.344 63.253 73.368 ;
     RECT  63.253 70.656 63.299 71.352 ;
     RECT  63.253 73.344 63.299 74.328 ;
     RECT  63.349 72.336 63.433 72.36 ;
     RECT  62.104 79.92 63.827 83.256 ;
     RECT  63.299 74.304 63.849 74.328 ;
     RECT  63.299 71.328 63.929 71.352 ;
     RECT  64.549 1.728 64.829 1.752 ;
     RECT  60.277 86.256 65.369 86.28 ;
     RECT  63.245 4.656 65.581 4.68 ;
     RECT  65.617 84.384 65.747 84.408 ;
     RECT  66.257 84.912 66.341 84.936 ;
     RECT  63.827 80.496 66.661 83.256 ;
     RECT  65.581 3.84 66.877 4.68 ;
     RECT  66.877 3.408 67.208 4.68 ;
     RECT  62.104 41.088 67.208 41.64 ;
     RECT  66.661 80.496 67.208 83.784 ;
     RECT  67.208 2.148 67.312 84.252 ;
     RECT  66.901 85.488 67.477 85.512 ;
     RECT  67.312 2.148 67.504 83.982 ;
     RECT  62.813 0.096 67.564 0.12 ;
     RECT  67.477 85.488 67.601 86.28 ;
     RECT  67.564 0.096 67.781 0.168 ;
     RECT  67.601 86.256 68.185 86.28 ;
     RECT  68.005 1.728 68.213 1.752 ;
     RECT  67.504 3.408 68.249 3.432 ;
     RECT  67.504 4.656 68.569 4.68 ;
     RECT  68.636 84.384 68.723 84.408 ;
     RECT  67.504 80.496 69.257 83.208 ;
     RECT  69.301 86.256 69.509 86.28 ;
     RECT  69.829 84.384 69.923 84.408 ;
     RECT  69.733 1.728 69.941 1.752 ;
     RECT  68.569 3.936 70.117 4.68 ;
     RECT  67.781 0.096 70.597 0.12 ;
     RECT  70.597 0.096 70.805 0.168 ;
     RECT  70.501 86.256 71.077 86.28 ;
     RECT  70.117 3.84 71.089 4.68 ;
     RECT  71.089 3.456 71.273 4.68 ;
     RECT  71.077 85.488 71.345 86.28 ;
     RECT  71.273 3.456 71.633 3.48 ;
     RECT  71.461 1.728 71.669 1.752 ;
     RECT  69.257 80.496 71.708 83.064 ;
     RECT  71.345 86.256 72.385 86.28 ;
     RECT  67.504 41.088 72.493 41.64 ;
     RECT  72.385 85.488 72.497 86.28 ;
     RECT  70.805 0.096 72.533 0.12 ;
     RECT  72.313 3.6 72.608 3.624 ;
     RECT  71.273 4.656 72.608 4.68 ;
     RECT  72.493 41.088 72.608 41.736 ;
     RECT  71.708 80.496 72.608 84.024 ;
     RECT  72.608 2.148 72.712 84.252 ;
     RECT  72.716 0.528 72.803 0.552 ;
     RECT  72.712 2.148 72.904 83.982 ;
     RECT  72.497 85.488 72.947 85.512 ;
     RECT  73.189 1.728 73.397 1.752 ;
     RECT  72.904 3.408 73.613 3.624 ;
     RECT  72.904 41.184 73.785 41.736 ;
     RECT  73.477 86.256 74.08 86.28 ;
     RECT  73.785 41.712 74.149 41.736 ;
     RECT  74.149 41.712 74.189 42.168 ;
     RECT  74.08 86.208 74.333 86.28 ;
     RECT  72.904 80.496 74.509 82.872 ;
     RECT  74.509 79.632 74.693 82.872 ;
     RECT  74.333 86.256 74.764 86.28 ;
     RECT  74.941 77.52 74.972 77.544 ;
     RECT  74.972 77.52 75.013 77.976 ;
     RECT  75.013 76.896 75.059 77.976 ;
     RECT  74.693 79.632 75.059 82.824 ;
     RECT  73.613 3.408 75.109 3.432 ;
     RECT  72.904 4.656 75.109 4.68 ;
     RECT  74.917 1.728 75.125 1.752 ;
     RECT  75.059 76.896 75.197 77.544 ;
     RECT  75.109 3.408 75.485 4.68 ;
     RECT  75.059 79.632 75.553 81.624 ;
     RECT  73.609 0.096 75.661 0.12 ;
     RECT  75.301 84.912 75.665 84.936 ;
     RECT  75.553 79.104 75.683 81.624 ;
     RECT  75.661 0.096 75.827 0.552 ;
     RECT  75.683 79.104 75.829 79.272 ;
     RECT  75.197 76.992 75.845 77.544 ;
     RECT  75.059 82.656 76.097 82.824 ;
     RECT  75.845 77.04 76.489 77.544 ;
     RECT  75.829 78.624 76.489 79.272 ;
     RECT  76.489 77.04 76.529 79.272 ;
     RECT  76.529 78.096 76.745 79.272 ;
     RECT  76.745 78.096 76.817 79.128 ;
     RECT  76.645 1.728 76.925 1.752 ;
     RECT  75.683 80.304 76.933 81.624 ;
     RECT  76.097 82.656 76.933 82.68 ;
     RECT  76.933 80.304 77.137 82.68 ;
     RECT  77.137 80.304 77.785 82.824 ;
     RECT  74.189 42.144 77.821 42.168 ;
     RECT  76.529 77.04 77.893 77.064 ;
     RECT  76.817 78.096 77.893 78.12 ;
     RECT  75.877 86.256 77.897 86.28 ;
     RECT  77.893 77.04 77.929 78.12 ;
     RECT  76.817 79.104 77.929 79.128 ;
     RECT  75.485 3.408 78.008 3.432 ;
     RECT  75.485 4.656 78.008 4.68 ;
     RECT  77.821 41.76 78.008 42.168 ;
     RECT  72.904 44.352 78.008 44.376 ;
     RECT  77.929 77.04 78.008 79.128 ;
     RECT  77.785 80.304 78.008 83.256 ;
     RECT  78.008 2.148 78.112 84.252 ;
     RECT  78.112 2.418 78.277 84.252 ;
     RECT  78.277 2.418 78.304 84.84 ;
     RECT  78.304 84.816 78.365 84.84 ;
     RECT  75.827 0.096 78.373 0.12 ;
     RECT  78.304 75.216 78.401 83.256 ;
     RECT  78.401 77.952 78.419 83.256 ;
     RECT  78.419 78 78.437 83.256 ;
     RECT  78.401 75.216 78.445 76.872 ;
     RECT  78.373 0.096 78.581 0.168 ;
     RECT  78.445 75.216 78.717 75.864 ;
     RECT  78.437 78 78.761 81.432 ;
     RECT  78.717 75.216 78.797 75.24 ;
     RECT  78.304 41.616 78.869 41.784 ;
     RECT  78.829 85.488 78.947 85.512 ;
     RECT  78.304 4.656 79.369 4.68 ;
     RECT  78.581 0.096 79.445 0.12 ;
     RECT  78.304 44.352 79.481 44.472 ;
     RECT  78.761 79.824 79.517 81.432 ;
     RECT  78.437 82.656 79.553 83.256 ;
     RECT  78.445 76.848 79.625 76.872 ;
     RECT  79.481 44.448 79.733 44.472 ;
     RECT  79.477 86.256 79.877 86.28 ;
     RECT  79.369 4.368 80.017 4.68 ;
     RECT  80.101 84.384 80.188 84.408 ;
     RECT  78.869 41.616 80.233 41.64 ;
     RECT  80.125 76.56 80.269 76.584 ;
     RECT  80.233 40.416 80.291 41.64 ;
     RECT  80.291 40.416 80.317 41.016 ;
     RECT  78.761 78 80.489 78.744 ;
     RECT  80.017 4.368 80.633 5.448 ;
     RECT  79.517 80.832 80.701 81.432 ;
     RECT  80.245 42.768 80.777 42.792 ;
     RECT  80.489 78 80.777 78.072 ;
     RECT  80.677 85.488 80.849 85.512 ;
     RECT  79.517 79.824 80.881 79.848 ;
     RECT  80.701 80.832 80.881 81.48 ;
     RECT  80.881 79.824 80.989 81.48 ;
     RECT  80.317 40.416 80.993 40.44 ;
     RECT  80.633 4.656 81.029 5.448 ;
     RECT  80.269 76.464 81.205 76.584 ;
     RECT  81.205 74.64 81.289 74.664 ;
     RECT  80.989 79.824 81.313 81.672 ;
     RECT  81.313 79.248 81.353 81.672 ;
     RECT  79.553 82.656 81.353 82.824 ;
     RECT  81.029 4.656 81.425 5.208 ;
     RECT  81.205 76.176 81.425 76.584 ;
     RECT  81.301 84.912 81.425 84.936 ;
     RECT  79.657 1.728 81.461 1.752 ;
     RECT  81.425 76.464 81.497 76.584 ;
     RECT  81.353 82.656 81.533 82.68 ;
     RECT  81.497 76.56 81.605 76.584 ;
     RECT  80.777 78.048 81.857 78.072 ;
     RECT  81.353 79.248 81.857 80.424 ;
     RECT  81.353 81.504 81.877 81.672 ;
     RECT  81.845 84.336 81.929 84.36 ;
     RECT  81.877 81.504 81.964 82.152 ;
     RECT  81.425 5.184 82.033 5.208 ;
     RECT  81.829 0.096 82.069 0.12 ;
     RECT  82.069 0.096 82.307 0.168 ;
     RECT  81.857 79.872 82.433 80.424 ;
     RECT  81.964 81.504 82.501 81.672 ;
     RECT  82.357 86.352 82.501 86.376 ;
     RECT  82.501 86.256 82.645 86.376 ;
     RECT  82.645 86.208 83.123 86.376 ;
     RECT  82.033 5.184 83.408 5.256 ;
     RECT  82.501 80.928 83.408 81.672 ;
     RECT  82.285 83.76 83.408 83.784 ;
     RECT  83.408 2.148 83.512 84.252 ;
     RECT  82.307 0.096 83.629 0.12 ;
     RECT  83.512 2.304 83.704 83.982 ;
     RECT  83.704 81.648 83.837 81.672 ;
     RECT  83.704 2.304 84.053 2.328 ;
     RECT  83.123 86.256 84.373 86.376 ;
     RECT  83.905 0.48 84.38 0.504 ;
     RECT  84.38 0.48 84.899 0.552 ;
     RECT  84.877 41.616 84.913 41.64 ;
     RECT  84.913 40.992 85.093 41.64 ;
     RECT  84.899 0.48 85.265 0.504 ;
     RECT  85.057 3.408 85.453 3.432 ;
     RECT  84.913 7.824 85.453 7.848 ;
     RECT  84.913 27.216 85.453 27.24 ;
     RECT  84.877 28.464 85.453 28.488 ;
     RECT  84.913 31.584 85.453 31.608 ;
     RECT  85.093 40.368 85.453 41.64 ;
     RECT  85.165 57.888 85.453 57.912 ;
     RECT  84.913 66.672 85.453 66.696 ;
     RECT  85.165 67.92 85.453 67.944 ;
     RECT  84.913 70.416 85.453 70.44 ;
     RECT  84.877 81.696 85.453 81.72 ;
     RECT  85.453 24.096 85.489 28.488 ;
     RECT  85.453 29.712 85.489 41.64 ;
     RECT  85.453 56.016 85.489 60.408 ;
     RECT  85.453 62.304 85.489 72.936 ;
     RECT  85.489 1.536 85.525 1.56 ;
     RECT  85.453 2.784 85.525 4.104 ;
     RECT  84.877 83.568 85.525 83.592 ;
     RECT  84.373 85.488 85.525 86.376 ;
     RECT  85.525 85.44 86.051 86.376 ;
     RECT  86.051 85.44 86.147 86.28 ;
     RECT  85.265 0.096 86.221 0.504 ;
     RECT  86.221 0.288 86.245 0.504 ;
     RECT  85.525 1.536 86.245 4.104 ;
     RECT  85.453 5.952 86.245 9.096 ;
     RECT  86.147 85.44 86.245 86.088 ;
     RECT  86.245 0.288 86.281 4.104 ;
     RECT  86.245 5.328 86.281 9.096 ;
     RECT  85.453 10.32 86.281 16.584 ;
     RECT  85.453 18.48 86.281 21.624 ;
     RECT  85.489 23.472 86.281 41.64 ;
     RECT  85.453 43.488 86.281 43.512 ;
     RECT  85.453 44.736 86.281 47.304 ;
     RECT  85.453 49.152 86.281 53.544 ;
     RECT  85.489 54.768 86.281 61.032 ;
     RECT  85.489 62.304 86.281 73.56 ;
     RECT  86.245 74.784 86.281 74.808 ;
     RECT  85.453 76.08 86.281 79.224 ;
     RECT  85.453 81.072 86.281 81.72 ;
     RECT  85.525 82.944 86.281 83.592 ;
     RECT  86.245 84.816 86.281 86.088 ;
     RECT  86.281 0.288 86.364 86.088 ;
     RECT  86.364 85.968 86.393 85.992 ;
    LAYER M5 ;
     RECT  0.192 0.016 86.184 0.131 ;
     RECT  0.624 0.131 5.832 0.179 ;
     RECT  33.024 0.131 42.984 0.179 ;
     RECT  44.256 0.131 44.28 0.179 ;
     RECT  45.984 0.131 46.008 0.179 ;
     RECT  56.784 0.131 57.672 0.179 ;
     RECT  67.584 0.131 68.04 0.179 ;
     RECT  69.744 0.131 71.496 0.179 ;
     RECT  78.384 0.131 78.408 0.179 ;
     RECT  79.68 0.131 82.296 0.179 ;
     RECT  1.056 0.179 2.808 0.227 ;
     RECT  4.08 0.179 5.832 0.227 ;
     RECT  26.544 0.131 30.024 0.227 ;
     RECT  34.752 0.179 42.12 0.227 ;
     RECT  1.488 0.227 2.808 0.371 ;
     RECT  1.488 0.371 2.376 0.515 ;
     RECT  84 0.131 85.752 0.515 ;
     RECT  51.168 0.131 51.192 0.563 ;
     RECT  61.104 0.131 62.424 0.563 ;
     RECT  72.768 0.131 73.224 0.563 ;
     RECT  74.928 0.131 76.68 0.563 ;
     RECT  84 0.515 84.888 0.563 ;
     RECT  4.512 0.227 5.832 0.611 ;
     RECT  7.536 0.131 13.176 0.611 ;
     RECT  14.448 0.131 25.272 0.611 ;
     RECT  27.408 0.227 30.024 0.611 ;
     RECT  31.728 0.131 31.752 0.611 ;
     RECT  34.752 0.227 35.64 0.611 ;
     RECT  36.912 0.227 42.12 0.611 ;
     RECT  4.512 0.611 4.968 1.763 ;
     RECT  7.536 0.611 7.56 1.763 ;
     RECT  9.264 0.611 9.288 1.763 ;
     RECT  10.992 0.611 11.016 1.763 ;
     RECT  12.72 0.611 12.744 1.763 ;
     RECT  17.04 0.611 17.928 1.763 ;
     RECT  20.928 0.611 21.384 1.763 ;
     RECT  22.656 0.611 23.544 1.763 ;
     RECT  24.816 0.611 25.272 1.763 ;
     RECT  27.84 0.611 30.024 1.763 ;
     RECT  33.024 0.179 33.48 1.763 ;
     RECT  34.752 0.611 34.776 1.763 ;
     RECT  36.912 0.611 36.936 1.763 ;
     RECT  38.64 0.611 40.392 1.763 ;
     RECT  42.096 0.611 42.12 1.763 ;
     RECT  49.008 0.131 49.464 1.763 ;
     RECT  52.464 0.131 52.488 1.763 ;
     RECT  54.192 0.131 54.216 1.763 ;
     RECT  57.648 0.179 57.672 1.763 ;
     RECT  61.104 0.563 61.128 1.763 ;
     RECT  64.56 0.131 64.584 1.763 ;
     RECT  68.016 0.179 68.04 1.763 ;
     RECT  69.744 0.179 69.768 1.763 ;
     RECT  71.472 0.179 71.496 1.763 ;
     RECT  73.2 0.563 73.224 1.763 ;
     RECT  74.928 0.563 74.952 1.763 ;
     RECT  76.656 0.563 76.68 1.763 ;
     RECT  79.68 0.179 81.432 1.763 ;
     RECT  1.488 0.515 1.512 2.137 ;
     RECT  84 0.563 84.024 2.137 ;
     RECT  1.488 2.137 2.52 2.151 ;
     RECT  7.8 2.137 7.92 2.151 ;
     RECT  13.2 2.137 13.32 2.151 ;
     RECT  18.6 2.137 18.72 2.151 ;
     RECT  34.8 2.137 34.92 2.151 ;
     RECT  39.504 1.763 40.392 2.151 ;
     RECT  45.6 2.137 45.72 2.151 ;
     RECT  51 2.137 51.12 2.151 ;
     RECT  56.4 2.137 56.52 2.151 ;
     RECT  61.8 2.137 61.92 2.151 ;
     RECT  78 2.137 78.12 2.151 ;
     RECT  15.312 0.611 15.336 2.195 ;
     RECT  20.928 1.763 20.952 2.195 ;
     RECT  47.28 0.131 47.304 2.195 ;
     RECT  83.4 2.137 84.024 2.339 ;
     RECT  39.504 2.151 40.512 2.915 ;
     RECT  45.6 2.151 45.912 3.301 ;
     RECT  13.2 2.151 13.512 3.349 ;
     RECT  40.2 2.915 40.512 3.397 ;
     RECT  34.8 2.151 35.112 3.445 ;
     RECT  18.6 2.151 18.912 3.589 ;
     RECT  40.2 3.397 40.776 3.589 ;
     RECT  40.2 3.589 41.736 3.635 ;
     RECT  29.136 1.763 29.712 3.779 ;
     RECT  36.288 3.349 36.312 3.877 ;
     RECT  45.6 3.301 46.152 3.923 ;
     RECT  1.488 2.151 2.712 3.925 ;
     RECT  18.48 3.589 18.912 3.925 ;
     RECT  51 2.151 51.312 3.973 ;
     RECT  31.056 3.349 31.08 4.019 ;
     RECT  18.48 3.925 19.416 4.115 ;
     RECT  45.6 3.923 46.008 4.115 ;
     RECT  75.12 3.397 75.144 4.115 ;
     RECT  21.12 3.829 21.144 4.163 ;
     RECT  50.352 3.973 51.312 4.163 ;
     RECT  36.288 3.877 36.984 4.307 ;
     RECT  41.712 3.635 41.736 4.309 ;
     RECT  70.704 3.829 70.728 4.355 ;
     RECT  13.2 3.349 13.608 4.403 ;
     RECT  29.28 3.779 29.712 4.499 ;
     RECT  41.712 4.309 42.456 4.499 ;
     RECT  40.2 3.635 40.68 4.501 ;
     RECT  1.488 3.925 3.432 4.691 ;
     RECT  24 2.137 24.312 4.741 ;
     RECT  34.32 3.445 35.112 4.741 ;
     RECT  18.6 4.115 19.416 4.787 ;
     RECT  20.784 4.741 20.904 4.883 ;
     RECT  37.488 4.789 37.512 4.931 ;
     RECT  32.304 3.877 32.328 5.029 ;
     RECT  42.336 4.499 42.36 5.171 ;
     RECT  39.6 4.501 40.68 5.173 ;
     RECT  39.6 5.173 40.728 5.219 ;
     RECT  32.256 5.029 32.328 5.267 ;
     RECT  34.32 4.741 35.208 5.365 ;
     RECT  36.288 4.307 36.312 5.365 ;
     RECT  55.056 3.925 55.08 5.507 ;
     RECT  40.08 5.219 40.728 5.605 ;
     RECT  47.904 3.925 47.928 5.605 ;
     RECT  46.992 5.605 47.928 5.699 ;
     RECT  32.304 5.267 32.328 5.701 ;
     RECT  34.32 5.365 36.312 5.747 ;
     RECT  2.4 4.691 3.432 6.323 ;
     RECT  32.304 5.701 33.096 6.323 ;
     RECT  34.32 5.747 35.64 6.565 ;
     RECT  33.072 6.323 33.096 6.851 ;
     RECT  40.08 5.605 41.208 7.235 ;
     RECT  2.4 6.323 2.712 7.381 ;
     RECT  34.272 6.565 35.64 7.619 ;
     RECT  40.08 7.235 40.728 7.765 ;
     RECT  45.6 4.115 45.912 8.437 ;
     RECT  46.992 5.699 47.016 8.437 ;
     RECT  45.6 8.437 47.016 8.483 ;
     RECT  39.312 7.765 40.728 8.533 ;
     RECT  39.312 8.533 41.064 9.251 ;
     RECT  20.784 4.883 20.808 9.637 ;
     RECT  31.248 9.061 31.272 9.637 ;
     RECT  20.592 9.637 20.808 9.683 ;
     RECT  31.248 9.637 31.896 10.595 ;
     RECT  29.4 4.499 29.712 10.837 ;
     RECT  31.248 10.595 31.272 10.837 ;
     RECT  2.4 7.381 3.624 10.883 ;
     RECT  34.8 7.619 35.64 10.981 ;
     RECT  29.4 10.837 31.272 11.027 ;
     RECT  34.8 10.981 36.456 11.027 ;
     RECT  24 4.741 24.456 11.267 ;
     RECT  34.8 11.027 35.112 11.941 ;
     RECT  36.432 11.027 36.456 12.035 ;
     RECT  39.312 9.251 40.728 12.277 ;
     RECT  24 11.267 24.408 12.517 ;
     RECT  34.704 11.941 35.112 12.563 ;
     RECT  39.312 12.277 41.64 12.563 ;
     RECT  29.4 11.027 30.744 12.899 ;
     RECT  40.2 12.563 41.64 12.997 ;
     RECT  22.368 12.469 22.392 13.043 ;
     RECT  40.2 12.997 42.12 13.043 ;
     RECT  45.6 8.483 46.776 13.283 ;
     RECT  24 12.517 25.08 13.429 ;
     RECT  34.8 12.563 35.112 13.621 ;
     RECT  24 13.429 25.848 14.243 ;
     RECT  27.888 13.429 27.912 14.579 ;
     RECT  20.592 9.683 20.616 14.773 ;
     RECT  21.648 13.621 21.672 14.773 ;
     RECT  20.592 14.773 21.672 14.819 ;
     RECT  34.8 13.621 35.352 15.059 ;
     RECT  24 14.243 25.08 15.347 ;
     RECT  20.928 14.819 21.672 15.443 ;
     RECT  18.6 4.787 18.912 15.973 ;
     RECT  34.8 15.059 35.112 16.117 ;
     RECT  32.112 15.589 32.136 16.691 ;
     RECT  2.4 10.883 2.712 17.029 ;
     RECT  3.696 14.197 3.72 17.029 ;
     RECT  2.4 17.029 3.72 17.075 ;
     RECT  24 15.347 24.6 17.123 ;
     RECT  17.904 15.973 18.912 17.315 ;
     RECT  20.928 15.443 20.952 17.315 ;
     RECT  18.6 17.315 18.912 17.605 ;
     RECT  13.2 4.403 13.512 17.653 ;
     RECT  34.176 16.117 35.112 17.699 ;
     RECT  18.6 17.605 19.848 18.181 ;
     RECT  2.4 17.075 3.192 18.229 ;
     RECT  33.648 18.037 33.672 18.805 ;
     RECT  34.8 17.699 35.112 18.805 ;
     RECT  13.2 17.653 14.232 18.853 ;
     RECT  12 18.181 12.024 19.139 ;
     RECT  29.4 12.899 30.408 19.235 ;
     RECT  33.648 18.805 35.112 19.235 ;
     RECT  7.8 2.151 8.112 19.333 ;
     RECT  40.2 13.043 40.728 19.333 ;
     RECT  9.648 17.893 9.672 19.427 ;
     RECT  21.648 18.181 21.672 19.523 ;
     RECT  13.2 18.853 15.144 19.955 ;
     RECT  36.192 15.637 36.216 20.291 ;
     RECT  7.8 19.333 8.328 20.293 ;
     RECT  28.224 19.333 28.248 20.387 ;
     RECT  29.4 19.235 29.712 20.581 ;
     RECT  31.296 19.381 31.32 20.581 ;
     RECT  6.528 20.149 6.552 20.965 ;
     RECT  7.632 20.293 8.328 20.965 ;
     RECT  34.032 19.235 35.112 20.965 ;
     RECT  6.528 20.965 8.328 21.011 ;
     RECT  33.648 20.965 35.112 21.011 ;
     RECT  34.8 21.011 35.112 21.109 ;
     RECT  6.864 21.011 8.328 21.155 ;
     RECT  31.296 20.581 32.088 21.155 ;
     RECT  2.4 18.229 3.672 21.683 ;
     RECT  6.864 21.155 8.112 21.683 ;
     RECT  13.2 19.955 14.472 21.683 ;
     RECT  26.784 21.061 26.808 21.683 ;
     RECT  29.4 20.581 30.264 21.779 ;
     RECT  18.6 18.181 20.328 22.163 ;
     RECT  18.6 22.163 20.136 22.165 ;
     RECT  25.44 19.141 25.464 22.259 ;
     RECT  42.096 13.043 42.12 22.259 ;
     RECT  32.064 21.155 32.088 22.451 ;
     RECT  34.8 21.109 35.976 22.739 ;
     RECT  33.648 21.011 33.672 22.787 ;
     RECT  40.2 19.333 40.824 22.789 ;
     RECT  16.608 21.637 16.632 22.835 ;
     RECT  18.24 22.165 20.136 22.835 ;
     RECT  37.632 22.693 37.656 23.075 ;
     RECT  18.24 22.835 19.848 23.411 ;
     RECT  14.832 22.165 14.856 23.797 ;
     RECT  18.6 23.411 19.848 23.845 ;
     RECT  7.632 21.683 8.112 23.893 ;
     RECT  13.2 21.683 13.512 23.941 ;
     RECT  14.832 23.797 15.72 23.941 ;
     RECT  7.632 23.893 9.096 24.659 ;
     RECT  6.624 23.317 6.648 24.851 ;
     RECT  17.568 23.797 17.592 24.899 ;
     RECT  29.4 21.779 29.712 24.949 ;
     RECT  31.872 24.469 31.896 24.995 ;
     RECT  13.2 23.941 15.72 25.187 ;
     RECT  34.8 22.739 35.112 25.573 ;
     RECT  18.6 23.845 19.992 25.763 ;
     RECT  7.632 24.659 8.112 26.197 ;
     RECT  29.4 24.949 30.6 26.197 ;
     RECT  10.848 25.045 10.872 26.243 ;
     RECT  13.2 25.187 14.856 26.243 ;
     RECT  16.944 25.333 16.968 26.387 ;
     RECT  2.4 21.683 2.712 26.389 ;
     RECT  40.2 22.789 40.92 26.437 ;
     RECT  33.744 25.093 33.768 26.531 ;
     RECT  29.4 26.197 30.696 26.677 ;
     RECT  29.4 26.677 30.792 26.723 ;
     RECT  2.4 26.389 3.432 26.819 ;
     RECT  30.768 26.723 30.792 26.819 ;
     RECT  34.8 25.573 35.544 26.819 ;
     RECT  7.392 26.197 8.112 26.867 ;
     RECT  13.2 26.243 14.808 27.107 ;
     RECT  39.216 26.437 40.92 27.251 ;
     RECT  13.2 27.107 13.752 27.731 ;
     RECT  36.864 27.301 36.888 27.923 ;
     RECT  47.04 23.701 47.064 28.019 ;
     RECT  39.312 27.251 40.92 28.309 ;
     RECT  38.88 28.309 40.92 28.355 ;
     RECT  32.976 27.877 33 28.739 ;
     RECT  43.824 27.205 43.848 28.835 ;
     RECT  11.472 26.773 11.496 28.837 ;
     RECT  13.2 27.731 13.512 28.981 ;
     RECT  10.848 28.837 11.496 29.075 ;
     RECT  38.88 28.355 38.904 29.123 ;
     RECT  11.376 29.075 11.496 29.605 ;
     RECT  11.376 29.605 11.592 29.651 ;
     RECT  7.488 26.867 8.112 29.843 ;
     RECT  40.2 28.355 40.92 29.893 ;
     RECT  18.6 25.763 19.848 29.939 ;
     RECT  17.136 29.029 17.16 30.035 ;
     RECT  38.928 29.365 38.952 30.227 ;
     RECT  13.2 28.981 13.608 30.229 ;
     RECT  14.784 27.107 14.808 30.229 ;
     RECT  13.2 30.229 14.808 30.275 ;
     RECT  51 4.163 51.312 30.421 ;
     RECT  40.08 29.893 40.92 30.899 ;
     RECT  7.584 29.843 8.112 30.947 ;
     RECT  50.736 30.421 51.312 31.235 ;
     RECT  11.568 29.651 11.592 31.379 ;
     RECT  13.2 30.275 14.232 33.683 ;
     RECT  10.272 31.525 10.296 34.355 ;
     RECT  7.632 30.947 8.112 34.789 ;
     RECT  11.376 33.925 11.4 35.317 ;
     RECT  11.184 35.317 11.4 35.363 ;
     RECT  11.184 35.363 11.208 35.987 ;
     RECT  3.696 33.589 3.72 36.515 ;
     RECT  33.168 35.941 33.192 36.803 ;
     RECT  7.632 34.789 8.424 36.901 ;
     RECT  7.632 36.901 9.192 37.331 ;
     RECT  34.8 26.819 35.112 37.573 ;
     RECT  5.856 36.469 5.88 38.195 ;
     RECT  9.168 37.331 9.192 38.195 ;
     RECT  34.704 37.573 35.112 38.389 ;
     RECT  7.632 37.331 8.112 38.819 ;
     RECT  56.4 2.151 56.712 39.781 ;
     RECT  42.432 31.237 42.456 39.827 ;
     RECT  44.448 38.533 44.472 40.067 ;
     RECT  54.528 39.637 54.552 40.739 ;
     RECT  56.4 39.781 57.192 40.739 ;
     RECT  72.6 2.137 72.912 41.173 ;
     RECT  58.608 40.981 58.632 41.651 ;
     RECT  56.4 40.739 57.048 42.515 ;
     RECT  6.288 39.109 6.312 42.803 ;
     RECT  80.256 40.981 80.28 42.803 ;
     RECT  0.192 2.437 0.216 43.091 ;
     RECT  56.4 42.515 56.712 43.285 ;
     RECT  53.376 40.453 53.4 43.477 ;
     RECT  54.384 41.269 54.408 43.477 ;
     RECT  53.376 43.477 54.408 43.523 ;
     RECT  55.488 43.285 56.712 43.907 ;
     RECT  40.2 30.899 40.92 43.955 ;
     RECT  72.6 41.173 73.752 44.387 ;
     RECT  13.2 33.683 13.512 44.965 ;
     RECT  0.144 44.821 0.168 45.059 ;
     RECT  32.448 44.437 32.472 45.635 ;
     RECT  34.464 38.389 35.112 45.923 ;
     RECT  29.4 26.723 29.712 46.117 ;
     RECT  2.4 26.819 2.712 46.453 ;
     RECT  3.744 44.053 3.768 46.453 ;
     RECT  2.4 46.453 3.768 46.499 ;
     RECT  0.144 46.453 0.168 46.787 ;
     RECT  13.104 44.965 13.512 46.835 ;
     RECT  29.28 46.117 29.712 47.893 ;
     RECT  40.2 43.955 40.824 48.949 ;
     RECT  28.512 47.893 29.712 50.771 ;
     RECT  51 31.235 51.312 50.965 ;
     RECT  34.656 45.923 35.112 51.109 ;
     RECT  15.792 47.269 15.816 51.443 ;
     RECT  21.792 51.253 21.816 51.683 ;
     RECT  50.112 50.965 51.312 51.733 ;
     RECT  49.728 51.733 51.312 51.779 ;
     RECT  2.4 46.499 3.48 51.781 ;
     RECT  2.4 51.781 3.72 51.827 ;
     RECT  45.6 13.283 45.912 52.021 ;
     RECT  48.288 50.101 48.312 52.211 ;
     RECT  54.288 43.523 54.408 52.837 ;
     RECT  54.288 52.837 55.32 52.883 ;
     RECT  40.2 48.949 40.968 52.979 ;
     RECT  44.016 50.677 44.04 53.267 ;
     RECT  33.936 51.109 35.112 53.749 ;
     RECT  33.648 53.749 35.112 53.795 ;
     RECT  45.6 52.021 46.248 53.797 ;
     RECT  54.384 52.883 55.32 54.085 ;
     RECT  44.688 53.797 46.248 54.179 ;
     RECT  15.936 52.405 15.96 54.755 ;
     RECT  33.648 53.795 33.672 54.851 ;
     RECT  54.048 54.085 55.32 54.851 ;
     RECT  2.4 51.827 2.712 55.045 ;
     RECT  3.696 51.827 3.72 55.045 ;
     RECT  2.4 55.045 3.72 55.091 ;
     RECT  49.728 51.779 49.752 55.813 ;
     RECT  49.584 55.813 49.752 55.859 ;
     RECT  40.2 52.979 40.824 56.341 ;
     RECT  44.688 54.179 45.912 56.483 ;
     RECT  49.584 55.859 49.608 56.483 ;
     RECT  29.4 50.771 29.712 57.013 ;
     RECT  36.24 54.949 36.264 57.299 ;
     RECT  40.08 56.341 40.824 57.539 ;
     RECT  2.4 55.091 3.624 57.875 ;
     RECT  40.2 57.539 40.824 57.971 ;
     RECT  54.048 54.851 54.408 58.021 ;
     RECT  34.656 53.795 35.112 58.069 ;
     RECT  61.8 2.151 62.112 58.117 ;
     RECT  49.92 57.301 49.944 58.643 ;
     RECT  56.4 43.907 56.712 58.645 ;
     RECT  61.488 58.117 62.112 58.645 ;
     RECT  34.224 58.069 35.112 58.931 ;
     RECT  53.904 58.021 54.408 59.795 ;
     RECT  55.92 58.645 56.712 59.795 ;
     RECT  61.488 58.645 62.424 59.845 ;
     RECT  43.584 57.925 43.608 59.891 ;
     RECT  37.632 59.605 37.656 59.939 ;
     RECT  54.384 59.795 54.408 59.987 ;
     RECT  56.4 59.795 56.712 60.277 ;
     RECT  49.968 58.693 49.992 61.619 ;
     RECT  19.968 51.253 19.992 63.011 ;
     RECT  29.4 57.013 29.832 63.011 ;
     RECT  15.84 61.429 15.864 63.155 ;
     RECT  56.4 60.277 57.624 63.251 ;
     RECT  34.8 58.931 35.112 63.685 ;
     RECT  60.096 63.205 60.12 63.875 ;
     RECT  51 51.779 51.312 64.021 ;
     RECT  50.16 64.021 51.312 65.219 ;
     RECT  0.144 62.725 0.168 67.621 ;
     RECT  2.4 57.875 3.144 68.147 ;
     RECT  34.8 63.685 35.88 68.147 ;
     RECT  40.2 57.971 40.512 68.197 ;
     RECT  0.144 67.621 0.216 69.253 ;
     RECT  50.256 65.219 51.312 70.115 ;
     RECT  61.248 59.845 62.424 70.645 ;
     RECT  61.248 70.645 63.288 71.939 ;
     RECT  61.8 71.939 63.288 72.325 ;
     RECT  0.144 69.253 0.264 73.043 ;
     RECT  61.8 72.325 63.384 74.293 ;
     RECT  0.192 73.043 0.264 74.387 ;
     RECT  5.808 71.797 5.832 74.629 ;
     RECT  0.24 74.387 0.264 75.203 ;
     RECT  7.8 38.819 8.112 75.205 ;
     RECT  78 2.151 78.312 75.205 ;
     RECT  50.4 70.115 51.312 75.251 ;
     RECT  46.992 75.205 47.016 75.541 ;
     RECT  78 75.205 78.696 75.875 ;
     RECT  81.216 74.629 81.24 76.211 ;
     RECT  75.024 76.885 75.048 77.509 ;
     RECT  78 75.875 78.408 77.941 ;
     RECT  77.904 77.941 78.408 78.083 ;
     RECT  75.024 77.509 75.864 78.659 ;
     RECT  40.2 68.197 40.728 78.707 ;
     RECT  77.904 78.083 78.312 79.045 ;
     RECT  77.904 79.045 78.456 79.093 ;
     RECT  45.6 56.483 45.912 79.765 ;
     RECT  75.024 78.659 75.672 80.291 ;
     RECT  77.616 79.093 78.456 80.339 ;
     RECT  46.992 75.541 47.256 80.389 ;
     RECT  77.616 80.339 78.312 80.389 ;
     RECT  5.808 74.629 5.928 80.435 ;
     RECT  7.8 75.205 8.376 80.675 ;
     RECT  46.992 80.389 47.928 80.771 ;
     RECT  5.904 80.435 5.928 80.819 ;
     RECT  29.4 63.011 29.712 80.821 ;
     RECT  21.36 62.965 21.384 80.917 ;
     RECT  24 17.123 24.312 80.917 ;
     RECT  29.04 80.821 29.712 80.963 ;
     RECT  47.904 80.771 47.928 80.963 ;
     RECT  40.2 78.707 40.512 81.061 ;
     RECT  24 80.917 25.08 81.107 ;
     RECT  41.568 79.189 41.592 81.347 ;
     RECT  2.4 68.147 2.712 81.445 ;
     RECT  13.2 46.835 13.512 81.445 ;
     RECT  83.4 2.339 83.712 81.445 ;
     RECT  20.208 80.917 21.384 81.589 ;
     RECT  61.8 74.293 63.816 81.635 ;
     RECT  20.208 81.589 21.672 81.877 ;
     RECT  34.8 68.147 35.112 81.877 ;
     RECT  17.28 81.493 17.304 82.019 ;
     RECT  51 75.251 51.312 82.021 ;
     RECT  67.2 2.137 67.512 82.021 ;
     RECT  20.208 81.877 22.008 82.115 ;
     RECT  27.312 80.773 27.336 82.115 ;
     RECT  59.808 81.349 59.832 82.115 ;
     RECT  75.024 80.291 75.048 82.115 ;
     RECT  33.552 79.765 33.576 82.163 ;
     RECT  44.976 79.765 45.912 82.163 ;
     RECT  61.8 81.635 62.952 82.163 ;
     RECT  81.888 81.493 81.912 82.163 ;
     RECT  24 81.107 24.312 82.165 ;
     RECT  38.16 80.341 38.184 82.165 ;
     RECT  70.608 82.117 70.632 82.165 ;
     RECT  21.072 82.115 22.008 82.211 ;
     RECT  76.944 80.389 78.312 82.211 ;
     RECT  13.008 81.445 13.512 82.213 ;
     RECT  38.16 82.165 38.616 82.213 ;
     RECT  24 82.165 24.408 82.355 ;
     RECT  38.112 82.213 38.616 82.405 ;
     RECT  72.6 44.387 72.912 82.501 ;
     RECT  25.44 82.405 25.464 82.547 ;
     RECT  38.112 82.405 38.712 82.547 ;
     RECT  70.608 82.165 70.728 82.547 ;
     RECT  13.008 82.213 13.656 82.643 ;
     RECT  21.072 82.211 21.672 82.643 ;
     RECT  38.112 82.547 38.136 82.643 ;
     RECT  51 82.021 52.296 82.643 ;
     RECT  40.08 81.061 40.512 82.691 ;
     RECT  47.808 82.069 47.832 82.691 ;
     RECT  66.336 82.021 67.512 82.691 ;
     RECT  76.944 82.211 76.968 82.691 ;
     RECT  3.744 82.405 3.768 82.739 ;
     RECT  13.008 82.643 13.512 82.739 ;
     RECT  15.936 81.445 15.96 82.741 ;
     RECT  18.6 29.939 18.912 82.741 ;
     RECT  34.8 81.877 35.256 82.835 ;
     RECT  15.36 82.741 15.96 82.931 ;
     RECT  15.36 82.931 15.384 82.979 ;
     RECT  17.712 82.741 18.912 82.979 ;
     RECT  0.288 81.973 0.312 83.029 ;
     RECT  1.488 81.445 2.712 83.029 ;
     RECT  21.648 82.643 21.672 83.171 ;
     RECT  24 82.355 24.312 83.893 ;
     RECT  25.488 83.797 25.512 83.893 ;
     RECT  71.76 82.501 72.912 84.035 ;
     RECT  24 83.893 25.512 84.181 ;
     RECT  27.312 83.797 27.336 84.181 ;
     RECT  45.6 82.163 45.912 84.249 ;
     RECT  56.4 63.251 56.712 84.249 ;
     RECT  61.8 82.163 62.112 84.249 ;
     RECT  67.2 82.691 67.512 84.249 ;
     RECT  72.6 84.035 72.912 84.249 ;
     RECT  83.28 81.445 83.712 84.249 ;
     RECT  0.288 83.029 2.712 84.263 ;
     RECT  7.8 80.675 8.112 84.263 ;
     RECT  18.6 82.979 18.912 84.263 ;
     RECT  24 84.181 27.336 84.263 ;
     RECT  29.4 80.963 29.712 84.263 ;
     RECT  45.6 84.249 45.72 84.263 ;
     RECT  51 82.643 51.312 84.263 ;
     RECT  56.4 84.249 56.52 84.263 ;
     RECT  61.8 84.249 61.92 84.263 ;
     RECT  67.2 84.249 67.32 84.263 ;
     RECT  72.6 84.249 72.72 84.263 ;
     RECT  78 82.211 78.312 84.263 ;
     RECT  83.28 84.249 83.52 84.263 ;
     RECT  13.2 82.739 13.512 84.325 ;
     RECT  40.2 82.691 40.512 84.325 ;
     RECT  13.2 84.325 14.136 84.901 ;
     RECT  16.512 84.325 16.536 84.901 ;
     RECT  34.8 82.835 35.112 84.901 ;
     RECT  39.312 84.325 40.512 84.901 ;
     RECT  59.712 84.373 59.736 84.901 ;
     RECT  65.712 84.373 65.736 84.901 ;
     RECT  81.888 84.325 81.912 84.901 ;
     RECT  16.512 84.901 17.112 85.477 ;
     RECT  19.488 84.373 19.512 85.477 ;
     RECT  21.312 84.901 21.336 85.477 ;
     RECT  23.712 84.373 23.736 85.477 ;
     RECT  24.912 84.263 27.336 85.477 ;
     RECT  37.488 84.373 37.512 85.477 ;
     RECT  65.712 84.901 66.312 85.477 ;
     RECT  78.288 84.263 78.312 85.477 ;
     RECT  80.112 84.373 80.136 85.477 ;
     RECT  81.312 84.901 81.912 85.477 ;
     RECT  37.488 85.477 38.136 85.957 ;
     RECT  23.712 85.477 27.336 86.005 ;
     RECT  51.312 84.901 51.336 86.197 ;
     RECT  83.28 84.263 83.304 86.197 ;
     RECT  0.288 84.263 1.512 86.245 ;
     RECT  2.688 84.263 2.712 86.245 ;
     RECT  4.512 86.197 4.536 86.245 ;
     RECT  5.712 85.477 5.736 86.245 ;
     RECT  6.912 84.901 6.936 86.245 ;
     RECT  8.112 84.325 8.712 86.245 ;
     RECT  11.088 84.373 11.112 86.245 ;
     RECT  12.912 84.901 14.712 86.245 ;
     RECT  15.888 85.477 21.912 86.245 ;
     RECT  23.712 86.005 27.912 86.245 ;
     RECT  29.712 84.901 29.736 86.245 ;
     RECT  31.488 85.477 31.512 86.245 ;
     RECT  32.688 84.901 35.736 86.245 ;
     RECT  36.912 85.957 38.136 86.245 ;
     RECT  39.312 84.901 41.112 86.245 ;
     RECT  42.288 84.181 42.312 86.245 ;
     RECT  50.688 86.197 51.336 86.245 ;
     RECT  52.512 84.901 52.536 86.245 ;
     RECT  54.288 84.901 54.936 86.245 ;
     RECT  56.112 84.901 56.136 86.245 ;
     RECT  59.088 84.901 59.736 86.245 ;
     RECT  65.712 85.477 66.936 86.245 ;
     RECT  68.688 84.373 68.712 86.245 ;
     RECT  69.888 84.373 69.912 86.245 ;
     RECT  71.088 85.477 71.112 86.245 ;
     RECT  72.912 85.477 72.936 86.245 ;
     RECT  74.112 86.197 74.136 86.245 ;
     RECT  75.312 84.901 75.336 86.245 ;
     RECT  78.288 85.477 78.936 86.245 ;
     RECT  80.112 85.477 81.912 86.245 ;
     RECT  83.088 86.197 83.304 86.245 ;
     RECT  84.912 85.477 84.936 86.245 ;
     RECT  0.288 86.245 86.136 86.352 ;
     RECT  86.016 86.352 86.04 86.387 ;
     RECT  13.224 0.131 13.536 0.132 ;
     RECT  13.656 0.131 13.968 0.132 ;
     RECT  14.088 0.131 14.4 0.132 ;
     RECT  25.32 0.131 25.632 0.132 ;
     RECT  25.752 0.131 26.064 0.132 ;
     RECT  26.184 0.131 26.496 0.132 ;
     RECT  31.8 0.131 32.112 0.132 ;
     RECT  32.232 0.131 32.544 0.132 ;
     RECT  32.664 0.131 32.976 0.132 ;
     RECT  43.032 0.131 43.344 0.132 ;
     RECT  43.464 0.131 43.776 0.132 ;
     RECT  43.896 0.131 44.208 0.132 ;
     RECT  46.056 0.131 46.368 0.132 ;
     RECT  46.488 0.131 46.8 0.132 ;
     RECT  46.92 0.131 47.232 0.132 ;
     RECT  51.24 0.131 51.552 0.132 ;
     RECT  51.672 0.131 51.984 0.132 ;
     RECT  52.104 0.131 52.416 0.132 ;
     RECT  71.544 0.131 71.856 0.132 ;
     RECT  71.976 0.131 72.288 0.132 ;
     RECT  72.408 0.131 72.72 0.132 ;
     RECT  78.456 0.131 78.768 0.132 ;
     RECT  78.888 0.131 79.2 0.132 ;
     RECT  79.32 0.131 79.632 0.132 ;
     RECT  13.176 0.132 14.448 0.611 ;
     RECT  25.272 0.132 26.544 0.227 ;
     RECT  31.752 0.132 33.024 0.611 ;
     RECT  42.984 0.132 44.256 0.179 ;
     RECT  46.008 0.132 47.28 0.179 ;
     RECT  51.192 0.132 52.464 0.563 ;
     RECT  71.496 0.132 72.768 0.563 ;
     RECT  78.408 0.132 79.68 0.179 ;
     RECT  2.808 0.179 4.08 0.227 ;
     RECT  33.48 0.179 34.752 1.763 ;
     RECT  35.64 0.227 36.912 0.611 ;
     RECT  7.56 0.611 9.264 1.763 ;
     RECT  12.744 0.611 13.32 1.763 ;
     RECT  17.928 0.611 18.72 1.763 ;
     RECT  21.384 0.611 22.656 1.763 ;
     RECT  23.544 0.611 24.816 1.763 ;
     RECT  34.776 0.611 34.92 1.763 ;
     RECT  7.8 1.763 8.112 2.137 ;
     RECT  13.2 1.763 13.32 2.137 ;
     RECT  18.6 1.763 18.72 2.137 ;
     RECT  24 1.763 24.312 2.137 ;
     RECT  34.8 1.763 34.92 2.137 ;
     RECT  7.92 2.137 8.112 2.151 ;
     RECT  45.912 2.151 47.28 2.195 ;
     RECT  45.912 2.195 46.152 3.301 ;
     RECT  0.275 2.437 1.488 2.52 ;
     RECT  0.216 2.52 1.488 3.936 ;
     RECT  29.712 3.349 31.056 4.019 ;
     RECT  35.112 3.349 36.288 4.741 ;
     RECT  40.68 3.635 41.712 4.499 ;
     RECT  31.08 3.877 32.304 4.019 ;
     RECT  55.08 3.925 56.4 5.507 ;
     RECT  0.221 3.936 1.488 4.152 ;
     RECT  32.256 4.019 32.304 5.029 ;
     RECT  45.912 4.115 46.008 5.605 ;
     RECT  0.216 4.152 1.488 4.691 ;
     RECT  36.312 4.307 36.984 4.789 ;
     RECT  40.68 4.499 42.336 5.171 ;
     RECT  19.416 4.741 20.784 4.787 ;
     RECT  35.208 4.741 36.288 5.365 ;
     RECT  36.312 4.789 37.488 4.931 ;
     RECT  40.68 5.171 41.208 5.173 ;
     RECT  40.728 5.173 41.208 5.605 ;
     RECT  45.912 5.605 46.992 8.437 ;
     RECT  33.096 5.701 34.32 6.565 ;
     RECT  2.712 6.323 3.432 7.381 ;
     RECT  33.096 6.565 34.272 6.851 ;
     RECT  40.728 7.235 41.064 8.533 ;
     RECT  35.112 11.027 36.432 12.035 ;
     RECT  24.408 11.267 24.456 12.517 ;
     RECT  40.728 13.043 42.096 19.333 ;
     RECT  27.912 13.429 29.4 14.579 ;
     RECT  20.616 13.621 21.648 14.773 ;
     RECT  2.712 14.197 3.696 17.029 ;
     RECT  35.112 15.059 35.352 15.637 ;
     RECT  35.112 15.637 36.192 20.291 ;
     RECT  3.192 17.075 3.672 18.229 ;
     RECT  20.928 17.315 20.952 17.605 ;
     RECT  19.848 17.605 20.952 18.181 ;
     RECT  34.176 17.699 34.8 18.037 ;
     RECT  33.672 18.037 34.8 18.805 ;
     RECT  12.024 18.181 13.2 19.139 ;
     RECT  20.328 18.181 21.648 19.523 ;
     RECT  24.312 19.141 25.44 22.259 ;
     RECT  29.712 19.235 30.408 19.381 ;
     RECT  8.328 19.333 9.648 19.427 ;
     RECT  28.248 19.333 29.4 20.387 ;
     RECT  40.824 19.333 42.096 22.259 ;
     RECT  29.712 19.381 31.296 20.581 ;
     RECT  6.552 20.149 7.8 20.293 ;
     RECT  35.112 20.291 35.976 21.109 ;
     RECT  6.552 20.293 7.632 20.965 ;
     RECT  30.264 20.581 31.296 21.155 ;
     RECT  33.672 21.011 34.8 22.787 ;
     RECT  25.464 21.061 26.784 21.683 ;
     RECT  13.512 21.683 14.472 22.165 ;
     RECT  13.512 22.165 14.832 23.941 ;
     RECT  40.824 22.259 40.92 22.789 ;
     RECT  19.848 22.835 19.992 23.845 ;
     RECT  6.648 23.317 7.632 24.851 ;
     RECT  18.24 23.411 18.6 23.797 ;
     RECT  45.912 23.701 47.04 28.019 ;
     RECT  17.592 23.797 18.6 24.899 ;
     RECT  7.392 24.851 7.632 26.197 ;
     RECT  30.6 24.949 31.872 24.995 ;
     RECT  30.6 24.995 30.696 26.197 ;
     RECT  33.768 25.093 34.8 26.531 ;
     RECT  29.712 26.723 30.768 26.819 ;
     RECT  13.752 27.107 14.784 27.731 ;
     RECT  39.216 27.251 39.312 28.309 ;
     RECT  13.512 27.731 14.784 28.981 ;
     RECT  38.904 28.355 40.2 29.123 ;
     RECT  13.608 28.981 14.784 30.229 ;
     RECT  17.16 29.029 18.6 30.035 ;
     RECT  38.928 29.123 40.2 29.365 ;
     RECT  38.952 29.365 40.2 29.893 ;
     RECT  38.952 29.893 40.08 30.227 ;
     RECT  40.92 31.237 42.432 39.827 ;
     RECT  2.712 33.589 3.696 36.515 ;
     RECT  10.296 33.925 11.376 34.355 ;
     RECT  11.184 34.355 11.376 35.317 ;
     RECT  8.112 37.331 9.168 38.195 ;
     RECT  44.472 38.533 45.6 40.067 ;
     RECT  7.632 38.819 7.8 39.109 ;
     RECT  6.312 39.109 7.8 42.803 ;
     RECT  53.4 40.453 54.528 40.739 ;
     RECT  53.4 40.739 54.408 41.269 ;
     RECT  53.4 41.269 54.384 43.477 ;
     RECT  54.408 43.285 55.488 43.907 ;
     RECT  2.712 44.053 3.744 46.453 ;
     RECT  0.144 45.059 0.168 46.416 ;
     RECT  18.912 51.253 19.968 63.011 ;
     RECT  48.312 51.733 49.728 52.211 ;
     RECT  49.752 51.779 51 55.859 ;
     RECT  2.712 51.827 3.696 55.045 ;
     RECT  55.32 52.837 56.4 54.851 ;
     RECT  54.288 52.883 54.384 54.085 ;
     RECT  33.672 53.795 34.656 54.851 ;
     RECT  35.112 54.949 36.24 57.299 ;
     RECT  49.608 55.859 51 56.483 ;
     RECT  49.92 56.483 51 57.301 ;
     RECT  49.944 57.301 51 58.643 ;
     RECT  49.968 58.643 51 58.693 ;
     RECT  54.408 58.645 55.92 59.795 ;
     RECT  49.992 58.693 51 61.619 ;
     RECT  19.992 62.965 21.36 63.011 ;
     RECT  60.12 63.205 61.248 63.875 ;
     RECT  45.912 75.205 46.992 80.771 ;
     RECT  78.312 78.083 78.408 79.045 ;
     RECT  40.512 78.707 40.728 79.189 ;
     RECT  40.512 79.189 41.568 81.347 ;
     RECT  33.576 79.765 34.8 82.163 ;
     RECT  47.808 80.771 47.904 80.963 ;
     RECT  18.912 80.917 20.208 82.115 ;
     RECT  47.808 80.963 47.832 82.069 ;
     RECT  24.312 81.107 25.08 82.165 ;
     RECT  15.96 81.493 17.28 82.019 ;
     RECT  17.304 81.493 18.6 82.019 ;
     RECT  81.912 81.493 83.28 82.163 ;
     RECT  0.312 81.973 1.488 83.029 ;
     RECT  17.712 82.019 18.6 82.741 ;
     RECT  24.408 82.165 25.08 82.355 ;
     RECT  38.616 82.165 40.08 82.405 ;
     RECT  76.968 82.211 78 82.691 ;
     RECT  24.312 82.355 25.08 82.405 ;
     RECT  2.712 82.405 3.744 82.739 ;
     RECT  24.312 82.405 25.44 82.547 ;
     RECT  38.712 82.405 40.08 82.547 ;
     RECT  70.728 82.501 71.76 82.547 ;
     RECT  24.312 82.547 25.464 83.797 ;
     RECT  24.312 83.797 25.488 83.893 ;
     RECT  1.512 84.263 2.688 85.536 ;
     RECT  7.8 84.263 8.112 84.901 ;
     RECT  18.6 84.263 18.912 84.373 ;
     RECT  24 84.263 24.912 84.373 ;
     RECT  81.912 84.325 83.28 86.197 ;
     RECT  18.6 84.373 19.488 84.901 ;
     RECT  23.736 84.373 24.912 85.477 ;
     RECT  68.712 84.373 69.888 86.245 ;
     RECT  6.936 84.901 8.112 86.245 ;
     RECT  17.112 84.901 19.488 85.477 ;
     RECT  41.112 84.901 42.288 86.245 ;
     RECT  51.336 84.901 52.512 86.245 ;
     RECT  54.936 84.901 56.112 86.245 ;
     RECT  80.136 84.901 81.312 85.477 ;
     RECT  5.736 85.477 6.912 86.245 ;
     RECT  14.712 85.477 15.888 86.245 ;
     RECT  31.512 85.477 32.688 86.245 ;
     RECT  38.136 85.477 39.312 86.245 ;
     RECT  69.912 85.477 71.088 86.245 ;
     RECT  78.936 85.477 80.112 86.245 ;
     RECT  2.149 85.536 2.688 85.656 ;
     RECT  1.512 85.656 2.688 86.245 ;
     RECT  35.736 85.957 36.912 86.245 ;
     RECT  4.536 86.197 5.712 86.245 ;
     RECT  72.936 86.197 74.112 86.245 ;
     RECT  74.136 86.197 75.312 86.245 ;
     RECT  81.912 86.197 83.088 86.245 ;
  END
END ot_hgi_qdq_transport_ctl
END LIBRARY
